VERSION 5.8 ;
BUSBITCHARS "[]" ;
DIVIDERCHAR "/" ;
UNITS
    DATABASE MICRONS 1000 ;
END UNITS

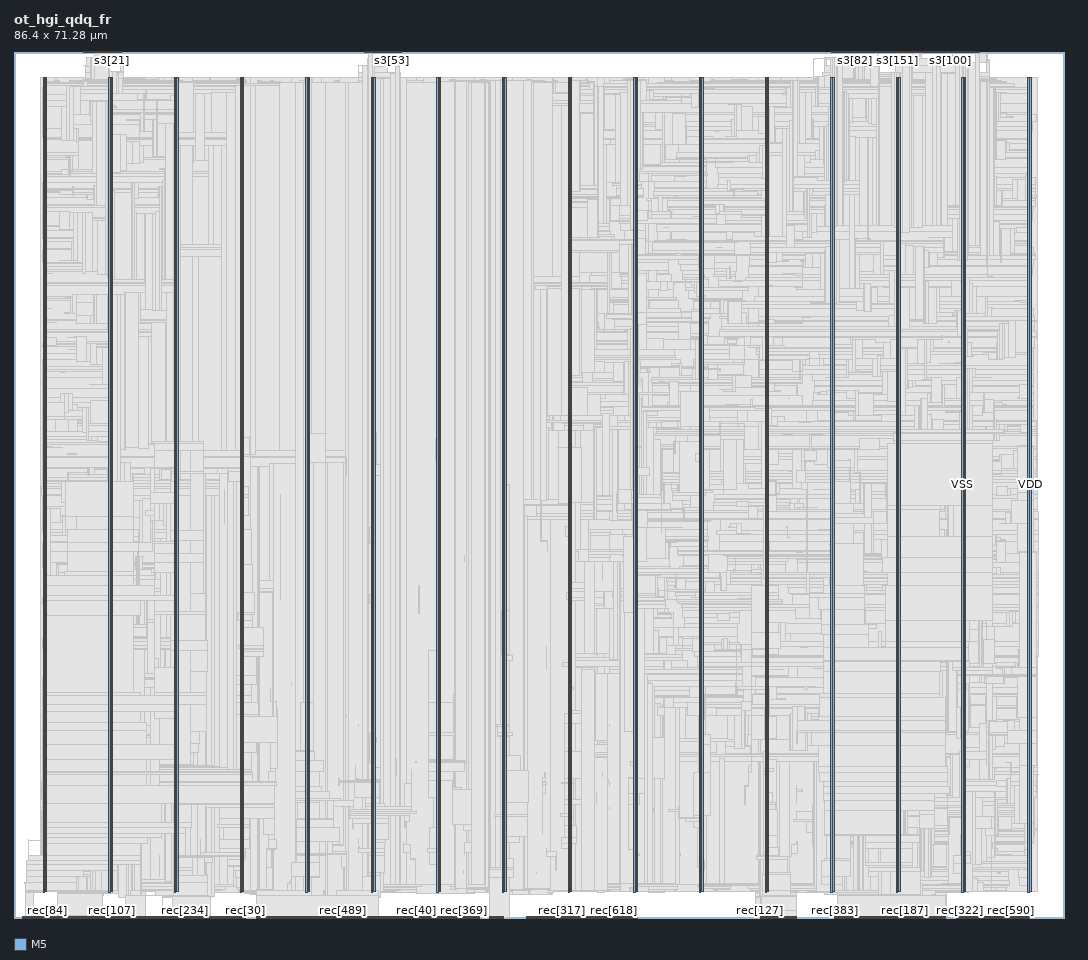
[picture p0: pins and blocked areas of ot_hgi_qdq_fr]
MACRO ot_hgi_qdq_fr
  FOREIGN ot_hgi_qdq_fr 0 0 ;
  CLASS BLOCK ;
  SIZE 86.4 BY 71.28 ;
  PIN clk
    DIRECTION INPUT ;
    USE SIGNAL ;
    PORT
      LAYER M5 ;
        RECT  16.08 0 16.104 0.084 ;
    END
  END clk
  PIN nfault
    DIRECTION OUTPUT ;
    USE SIGNAL ;
    PORT
      LAYER M5 ;
        RECT  5.808 71.196 5.832 71.28 ;
    END
  END nfault
  PIN rec[0]
    DIRECTION INPUT ;
    USE SIGNAL ;
    PORT
      LAYER M5 ;
        RECT  16.176 0 16.2 0.084 ;
    END
  END rec[0]
  PIN rec[100]
    DIRECTION INPUT ;
    USE SIGNAL ;
    PORT
      LAYER M5 ;
        RECT  7.344 0 7.368 0.084 ;
    END
  END rec[100]
  PIN rec[101]
    DIRECTION INPUT ;
    USE SIGNAL ;
    PORT
      LAYER M5 ;
        RECT  7.44 0 7.464 0.084 ;
    END
  END rec[101]
  PIN rec[102]
    DIRECTION INPUT ;
    USE SIGNAL ;
    PORT
      LAYER M5 ;
        RECT  7.536 0 7.56 0.084 ;
    END
  END rec[102]
  PIN rec[103]
    DIRECTION INPUT ;
    USE SIGNAL ;
    PORT
      LAYER M5 ;
        RECT  7.632 0 7.656 0.084 ;
    END
  END rec[103]
  PIN rec[104]
    DIRECTION INPUT ;
    USE SIGNAL ;
    PORT
      LAYER M5 ;
        RECT  7.728 0 7.752 0.084 ;
    END
  END rec[104]
  PIN rec[105]
    DIRECTION INPUT ;
    USE SIGNAL ;
    PORT
      LAYER M5 ;
        RECT  7.824 0 7.848 0.084 ;
    END
  END rec[105]
  PIN rec[106]
    DIRECTION INPUT ;
    USE SIGNAL ;
    PORT
      LAYER M5 ;
        RECT  7.92 0 7.944 0.084 ;
    END
  END rec[106]
  PIN rec[107]
    DIRECTION INPUT ;
    USE SIGNAL ;
    PORT
      LAYER M5 ;
        RECT  8.016 0 8.04 0.084 ;
    END
  END rec[107]
  PIN rec[108]
    DIRECTION INPUT ;
    USE SIGNAL ;
    PORT
      LAYER M5 ;
        RECT  8.112 0 8.136 0.084 ;
    END
  END rec[108]
  PIN rec[109]
    DIRECTION INPUT ;
    USE SIGNAL ;
    PORT
      LAYER M5 ;
        RECT  8.208 0 8.232 0.084 ;
    END
  END rec[109]
  PIN rec[10]
    DIRECTION INPUT ;
    USE SIGNAL ;
    PORT
      LAYER M5 ;
        RECT  17.136 0 17.16 0.084 ;
    END
  END rec[10]
  PIN rec[110]
    DIRECTION INPUT ;
    USE SIGNAL ;
    PORT
      LAYER M5 ;
        RECT  8.304 0 8.328 0.084 ;
    END
  END rec[110]
  PIN rec[111]
    DIRECTION INPUT ;
    USE SIGNAL ;
    PORT
      LAYER M5 ;
        RECT  8.4 0 8.424 0.084 ;
    END
  END rec[111]
  PIN rec[112]
    DIRECTION INPUT ;
    USE SIGNAL ;
    PORT
      LAYER M5 ;
        RECT  8.496 0 8.52 0.084 ;
    END
  END rec[112]
  PIN rec[113]
    DIRECTION INPUT ;
    USE SIGNAL ;
    PORT
      LAYER M5 ;
        RECT  8.592 0 8.616 0.084 ;
    END
  END rec[113]
  PIN rec[114]
    DIRECTION INPUT ;
    USE SIGNAL ;
    PORT
      LAYER M5 ;
        RECT  8.688 0 8.712 0.084 ;
    END
  END rec[114]
  PIN rec[115]
    DIRECTION INPUT ;
    USE SIGNAL ;
    PORT
      LAYER M5 ;
        RECT  8.784 0 8.808 0.084 ;
    END
  END rec[115]
  PIN rec[116]
    DIRECTION INPUT ;
    USE SIGNAL ;
    PORT
      LAYER M5 ;
        RECT  8.88 0 8.904 0.084 ;
    END
  END rec[116]
  PIN rec[117]
    DIRECTION INPUT ;
    USE SIGNAL ;
    PORT
      LAYER M5 ;
        RECT  8.976 0 9 0.084 ;
    END
  END rec[117]
  PIN rec[118]
    DIRECTION INPUT ;
    USE SIGNAL ;
    PORT
      LAYER M5 ;
        RECT  9.072 0 9.096 0.084 ;
    END
  END rec[118]
  PIN rec[119]
    DIRECTION INPUT ;
    USE SIGNAL ;
    PORT
      LAYER M5 ;
        RECT  9.168 0 9.192 0.084 ;
    END
  END rec[119]
  PIN rec[11]
    DIRECTION INPUT ;
    USE SIGNAL ;
    PORT
      LAYER M5 ;
        RECT  17.232 0 17.256 0.084 ;
    END
  END rec[11]
  PIN rec[120]
    DIRECTION INPUT ;
    USE SIGNAL ;
    PORT
      LAYER M5 ;
        RECT  9.264 0 9.288 0.084 ;
    END
  END rec[120]
  PIN rec[121]
    DIRECTION INPUT ;
    USE SIGNAL ;
    PORT
      LAYER M5 ;
        RECT  9.36 0 9.384 0.084 ;
    END
  END rec[121]
  PIN rec[122]
    DIRECTION INPUT ;
    USE SIGNAL ;
    PORT
      LAYER M5 ;
        RECT  9.456 0 9.48 0.084 ;
    END
  END rec[122]
  PIN rec[123]
    DIRECTION INPUT ;
    USE SIGNAL ;
    PORT
      LAYER M5 ;
        RECT  9.552 0 9.576 0.084 ;
    END
  END rec[123]
  PIN rec[124]
    DIRECTION INPUT ;
    USE SIGNAL ;
    PORT
      LAYER M5 ;
        RECT  9.648 0 9.672 0.084 ;
    END
  END rec[124]
  PIN rec[125]
    DIRECTION INPUT ;
    USE SIGNAL ;
    PORT
      LAYER M5 ;
        RECT  9.744 0 9.768 0.084 ;
    END
  END rec[125]
  PIN rec[126]
    DIRECTION INPUT ;
    USE SIGNAL ;
    PORT
      LAYER M5 ;
        RECT  9.84 0 9.864 0.084 ;
    END
  END rec[126]
  PIN rec[127]
    DIRECTION INPUT ;
    USE SIGNAL ;
    PORT
      LAYER M5 ;
        RECT  61.392 0 61.416 0.084 ;
    END
  END rec[127]
  PIN rec[128]
    DIRECTION INPUT ;
    USE SIGNAL ;
    PORT
      LAYER M5 ;
        RECT  61.488 0 61.512 0.084 ;
    END
  END rec[128]
  PIN rec[129]
    DIRECTION INPUT ;
    USE SIGNAL ;
    PORT
      LAYER M5 ;
        RECT  61.584 0 61.608 0.084 ;
    END
  END rec[129]
  PIN rec[12]
    DIRECTION INPUT ;
    USE SIGNAL ;
    PORT
      LAYER M5 ;
        RECT  17.328 0 17.352 0.084 ;
    END
  END rec[12]
  PIN rec[130]
    DIRECTION INPUT ;
    USE SIGNAL ;
    PORT
      LAYER M5 ;
        RECT  61.68 0 61.704 0.084 ;
    END
  END rec[130]
  PIN rec[131]
    DIRECTION INPUT ;
    USE SIGNAL ;
    PORT
      LAYER M5 ;
        RECT  61.776 0 61.8 0.084 ;
    END
  END rec[131]
  PIN rec[132]
    DIRECTION INPUT ;
    USE SIGNAL ;
    PORT
      LAYER M5 ;
        RECT  61.872 0 61.896 0.084 ;
    END
  END rec[132]
  PIN rec[133]
    DIRECTION INPUT ;
    USE SIGNAL ;
    PORT
      LAYER M5 ;
        RECT  61.968 0 61.992 0.084 ;
    END
  END rec[133]
  PIN rec[134]
    DIRECTION INPUT ;
    USE SIGNAL ;
    PORT
      LAYER M5 ;
        RECT  62.064 0 62.088 0.084 ;
    END
  END rec[134]
  PIN rec[135]
    DIRECTION INPUT ;
    USE SIGNAL ;
    PORT
      LAYER M5 ;
        RECT  62.16 0 62.184 0.084 ;
    END
  END rec[135]
  PIN rec[136]
    DIRECTION INPUT ;
    USE SIGNAL ;
    PORT
      LAYER M5 ;
        RECT  62.256 0 62.28 0.084 ;
    END
  END rec[136]
  PIN rec[137]
    DIRECTION INPUT ;
    USE SIGNAL ;
    PORT
      LAYER M5 ;
        RECT  62.352 0 62.376 0.084 ;
    END
  END rec[137]
  PIN rec[138]
    DIRECTION INPUT ;
    USE SIGNAL ;
    PORT
      LAYER M5 ;
        RECT  62.448 0 62.472 0.084 ;
    END
  END rec[138]
  PIN rec[139]
    DIRECTION INPUT ;
    USE SIGNAL ;
    PORT
      LAYER M5 ;
        RECT  62.544 0 62.568 0.084 ;
    END
  END rec[139]
  PIN rec[13]
    DIRECTION INPUT ;
    USE SIGNAL ;
    PORT
      LAYER M5 ;
        RECT  17.424 0 17.448 0.084 ;
    END
  END rec[13]
  PIN rec[140]
    DIRECTION INPUT ;
    USE SIGNAL ;
    PORT
      LAYER M5 ;
        RECT  62.64 0 62.664 0.084 ;
    END
  END rec[140]
  PIN rec[141]
    DIRECTION INPUT ;
    USE SIGNAL ;
    PORT
      LAYER M5 ;
        RECT  62.736 0 62.76 0.084 ;
    END
  END rec[141]
  PIN rec[142]
    DIRECTION INPUT ;
    USE SIGNAL ;
    PORT
      LAYER M5 ;
        RECT  62.832 0 62.856 0.084 ;
    END
  END rec[142]
  PIN rec[143]
    DIRECTION INPUT ;
    USE SIGNAL ;
    PORT
      LAYER M5 ;
        RECT  62.928 0 62.952 0.084 ;
    END
  END rec[143]
  PIN rec[144]
    DIRECTION INPUT ;
    USE SIGNAL ;
    PORT
      LAYER M5 ;
        RECT  63.024 0 63.048 0.084 ;
    END
  END rec[144]
  PIN rec[145]
    DIRECTION INPUT ;
    USE SIGNAL ;
    PORT
      LAYER M5 ;
        RECT  63.12 0 63.144 0.084 ;
    END
  END rec[145]
  PIN rec[146]
    DIRECTION INPUT ;
    USE SIGNAL ;
    PORT
      LAYER M5 ;
        RECT  63.216 0 63.24 0.084 ;
    END
  END rec[146]
  PIN rec[147]
    DIRECTION INPUT ;
    USE SIGNAL ;
    PORT
      LAYER M5 ;
        RECT  63.312 0 63.336 0.084 ;
    END
  END rec[147]
  PIN rec[148]
    DIRECTION INPUT ;
    USE SIGNAL ;
    PORT
      LAYER M5 ;
        RECT  63.408 0 63.432 0.084 ;
    END
  END rec[148]
  PIN rec[149]
    DIRECTION INPUT ;
    USE SIGNAL ;
    PORT
      LAYER M5 ;
        RECT  63.504 0 63.528 0.084 ;
    END
  END rec[149]
  PIN rec[14]
    DIRECTION INPUT ;
    USE SIGNAL ;
    PORT
      LAYER M5 ;
        RECT  17.52 0 17.544 0.084 ;
    END
  END rec[14]
  PIN rec[150]
    DIRECTION INPUT ;
    USE SIGNAL ;
    PORT
      LAYER M5 ;
        RECT  63.6 0 63.624 0.084 ;
    END
  END rec[150]
  PIN rec[151]
    DIRECTION INPUT ;
    USE SIGNAL ;
    PORT
      LAYER M5 ;
        RECT  63.696 0 63.72 0.084 ;
    END
  END rec[151]
  PIN rec[152]
    DIRECTION INPUT ;
    USE SIGNAL ;
    PORT
      LAYER M5 ;
        RECT  63.792 0 63.816 0.084 ;
    END
  END rec[152]
  PIN rec[153]
    DIRECTION INPUT ;
    USE SIGNAL ;
    PORT
      LAYER M5 ;
        RECT  63.888 0 63.912 0.084 ;
    END
  END rec[153]
  PIN rec[154]
    DIRECTION INPUT ;
    USE SIGNAL ;
    PORT
      LAYER M5 ;
        RECT  63.984 0 64.008 0.084 ;
    END
  END rec[154]
  PIN rec[155]
    DIRECTION INPUT ;
    USE SIGNAL ;
    PORT
      LAYER M5 ;
        RECT  64.08 0 64.104 0.084 ;
    END
  END rec[155]
  PIN rec[156]
    DIRECTION INPUT ;
    USE SIGNAL ;
    PORT
      LAYER M5 ;
        RECT  64.176 0 64.2 0.084 ;
    END
  END rec[156]
  PIN rec[157]
    DIRECTION INPUT ;
    USE SIGNAL ;
    PORT
      LAYER M5 ;
        RECT  64.272 0 64.296 0.084 ;
    END
  END rec[157]
  PIN rec[158]
    DIRECTION INPUT ;
    USE SIGNAL ;
    PORT
      LAYER M5 ;
        RECT  64.368 0 64.392 0.084 ;
    END
  END rec[158]
  PIN rec[159]
    DIRECTION INPUT ;
    USE SIGNAL ;
    PORT
      LAYER M5 ;
        RECT  70.608 0 70.632 0.084 ;
    END
  END rec[159]
  PIN rec[15]
    DIRECTION INPUT ;
    USE SIGNAL ;
    PORT
      LAYER M5 ;
        RECT  17.616 0 17.64 0.084 ;
    END
  END rec[15]
  PIN rec[160]
    DIRECTION INPUT ;
    USE SIGNAL ;
    PORT
      LAYER M5 ;
        RECT  70.704 0 70.728 0.084 ;
    END
  END rec[160]
  PIN rec[161]
    DIRECTION INPUT ;
    USE SIGNAL ;
    PORT
      LAYER M5 ;
        RECT  70.8 0 70.824 0.084 ;
    END
  END rec[161]
  PIN rec[162]
    DIRECTION INPUT ;
    USE SIGNAL ;
    PORT
      LAYER M5 ;
        RECT  70.896 0 70.92 0.084 ;
    END
  END rec[162]
  PIN rec[163]
    DIRECTION INPUT ;
    USE SIGNAL ;
    PORT
      LAYER M5 ;
        RECT  70.992 0 71.016 0.084 ;
    END
  END rec[163]
  PIN rec[164]
    DIRECTION INPUT ;
    USE SIGNAL ;
    PORT
      LAYER M5 ;
        RECT  71.088 0 71.112 0.084 ;
    END
  END rec[164]
  PIN rec[165]
    DIRECTION INPUT ;
    USE SIGNAL ;
    PORT
      LAYER M5 ;
        RECT  71.184 0 71.208 0.084 ;
    END
  END rec[165]
  PIN rec[166]
    DIRECTION INPUT ;
    USE SIGNAL ;
    PORT
      LAYER M5 ;
        RECT  71.28 0 71.304 0.084 ;
    END
  END rec[166]
  PIN rec[167]
    DIRECTION INPUT ;
    USE SIGNAL ;
    PORT
      LAYER M5 ;
        RECT  71.376 0 71.4 0.084 ;
    END
  END rec[167]
  PIN rec[168]
    DIRECTION INPUT ;
    USE SIGNAL ;
    PORT
      LAYER M5 ;
        RECT  71.472 0 71.496 0.084 ;
    END
  END rec[168]
  PIN rec[169]
    DIRECTION INPUT ;
    USE SIGNAL ;
    PORT
      LAYER M5 ;
        RECT  71.568 0 71.592 0.084 ;
    END
  END rec[169]
  PIN rec[16]
    DIRECTION INPUT ;
    USE SIGNAL ;
    PORT
      LAYER M5 ;
        RECT  17.712 0 17.736 0.084 ;
    END
  END rec[16]
  PIN rec[170]
    DIRECTION INPUT ;
    USE SIGNAL ;
    PORT
      LAYER M5 ;
        RECT  71.664 0 71.688 0.084 ;
    END
  END rec[170]
  PIN rec[171]
    DIRECTION INPUT ;
    USE SIGNAL ;
    PORT
      LAYER M5 ;
        RECT  71.76 0 71.784 0.084 ;
    END
  END rec[171]
  PIN rec[172]
    DIRECTION INPUT ;
    USE SIGNAL ;
    PORT
      LAYER M5 ;
        RECT  71.856 0 71.88 0.084 ;
    END
  END rec[172]
  PIN rec[173]
    DIRECTION INPUT ;
    USE SIGNAL ;
    PORT
      LAYER M5 ;
        RECT  71.952 0 71.976 0.084 ;
    END
  END rec[173]
  PIN rec[174]
    DIRECTION INPUT ;
    USE SIGNAL ;
    PORT
      LAYER M5 ;
        RECT  72.048 0 72.072 0.084 ;
    END
  END rec[174]
  PIN rec[175]
    DIRECTION INPUT ;
    USE SIGNAL ;
    PORT
      LAYER M5 ;
        RECT  72.144 0 72.168 0.084 ;
    END
  END rec[175]
  PIN rec[176]
    DIRECTION INPUT ;
    USE SIGNAL ;
    PORT
      LAYER M5 ;
        RECT  72.24 0 72.264 0.084 ;
    END
  END rec[176]
  PIN rec[177]
    DIRECTION INPUT ;
    USE SIGNAL ;
    PORT
      LAYER M5 ;
        RECT  72.336 0 72.36 0.084 ;
    END
  END rec[177]
  PIN rec[178]
    DIRECTION INPUT ;
    USE SIGNAL ;
    PORT
      LAYER M5 ;
        RECT  72.432 0 72.456 0.084 ;
    END
  END rec[178]
  PIN rec[179]
    DIRECTION INPUT ;
    USE SIGNAL ;
    PORT
      LAYER M5 ;
        RECT  72.528 0 72.552 0.084 ;
    END
  END rec[179]
  PIN rec[17]
    DIRECTION INPUT ;
    USE SIGNAL ;
    PORT
      LAYER M5 ;
        RECT  17.808 0 17.832 0.084 ;
    END
  END rec[17]
  PIN rec[180]
    DIRECTION INPUT ;
    USE SIGNAL ;
    PORT
      LAYER M5 ;
        RECT  72.624 0 72.648 0.084 ;
    END
  END rec[180]
  PIN rec[181]
    DIRECTION INPUT ;
    USE SIGNAL ;
    PORT
      LAYER M5 ;
        RECT  72.72 0 72.744 0.084 ;
    END
  END rec[181]
  PIN rec[182]
    DIRECTION INPUT ;
    USE SIGNAL ;
    PORT
      LAYER M5 ;
        RECT  72.816 0 72.84 0.084 ;
    END
  END rec[182]
  PIN rec[183]
    DIRECTION INPUT ;
    USE SIGNAL ;
    PORT
      LAYER M5 ;
        RECT  72.912 0 72.936 0.084 ;
    END
  END rec[183]
  PIN rec[184]
    DIRECTION INPUT ;
    USE SIGNAL ;
    PORT
      LAYER M5 ;
        RECT  73.008 0 73.032 0.084 ;
    END
  END rec[184]
  PIN rec[185]
    DIRECTION INPUT ;
    USE SIGNAL ;
    PORT
      LAYER M5 ;
        RECT  73.104 0 73.128 0.084 ;
    END
  END rec[185]
  PIN rec[186]
    DIRECTION INPUT ;
    USE SIGNAL ;
    PORT
      LAYER M5 ;
        RECT  73.2 0 73.224 0.084 ;
    END
  END rec[186]
  PIN rec[187]
    DIRECTION INPUT ;
    USE SIGNAL ;
    PORT
      LAYER M5 ;
        RECT  73.296 0 73.32 0.084 ;
    END
  END rec[187]
  PIN rec[188]
    DIRECTION INPUT ;
    USE SIGNAL ;
    PORT
      LAYER M5 ;
        RECT  73.392 0 73.416 0.084 ;
    END
  END rec[188]
  PIN rec[189]
    DIRECTION INPUT ;
    USE SIGNAL ;
    PORT
      LAYER M5 ;
        RECT  73.488 0 73.512 0.084 ;
    END
  END rec[189]
  PIN rec[18]
    DIRECTION INPUT ;
    USE SIGNAL ;
    PORT
      LAYER M5 ;
        RECT  17.904 0 17.928 0.084 ;
    END
  END rec[18]
  PIN rec[190]
    DIRECTION INPUT ;
    USE SIGNAL ;
    PORT
      LAYER M5 ;
        RECT  73.584 0 73.608 0.084 ;
    END
  END rec[190]
  PIN rec[191]
    DIRECTION INPUT ;
    USE SIGNAL ;
    PORT
      LAYER M5 ;
        RECT  3.792 0 3.816 0.084 ;
    END
  END rec[191]
  PIN rec[192]
    DIRECTION INPUT ;
    USE SIGNAL ;
    PORT
      LAYER M5 ;
        RECT  3.888 0 3.912 0.084 ;
    END
  END rec[192]
  PIN rec[193]
    DIRECTION INPUT ;
    USE SIGNAL ;
    PORT
      LAYER M5 ;
        RECT  3.984 0 4.008 0.084 ;
    END
  END rec[193]
  PIN rec[194]
    DIRECTION INPUT ;
    USE SIGNAL ;
    PORT
      LAYER M5 ;
        RECT  4.08 0 4.104 0.084 ;
    END
  END rec[194]
  PIN rec[195]
    DIRECTION INPUT ;
    USE SIGNAL ;
    PORT
      LAYER M5 ;
        RECT  4.176 0 4.2 0.084 ;
    END
  END rec[195]
  PIN rec[196]
    DIRECTION INPUT ;
    USE SIGNAL ;
    PORT
      LAYER M5 ;
        RECT  4.272 0 4.296 0.084 ;
    END
  END rec[196]
  PIN rec[197]
    DIRECTION INPUT ;
    USE SIGNAL ;
    PORT
      LAYER M5 ;
        RECT  4.368 0 4.392 0.084 ;
    END
  END rec[197]
  PIN rec[198]
    DIRECTION INPUT ;
    USE SIGNAL ;
    PORT
      LAYER M5 ;
        RECT  4.464 0 4.488 0.084 ;
    END
  END rec[198]
  PIN rec[199]
    DIRECTION INPUT ;
    USE SIGNAL ;
    PORT
      LAYER M5 ;
        RECT  4.56 0 4.584 0.084 ;
    END
  END rec[199]
  PIN rec[19]
    DIRECTION INPUT ;
    USE SIGNAL ;
    PORT
      LAYER M5 ;
        RECT  18 0 18.024 0.084 ;
    END
  END rec[19]
  PIN rec[1]
    DIRECTION INPUT ;
    USE SIGNAL ;
    PORT
      LAYER M5 ;
        RECT  16.272 0 16.296 0.084 ;
    END
  END rec[1]
  PIN rec[200]
    DIRECTION INPUT ;
    USE SIGNAL ;
    PORT
      LAYER M5 ;
        RECT  4.656 0 4.68 0.084 ;
    END
  END rec[200]
  PIN rec[201]
    DIRECTION INPUT ;
    USE SIGNAL ;
    PORT
      LAYER M5 ;
        RECT  4.752 0 4.776 0.084 ;
    END
  END rec[201]
  PIN rec[202]
    DIRECTION INPUT ;
    USE SIGNAL ;
    PORT
      LAYER M5 ;
        RECT  4.848 0 4.872 0.084 ;
    END
  END rec[202]
  PIN rec[203]
    DIRECTION INPUT ;
    USE SIGNAL ;
    PORT
      LAYER M5 ;
        RECT  4.944 0 4.968 0.084 ;
    END
  END rec[203]
  PIN rec[204]
    DIRECTION INPUT ;
    USE SIGNAL ;
    PORT
      LAYER M5 ;
        RECT  5.04 0 5.064 0.084 ;
    END
  END rec[204]
  PIN rec[205]
    DIRECTION INPUT ;
    USE SIGNAL ;
    PORT
      LAYER M5 ;
        RECT  5.136 0 5.16 0.084 ;
    END
  END rec[205]
  PIN rec[206]
    DIRECTION INPUT ;
    USE SIGNAL ;
    PORT
      LAYER M5 ;
        RECT  5.232 0 5.256 0.084 ;
    END
  END rec[206]
  PIN rec[207]
    DIRECTION INPUT ;
    USE SIGNAL ;
    PORT
      LAYER M5 ;
        RECT  5.328 0 5.352 0.084 ;
    END
  END rec[207]
  PIN rec[208]
    DIRECTION INPUT ;
    USE SIGNAL ;
    PORT
      LAYER M5 ;
        RECT  5.424 0 5.448 0.084 ;
    END
  END rec[208]
  PIN rec[209]
    DIRECTION INPUT ;
    USE SIGNAL ;
    PORT
      LAYER M5 ;
        RECT  5.52 0 5.544 0.084 ;
    END
  END rec[209]
  PIN rec[20]
    DIRECTION INPUT ;
    USE SIGNAL ;
    PORT
      LAYER M5 ;
        RECT  18.096 0 18.12 0.084 ;
    END
  END rec[20]
  PIN rec[210]
    DIRECTION INPUT ;
    USE SIGNAL ;
    PORT
      LAYER M5 ;
        RECT  5.616 0 5.64 0.084 ;
    END
  END rec[210]
  PIN rec[211]
    DIRECTION INPUT ;
    USE SIGNAL ;
    PORT
      LAYER M5 ;
        RECT  5.712 0 5.736 0.084 ;
    END
  END rec[211]
  PIN rec[212]
    DIRECTION INPUT ;
    USE SIGNAL ;
    PORT
      LAYER M5 ;
        RECT  5.808 0 5.832 0.084 ;
    END
  END rec[212]
  PIN rec[213]
    DIRECTION INPUT ;
    USE SIGNAL ;
    PORT
      LAYER M5 ;
        RECT  5.904 0 5.928 0.084 ;
    END
  END rec[213]
  PIN rec[214]
    DIRECTION INPUT ;
    USE SIGNAL ;
    PORT
      LAYER M5 ;
        RECT  6 0 6.024 0.084 ;
    END
  END rec[214]
  PIN rec[215]
    DIRECTION INPUT ;
    USE SIGNAL ;
    PORT
      LAYER M5 ;
        RECT  6.096 0 6.12 0.084 ;
    END
  END rec[215]
  PIN rec[216]
    DIRECTION INPUT ;
    USE SIGNAL ;
    PORT
      LAYER M5 ;
        RECT  6.192 0 6.216 0.084 ;
    END
  END rec[216]
  PIN rec[217]
    DIRECTION INPUT ;
    USE SIGNAL ;
    PORT
      LAYER M5 ;
        RECT  6.288 0 6.312 0.084 ;
    END
  END rec[217]
  PIN rec[218]
    DIRECTION INPUT ;
    USE SIGNAL ;
    PORT
      LAYER M5 ;
        RECT  6.384 0 6.408 0.084 ;
    END
  END rec[218]
  PIN rec[219]
    DIRECTION INPUT ;
    USE SIGNAL ;
    PORT
      LAYER M5 ;
        RECT  6.48 0 6.504 0.084 ;
    END
  END rec[219]
  PIN rec[21]
    DIRECTION INPUT ;
    USE SIGNAL ;
    PORT
      LAYER M5 ;
        RECT  18.192 0 18.216 0.084 ;
    END
  END rec[21]
  PIN rec[220]
    DIRECTION INPUT ;
    USE SIGNAL ;
    PORT
      LAYER M5 ;
        RECT  6.576 0 6.6 0.084 ;
    END
  END rec[220]
  PIN rec[221]
    DIRECTION INPUT ;
    USE SIGNAL ;
    PORT
      LAYER M5 ;
        RECT  6.672 0 6.696 0.084 ;
    END
  END rec[221]
  PIN rec[222]
    DIRECTION INPUT ;
    USE SIGNAL ;
    PORT
      LAYER M5 ;
        RECT  6.768 0 6.792 0.084 ;
    END
  END rec[222]
  PIN rec[223]
    DIRECTION INPUT ;
    USE SIGNAL ;
    PORT
      LAYER M5 ;
        RECT  13.008 0 13.032 0.084 ;
    END
  END rec[223]
  PIN rec[224]
    DIRECTION INPUT ;
    USE SIGNAL ;
    PORT
      LAYER M5 ;
        RECT  13.104 0 13.128 0.084 ;
    END
  END rec[224]
  PIN rec[225]
    DIRECTION INPUT ;
    USE SIGNAL ;
    PORT
      LAYER M5 ;
        RECT  13.2 0 13.224 0.084 ;
    END
  END rec[225]
  PIN rec[226]
    DIRECTION INPUT ;
    USE SIGNAL ;
    PORT
      LAYER M5 ;
        RECT  13.296 0 13.32 0.084 ;
    END
  END rec[226]
  PIN rec[227]
    DIRECTION INPUT ;
    USE SIGNAL ;
    PORT
      LAYER M5 ;
        RECT  13.392 0 13.416 0.084 ;
    END
  END rec[227]
  PIN rec[228]
    DIRECTION INPUT ;
    USE SIGNAL ;
    PORT
      LAYER M5 ;
        RECT  13.488 0 13.512 0.084 ;
    END
  END rec[228]
  PIN rec[229]
    DIRECTION INPUT ;
    USE SIGNAL ;
    PORT
      LAYER M5 ;
        RECT  13.584 0 13.608 0.084 ;
    END
  END rec[229]
  PIN rec[22]
    DIRECTION INPUT ;
    USE SIGNAL ;
    PORT
      LAYER M5 ;
        RECT  18.288 0 18.312 0.084 ;
    END
  END rec[22]
  PIN rec[230]
    DIRECTION INPUT ;
    USE SIGNAL ;
    PORT
      LAYER M5 ;
        RECT  13.68 0 13.704 0.084 ;
    END
  END rec[230]
  PIN rec[231]
    DIRECTION INPUT ;
    USE SIGNAL ;
    PORT
      LAYER M5 ;
        RECT  13.776 0 13.8 0.084 ;
    END
  END rec[231]
  PIN rec[232]
    DIRECTION INPUT ;
    USE SIGNAL ;
    PORT
      LAYER M5 ;
        RECT  13.872 0 13.896 0.084 ;
    END
  END rec[232]
  PIN rec[233]
    DIRECTION INPUT ;
    USE SIGNAL ;
    PORT
      LAYER M5 ;
        RECT  13.968 0 13.992 0.084 ;
    END
  END rec[233]
  PIN rec[234]
    DIRECTION INPUT ;
    USE SIGNAL ;
    PORT
      LAYER M5 ;
        RECT  14.064 0 14.088 0.084 ;
    END
  END rec[234]
  PIN rec[235]
    DIRECTION INPUT ;
    USE SIGNAL ;
    PORT
      LAYER M5 ;
        RECT  14.16 0 14.184 0.084 ;
    END
  END rec[235]
  PIN rec[236]
    DIRECTION INPUT ;
    USE SIGNAL ;
    PORT
      LAYER M5 ;
        RECT  14.256 0 14.28 0.084 ;
    END
  END rec[236]
  PIN rec[237]
    DIRECTION INPUT ;
    USE SIGNAL ;
    PORT
      LAYER M5 ;
        RECT  14.352 0 14.376 0.084 ;
    END
  END rec[237]
  PIN rec[238]
    DIRECTION INPUT ;
    USE SIGNAL ;
    PORT
      LAYER M5 ;
        RECT  14.448 0 14.472 0.084 ;
    END
  END rec[238]
  PIN rec[239]
    DIRECTION INPUT ;
    USE SIGNAL ;
    PORT
      LAYER M5 ;
        RECT  14.544 0 14.568 0.084 ;
    END
  END rec[239]
  PIN rec[23]
    DIRECTION INPUT ;
    USE SIGNAL ;
    PORT
      LAYER M5 ;
        RECT  18.384 0 18.408 0.084 ;
    END
  END rec[23]
  PIN rec[240]
    DIRECTION INPUT ;
    USE SIGNAL ;
    PORT
      LAYER M5 ;
        RECT  14.64 0 14.664 0.084 ;
    END
  END rec[240]
  PIN rec[241]
    DIRECTION INPUT ;
    USE SIGNAL ;
    PORT
      LAYER M5 ;
        RECT  14.736 0 14.76 0.084 ;
    END
  END rec[241]
  PIN rec[242]
    DIRECTION INPUT ;
    USE SIGNAL ;
    PORT
      LAYER M5 ;
        RECT  14.832 0 14.856 0.084 ;
    END
  END rec[242]
  PIN rec[243]
    DIRECTION INPUT ;
    USE SIGNAL ;
    PORT
      LAYER M5 ;
        RECT  14.928 0 14.952 0.084 ;
    END
  END rec[243]
  PIN rec[244]
    DIRECTION INPUT ;
    USE SIGNAL ;
    PORT
      LAYER M5 ;
        RECT  15.024 0 15.048 0.084 ;
    END
  END rec[244]
  PIN rec[245]
    DIRECTION INPUT ;
    USE SIGNAL ;
    PORT
      LAYER M5 ;
        RECT  15.12 0 15.144 0.084 ;
    END
  END rec[245]
  PIN rec[246]
    DIRECTION INPUT ;
    USE SIGNAL ;
    PORT
      LAYER M5 ;
        RECT  15.216 0 15.24 0.084 ;
    END
  END rec[246]
  PIN rec[247]
    DIRECTION INPUT ;
    USE SIGNAL ;
    PORT
      LAYER M5 ;
        RECT  15.312 0 15.336 0.084 ;
    END
  END rec[247]
  PIN rec[248]
    DIRECTION INPUT ;
    USE SIGNAL ;
    PORT
      LAYER M5 ;
        RECT  15.408 0 15.432 0.084 ;
    END
  END rec[248]
  PIN rec[249]
    DIRECTION INPUT ;
    USE SIGNAL ;
    PORT
      LAYER M5 ;
        RECT  15.504 0 15.528 0.084 ;
    END
  END rec[249]
  PIN rec[24]
    DIRECTION INPUT ;
    USE SIGNAL ;
    PORT
      LAYER M5 ;
        RECT  18.48 0 18.504 0.084 ;
    END
  END rec[24]
  PIN rec[250]
    DIRECTION INPUT ;
    USE SIGNAL ;
    PORT
      LAYER M5 ;
        RECT  15.6 0 15.624 0.084 ;
    END
  END rec[250]
  PIN rec[251]
    DIRECTION INPUT ;
    USE SIGNAL ;
    PORT
      LAYER M5 ;
        RECT  15.696 0 15.72 0.084 ;
    END
  END rec[251]
  PIN rec[252]
    DIRECTION INPUT ;
    USE SIGNAL ;
    PORT
      LAYER M5 ;
        RECT  15.792 0 15.816 0.084 ;
    END
  END rec[252]
  PIN rec[253]
    DIRECTION INPUT ;
    USE SIGNAL ;
    PORT
      LAYER M5 ;
        RECT  15.888 0 15.912 0.084 ;
    END
  END rec[253]
  PIN rec[254]
    DIRECTION INPUT ;
    USE SIGNAL ;
    PORT
      LAYER M5 ;
        RECT  15.984 0 16.008 0.084 ;
    END
  END rec[254]
  PIN rec[255]
    DIRECTION INPUT ;
    USE SIGNAL ;
    PORT
      LAYER M5 ;
        RECT  9.936 0 9.96 0.084 ;
    END
  END rec[255]
  PIN rec[256]
    DIRECTION INPUT ;
    USE SIGNAL ;
    PORT
      LAYER M5 ;
        RECT  10.032 0 10.056 0.084 ;
    END
  END rec[256]
  PIN rec[257]
    DIRECTION INPUT ;
    USE SIGNAL ;
    PORT
      LAYER M5 ;
        RECT  10.128 0 10.152 0.084 ;
    END
  END rec[257]
  PIN rec[258]
    DIRECTION INPUT ;
    USE SIGNAL ;
    PORT
      LAYER M5 ;
        RECT  10.224 0 10.248 0.084 ;
    END
  END rec[258]
  PIN rec[259]
    DIRECTION INPUT ;
    USE SIGNAL ;
    PORT
      LAYER M5 ;
        RECT  10.32 0 10.344 0.084 ;
    END
  END rec[259]
  PIN rec[25]
    DIRECTION INPUT ;
    USE SIGNAL ;
    PORT
      LAYER M5 ;
        RECT  18.576 0 18.6 0.084 ;
    END
  END rec[25]
  PIN rec[260]
    DIRECTION INPUT ;
    USE SIGNAL ;
    PORT
      LAYER M5 ;
        RECT  10.416 0 10.44 0.084 ;
    END
  END rec[260]
  PIN rec[261]
    DIRECTION INPUT ;
    USE SIGNAL ;
    PORT
      LAYER M5 ;
        RECT  10.512 0 10.536 0.084 ;
    END
  END rec[261]
  PIN rec[262]
    DIRECTION INPUT ;
    USE SIGNAL ;
    PORT
      LAYER M5 ;
        RECT  10.608 0 10.632 0.084 ;
    END
  END rec[262]
  PIN rec[263]
    DIRECTION INPUT ;
    USE SIGNAL ;
    PORT
      LAYER M5 ;
        RECT  10.704 0 10.728 0.084 ;
    END
  END rec[263]
  PIN rec[264]
    DIRECTION INPUT ;
    USE SIGNAL ;
    PORT
      LAYER M5 ;
        RECT  10.8 0 10.824 0.084 ;
    END
  END rec[264]
  PIN rec[265]
    DIRECTION INPUT ;
    USE SIGNAL ;
    PORT
      LAYER M5 ;
        RECT  10.896 0 10.92 0.084 ;
    END
  END rec[265]
  PIN rec[266]
    DIRECTION INPUT ;
    USE SIGNAL ;
    PORT
      LAYER M5 ;
        RECT  10.992 0 11.016 0.084 ;
    END
  END rec[266]
  PIN rec[267]
    DIRECTION INPUT ;
    USE SIGNAL ;
    PORT
      LAYER M5 ;
        RECT  11.088 0 11.112 0.084 ;
    END
  END rec[267]
  PIN rec[268]
    DIRECTION INPUT ;
    USE SIGNAL ;
    PORT
      LAYER M5 ;
        RECT  11.184 0 11.208 0.084 ;
    END
  END rec[268]
  PIN rec[269]
    DIRECTION INPUT ;
    USE SIGNAL ;
    PORT
      LAYER M5 ;
        RECT  11.28 0 11.304 0.084 ;
    END
  END rec[269]
  PIN rec[26]
    DIRECTION INPUT ;
    USE SIGNAL ;
    PORT
      LAYER M5 ;
        RECT  18.672 0 18.696 0.084 ;
    END
  END rec[26]
  PIN rec[270]
    DIRECTION INPUT ;
    USE SIGNAL ;
    PORT
      LAYER M5 ;
        RECT  11.376 0 11.4 0.084 ;
    END
  END rec[270]
  PIN rec[271]
    DIRECTION INPUT ;
    USE SIGNAL ;
    PORT
      LAYER M5 ;
        RECT  11.472 0 11.496 0.084 ;
    END
  END rec[271]
  PIN rec[272]
    DIRECTION INPUT ;
    USE SIGNAL ;
    PORT
      LAYER M5 ;
        RECT  11.568 0 11.592 0.084 ;
    END
  END rec[272]
  PIN rec[273]
    DIRECTION INPUT ;
    USE SIGNAL ;
    PORT
      LAYER M5 ;
        RECT  11.664 0 11.688 0.084 ;
    END
  END rec[273]
  PIN rec[274]
    DIRECTION INPUT ;
    USE SIGNAL ;
    PORT
      LAYER M5 ;
        RECT  11.76 0 11.784 0.084 ;
    END
  END rec[274]
  PIN rec[275]
    DIRECTION INPUT ;
    USE SIGNAL ;
    PORT
      LAYER M5 ;
        RECT  11.856 0 11.88 0.084 ;
    END
  END rec[275]
  PIN rec[276]
    DIRECTION INPUT ;
    USE SIGNAL ;
    PORT
      LAYER M5 ;
        RECT  11.952 0 11.976 0.084 ;
    END
  END rec[276]
  PIN rec[277]
    DIRECTION INPUT ;
    USE SIGNAL ;
    PORT
      LAYER M5 ;
        RECT  12.048 0 12.072 0.084 ;
    END
  END rec[277]
  PIN rec[278]
    DIRECTION INPUT ;
    USE SIGNAL ;
    PORT
      LAYER M5 ;
        RECT  12.144 0 12.168 0.084 ;
    END
  END rec[278]
  PIN rec[279]
    DIRECTION INPUT ;
    USE SIGNAL ;
    PORT
      LAYER M5 ;
        RECT  12.24 0 12.264 0.084 ;
    END
  END rec[279]
  PIN rec[27]
    DIRECTION INPUT ;
    USE SIGNAL ;
    PORT
      LAYER M5 ;
        RECT  18.768 0 18.792 0.084 ;
    END
  END rec[27]
  PIN rec[280]
    DIRECTION INPUT ;
    USE SIGNAL ;
    PORT
      LAYER M5 ;
        RECT  12.336 0 12.36 0.084 ;
    END
  END rec[280]
  PIN rec[281]
    DIRECTION INPUT ;
    USE SIGNAL ;
    PORT
      LAYER M5 ;
        RECT  12.432 0 12.456 0.084 ;
    END
  END rec[281]
  PIN rec[282]
    DIRECTION INPUT ;
    USE SIGNAL ;
    PORT
      LAYER M5 ;
        RECT  12.528 0 12.552 0.084 ;
    END
  END rec[282]
  PIN rec[283]
    DIRECTION INPUT ;
    USE SIGNAL ;
    PORT
      LAYER M5 ;
        RECT  12.624 0 12.648 0.084 ;
    END
  END rec[283]
  PIN rec[284]
    DIRECTION INPUT ;
    USE SIGNAL ;
    PORT
      LAYER M5 ;
        RECT  12.72 0 12.744 0.084 ;
    END
  END rec[284]
  PIN rec[285]
    DIRECTION INPUT ;
    USE SIGNAL ;
    PORT
      LAYER M5 ;
        RECT  12.816 0 12.84 0.084 ;
    END
  END rec[285]
  PIN rec[286]
    DIRECTION INPUT ;
    USE SIGNAL ;
    PORT
      LAYER M5 ;
        RECT  12.912 0 12.936 0.084 ;
    END
  END rec[286]
  PIN rec[287]
    DIRECTION INPUT ;
    USE SIGNAL ;
    PORT
      LAYER M5 ;
        RECT  42.192 0 42.216 0.084 ;
    END
  END rec[287]
  PIN rec[288]
    DIRECTION INPUT ;
    USE SIGNAL ;
    PORT
      LAYER M5 ;
        RECT  42.288 0 42.312 0.084 ;
    END
  END rec[288]
  PIN rec[289]
    DIRECTION INPUT ;
    USE SIGNAL ;
    PORT
      LAYER M5 ;
        RECT  42.384 0 42.408 0.084 ;
    END
  END rec[289]
  PIN rec[28]
    DIRECTION INPUT ;
    USE SIGNAL ;
    PORT
      LAYER M5 ;
        RECT  18.864 0 18.888 0.084 ;
    END
  END rec[28]
  PIN rec[290]
    DIRECTION INPUT ;
    USE SIGNAL ;
    PORT
      LAYER M5 ;
        RECT  42.48 0 42.504 0.084 ;
    END
  END rec[290]
  PIN rec[291]
    DIRECTION INPUT ;
    USE SIGNAL ;
    PORT
      LAYER M5 ;
        RECT  42.576 0 42.6 0.084 ;
    END
  END rec[291]
  PIN rec[292]
    DIRECTION INPUT ;
    USE SIGNAL ;
    PORT
      LAYER M5 ;
        RECT  42.672 0 42.696 0.084 ;
    END
  END rec[292]
  PIN rec[293]
    DIRECTION INPUT ;
    USE SIGNAL ;
    PORT
      LAYER M5 ;
        RECT  42.768 0 42.792 0.084 ;
    END
  END rec[293]
  PIN rec[294]
    DIRECTION INPUT ;
    USE SIGNAL ;
    PORT
      LAYER M5 ;
        RECT  42.864 0 42.888 0.084 ;
    END
  END rec[294]
  PIN rec[295]
    DIRECTION INPUT ;
    USE SIGNAL ;
    PORT
      LAYER M5 ;
        RECT  42.96 0 42.984 0.084 ;
    END
  END rec[295]
  PIN rec[296]
    DIRECTION INPUT ;
    USE SIGNAL ;
    PORT
      LAYER M5 ;
        RECT  43.056 0 43.08 0.084 ;
    END
  END rec[296]
  PIN rec[297]
    DIRECTION INPUT ;
    USE SIGNAL ;
    PORT
      LAYER M5 ;
        RECT  43.152 0 43.176 0.084 ;
    END
  END rec[297]
  PIN rec[298]
    DIRECTION INPUT ;
    USE SIGNAL ;
    PORT
      LAYER M5 ;
        RECT  43.248 0 43.272 0.084 ;
    END
  END rec[298]
  PIN rec[299]
    DIRECTION INPUT ;
    USE SIGNAL ;
    PORT
      LAYER M5 ;
        RECT  43.344 0 43.368 0.084 ;
    END
  END rec[299]
  PIN rec[29]
    DIRECTION INPUT ;
    USE SIGNAL ;
    PORT
      LAYER M5 ;
        RECT  18.96 0 18.984 0.084 ;
    END
  END rec[29]
  PIN rec[2]
    DIRECTION INPUT ;
    USE SIGNAL ;
    PORT
      LAYER M5 ;
        RECT  16.368 0 16.392 0.084 ;
    END
  END rec[2]
  PIN rec[300]
    DIRECTION INPUT ;
    USE SIGNAL ;
    PORT
      LAYER M5 ;
        RECT  43.44 0 43.464 0.084 ;
    END
  END rec[300]
  PIN rec[301]
    DIRECTION INPUT ;
    USE SIGNAL ;
    PORT
      LAYER M5 ;
        RECT  43.536 0 43.56 0.084 ;
    END
  END rec[301]
  PIN rec[302]
    DIRECTION INPUT ;
    USE SIGNAL ;
    PORT
      LAYER M5 ;
        RECT  43.632 0 43.656 0.084 ;
    END
  END rec[302]
  PIN rec[303]
    DIRECTION INPUT ;
    USE SIGNAL ;
    PORT
      LAYER M5 ;
        RECT  43.728 0 43.752 0.084 ;
    END
  END rec[303]
  PIN rec[304]
    DIRECTION INPUT ;
    USE SIGNAL ;
    PORT
      LAYER M5 ;
        RECT  43.824 0 43.848 0.084 ;
    END
  END rec[304]
  PIN rec[305]
    DIRECTION INPUT ;
    USE SIGNAL ;
    PORT
      LAYER M5 ;
        RECT  43.92 0 43.944 0.084 ;
    END
  END rec[305]
  PIN rec[306]
    DIRECTION INPUT ;
    USE SIGNAL ;
    PORT
      LAYER M5 ;
        RECT  44.016 0 44.04 0.084 ;
    END
  END rec[306]
  PIN rec[307]
    DIRECTION INPUT ;
    USE SIGNAL ;
    PORT
      LAYER M5 ;
        RECT  44.112 0 44.136 0.084 ;
    END
  END rec[307]
  PIN rec[308]
    DIRECTION INPUT ;
    USE SIGNAL ;
    PORT
      LAYER M5 ;
        RECT  44.208 0 44.232 0.084 ;
    END
  END rec[308]
  PIN rec[309]
    DIRECTION INPUT ;
    USE SIGNAL ;
    PORT
      LAYER M5 ;
        RECT  44.304 0 44.328 0.084 ;
    END
  END rec[309]
  PIN rec[30]
    DIRECTION INPUT ;
    USE SIGNAL ;
    PORT
      LAYER M5 ;
        RECT  19.056 0 19.08 0.084 ;
    END
  END rec[30]
  PIN rec[310]
    DIRECTION INPUT ;
    USE SIGNAL ;
    PORT
      LAYER M5 ;
        RECT  44.4 0 44.424 0.084 ;
    END
  END rec[310]
  PIN rec[311]
    DIRECTION INPUT ;
    USE SIGNAL ;
    PORT
      LAYER M5 ;
        RECT  44.496 0 44.52 0.084 ;
    END
  END rec[311]
  PIN rec[312]
    DIRECTION INPUT ;
    USE SIGNAL ;
    PORT
      LAYER M5 ;
        RECT  44.592 0 44.616 0.084 ;
    END
  END rec[312]
  PIN rec[313]
    DIRECTION INPUT ;
    USE SIGNAL ;
    PORT
      LAYER M5 ;
        RECT  44.688 0 44.712 0.084 ;
    END
  END rec[313]
  PIN rec[314]
    DIRECTION INPUT ;
    USE SIGNAL ;
    PORT
      LAYER M5 ;
        RECT  44.784 0 44.808 0.084 ;
    END
  END rec[314]
  PIN rec[315]
    DIRECTION INPUT ;
    USE SIGNAL ;
    PORT
      LAYER M5 ;
        RECT  44.88 0 44.904 0.084 ;
    END
  END rec[315]
  PIN rec[316]
    DIRECTION INPUT ;
    USE SIGNAL ;
    PORT
      LAYER M5 ;
        RECT  44.976 0 45 0.084 ;
    END
  END rec[316]
  PIN rec[317]
    DIRECTION INPUT ;
    USE SIGNAL ;
    PORT
      LAYER M5 ;
        RECT  45.072 0 45.096 0.084 ;
    END
  END rec[317]
  PIN rec[318]
    DIRECTION INPUT ;
    USE SIGNAL ;
    PORT
      LAYER M5 ;
        RECT  45.168 0 45.192 0.084 ;
    END
  END rec[318]
  PIN rec[319]
    DIRECTION INPUT ;
    USE SIGNAL ;
    PORT
      LAYER M5 ;
        RECT  77.52 0 77.544 0.084 ;
    END
  END rec[319]
  PIN rec[31]
    DIRECTION INPUT ;
    USE SIGNAL ;
    PORT
      LAYER M5 ;
        RECT  32.208 0 32.232 0.084 ;
    END
  END rec[31]
  PIN rec[320]
    DIRECTION INPUT ;
    USE SIGNAL ;
    PORT
      LAYER M5 ;
        RECT  77.616 0 77.64 0.084 ;
    END
  END rec[320]
  PIN rec[321]
    DIRECTION INPUT ;
    USE SIGNAL ;
    PORT
      LAYER M5 ;
        RECT  77.712 0 77.736 0.084 ;
    END
  END rec[321]
  PIN rec[322]
    DIRECTION INPUT ;
    USE SIGNAL ;
    PORT
      LAYER M5 ;
        RECT  77.808 0 77.832 0.084 ;
    END
  END rec[322]
  PIN rec[323]
    DIRECTION INPUT ;
    USE SIGNAL ;
    PORT
      LAYER M5 ;
        RECT  77.904 0 77.928 0.084 ;
    END
  END rec[323]
  PIN rec[324]
    DIRECTION INPUT ;
    USE SIGNAL ;
    PORT
      LAYER M5 ;
        RECT  78 0 78.024 0.084 ;
    END
  END rec[324]
  PIN rec[325]
    DIRECTION INPUT ;
    USE SIGNAL ;
    PORT
      LAYER M5 ;
        RECT  78.096 0 78.12 0.084 ;
    END
  END rec[325]
  PIN rec[326]
    DIRECTION INPUT ;
    USE SIGNAL ;
    PORT
      LAYER M5 ;
        RECT  78.192 0 78.216 0.084 ;
    END
  END rec[326]
  PIN rec[327]
    DIRECTION INPUT ;
    USE SIGNAL ;
    PORT
      LAYER M5 ;
        RECT  78.288 0 78.312 0.084 ;
    END
  END rec[327]
  PIN rec[328]
    DIRECTION INPUT ;
    USE SIGNAL ;
    PORT
      LAYER M5 ;
        RECT  78.384 0 78.408 0.084 ;
    END
  END rec[328]
  PIN rec[329]
    DIRECTION INPUT ;
    USE SIGNAL ;
    PORT
      LAYER M5 ;
        RECT  78.48 0 78.504 0.084 ;
    END
  END rec[329]
  PIN rec[32]
    DIRECTION INPUT ;
    USE SIGNAL ;
    PORT
      LAYER M5 ;
        RECT  32.304 0 32.328 0.084 ;
    END
  END rec[32]
  PIN rec[330]
    DIRECTION INPUT ;
    USE SIGNAL ;
    PORT
      LAYER M5 ;
        RECT  78.576 0 78.6 0.084 ;
    END
  END rec[330]
  PIN rec[331]
    DIRECTION INPUT ;
    USE SIGNAL ;
    PORT
      LAYER M5 ;
        RECT  78.672 0 78.696 0.084 ;
    END
  END rec[331]
  PIN rec[332]
    DIRECTION INPUT ;
    USE SIGNAL ;
    PORT
      LAYER M5 ;
        RECT  78.768 0 78.792 0.084 ;
    END
  END rec[332]
  PIN rec[333]
    DIRECTION INPUT ;
    USE SIGNAL ;
    PORT
      LAYER M5 ;
        RECT  78.864 0 78.888 0.084 ;
    END
  END rec[333]
  PIN rec[334]
    DIRECTION INPUT ;
    USE SIGNAL ;
    PORT
      LAYER M5 ;
        RECT  78.96 0 78.984 0.084 ;
    END
  END rec[334]
  PIN rec[335]
    DIRECTION INPUT ;
    USE SIGNAL ;
    PORT
      LAYER M5 ;
        RECT  79.056 0 79.08 0.084 ;
    END
  END rec[335]
  PIN rec[336]
    DIRECTION INPUT ;
    USE SIGNAL ;
    PORT
      LAYER M5 ;
        RECT  79.152 0 79.176 0.084 ;
    END
  END rec[336]
  PIN rec[337]
    DIRECTION INPUT ;
    USE SIGNAL ;
    PORT
      LAYER M5 ;
        RECT  79.248 0 79.272 0.084 ;
    END
  END rec[337]
  PIN rec[338]
    DIRECTION INPUT ;
    USE SIGNAL ;
    PORT
      LAYER M5 ;
        RECT  79.344 0 79.368 0.084 ;
    END
  END rec[338]
  PIN rec[339]
    DIRECTION INPUT ;
    USE SIGNAL ;
    PORT
      LAYER M5 ;
        RECT  79.44 0 79.464 0.084 ;
    END
  END rec[339]
  PIN rec[33]
    DIRECTION INPUT ;
    USE SIGNAL ;
    PORT
      LAYER M5 ;
        RECT  32.4 0 32.424 0.084 ;
    END
  END rec[33]
  PIN rec[340]
    DIRECTION INPUT ;
    USE SIGNAL ;
    PORT
      LAYER M5 ;
        RECT  79.536 0 79.56 0.084 ;
    END
  END rec[340]
  PIN rec[341]
    DIRECTION INPUT ;
    USE SIGNAL ;
    PORT
      LAYER M5 ;
        RECT  79.632 0 79.656 0.084 ;
    END
  END rec[341]
  PIN rec[342]
    DIRECTION INPUT ;
    USE SIGNAL ;
    PORT
      LAYER M5 ;
        RECT  79.728 0 79.752 0.084 ;
    END
  END rec[342]
  PIN rec[343]
    DIRECTION INPUT ;
    USE SIGNAL ;
    PORT
      LAYER M5 ;
        RECT  79.824 0 79.848 0.084 ;
    END
  END rec[343]
  PIN rec[344]
    DIRECTION INPUT ;
    USE SIGNAL ;
    PORT
      LAYER M5 ;
        RECT  79.92 0 79.944 0.084 ;
    END
  END rec[344]
  PIN rec[345]
    DIRECTION INPUT ;
    USE SIGNAL ;
    PORT
      LAYER M5 ;
        RECT  80.016 0 80.04 0.084 ;
    END
  END rec[345]
  PIN rec[346]
    DIRECTION INPUT ;
    USE SIGNAL ;
    PORT
      LAYER M5 ;
        RECT  80.112 0 80.136 0.084 ;
    END
  END rec[346]
  PIN rec[347]
    DIRECTION INPUT ;
    USE SIGNAL ;
    PORT
      LAYER M5 ;
        RECT  80.208 0 80.232 0.084 ;
    END
  END rec[347]
  PIN rec[348]
    DIRECTION INPUT ;
    USE SIGNAL ;
    PORT
      LAYER M5 ;
        RECT  80.304 0 80.328 0.084 ;
    END
  END rec[348]
  PIN rec[349]
    DIRECTION INPUT ;
    USE SIGNAL ;
    PORT
      LAYER M5 ;
        RECT  80.4 0 80.424 0.084 ;
    END
  END rec[349]
  PIN rec[34]
    DIRECTION INPUT ;
    USE SIGNAL ;
    PORT
      LAYER M5 ;
        RECT  32.496 0 32.52 0.084 ;
    END
  END rec[34]
  PIN rec[350]
    DIRECTION INPUT ;
    USE SIGNAL ;
    PORT
      LAYER M5 ;
        RECT  80.496 0 80.52 0.084 ;
    END
  END rec[350]
  PIN rec[351]
    DIRECTION INPUT ;
    USE SIGNAL ;
    PORT
      LAYER M5 ;
        RECT  35.28 0 35.304 0.084 ;
    END
  END rec[351]
  PIN rec[352]
    DIRECTION INPUT ;
    USE SIGNAL ;
    PORT
      LAYER M5 ;
        RECT  35.376 0 35.4 0.084 ;
    END
  END rec[352]
  PIN rec[353]
    DIRECTION INPUT ;
    USE SIGNAL ;
    PORT
      LAYER M5 ;
        RECT  35.472 0 35.496 0.084 ;
    END
  END rec[353]
  PIN rec[354]
    DIRECTION INPUT ;
    USE SIGNAL ;
    PORT
      LAYER M5 ;
        RECT  35.568 0 35.592 0.084 ;
    END
  END rec[354]
  PIN rec[355]
    DIRECTION INPUT ;
    USE SIGNAL ;
    PORT
      LAYER M5 ;
        RECT  35.664 0 35.688 0.084 ;
    END
  END rec[355]
  PIN rec[356]
    DIRECTION INPUT ;
    USE SIGNAL ;
    PORT
      LAYER M5 ;
        RECT  35.76 0 35.784 0.084 ;
    END
  END rec[356]
  PIN rec[357]
    DIRECTION INPUT ;
    USE SIGNAL ;
    PORT
      LAYER M5 ;
        RECT  35.856 0 35.88 0.084 ;
    END
  END rec[357]
  PIN rec[358]
    DIRECTION INPUT ;
    USE SIGNAL ;
    PORT
      LAYER M5 ;
        RECT  35.952 0 35.976 0.084 ;
    END
  END rec[358]
  PIN rec[359]
    DIRECTION INPUT ;
    USE SIGNAL ;
    PORT
      LAYER M5 ;
        RECT  36.048 0 36.072 0.084 ;
    END
  END rec[359]
  PIN rec[35]
    DIRECTION INPUT ;
    USE SIGNAL ;
    PORT
      LAYER M5 ;
        RECT  32.592 0 32.616 0.084 ;
    END
  END rec[35]
  PIN rec[360]
    DIRECTION INPUT ;
    USE SIGNAL ;
    PORT
      LAYER M5 ;
        RECT  36.144 0 36.168 0.084 ;
    END
  END rec[360]
  PIN rec[361]
    DIRECTION INPUT ;
    USE SIGNAL ;
    PORT
      LAYER M5 ;
        RECT  36.24 0 36.264 0.084 ;
    END
  END rec[361]
  PIN rec[362]
    DIRECTION INPUT ;
    USE SIGNAL ;
    PORT
      LAYER M5 ;
        RECT  36.336 0 36.36 0.084 ;
    END
  END rec[362]
  PIN rec[363]
    DIRECTION INPUT ;
    USE SIGNAL ;
    PORT
      LAYER M5 ;
        RECT  36.432 0 36.456 0.084 ;
    END
  END rec[363]
  PIN rec[364]
    DIRECTION INPUT ;
    USE SIGNAL ;
    PORT
      LAYER M5 ;
        RECT  36.528 0 36.552 0.084 ;
    END
  END rec[364]
  PIN rec[365]
    DIRECTION INPUT ;
    USE SIGNAL ;
    PORT
      LAYER M5 ;
        RECT  36.624 0 36.648 0.084 ;
    END
  END rec[365]
  PIN rec[366]
    DIRECTION INPUT ;
    USE SIGNAL ;
    PORT
      LAYER M5 ;
        RECT  36.72 0 36.744 0.084 ;
    END
  END rec[366]
  PIN rec[367]
    DIRECTION INPUT ;
    USE SIGNAL ;
    PORT
      LAYER M5 ;
        RECT  36.816 0 36.84 0.084 ;
    END
  END rec[367]
  PIN rec[368]
    DIRECTION INPUT ;
    USE SIGNAL ;
    PORT
      LAYER M5 ;
        RECT  36.912 0 36.936 0.084 ;
    END
  END rec[368]
  PIN rec[369]
    DIRECTION INPUT ;
    USE SIGNAL ;
    PORT
      LAYER M5 ;
        RECT  37.008 0 37.032 0.084 ;
    END
  END rec[369]
  PIN rec[36]
    DIRECTION INPUT ;
    USE SIGNAL ;
    PORT
      LAYER M5 ;
        RECT  32.688 0 32.712 0.084 ;
    END
  END rec[36]
  PIN rec[370]
    DIRECTION INPUT ;
    USE SIGNAL ;
    PORT
      LAYER M5 ;
        RECT  37.104 0 37.128 0.084 ;
    END
  END rec[370]
  PIN rec[371]
    DIRECTION INPUT ;
    USE SIGNAL ;
    PORT
      LAYER M5 ;
        RECT  37.2 0 37.224 0.084 ;
    END
  END rec[371]
  PIN rec[372]
    DIRECTION INPUT ;
    USE SIGNAL ;
    PORT
      LAYER M5 ;
        RECT  37.296 0 37.32 0.084 ;
    END
  END rec[372]
  PIN rec[373]
    DIRECTION INPUT ;
    USE SIGNAL ;
    PORT
      LAYER M5 ;
        RECT  37.392 0 37.416 0.084 ;
    END
  END rec[373]
  PIN rec[374]
    DIRECTION INPUT ;
    USE SIGNAL ;
    PORT
      LAYER M5 ;
        RECT  37.488 0 37.512 0.084 ;
    END
  END rec[374]
  PIN rec[375]
    DIRECTION INPUT ;
    USE SIGNAL ;
    PORT
      LAYER M5 ;
        RECT  37.584 0 37.608 0.084 ;
    END
  END rec[375]
  PIN rec[376]
    DIRECTION INPUT ;
    USE SIGNAL ;
    PORT
      LAYER M5 ;
        RECT  37.68 0 37.704 0.084 ;
    END
  END rec[376]
  PIN rec[377]
    DIRECTION INPUT ;
    USE SIGNAL ;
    PORT
      LAYER M5 ;
        RECT  37.776 0 37.8 0.084 ;
    END
  END rec[377]
  PIN rec[378]
    DIRECTION INPUT ;
    USE SIGNAL ;
    PORT
      LAYER M5 ;
        RECT  37.872 0 37.896 0.084 ;
    END
  END rec[378]
  PIN rec[379]
    DIRECTION INPUT ;
    USE SIGNAL ;
    PORT
      LAYER M5 ;
        RECT  37.968 0 37.992 0.084 ;
    END
  END rec[379]
  PIN rec[37]
    DIRECTION INPUT ;
    USE SIGNAL ;
    PORT
      LAYER M5 ;
        RECT  32.784 0 32.808 0.084 ;
    END
  END rec[37]
  PIN rec[380]
    DIRECTION INPUT ;
    USE SIGNAL ;
    PORT
      LAYER M5 ;
        RECT  38.064 0 38.088 0.084 ;
    END
  END rec[380]
  PIN rec[381]
    DIRECTION INPUT ;
    USE SIGNAL ;
    PORT
      LAYER M5 ;
        RECT  38.16 0 38.184 0.084 ;
    END
  END rec[381]
  PIN rec[382]
    DIRECTION INPUT ;
    USE SIGNAL ;
    PORT
      LAYER M5 ;
        RECT  38.256 0 38.28 0.084 ;
    END
  END rec[382]
  PIN rec[383]
    DIRECTION INPUT ;
    USE SIGNAL ;
    PORT
      LAYER M5 ;
        RECT  67.536 0 67.56 0.084 ;
    END
  END rec[383]
  PIN rec[384]
    DIRECTION INPUT ;
    USE SIGNAL ;
    PORT
      LAYER M5 ;
        RECT  67.632 0 67.656 0.084 ;
    END
  END rec[384]
  PIN rec[385]
    DIRECTION INPUT ;
    USE SIGNAL ;
    PORT
      LAYER M5 ;
        RECT  67.728 0 67.752 0.084 ;
    END
  END rec[385]
  PIN rec[386]
    DIRECTION INPUT ;
    USE SIGNAL ;
    PORT
      LAYER M5 ;
        RECT  67.824 0 67.848 0.084 ;
    END
  END rec[386]
  PIN rec[387]
    DIRECTION INPUT ;
    USE SIGNAL ;
    PORT
      LAYER M5 ;
        RECT  67.92 0 67.944 0.084 ;
    END
  END rec[387]
  PIN rec[388]
    DIRECTION INPUT ;
    USE SIGNAL ;
    PORT
      LAYER M5 ;
        RECT  68.016 0 68.04 0.084 ;
    END
  END rec[388]
  PIN rec[389]
    DIRECTION INPUT ;
    USE SIGNAL ;
    PORT
      LAYER M5 ;
        RECT  68.112 0 68.136 0.084 ;
    END
  END rec[389]
  PIN rec[38]
    DIRECTION INPUT ;
    USE SIGNAL ;
    PORT
      LAYER M5 ;
        RECT  32.88 0 32.904 0.084 ;
    END
  END rec[38]
  PIN rec[390]
    DIRECTION INPUT ;
    USE SIGNAL ;
    PORT
      LAYER M5 ;
        RECT  68.208 0 68.232 0.084 ;
    END
  END rec[390]
  PIN rec[391]
    DIRECTION INPUT ;
    USE SIGNAL ;
    PORT
      LAYER M5 ;
        RECT  68.304 0 68.328 0.084 ;
    END
  END rec[391]
  PIN rec[392]
    DIRECTION INPUT ;
    USE SIGNAL ;
    PORT
      LAYER M5 ;
        RECT  68.4 0 68.424 0.084 ;
    END
  END rec[392]
  PIN rec[393]
    DIRECTION INPUT ;
    USE SIGNAL ;
    PORT
      LAYER M5 ;
        RECT  68.496 0 68.52 0.084 ;
    END
  END rec[393]
  PIN rec[394]
    DIRECTION INPUT ;
    USE SIGNAL ;
    PORT
      LAYER M5 ;
        RECT  68.592 0 68.616 0.084 ;
    END
  END rec[394]
  PIN rec[395]
    DIRECTION INPUT ;
    USE SIGNAL ;
    PORT
      LAYER M5 ;
        RECT  68.688 0 68.712 0.084 ;
    END
  END rec[395]
  PIN rec[396]
    DIRECTION INPUT ;
    USE SIGNAL ;
    PORT
      LAYER M5 ;
        RECT  68.784 0 68.808 0.084 ;
    END
  END rec[396]
  PIN rec[397]
    DIRECTION INPUT ;
    USE SIGNAL ;
    PORT
      LAYER M5 ;
        RECT  68.88 0 68.904 0.084 ;
    END
  END rec[397]
  PIN rec[398]
    DIRECTION INPUT ;
    USE SIGNAL ;
    PORT
      LAYER M5 ;
        RECT  68.976 0 69 0.084 ;
    END
  END rec[398]
  PIN rec[399]
    DIRECTION INPUT ;
    USE SIGNAL ;
    PORT
      LAYER M5 ;
        RECT  69.072 0 69.096 0.084 ;
    END
  END rec[399]
  PIN rec[39]
    DIRECTION INPUT ;
    USE SIGNAL ;
    PORT
      LAYER M5 ;
        RECT  32.976 0 33 0.084 ;
    END
  END rec[39]
  PIN rec[3]
    DIRECTION INPUT ;
    USE SIGNAL ;
    PORT
      LAYER M5 ;
        RECT  16.464 0 16.488 0.084 ;
    END
  END rec[3]
  PIN rec[400]
    DIRECTION INPUT ;
    USE SIGNAL ;
    PORT
      LAYER M5 ;
        RECT  69.168 0 69.192 0.084 ;
    END
  END rec[400]
  PIN rec[401]
    DIRECTION INPUT ;
    USE SIGNAL ;
    PORT
      LAYER M5 ;
        RECT  69.264 0 69.288 0.084 ;
    END
  END rec[401]
  PIN rec[402]
    DIRECTION INPUT ;
    USE SIGNAL ;
    PORT
      LAYER M5 ;
        RECT  69.36 0 69.384 0.084 ;
    END
  END rec[402]
  PIN rec[403]
    DIRECTION INPUT ;
    USE SIGNAL ;
    PORT
      LAYER M5 ;
        RECT  69.456 0 69.48 0.084 ;
    END
  END rec[403]
  PIN rec[404]
    DIRECTION INPUT ;
    USE SIGNAL ;
    PORT
      LAYER M5 ;
        RECT  69.552 0 69.576 0.084 ;
    END
  END rec[404]
  PIN rec[405]
    DIRECTION INPUT ;
    USE SIGNAL ;
    PORT
      LAYER M5 ;
        RECT  69.648 0 69.672 0.084 ;
    END
  END rec[405]
  PIN rec[406]
    DIRECTION INPUT ;
    USE SIGNAL ;
    PORT
      LAYER M5 ;
        RECT  69.744 0 69.768 0.084 ;
    END
  END rec[406]
  PIN rec[407]
    DIRECTION INPUT ;
    USE SIGNAL ;
    PORT
      LAYER M5 ;
        RECT  69.84 0 69.864 0.084 ;
    END
  END rec[407]
  PIN rec[408]
    DIRECTION INPUT ;
    USE SIGNAL ;
    PORT
      LAYER M5 ;
        RECT  69.936 0 69.96 0.084 ;
    END
  END rec[408]
  PIN rec[409]
    DIRECTION INPUT ;
    USE SIGNAL ;
    PORT
      LAYER M5 ;
        RECT  70.032 0 70.056 0.084 ;
    END
  END rec[409]
  PIN rec[40]
    DIRECTION INPUT ;
    USE SIGNAL ;
    PORT
      LAYER M5 ;
        RECT  33.072 0 33.096 0.084 ;
    END
  END rec[40]
  PIN rec[410]
    DIRECTION INPUT ;
    USE SIGNAL ;
    PORT
      LAYER M5 ;
        RECT  70.128 0 70.152 0.084 ;
    END
  END rec[410]
  PIN rec[411]
    DIRECTION INPUT ;
    USE SIGNAL ;
    PORT
      LAYER M5 ;
        RECT  70.224 0 70.248 0.084 ;
    END
  END rec[411]
  PIN rec[412]
    DIRECTION INPUT ;
    USE SIGNAL ;
    PORT
      LAYER M5 ;
        RECT  70.32 0 70.344 0.084 ;
    END
  END rec[412]
  PIN rec[413]
    DIRECTION INPUT ;
    USE SIGNAL ;
    PORT
      LAYER M5 ;
        RECT  70.416 0 70.44 0.084 ;
    END
  END rec[413]
  PIN rec[414]
    DIRECTION INPUT ;
    USE SIGNAL ;
    PORT
      LAYER M5 ;
        RECT  70.512 0 70.536 0.084 ;
    END
  END rec[414]
  PIN rec[415]
    DIRECTION INPUT ;
    USE SIGNAL ;
    PORT
      LAYER M5 ;
        RECT  73.68 0 73.704 0.084 ;
    END
  END rec[415]
  PIN rec[416]
    DIRECTION INPUT ;
    USE SIGNAL ;
    PORT
      LAYER M5 ;
        RECT  73.776 0 73.8 0.084 ;
    END
  END rec[416]
  PIN rec[417]
    DIRECTION INPUT ;
    USE SIGNAL ;
    PORT
      LAYER M5 ;
        RECT  73.872 0 73.896 0.084 ;
    END
  END rec[417]
  PIN rec[418]
    DIRECTION INPUT ;
    USE SIGNAL ;
    PORT
      LAYER M5 ;
        RECT  73.968 0 73.992 0.084 ;
    END
  END rec[418]
  PIN rec[419]
    DIRECTION INPUT ;
    USE SIGNAL ;
    PORT
      LAYER M5 ;
        RECT  74.064 0 74.088 0.084 ;
    END
  END rec[419]
  PIN rec[41]
    DIRECTION INPUT ;
    USE SIGNAL ;
    PORT
      LAYER M5 ;
        RECT  33.168 0 33.192 0.084 ;
    END
  END rec[41]
  PIN rec[420]
    DIRECTION INPUT ;
    USE SIGNAL ;
    PORT
      LAYER M5 ;
        RECT  74.16 0 74.184 0.084 ;
    END
  END rec[420]
  PIN rec[421]
    DIRECTION INPUT ;
    USE SIGNAL ;
    PORT
      LAYER M5 ;
        RECT  74.256 0 74.28 0.084 ;
    END
  END rec[421]
  PIN rec[422]
    DIRECTION INPUT ;
    USE SIGNAL ;
    PORT
      LAYER M5 ;
        RECT  74.352 0 74.376 0.084 ;
    END
  END rec[422]
  PIN rec[423]
    DIRECTION INPUT ;
    USE SIGNAL ;
    PORT
      LAYER M5 ;
        RECT  74.448 0 74.472 0.084 ;
    END
  END rec[423]
  PIN rec[424]
    DIRECTION INPUT ;
    USE SIGNAL ;
    PORT
      LAYER M5 ;
        RECT  74.544 0 74.568 0.084 ;
    END
  END rec[424]
  PIN rec[425]
    DIRECTION INPUT ;
    USE SIGNAL ;
    PORT
      LAYER M5 ;
        RECT  74.64 0 74.664 0.084 ;
    END
  END rec[425]
  PIN rec[426]
    DIRECTION INPUT ;
    USE SIGNAL ;
    PORT
      LAYER M5 ;
        RECT  74.736 0 74.76 0.084 ;
    END
  END rec[426]
  PIN rec[427]
    DIRECTION INPUT ;
    USE SIGNAL ;
    PORT
      LAYER M5 ;
        RECT  74.832 0 74.856 0.084 ;
    END
  END rec[427]
  PIN rec[428]
    DIRECTION INPUT ;
    USE SIGNAL ;
    PORT
      LAYER M5 ;
        RECT  74.928 0 74.952 0.084 ;
    END
  END rec[428]
  PIN rec[429]
    DIRECTION INPUT ;
    USE SIGNAL ;
    PORT
      LAYER M5 ;
        RECT  75.024 0 75.048 0.084 ;
    END
  END rec[429]
  PIN rec[42]
    DIRECTION INPUT ;
    USE SIGNAL ;
    PORT
      LAYER M5 ;
        RECT  33.264 0 33.288 0.084 ;
    END
  END rec[42]
  PIN rec[430]
    DIRECTION INPUT ;
    USE SIGNAL ;
    PORT
      LAYER M5 ;
        RECT  75.12 0 75.144 0.084 ;
    END
  END rec[430]
  PIN rec[431]
    DIRECTION INPUT ;
    USE SIGNAL ;
    PORT
      LAYER M5 ;
        RECT  75.216 0 75.24 0.084 ;
    END
  END rec[431]
  PIN rec[432]
    DIRECTION INPUT ;
    USE SIGNAL ;
    PORT
      LAYER M5 ;
        RECT  75.312 0 75.336 0.084 ;
    END
  END rec[432]
  PIN rec[433]
    DIRECTION INPUT ;
    USE SIGNAL ;
    PORT
      LAYER M5 ;
        RECT  75.408 0 75.432 0.084 ;
    END
  END rec[433]
  PIN rec[434]
    DIRECTION INPUT ;
    USE SIGNAL ;
    PORT
      LAYER M5 ;
        RECT  75.504 0 75.528 0.084 ;
    END
  END rec[434]
  PIN rec[435]
    DIRECTION INPUT ;
    USE SIGNAL ;
    PORT
      LAYER M5 ;
        RECT  75.6 0 75.624 0.084 ;
    END
  END rec[435]
  PIN rec[436]
    DIRECTION INPUT ;
    USE SIGNAL ;
    PORT
      LAYER M5 ;
        RECT  75.696 0 75.72 0.084 ;
    END
  END rec[436]
  PIN rec[437]
    DIRECTION INPUT ;
    USE SIGNAL ;
    PORT
      LAYER M5 ;
        RECT  75.792 0 75.816 0.084 ;
    END
  END rec[437]
  PIN rec[438]
    DIRECTION INPUT ;
    USE SIGNAL ;
    PORT
      LAYER M5 ;
        RECT  75.888 0 75.912 0.084 ;
    END
  END rec[438]
  PIN rec[439]
    DIRECTION INPUT ;
    USE SIGNAL ;
    PORT
      LAYER M5 ;
        RECT  75.984 0 76.008 0.084 ;
    END
  END rec[439]
  PIN rec[43]
    DIRECTION INPUT ;
    USE SIGNAL ;
    PORT
      LAYER M5 ;
        RECT  33.36 0 33.384 0.084 ;
    END
  END rec[43]
  PIN rec[440]
    DIRECTION INPUT ;
    USE SIGNAL ;
    PORT
      LAYER M5 ;
        RECT  76.08 0 76.104 0.084 ;
    END
  END rec[440]
  PIN rec[441]
    DIRECTION INPUT ;
    USE SIGNAL ;
    PORT
      LAYER M5 ;
        RECT  76.176 0 76.2 0.084 ;
    END
  END rec[441]
  PIN rec[442]
    DIRECTION INPUT ;
    USE SIGNAL ;
    PORT
      LAYER M5 ;
        RECT  76.272 0 76.296 0.084 ;
    END
  END rec[442]
  PIN rec[443]
    DIRECTION INPUT ;
    USE SIGNAL ;
    PORT
      LAYER M5 ;
        RECT  76.368 0 76.392 0.084 ;
    END
  END rec[443]
  PIN rec[444]
    DIRECTION INPUT ;
    USE SIGNAL ;
    PORT
      LAYER M5 ;
        RECT  76.464 0 76.488 0.084 ;
    END
  END rec[444]
  PIN rec[445]
    DIRECTION INPUT ;
    USE SIGNAL ;
    PORT
      LAYER M5 ;
        RECT  76.56 0 76.584 0.084 ;
    END
  END rec[445]
  PIN rec[446]
    DIRECTION INPUT ;
    USE SIGNAL ;
    PORT
      LAYER M5 ;
        RECT  76.656 0 76.68 0.084 ;
    END
  END rec[446]
  PIN rec[447]
    DIRECTION INPUT ;
    USE SIGNAL ;
    PORT
      LAYER M5 ;
        RECT  19.92 0 19.944 0.084 ;
    END
  END rec[447]
  PIN rec[448]
    DIRECTION INPUT ;
    USE SIGNAL ;
    PORT
      LAYER M5 ;
        RECT  20.016 0 20.04 0.084 ;
    END
  END rec[448]
  PIN rec[449]
    DIRECTION INPUT ;
    USE SIGNAL ;
    PORT
      LAYER M5 ;
        RECT  20.112 0 20.136 0.084 ;
    END
  END rec[449]
  PIN rec[44]
    DIRECTION INPUT ;
    USE SIGNAL ;
    PORT
      LAYER M5 ;
        RECT  33.456 0 33.48 0.084 ;
    END
  END rec[44]
  PIN rec[450]
    DIRECTION INPUT ;
    USE SIGNAL ;
    PORT
      LAYER M5 ;
        RECT  20.208 0 20.232 0.084 ;
    END
  END rec[450]
  PIN rec[451]
    DIRECTION INPUT ;
    USE SIGNAL ;
    PORT
      LAYER M5 ;
        RECT  20.304 0 20.328 0.084 ;
    END
  END rec[451]
  PIN rec[452]
    DIRECTION INPUT ;
    USE SIGNAL ;
    PORT
      LAYER M5 ;
        RECT  20.4 0 20.424 0.084 ;
    END
  END rec[452]
  PIN rec[453]
    DIRECTION INPUT ;
    USE SIGNAL ;
    PORT
      LAYER M5 ;
        RECT  20.496 0 20.52 0.084 ;
    END
  END rec[453]
  PIN rec[454]
    DIRECTION INPUT ;
    USE SIGNAL ;
    PORT
      LAYER M5 ;
        RECT  20.592 0 20.616 0.084 ;
    END
  END rec[454]
  PIN rec[455]
    DIRECTION INPUT ;
    USE SIGNAL ;
    PORT
      LAYER M5 ;
        RECT  20.688 0 20.712 0.084 ;
    END
  END rec[455]
  PIN rec[456]
    DIRECTION INPUT ;
    USE SIGNAL ;
    PORT
      LAYER M5 ;
        RECT  20.784 0 20.808 0.084 ;
    END
  END rec[456]
  PIN rec[457]
    DIRECTION INPUT ;
    USE SIGNAL ;
    PORT
      LAYER M5 ;
        RECT  20.88 0 20.904 0.084 ;
    END
  END rec[457]
  PIN rec[458]
    DIRECTION INPUT ;
    USE SIGNAL ;
    PORT
      LAYER M5 ;
        RECT  20.976 0 21 0.084 ;
    END
  END rec[458]
  PIN rec[459]
    DIRECTION INPUT ;
    USE SIGNAL ;
    PORT
      LAYER M5 ;
        RECT  21.072 0 21.096 0.084 ;
    END
  END rec[459]
  PIN rec[45]
    DIRECTION INPUT ;
    USE SIGNAL ;
    PORT
      LAYER M5 ;
        RECT  33.552 0 33.576 0.084 ;
    END
  END rec[45]
  PIN rec[460]
    DIRECTION INPUT ;
    USE SIGNAL ;
    PORT
      LAYER M5 ;
        RECT  21.168 0 21.192 0.084 ;
    END
  END rec[460]
  PIN rec[461]
    DIRECTION INPUT ;
    USE SIGNAL ;
    PORT
      LAYER M5 ;
        RECT  21.264 0 21.288 0.084 ;
    END
  END rec[461]
  PIN rec[462]
    DIRECTION INPUT ;
    USE SIGNAL ;
    PORT
      LAYER M5 ;
        RECT  21.36 0 21.384 0.084 ;
    END
  END rec[462]
  PIN rec[463]
    DIRECTION INPUT ;
    USE SIGNAL ;
    PORT
      LAYER M5 ;
        RECT  21.456 0 21.48 0.084 ;
    END
  END rec[463]
  PIN rec[464]
    DIRECTION INPUT ;
    USE SIGNAL ;
    PORT
      LAYER M5 ;
        RECT  21.552 0 21.576 0.084 ;
    END
  END rec[464]
  PIN rec[465]
    DIRECTION INPUT ;
    USE SIGNAL ;
    PORT
      LAYER M5 ;
        RECT  21.648 0 21.672 0.084 ;
    END
  END rec[465]
  PIN rec[466]
    DIRECTION INPUT ;
    USE SIGNAL ;
    PORT
      LAYER M5 ;
        RECT  21.744 0 21.768 0.084 ;
    END
  END rec[466]
  PIN rec[467]
    DIRECTION INPUT ;
    USE SIGNAL ;
    PORT
      LAYER M5 ;
        RECT  21.84 0 21.864 0.084 ;
    END
  END rec[467]
  PIN rec[468]
    DIRECTION INPUT ;
    USE SIGNAL ;
    PORT
      LAYER M5 ;
        RECT  21.936 0 21.96 0.084 ;
    END
  END rec[468]
  PIN rec[469]
    DIRECTION INPUT ;
    USE SIGNAL ;
    PORT
      LAYER M5 ;
        RECT  22.032 0 22.056 0.084 ;
    END
  END rec[469]
  PIN rec[46]
    DIRECTION INPUT ;
    USE SIGNAL ;
    PORT
      LAYER M5 ;
        RECT  33.648 0 33.672 0.084 ;
    END
  END rec[46]
  PIN rec[470]
    DIRECTION INPUT ;
    USE SIGNAL ;
    PORT
      LAYER M5 ;
        RECT  22.128 0 22.152 0.084 ;
    END
  END rec[470]
  PIN rec[471]
    DIRECTION INPUT ;
    USE SIGNAL ;
    PORT
      LAYER M5 ;
        RECT  22.224 0 22.248 0.084 ;
    END
  END rec[471]
  PIN rec[472]
    DIRECTION INPUT ;
    USE SIGNAL ;
    PORT
      LAYER M5 ;
        RECT  22.32 0 22.344 0.084 ;
    END
  END rec[472]
  PIN rec[473]
    DIRECTION INPUT ;
    USE SIGNAL ;
    PORT
      LAYER M5 ;
        RECT  22.416 0 22.44 0.084 ;
    END
  END rec[473]
  PIN rec[474]
    DIRECTION INPUT ;
    USE SIGNAL ;
    PORT
      LAYER M5 ;
        RECT  22.512 0 22.536 0.084 ;
    END
  END rec[474]
  PIN rec[475]
    DIRECTION INPUT ;
    USE SIGNAL ;
    PORT
      LAYER M5 ;
        RECT  22.608 0 22.632 0.084 ;
    END
  END rec[475]
  PIN rec[476]
    DIRECTION INPUT ;
    USE SIGNAL ;
    PORT
      LAYER M5 ;
        RECT  22.704 0 22.728 0.084 ;
    END
  END rec[476]
  PIN rec[477]
    DIRECTION INPUT ;
    USE SIGNAL ;
    PORT
      LAYER M5 ;
        RECT  22.8 0 22.824 0.084 ;
    END
  END rec[477]
  PIN rec[478]
    DIRECTION INPUT ;
    USE SIGNAL ;
    PORT
      LAYER M5 ;
        RECT  22.896 0 22.92 0.084 ;
    END
  END rec[478]
  PIN rec[479]
    DIRECTION INPUT ;
    USE SIGNAL ;
    PORT
      LAYER M5 ;
        RECT  26.064 0 26.088 0.084 ;
    END
  END rec[479]
  PIN rec[47]
    DIRECTION INPUT ;
    USE SIGNAL ;
    PORT
      LAYER M5 ;
        RECT  33.744 0 33.768 0.084 ;
    END
  END rec[47]
  PIN rec[480]
    DIRECTION INPUT ;
    USE SIGNAL ;
    PORT
      LAYER M5 ;
        RECT  26.16 0 26.184 0.084 ;
    END
  END rec[480]
  PIN rec[481]
    DIRECTION INPUT ;
    USE SIGNAL ;
    PORT
      LAYER M5 ;
        RECT  26.256 0 26.28 0.084 ;
    END
  END rec[481]
  PIN rec[482]
    DIRECTION INPUT ;
    USE SIGNAL ;
    PORT
      LAYER M5 ;
        RECT  26.352 0 26.376 0.084 ;
    END
  END rec[482]
  PIN rec[483]
    DIRECTION INPUT ;
    USE SIGNAL ;
    PORT
      LAYER M5 ;
        RECT  26.448 0 26.472 0.084 ;
    END
  END rec[483]
  PIN rec[484]
    DIRECTION INPUT ;
    USE SIGNAL ;
    PORT
      LAYER M5 ;
        RECT  26.544 0 26.568 0.084 ;
    END
  END rec[484]
  PIN rec[485]
    DIRECTION INPUT ;
    USE SIGNAL ;
    PORT
      LAYER M5 ;
        RECT  26.64 0 26.664 0.084 ;
    END
  END rec[485]
  PIN rec[486]
    DIRECTION INPUT ;
    USE SIGNAL ;
    PORT
      LAYER M5 ;
        RECT  26.736 0 26.76 0.084 ;
    END
  END rec[486]
  PIN rec[487]
    DIRECTION INPUT ;
    USE SIGNAL ;
    PORT
      LAYER M5 ;
        RECT  26.832 0 26.856 0.084 ;
    END
  END rec[487]
  PIN rec[488]
    DIRECTION INPUT ;
    USE SIGNAL ;
    PORT
      LAYER M5 ;
        RECT  26.928 0 26.952 0.084 ;
    END
  END rec[488]
  PIN rec[489]
    DIRECTION INPUT ;
    USE SIGNAL ;
    PORT
      LAYER M5 ;
        RECT  27.024 0 27.048 0.084 ;
    END
  END rec[489]
  PIN rec[48]
    DIRECTION INPUT ;
    USE SIGNAL ;
    PORT
      LAYER M5 ;
        RECT  33.84 0 33.864 0.084 ;
    END
  END rec[48]
  PIN rec[490]
    DIRECTION INPUT ;
    USE SIGNAL ;
    PORT
      LAYER M5 ;
        RECT  27.12 0 27.144 0.084 ;
    END
  END rec[490]
  PIN rec[491]
    DIRECTION INPUT ;
    USE SIGNAL ;
    PORT
      LAYER M5 ;
        RECT  27.216 0 27.24 0.084 ;
    END
  END rec[491]
  PIN rec[492]
    DIRECTION INPUT ;
    USE SIGNAL ;
    PORT
      LAYER M5 ;
        RECT  27.312 0 27.336 0.084 ;
    END
  END rec[492]
  PIN rec[493]
    DIRECTION INPUT ;
    USE SIGNAL ;
    PORT
      LAYER M5 ;
        RECT  27.408 0 27.432 0.084 ;
    END
  END rec[493]
  PIN rec[494]
    DIRECTION INPUT ;
    USE SIGNAL ;
    PORT
      LAYER M5 ;
        RECT  27.504 0 27.528 0.084 ;
    END
  END rec[494]
  PIN rec[495]
    DIRECTION INPUT ;
    USE SIGNAL ;
    PORT
      LAYER M5 ;
        RECT  27.6 0 27.624 0.084 ;
    END
  END rec[495]
  PIN rec[496]
    DIRECTION INPUT ;
    USE SIGNAL ;
    PORT
      LAYER M5 ;
        RECT  27.696 0 27.72 0.084 ;
    END
  END rec[496]
  PIN rec[497]
    DIRECTION INPUT ;
    USE SIGNAL ;
    PORT
      LAYER M5 ;
        RECT  27.792 0 27.816 0.084 ;
    END
  END rec[497]
  PIN rec[498]
    DIRECTION INPUT ;
    USE SIGNAL ;
    PORT
      LAYER M5 ;
        RECT  27.888 0 27.912 0.084 ;
    END
  END rec[498]
  PIN rec[499]
    DIRECTION INPUT ;
    USE SIGNAL ;
    PORT
      LAYER M5 ;
        RECT  27.984 0 28.008 0.084 ;
    END
  END rec[499]
  PIN rec[49]
    DIRECTION INPUT ;
    USE SIGNAL ;
    PORT
      LAYER M5 ;
        RECT  33.936 0 33.96 0.084 ;
    END
  END rec[49]
  PIN rec[4]
    DIRECTION INPUT ;
    USE SIGNAL ;
    PORT
      LAYER M5 ;
        RECT  16.56 0 16.584 0.084 ;
    END
  END rec[4]
  PIN rec[500]
    DIRECTION INPUT ;
    USE SIGNAL ;
    PORT
      LAYER M5 ;
        RECT  28.08 0 28.104 0.084 ;
    END
  END rec[500]
  PIN rec[501]
    DIRECTION INPUT ;
    USE SIGNAL ;
    PORT
      LAYER M5 ;
        RECT  28.176 0 28.2 0.084 ;
    END
  END rec[501]
  PIN rec[502]
    DIRECTION INPUT ;
    USE SIGNAL ;
    PORT
      LAYER M5 ;
        RECT  28.272 0 28.296 0.084 ;
    END
  END rec[502]
  PIN rec[503]
    DIRECTION INPUT ;
    USE SIGNAL ;
    PORT
      LAYER M5 ;
        RECT  28.368 0 28.392 0.084 ;
    END
  END rec[503]
  PIN rec[504]
    DIRECTION INPUT ;
    USE SIGNAL ;
    PORT
      LAYER M5 ;
        RECT  28.464 0 28.488 0.084 ;
    END
  END rec[504]
  PIN rec[505]
    DIRECTION INPUT ;
    USE SIGNAL ;
    PORT
      LAYER M5 ;
        RECT  28.56 0 28.584 0.084 ;
    END
  END rec[505]
  PIN rec[506]
    DIRECTION INPUT ;
    USE SIGNAL ;
    PORT
      LAYER M5 ;
        RECT  28.656 0 28.68 0.084 ;
    END
  END rec[506]
  PIN rec[507]
    DIRECTION INPUT ;
    USE SIGNAL ;
    PORT
      LAYER M5 ;
        RECT  28.752 0 28.776 0.084 ;
    END
  END rec[507]
  PIN rec[508]
    DIRECTION INPUT ;
    USE SIGNAL ;
    PORT
      LAYER M5 ;
        RECT  28.848 0 28.872 0.084 ;
    END
  END rec[508]
  PIN rec[509]
    DIRECTION INPUT ;
    USE SIGNAL ;
    PORT
      LAYER M5 ;
        RECT  28.944 0 28.968 0.084 ;
    END
  END rec[509]
  PIN rec[50]
    DIRECTION INPUT ;
    USE SIGNAL ;
    PORT
      LAYER M5 ;
        RECT  34.032 0 34.056 0.084 ;
    END
  END rec[50]
  PIN rec[510]
    DIRECTION INPUT ;
    USE SIGNAL ;
    PORT
      LAYER M5 ;
        RECT  29.04 0 29.064 0.084 ;
    END
  END rec[510]
  PIN rec[511]
    DIRECTION INPUT ;
    USE SIGNAL ;
    PORT
      LAYER M5 ;
        RECT  29.136 0 29.16 0.084 ;
    END
  END rec[511]
  PIN rec[512]
    DIRECTION INPUT ;
    USE SIGNAL ;
    PORT
      LAYER M5 ;
        RECT  29.232 0 29.256 0.084 ;
    END
  END rec[512]
  PIN rec[513]
    DIRECTION INPUT ;
    USE SIGNAL ;
    PORT
      LAYER M5 ;
        RECT  29.328 0 29.352 0.084 ;
    END
  END rec[513]
  PIN rec[514]
    DIRECTION INPUT ;
    USE SIGNAL ;
    PORT
      LAYER M5 ;
        RECT  29.424 0 29.448 0.084 ;
    END
  END rec[514]
  PIN rec[515]
    DIRECTION INPUT ;
    USE SIGNAL ;
    PORT
      LAYER M5 ;
        RECT  29.52 0 29.544 0.084 ;
    END
  END rec[515]
  PIN rec[516]
    DIRECTION INPUT ;
    USE SIGNAL ;
    PORT
      LAYER M5 ;
        RECT  29.616 0 29.64 0.084 ;
    END
  END rec[516]
  PIN rec[517]
    DIRECTION INPUT ;
    USE SIGNAL ;
    PORT
      LAYER M5 ;
        RECT  29.712 0 29.736 0.084 ;
    END
  END rec[517]
  PIN rec[518]
    DIRECTION INPUT ;
    USE SIGNAL ;
    PORT
      LAYER M5 ;
        RECT  29.808 0 29.832 0.084 ;
    END
  END rec[518]
  PIN rec[519]
    DIRECTION INPUT ;
    USE SIGNAL ;
    PORT
      LAYER M5 ;
        RECT  29.904 0 29.928 0.084 ;
    END
  END rec[519]
  PIN rec[51]
    DIRECTION INPUT ;
    USE SIGNAL ;
    PORT
      LAYER M5 ;
        RECT  34.128 0 34.152 0.084 ;
    END
  END rec[51]
  PIN rec[520]
    DIRECTION INPUT ;
    USE SIGNAL ;
    PORT
      LAYER M5 ;
        RECT  30 0 30.024 0.084 ;
    END
  END rec[520]
  PIN rec[521]
    DIRECTION INPUT ;
    USE SIGNAL ;
    PORT
      LAYER M5 ;
        RECT  30.096 0 30.12 0.084 ;
    END
  END rec[521]
  PIN rec[522]
    DIRECTION INPUT ;
    USE SIGNAL ;
    PORT
      LAYER M5 ;
        RECT  30.192 0 30.216 0.084 ;
    END
  END rec[522]
  PIN rec[523]
    DIRECTION INPUT ;
    USE SIGNAL ;
    PORT
      LAYER M5 ;
        RECT  30.288 0 30.312 0.084 ;
    END
  END rec[523]
  PIN rec[524]
    DIRECTION INPUT ;
    USE SIGNAL ;
    PORT
      LAYER M5 ;
        RECT  30.384 0 30.408 0.084 ;
    END
  END rec[524]
  PIN rec[525]
    DIRECTION INPUT ;
    USE SIGNAL ;
    PORT
      LAYER M5 ;
        RECT  30.48 0 30.504 0.084 ;
    END
  END rec[525]
  PIN rec[526]
    DIRECTION INPUT ;
    USE SIGNAL ;
    PORT
      LAYER M5 ;
        RECT  30.576 0 30.6 0.084 ;
    END
  END rec[526]
  PIN rec[527]
    DIRECTION INPUT ;
    USE SIGNAL ;
    PORT
      LAYER M5 ;
        RECT  30.672 0 30.696 0.084 ;
    END
  END rec[527]
  PIN rec[528]
    DIRECTION INPUT ;
    USE SIGNAL ;
    PORT
      LAYER M5 ;
        RECT  30.768 0 30.792 0.084 ;
    END
  END rec[528]
  PIN rec[529]
    DIRECTION INPUT ;
    USE SIGNAL ;
    PORT
      LAYER M5 ;
        RECT  30.864 0 30.888 0.084 ;
    END
  END rec[529]
  PIN rec[52]
    DIRECTION INPUT ;
    USE SIGNAL ;
    PORT
      LAYER M5 ;
        RECT  34.224 0 34.248 0.084 ;
    END
  END rec[52]
  PIN rec[530]
    DIRECTION INPUT ;
    USE SIGNAL ;
    PORT
      LAYER M5 ;
        RECT  30.96 0 30.984 0.084 ;
    END
  END rec[530]
  PIN rec[531]
    DIRECTION INPUT ;
    USE SIGNAL ;
    PORT
      LAYER M5 ;
        RECT  31.056 0 31.08 0.084 ;
    END
  END rec[531]
  PIN rec[532]
    DIRECTION INPUT ;
    USE SIGNAL ;
    PORT
      LAYER M5 ;
        RECT  31.152 0 31.176 0.084 ;
    END
  END rec[532]
  PIN rec[533]
    DIRECTION INPUT ;
    USE SIGNAL ;
    PORT
      LAYER M5 ;
        RECT  31.248 0 31.272 0.084 ;
    END
  END rec[533]
  PIN rec[534]
    DIRECTION INPUT ;
    USE SIGNAL ;
    PORT
      LAYER M5 ;
        RECT  31.344 0 31.368 0.084 ;
    END
  END rec[534]
  PIN rec[535]
    DIRECTION INPUT ;
    USE SIGNAL ;
    PORT
      LAYER M5 ;
        RECT  31.44 0 31.464 0.084 ;
    END
  END rec[535]
  PIN rec[536]
    DIRECTION INPUT ;
    USE SIGNAL ;
    PORT
      LAYER M5 ;
        RECT  31.536 0 31.56 0.084 ;
    END
  END rec[536]
  PIN rec[537]
    DIRECTION INPUT ;
    USE SIGNAL ;
    PORT
      LAYER M5 ;
        RECT  31.632 0 31.656 0.084 ;
    END
  END rec[537]
  PIN rec[538]
    DIRECTION INPUT ;
    USE SIGNAL ;
    PORT
      LAYER M5 ;
        RECT  31.728 0 31.752 0.084 ;
    END
  END rec[538]
  PIN rec[539]
    DIRECTION INPUT ;
    USE SIGNAL ;
    PORT
      LAYER M5 ;
        RECT  31.824 0 31.848 0.084 ;
    END
  END rec[539]
  PIN rec[53]
    DIRECTION INPUT ;
    USE SIGNAL ;
    PORT
      LAYER M5 ;
        RECT  34.32 0 34.344 0.084 ;
    END
  END rec[53]
  PIN rec[540]
    DIRECTION INPUT ;
    USE SIGNAL ;
    PORT
      LAYER M5 ;
        RECT  31.92 0 31.944 0.084 ;
    END
  END rec[540]
  PIN rec[541]
    DIRECTION INPUT ;
    USE SIGNAL ;
    PORT
      LAYER M5 ;
        RECT  32.016 0 32.04 0.084 ;
    END
  END rec[541]
  PIN rec[542]
    DIRECTION INPUT ;
    USE SIGNAL ;
    PORT
      LAYER M5 ;
        RECT  32.112 0 32.136 0.084 ;
    END
  END rec[542]
  PIN rec[543]
    DIRECTION INPUT ;
    USE SIGNAL ;
    PORT
      LAYER M5 ;
        RECT  45.264 0 45.288 0.084 ;
    END
  END rec[543]
  PIN rec[544]
    DIRECTION INPUT ;
    USE SIGNAL ;
    PORT
      LAYER M5 ;
        RECT  45.36 0 45.384 0.084 ;
    END
  END rec[544]
  PIN rec[545]
    DIRECTION INPUT ;
    USE SIGNAL ;
    PORT
      LAYER M5 ;
        RECT  45.456 0 45.48 0.084 ;
    END
  END rec[545]
  PIN rec[546]
    DIRECTION INPUT ;
    USE SIGNAL ;
    PORT
      LAYER M5 ;
        RECT  45.552 0 45.576 0.084 ;
    END
  END rec[546]
  PIN rec[547]
    DIRECTION INPUT ;
    USE SIGNAL ;
    PORT
      LAYER M5 ;
        RECT  45.648 0 45.672 0.084 ;
    END
  END rec[547]
  PIN rec[548]
    DIRECTION INPUT ;
    USE SIGNAL ;
    PORT
      LAYER M5 ;
        RECT  45.744 0 45.768 0.084 ;
    END
  END rec[548]
  PIN rec[549]
    DIRECTION INPUT ;
    USE SIGNAL ;
    PORT
      LAYER M5 ;
        RECT  45.84 0 45.864 0.084 ;
    END
  END rec[549]
  PIN rec[54]
    DIRECTION INPUT ;
    USE SIGNAL ;
    PORT
      LAYER M5 ;
        RECT  34.416 0 34.44 0.084 ;
    END
  END rec[54]
  PIN rec[550]
    DIRECTION INPUT ;
    USE SIGNAL ;
    PORT
      LAYER M5 ;
        RECT  45.936 0 45.96 0.084 ;
    END
  END rec[550]
  PIN rec[551]
    DIRECTION INPUT ;
    USE SIGNAL ;
    PORT
      LAYER M5 ;
        RECT  46.032 0 46.056 0.084 ;
    END
  END rec[551]
  PIN rec[552]
    DIRECTION INPUT ;
    USE SIGNAL ;
    PORT
      LAYER M5 ;
        RECT  46.128 0 46.152 0.084 ;
    END
  END rec[552]
  PIN rec[553]
    DIRECTION INPUT ;
    USE SIGNAL ;
    PORT
      LAYER M5 ;
        RECT  46.224 0 46.248 0.084 ;
    END
  END rec[553]
  PIN rec[554]
    DIRECTION INPUT ;
    USE SIGNAL ;
    PORT
      LAYER M5 ;
        RECT  46.32 0 46.344 0.084 ;
    END
  END rec[554]
  PIN rec[555]
    DIRECTION INPUT ;
    USE SIGNAL ;
    PORT
      LAYER M5 ;
        RECT  46.416 0 46.44 0.084 ;
    END
  END rec[555]
  PIN rec[556]
    DIRECTION INPUT ;
    USE SIGNAL ;
    PORT
      LAYER M5 ;
        RECT  46.512 0 46.536 0.084 ;
    END
  END rec[556]
  PIN rec[557]
    DIRECTION INPUT ;
    USE SIGNAL ;
    PORT
      LAYER M5 ;
        RECT  46.608 0 46.632 0.084 ;
    END
  END rec[557]
  PIN rec[558]
    DIRECTION INPUT ;
    USE SIGNAL ;
    PORT
      LAYER M5 ;
        RECT  46.704 0 46.728 0.084 ;
    END
  END rec[558]
  PIN rec[559]
    DIRECTION INPUT ;
    USE SIGNAL ;
    PORT
      LAYER M5 ;
        RECT  46.8 0 46.824 0.084 ;
    END
  END rec[559]
  PIN rec[55]
    DIRECTION INPUT ;
    USE SIGNAL ;
    PORT
      LAYER M5 ;
        RECT  34.512 0 34.536 0.084 ;
    END
  END rec[55]
  PIN rec[560]
    DIRECTION INPUT ;
    USE SIGNAL ;
    PORT
      LAYER M5 ;
        RECT  46.896 0 46.92 0.084 ;
    END
  END rec[560]
  PIN rec[561]
    DIRECTION INPUT ;
    USE SIGNAL ;
    PORT
      LAYER M5 ;
        RECT  46.992 0 47.016 0.084 ;
    END
  END rec[561]
  PIN rec[562]
    DIRECTION INPUT ;
    USE SIGNAL ;
    PORT
      LAYER M5 ;
        RECT  47.088 0 47.112 0.084 ;
    END
  END rec[562]
  PIN rec[563]
    DIRECTION INPUT ;
    USE SIGNAL ;
    PORT
      LAYER M5 ;
        RECT  47.184 0 47.208 0.084 ;
    END
  END rec[563]
  PIN rec[564]
    DIRECTION INPUT ;
    USE SIGNAL ;
    PORT
      LAYER M5 ;
        RECT  47.28 0 47.304 0.084 ;
    END
  END rec[564]
  PIN rec[565]
    DIRECTION INPUT ;
    USE SIGNAL ;
    PORT
      LAYER M5 ;
        RECT  47.376 0 47.4 0.084 ;
    END
  END rec[565]
  PIN rec[566]
    DIRECTION INPUT ;
    USE SIGNAL ;
    PORT
      LAYER M5 ;
        RECT  47.472 0 47.496 0.084 ;
    END
  END rec[566]
  PIN rec[567]
    DIRECTION INPUT ;
    USE SIGNAL ;
    PORT
      LAYER M5 ;
        RECT  47.568 0 47.592 0.084 ;
    END
  END rec[567]
  PIN rec[568]
    DIRECTION INPUT ;
    USE SIGNAL ;
    PORT
      LAYER M5 ;
        RECT  47.664 0 47.688 0.084 ;
    END
  END rec[568]
  PIN rec[569]
    DIRECTION INPUT ;
    USE SIGNAL ;
    PORT
      LAYER M5 ;
        RECT  47.76 0 47.784 0.084 ;
    END
  END rec[569]
  PIN rec[56]
    DIRECTION INPUT ;
    USE SIGNAL ;
    PORT
      LAYER M5 ;
        RECT  34.608 0 34.632 0.084 ;
    END
  END rec[56]
  PIN rec[570]
    DIRECTION INPUT ;
    USE SIGNAL ;
    PORT
      LAYER M5 ;
        RECT  47.856 0 47.88 0.084 ;
    END
  END rec[570]
  PIN rec[571]
    DIRECTION INPUT ;
    USE SIGNAL ;
    PORT
      LAYER M5 ;
        RECT  47.952 0 47.976 0.084 ;
    END
  END rec[571]
  PIN rec[572]
    DIRECTION INPUT ;
    USE SIGNAL ;
    PORT
      LAYER M5 ;
        RECT  48.048 0 48.072 0.084 ;
    END
  END rec[572]
  PIN rec[573]
    DIRECTION INPUT ;
    USE SIGNAL ;
    PORT
      LAYER M5 ;
        RECT  48.144 0 48.168 0.084 ;
    END
  END rec[573]
  PIN rec[574]
    DIRECTION INPUT ;
    USE SIGNAL ;
    PORT
      LAYER M5 ;
        RECT  48.24 0 48.264 0.084 ;
    END
  END rec[574]
  PIN rec[575]
    DIRECTION INPUT ;
    USE SIGNAL ;
    PORT
      LAYER M5 ;
        RECT  80.592 0 80.616 0.084 ;
    END
  END rec[575]
  PIN rec[576]
    DIRECTION INPUT ;
    USE SIGNAL ;
    PORT
      LAYER M5 ;
        RECT  80.688 0 80.712 0.084 ;
    END
  END rec[576]
  PIN rec[577]
    DIRECTION INPUT ;
    USE SIGNAL ;
    PORT
      LAYER M5 ;
        RECT  80.784 0 80.808 0.084 ;
    END
  END rec[577]
  PIN rec[578]
    DIRECTION INPUT ;
    USE SIGNAL ;
    PORT
      LAYER M5 ;
        RECT  80.88 0 80.904 0.084 ;
    END
  END rec[578]
  PIN rec[579]
    DIRECTION INPUT ;
    USE SIGNAL ;
    PORT
      LAYER M5 ;
        RECT  80.976 0 81 0.084 ;
    END
  END rec[579]
  PIN rec[57]
    DIRECTION INPUT ;
    USE SIGNAL ;
    PORT
      LAYER M5 ;
        RECT  34.704 0 34.728 0.084 ;
    END
  END rec[57]
  PIN rec[580]
    DIRECTION INPUT ;
    USE SIGNAL ;
    PORT
      LAYER M5 ;
        RECT  81.072 0 81.096 0.084 ;
    END
  END rec[580]
  PIN rec[581]
    DIRECTION INPUT ;
    USE SIGNAL ;
    PORT
      LAYER M5 ;
        RECT  81.168 0 81.192 0.084 ;
    END
  END rec[581]
  PIN rec[582]
    DIRECTION INPUT ;
    USE SIGNAL ;
    PORT
      LAYER M5 ;
        RECT  81.264 0 81.288 0.084 ;
    END
  END rec[582]
  PIN rec[583]
    DIRECTION INPUT ;
    USE SIGNAL ;
    PORT
      LAYER M5 ;
        RECT  81.36 0 81.384 0.084 ;
    END
  END rec[583]
  PIN rec[584]
    DIRECTION INPUT ;
    USE SIGNAL ;
    PORT
      LAYER M5 ;
        RECT  81.456 0 81.48 0.084 ;
    END
  END rec[584]
  PIN rec[585]
    DIRECTION INPUT ;
    USE SIGNAL ;
    PORT
      LAYER M5 ;
        RECT  81.552 0 81.576 0.084 ;
    END
  END rec[585]
  PIN rec[586]
    DIRECTION INPUT ;
    USE SIGNAL ;
    PORT
      LAYER M5 ;
        RECT  81.648 0 81.672 0.084 ;
    END
  END rec[586]
  PIN rec[587]
    DIRECTION INPUT ;
    USE SIGNAL ;
    PORT
      LAYER M5 ;
        RECT  81.744 0 81.768 0.084 ;
    END
  END rec[587]
  PIN rec[588]
    DIRECTION INPUT ;
    USE SIGNAL ;
    PORT
      LAYER M5 ;
        RECT  81.84 0 81.864 0.084 ;
    END
  END rec[588]
  PIN rec[589]
    DIRECTION INPUT ;
    USE SIGNAL ;
    PORT
      LAYER M5 ;
        RECT  81.936 0 81.96 0.084 ;
    END
  END rec[589]
  PIN rec[58]
    DIRECTION INPUT ;
    USE SIGNAL ;
    PORT
      LAYER M5 ;
        RECT  34.8 0 34.824 0.084 ;
    END
  END rec[58]
  PIN rec[590]
    DIRECTION INPUT ;
    USE SIGNAL ;
    PORT
      LAYER M5 ;
        RECT  82.032 0 82.056 0.084 ;
    END
  END rec[590]
  PIN rec[591]
    DIRECTION INPUT ;
    USE SIGNAL ;
    PORT
      LAYER M5 ;
        RECT  82.128 0 82.152 0.084 ;
    END
  END rec[591]
  PIN rec[592]
    DIRECTION INPUT ;
    USE SIGNAL ;
    PORT
      LAYER M5 ;
        RECT  82.224 0 82.248 0.084 ;
    END
  END rec[592]
  PIN rec[593]
    DIRECTION INPUT ;
    USE SIGNAL ;
    PORT
      LAYER M5 ;
        RECT  82.32 0 82.344 0.084 ;
    END
  END rec[593]
  PIN rec[594]
    DIRECTION INPUT ;
    USE SIGNAL ;
    PORT
      LAYER M5 ;
        RECT  82.416 0 82.44 0.084 ;
    END
  END rec[594]
  PIN rec[595]
    DIRECTION INPUT ;
    USE SIGNAL ;
    PORT
      LAYER M5 ;
        RECT  82.512 0 82.536 0.084 ;
    END
  END rec[595]
  PIN rec[596]
    DIRECTION INPUT ;
    USE SIGNAL ;
    PORT
      LAYER M5 ;
        RECT  82.608 0 82.632 0.084 ;
    END
  END rec[596]
  PIN rec[597]
    DIRECTION INPUT ;
    USE SIGNAL ;
    PORT
      LAYER M5 ;
        RECT  82.704 0 82.728 0.084 ;
    END
  END rec[597]
  PIN rec[598]
    DIRECTION INPUT ;
    USE SIGNAL ;
    PORT
      LAYER M5 ;
        RECT  82.8 0 82.824 0.084 ;
    END
  END rec[598]
  PIN rec[599]
    DIRECTION INPUT ;
    USE SIGNAL ;
    PORT
      LAYER M5 ;
        RECT  82.896 0 82.92 0.084 ;
    END
  END rec[599]
  PIN rec[59]
    DIRECTION INPUT ;
    USE SIGNAL ;
    PORT
      LAYER M5 ;
        RECT  34.896 0 34.92 0.084 ;
    END
  END rec[59]
  PIN rec[5]
    DIRECTION INPUT ;
    USE SIGNAL ;
    PORT
      LAYER M5 ;
        RECT  16.656 0 16.68 0.084 ;
    END
  END rec[5]
  PIN rec[600]
    DIRECTION INPUT ;
    USE SIGNAL ;
    PORT
      LAYER M5 ;
        RECT  82.992 0 83.016 0.084 ;
    END
  END rec[600]
  PIN rec[601]
    DIRECTION INPUT ;
    USE SIGNAL ;
    PORT
      LAYER M5 ;
        RECT  83.088 0 83.112 0.084 ;
    END
  END rec[601]
  PIN rec[602]
    DIRECTION INPUT ;
    USE SIGNAL ;
    PORT
      LAYER M5 ;
        RECT  83.184 0 83.208 0.084 ;
    END
  END rec[602]
  PIN rec[603]
    DIRECTION INPUT ;
    USE SIGNAL ;
    PORT
      LAYER M5 ;
        RECT  83.28 0 83.304 0.084 ;
    END
  END rec[603]
  PIN rec[604]
    DIRECTION INPUT ;
    USE SIGNAL ;
    PORT
      LAYER M5 ;
        RECT  83.376 0 83.4 0.084 ;
    END
  END rec[604]
  PIN rec[605]
    DIRECTION INPUT ;
    USE SIGNAL ;
    PORT
      LAYER M5 ;
        RECT  83.472 0 83.496 0.084 ;
    END
  END rec[605]
  PIN rec[606]
    DIRECTION INPUT ;
    USE SIGNAL ;
    PORT
      LAYER M5 ;
        RECT  83.568 0 83.592 0.084 ;
    END
  END rec[606]
  PIN rec[607]
    DIRECTION INPUT ;
    USE SIGNAL ;
    PORT
      LAYER M5 ;
        RECT  48.336 0 48.36 0.084 ;
    END
  END rec[607]
  PIN rec[608]
    DIRECTION INPUT ;
    USE SIGNAL ;
    PORT
      LAYER M5 ;
        RECT  48.432 0 48.456 0.084 ;
    END
  END rec[608]
  PIN rec[609]
    DIRECTION INPUT ;
    USE SIGNAL ;
    PORT
      LAYER M5 ;
        RECT  48.528 0 48.552 0.084 ;
    END
  END rec[609]
  PIN rec[60]
    DIRECTION INPUT ;
    USE SIGNAL ;
    PORT
      LAYER M5 ;
        RECT  34.992 0 35.016 0.084 ;
    END
  END rec[60]
  PIN rec[610]
    DIRECTION INPUT ;
    USE SIGNAL ;
    PORT
      LAYER M5 ;
        RECT  48.624 0 48.648 0.084 ;
    END
  END rec[610]
  PIN rec[611]
    DIRECTION INPUT ;
    USE SIGNAL ;
    PORT
      LAYER M5 ;
        RECT  48.72 0 48.744 0.084 ;
    END
  END rec[611]
  PIN rec[612]
    DIRECTION INPUT ;
    USE SIGNAL ;
    PORT
      LAYER M5 ;
        RECT  48.816 0 48.84 0.084 ;
    END
  END rec[612]
  PIN rec[613]
    DIRECTION INPUT ;
    USE SIGNAL ;
    PORT
      LAYER M5 ;
        RECT  48.912 0 48.936 0.084 ;
    END
  END rec[613]
  PIN rec[614]
    DIRECTION INPUT ;
    USE SIGNAL ;
    PORT
      LAYER M5 ;
        RECT  49.008 0 49.032 0.084 ;
    END
  END rec[614]
  PIN rec[615]
    DIRECTION INPUT ;
    USE SIGNAL ;
    PORT
      LAYER M5 ;
        RECT  49.104 0 49.128 0.084 ;
    END
  END rec[615]
  PIN rec[616]
    DIRECTION INPUT ;
    USE SIGNAL ;
    PORT
      LAYER M5 ;
        RECT  49.2 0 49.224 0.084 ;
    END
  END rec[616]
  PIN rec[617]
    DIRECTION INPUT ;
    USE SIGNAL ;
    PORT
      LAYER M5 ;
        RECT  49.296 0 49.32 0.084 ;
    END
  END rec[617]
  PIN rec[618]
    DIRECTION INPUT ;
    USE SIGNAL ;
    PORT
      LAYER M5 ;
        RECT  49.392 0 49.416 0.084 ;
    END
  END rec[618]
  PIN rec[619]
    DIRECTION INPUT ;
    USE SIGNAL ;
    PORT
      LAYER M5 ;
        RECT  49.488 0 49.512 0.084 ;
    END
  END rec[619]
  PIN rec[61]
    DIRECTION INPUT ;
    USE SIGNAL ;
    PORT
      LAYER M5 ;
        RECT  35.088 0 35.112 0.084 ;
    END
  END rec[61]
  PIN rec[620]
    DIRECTION INPUT ;
    USE SIGNAL ;
    PORT
      LAYER M5 ;
        RECT  49.584 0 49.608 0.084 ;
    END
  END rec[620]
  PIN rec[621]
    DIRECTION INPUT ;
    USE SIGNAL ;
    PORT
      LAYER M5 ;
        RECT  49.68 0 49.704 0.084 ;
    END
  END rec[621]
  PIN rec[622]
    DIRECTION INPUT ;
    USE SIGNAL ;
    PORT
      LAYER M5 ;
        RECT  49.776 0 49.8 0.084 ;
    END
  END rec[622]
  PIN rec[623]
    DIRECTION INPUT ;
    USE SIGNAL ;
    PORT
      LAYER M5 ;
        RECT  49.872 0 49.896 0.084 ;
    END
  END rec[623]
  PIN rec[624]
    DIRECTION INPUT ;
    USE SIGNAL ;
    PORT
      LAYER M5 ;
        RECT  49.968 0 49.992 0.084 ;
    END
  END rec[624]
  PIN rec[625]
    DIRECTION INPUT ;
    USE SIGNAL ;
    PORT
      LAYER M5 ;
        RECT  50.064 0 50.088 0.084 ;
    END
  END rec[625]
  PIN rec[626]
    DIRECTION INPUT ;
    USE SIGNAL ;
    PORT
      LAYER M5 ;
        RECT  50.16 0 50.184 0.084 ;
    END
  END rec[626]
  PIN rec[627]
    DIRECTION INPUT ;
    USE SIGNAL ;
    PORT
      LAYER M5 ;
        RECT  50.256 0 50.28 0.084 ;
    END
  END rec[627]
  PIN rec[628]
    DIRECTION INPUT ;
    USE SIGNAL ;
    PORT
      LAYER M5 ;
        RECT  50.352 0 50.376 0.084 ;
    END
  END rec[628]
  PIN rec[629]
    DIRECTION INPUT ;
    USE SIGNAL ;
    PORT
      LAYER M5 ;
        RECT  50.448 0 50.472 0.084 ;
    END
  END rec[629]
  PIN rec[62]
    DIRECTION INPUT ;
    USE SIGNAL ;
    PORT
      LAYER M5 ;
        RECT  35.184 0 35.208 0.084 ;
    END
  END rec[62]
  PIN rec[630]
    DIRECTION INPUT ;
    USE SIGNAL ;
    PORT
      LAYER M5 ;
        RECT  50.544 0 50.568 0.084 ;
    END
  END rec[630]
  PIN rec[631]
    DIRECTION INPUT ;
    USE SIGNAL ;
    PORT
      LAYER M5 ;
        RECT  50.64 0 50.664 0.084 ;
    END
  END rec[631]
  PIN rec[632]
    DIRECTION INPUT ;
    USE SIGNAL ;
    PORT
      LAYER M5 ;
        RECT  50.736 0 50.76 0.084 ;
    END
  END rec[632]
  PIN rec[633]
    DIRECTION INPUT ;
    USE SIGNAL ;
    PORT
      LAYER M5 ;
        RECT  50.832 0 50.856 0.084 ;
    END
  END rec[633]
  PIN rec[634]
    DIRECTION INPUT ;
    USE SIGNAL ;
    PORT
      LAYER M5 ;
        RECT  50.928 0 50.952 0.084 ;
    END
  END rec[634]
  PIN rec[635]
    DIRECTION INPUT ;
    USE SIGNAL ;
    PORT
      LAYER M5 ;
        RECT  51.024 0 51.048 0.084 ;
    END
  END rec[635]
  PIN rec[636]
    DIRECTION INPUT ;
    USE SIGNAL ;
    PORT
      LAYER M5 ;
        RECT  51.12 0 51.144 0.084 ;
    END
  END rec[636]
  PIN rec[637]
    DIRECTION INPUT ;
    USE SIGNAL ;
    PORT
      LAYER M5 ;
        RECT  51.216 0 51.24 0.084 ;
    END
  END rec[637]
  PIN rec[638]
    DIRECTION INPUT ;
    USE SIGNAL ;
    PORT
      LAYER M5 ;
        RECT  51.312 0 51.336 0.084 ;
    END
  END rec[638]
  PIN rec[639]
    DIRECTION INPUT ;
    USE SIGNAL ;
    PORT
      LAYER M5 ;
        RECT  22.992 0 23.016 0.084 ;
    END
  END rec[639]
  PIN rec[63]
    DIRECTION INPUT ;
    USE SIGNAL ;
    PORT
      LAYER M5 ;
        RECT  0.72 0 0.744 0.084 ;
    END
  END rec[63]
  PIN rec[640]
    DIRECTION INPUT ;
    USE SIGNAL ;
    PORT
      LAYER M5 ;
        RECT  23.088 0 23.112 0.084 ;
    END
  END rec[640]
  PIN rec[641]
    DIRECTION INPUT ;
    USE SIGNAL ;
    PORT
      LAYER M5 ;
        RECT  23.184 0 23.208 0.084 ;
    END
  END rec[641]
  PIN rec[642]
    DIRECTION INPUT ;
    USE SIGNAL ;
    PORT
      LAYER M5 ;
        RECT  23.28 0 23.304 0.084 ;
    END
  END rec[642]
  PIN rec[643]
    DIRECTION INPUT ;
    USE SIGNAL ;
    PORT
      LAYER M5 ;
        RECT  23.376 0 23.4 0.084 ;
    END
  END rec[643]
  PIN rec[644]
    DIRECTION INPUT ;
    USE SIGNAL ;
    PORT
      LAYER M5 ;
        RECT  23.472 0 23.496 0.084 ;
    END
  END rec[644]
  PIN rec[645]
    DIRECTION INPUT ;
    USE SIGNAL ;
    PORT
      LAYER M5 ;
        RECT  23.568 0 23.592 0.084 ;
    END
  END rec[645]
  PIN rec[646]
    DIRECTION INPUT ;
    USE SIGNAL ;
    PORT
      LAYER M5 ;
        RECT  23.664 0 23.688 0.084 ;
    END
  END rec[646]
  PIN rec[647]
    DIRECTION INPUT ;
    USE SIGNAL ;
    PORT
      LAYER M5 ;
        RECT  23.76 0 23.784 0.084 ;
    END
  END rec[647]
  PIN rec[648]
    DIRECTION INPUT ;
    USE SIGNAL ;
    PORT
      LAYER M5 ;
        RECT  23.856 0 23.88 0.084 ;
    END
  END rec[648]
  PIN rec[649]
    DIRECTION INPUT ;
    USE SIGNAL ;
    PORT
      LAYER M5 ;
        RECT  23.952 0 23.976 0.084 ;
    END
  END rec[649]
  PIN rec[64]
    DIRECTION INPUT ;
    USE SIGNAL ;
    PORT
      LAYER M5 ;
        RECT  0.816 0 0.84 0.084 ;
    END
  END rec[64]
  PIN rec[650]
    DIRECTION INPUT ;
    USE SIGNAL ;
    PORT
      LAYER M5 ;
        RECT  24.048 0 24.072 0.084 ;
    END
  END rec[650]
  PIN rec[651]
    DIRECTION INPUT ;
    USE SIGNAL ;
    PORT
      LAYER M5 ;
        RECT  24.144 0 24.168 0.084 ;
    END
  END rec[651]
  PIN rec[652]
    DIRECTION INPUT ;
    USE SIGNAL ;
    PORT
      LAYER M5 ;
        RECT  24.24 0 24.264 0.084 ;
    END
  END rec[652]
  PIN rec[653]
    DIRECTION INPUT ;
    USE SIGNAL ;
    PORT
      LAYER M5 ;
        RECT  24.336 0 24.36 0.084 ;
    END
  END rec[653]
  PIN rec[654]
    DIRECTION INPUT ;
    USE SIGNAL ;
    PORT
      LAYER M5 ;
        RECT  24.432 0 24.456 0.084 ;
    END
  END rec[654]
  PIN rec[655]
    DIRECTION INPUT ;
    USE SIGNAL ;
    PORT
      LAYER M5 ;
        RECT  24.528 0 24.552 0.084 ;
    END
  END rec[655]
  PIN rec[656]
    DIRECTION INPUT ;
    USE SIGNAL ;
    PORT
      LAYER M5 ;
        RECT  24.624 0 24.648 0.084 ;
    END
  END rec[656]
  PIN rec[657]
    DIRECTION INPUT ;
    USE SIGNAL ;
    PORT
      LAYER M5 ;
        RECT  24.72 0 24.744 0.084 ;
    END
  END rec[657]
  PIN rec[658]
    DIRECTION INPUT ;
    USE SIGNAL ;
    PORT
      LAYER M5 ;
        RECT  24.816 0 24.84 0.084 ;
    END
  END rec[658]
  PIN rec[659]
    DIRECTION INPUT ;
    USE SIGNAL ;
    PORT
      LAYER M5 ;
        RECT  24.912 0 24.936 0.084 ;
    END
  END rec[659]
  PIN rec[65]
    DIRECTION INPUT ;
    USE SIGNAL ;
    PORT
      LAYER M5 ;
        RECT  0.912 0 0.936 0.084 ;
    END
  END rec[65]
  PIN rec[660]
    DIRECTION INPUT ;
    USE SIGNAL ;
    PORT
      LAYER M5 ;
        RECT  25.008 0 25.032 0.084 ;
    END
  END rec[660]
  PIN rec[661]
    DIRECTION INPUT ;
    USE SIGNAL ;
    PORT
      LAYER M5 ;
        RECT  25.104 0 25.128 0.084 ;
    END
  END rec[661]
  PIN rec[662]
    DIRECTION INPUT ;
    USE SIGNAL ;
    PORT
      LAYER M5 ;
        RECT  25.2 0 25.224 0.084 ;
    END
  END rec[662]
  PIN rec[663]
    DIRECTION INPUT ;
    USE SIGNAL ;
    PORT
      LAYER M5 ;
        RECT  25.296 0 25.32 0.084 ;
    END
  END rec[663]
  PIN rec[664]
    DIRECTION INPUT ;
    USE SIGNAL ;
    PORT
      LAYER M5 ;
        RECT  25.392 0 25.416 0.084 ;
    END
  END rec[664]
  PIN rec[665]
    DIRECTION INPUT ;
    USE SIGNAL ;
    PORT
      LAYER M5 ;
        RECT  25.488 0 25.512 0.084 ;
    END
  END rec[665]
  PIN rec[666]
    DIRECTION INPUT ;
    USE SIGNAL ;
    PORT
      LAYER M5 ;
        RECT  25.584 0 25.608 0.084 ;
    END
  END rec[666]
  PIN rec[667]
    DIRECTION INPUT ;
    USE SIGNAL ;
    PORT
      LAYER M5 ;
        RECT  25.68 0 25.704 0.084 ;
    END
  END rec[667]
  PIN rec[668]
    DIRECTION INPUT ;
    USE SIGNAL ;
    PORT
      LAYER M5 ;
        RECT  25.776 0 25.8 0.084 ;
    END
  END rec[668]
  PIN rec[669]
    DIRECTION INPUT ;
    USE SIGNAL ;
    PORT
      LAYER M5 ;
        RECT  25.872 0 25.896 0.084 ;
    END
  END rec[669]
  PIN rec[66]
    DIRECTION INPUT ;
    USE SIGNAL ;
    PORT
      LAYER M5 ;
        RECT  1.008 0 1.032 0.084 ;
    END
  END rec[66]
  PIN rec[670]
    DIRECTION INPUT ;
    USE SIGNAL ;
    PORT
      LAYER M5 ;
        RECT  25.968 0 25.992 0.084 ;
    END
  END rec[670]
  PIN rec[671]
    DIRECTION INPUT ;
    USE SIGNAL ;
    PORT
      LAYER M5 ;
        RECT  39.12 0 39.144 0.084 ;
    END
  END rec[671]
  PIN rec[672]
    DIRECTION INPUT ;
    USE SIGNAL ;
    PORT
      LAYER M5 ;
        RECT  39.216 0 39.24 0.084 ;
    END
  END rec[672]
  PIN rec[673]
    DIRECTION INPUT ;
    USE SIGNAL ;
    PORT
      LAYER M5 ;
        RECT  39.312 0 39.336 0.084 ;
    END
  END rec[673]
  PIN rec[674]
    DIRECTION INPUT ;
    USE SIGNAL ;
    PORT
      LAYER M5 ;
        RECT  39.408 0 39.432 0.084 ;
    END
  END rec[674]
  PIN rec[675]
    DIRECTION INPUT ;
    USE SIGNAL ;
    PORT
      LAYER M5 ;
        RECT  39.504 0 39.528 0.084 ;
    END
  END rec[675]
  PIN rec[676]
    DIRECTION INPUT ;
    USE SIGNAL ;
    PORT
      LAYER M5 ;
        RECT  39.6 0 39.624 0.084 ;
    END
  END rec[676]
  PIN rec[677]
    DIRECTION INPUT ;
    USE SIGNAL ;
    PORT
      LAYER M5 ;
        RECT  39.696 0 39.72 0.084 ;
    END
  END rec[677]
  PIN rec[678]
    DIRECTION INPUT ;
    USE SIGNAL ;
    PORT
      LAYER M5 ;
        RECT  39.792 0 39.816 0.084 ;
    END
  END rec[678]
  PIN rec[679]
    DIRECTION INPUT ;
    USE SIGNAL ;
    PORT
      LAYER M5 ;
        RECT  39.888 0 39.912 0.084 ;
    END
  END rec[679]
  PIN rec[67]
    DIRECTION INPUT ;
    USE SIGNAL ;
    PORT
      LAYER M5 ;
        RECT  1.104 0 1.128 0.084 ;
    END
  END rec[67]
  PIN rec[680]
    DIRECTION INPUT ;
    USE SIGNAL ;
    PORT
      LAYER M5 ;
        RECT  39.984 0 40.008 0.084 ;
    END
  END rec[680]
  PIN rec[681]
    DIRECTION INPUT ;
    USE SIGNAL ;
    PORT
      LAYER M5 ;
        RECT  40.08 0 40.104 0.084 ;
    END
  END rec[681]
  PIN rec[682]
    DIRECTION INPUT ;
    USE SIGNAL ;
    PORT
      LAYER M5 ;
        RECT  40.176 0 40.2 0.084 ;
    END
  END rec[682]
  PIN rec[68]
    DIRECTION INPUT ;
    USE SIGNAL ;
    PORT
      LAYER M5 ;
        RECT  1.2 0 1.224 0.084 ;
    END
  END rec[68]
  PIN rec[69]
    DIRECTION INPUT ;
    USE SIGNAL ;
    PORT
      LAYER M5 ;
        RECT  1.296 0 1.32 0.084 ;
    END
  END rec[69]
  PIN rec[6]
    DIRECTION INPUT ;
    USE SIGNAL ;
    PORT
      LAYER M5 ;
        RECT  16.752 0 16.776 0.084 ;
    END
  END rec[6]
  PIN rec[70]
    DIRECTION INPUT ;
    USE SIGNAL ;
    PORT
      LAYER M5 ;
        RECT  1.392 0 1.416 0.084 ;
    END
  END rec[70]
  PIN rec[71]
    DIRECTION INPUT ;
    USE SIGNAL ;
    PORT
      LAYER M5 ;
        RECT  1.488 0 1.512 0.084 ;
    END
  END rec[71]
  PIN rec[72]
    DIRECTION INPUT ;
    USE SIGNAL ;
    PORT
      LAYER M5 ;
        RECT  1.584 0 1.608 0.084 ;
    END
  END rec[72]
  PIN rec[73]
    DIRECTION INPUT ;
    USE SIGNAL ;
    PORT
      LAYER M5 ;
        RECT  1.68 0 1.704 0.084 ;
    END
  END rec[73]
  PIN rec[74]
    DIRECTION INPUT ;
    USE SIGNAL ;
    PORT
      LAYER M5 ;
        RECT  1.776 0 1.8 0.084 ;
    END
  END rec[74]
  PIN rec[75]
    DIRECTION INPUT ;
    USE SIGNAL ;
    PORT
      LAYER M5 ;
        RECT  1.872 0 1.896 0.084 ;
    END
  END rec[75]
  PIN rec[76]
    DIRECTION INPUT ;
    USE SIGNAL ;
    PORT
      LAYER M5 ;
        RECT  1.968 0 1.992 0.084 ;
    END
  END rec[76]
  PIN rec[77]
    DIRECTION INPUT ;
    USE SIGNAL ;
    PORT
      LAYER M5 ;
        RECT  2.064 0 2.088 0.084 ;
    END
  END rec[77]
  PIN rec[78]
    DIRECTION INPUT ;
    USE SIGNAL ;
    PORT
      LAYER M5 ;
        RECT  2.16 0 2.184 0.084 ;
    END
  END rec[78]
  PIN rec[79]
    DIRECTION INPUT ;
    USE SIGNAL ;
    PORT
      LAYER M5 ;
        RECT  2.256 0 2.28 0.084 ;
    END
  END rec[79]
  PIN rec[7]
    DIRECTION INPUT ;
    USE SIGNAL ;
    PORT
      LAYER M5 ;
        RECT  16.848 0 16.872 0.084 ;
    END
  END rec[7]
  PIN rec[80]
    DIRECTION INPUT ;
    USE SIGNAL ;
    PORT
      LAYER M5 ;
        RECT  2.352 0 2.376 0.084 ;
    END
  END rec[80]
  PIN rec[81]
    DIRECTION INPUT ;
    USE SIGNAL ;
    PORT
      LAYER M5 ;
        RECT  2.448 0 2.472 0.084 ;
    END
  END rec[81]
  PIN rec[82]
    DIRECTION INPUT ;
    USE SIGNAL ;
    PORT
      LAYER M5 ;
        RECT  2.544 0 2.568 0.084 ;
    END
  END rec[82]
  PIN rec[83]
    DIRECTION INPUT ;
    USE SIGNAL ;
    PORT
      LAYER M5 ;
        RECT  2.64 0 2.664 0.084 ;
    END
  END rec[83]
  PIN rec[84]
    DIRECTION INPUT ;
    USE SIGNAL ;
    PORT
      LAYER M5 ;
        RECT  2.736 0 2.76 0.084 ;
    END
  END rec[84]
  PIN rec[85]
    DIRECTION INPUT ;
    USE SIGNAL ;
    PORT
      LAYER M5 ;
        RECT  2.832 0 2.856 0.084 ;
    END
  END rec[85]
  PIN rec[86]
    DIRECTION INPUT ;
    USE SIGNAL ;
    PORT
      LAYER M5 ;
        RECT  2.928 0 2.952 0.084 ;
    END
  END rec[86]
  PIN rec[87]
    DIRECTION INPUT ;
    USE SIGNAL ;
    PORT
      LAYER M5 ;
        RECT  3.024 0 3.048 0.084 ;
    END
  END rec[87]
  PIN rec[88]
    DIRECTION INPUT ;
    USE SIGNAL ;
    PORT
      LAYER M5 ;
        RECT  3.12 0 3.144 0.084 ;
    END
  END rec[88]
  PIN rec[89]
    DIRECTION INPUT ;
    USE SIGNAL ;
    PORT
      LAYER M5 ;
        RECT  3.216 0 3.24 0.084 ;
    END
  END rec[89]
  PIN rec[8]
    DIRECTION INPUT ;
    USE SIGNAL ;
    PORT
      LAYER M5 ;
        RECT  16.944 0 16.968 0.084 ;
    END
  END rec[8]
  PIN rec[90]
    DIRECTION INPUT ;
    USE SIGNAL ;
    PORT
      LAYER M5 ;
        RECT  3.312 0 3.336 0.084 ;
    END
  END rec[90]
  PIN rec[91]
    DIRECTION INPUT ;
    USE SIGNAL ;
    PORT
      LAYER M5 ;
        RECT  3.408 0 3.432 0.084 ;
    END
  END rec[91]
  PIN rec[92]
    DIRECTION INPUT ;
    USE SIGNAL ;
    PORT
      LAYER M5 ;
        RECT  3.504 0 3.528 0.084 ;
    END
  END rec[92]
  PIN rec[93]
    DIRECTION INPUT ;
    USE SIGNAL ;
    PORT
      LAYER M5 ;
        RECT  3.6 0 3.624 0.084 ;
    END
  END rec[93]
  PIN rec[94]
    DIRECTION INPUT ;
    USE SIGNAL ;
    PORT
      LAYER M5 ;
        RECT  3.696 0 3.72 0.084 ;
    END
  END rec[94]
  PIN rec[95]
    DIRECTION INPUT ;
    USE SIGNAL ;
    PORT
      LAYER M5 ;
        RECT  6.864 0 6.888 0.084 ;
    END
  END rec[95]
  PIN rec[96]
    DIRECTION INPUT ;
    USE SIGNAL ;
    PORT
      LAYER M5 ;
        RECT  6.96 0 6.984 0.084 ;
    END
  END rec[96]
  PIN rec[97]
    DIRECTION INPUT ;
    USE SIGNAL ;
    PORT
      LAYER M5 ;
        RECT  7.056 0 7.08 0.084 ;
    END
  END rec[97]
  PIN rec[98]
    DIRECTION INPUT ;
    USE SIGNAL ;
    PORT
      LAYER M5 ;
        RECT  7.152 0 7.176 0.084 ;
    END
  END rec[98]
  PIN rec[99]
    DIRECTION INPUT ;
    USE SIGNAL ;
    PORT
      LAYER M5 ;
        RECT  7.248 0 7.272 0.084 ;
    END
  END rec[99]
  PIN rec[9]
    DIRECTION INPUT ;
    USE SIGNAL ;
    PORT
      LAYER M5 ;
        RECT  17.04 0 17.064 0.084 ;
    END
  END rec[9]
  PIN rst_n
    DIRECTION INPUT ;
    USE SIGNAL ;
    PORT
      LAYER M5 ;
        RECT  40.272 0 40.296 0.084 ;
    END
  END rst_n
  PIN s1_v
    DIRECTION OUTPUT ;
    USE SIGNAL ;
    PORT
      LAYER M5 ;
        RECT  5.904 71.196 5.928 71.28 ;
    END
  END s1_v
  PIN s3[0]
    DIRECTION OUTPUT ;
    USE SIGNAL ;
    PORT
      LAYER M5 ;
        RECT  6 71.196 6.024 71.28 ;
    END
  END s3[0]
  PIN s3[100]
    DIRECTION OUTPUT ;
    USE SIGNAL ;
    PORT
      LAYER M5 ;
        RECT  77.04 71.196 77.064 71.28 ;
    END
  END s3[100]
  PIN s3[101]
    DIRECTION OUTPUT ;
    USE SIGNAL ;
    PORT
      LAYER M5 ;
        RECT  77.136 71.196 77.16 71.28 ;
    END
  END s3[101]
  PIN s3[102]
    DIRECTION OUTPUT ;
    USE SIGNAL ;
    PORT
      LAYER M5 ;
        RECT  77.232 71.196 77.256 71.28 ;
    END
  END s3[102]
  PIN s3[103]
    DIRECTION OUTPUT ;
    USE SIGNAL ;
    PORT
      LAYER M5 ;
        RECT  77.328 71.196 77.352 71.28 ;
    END
  END s3[103]
  PIN s3[104]
    DIRECTION OUTPUT ;
    USE SIGNAL ;
    PORT
      LAYER M5 ;
        RECT  77.424 71.196 77.448 71.28 ;
    END
  END s3[104]
  PIN s3[105]
    DIRECTION OUTPUT ;
    USE SIGNAL ;
    PORT
      LAYER M5 ;
        RECT  77.52 71.196 77.544 71.28 ;
    END
  END s3[105]
  PIN s3[106]
    DIRECTION OUTPUT ;
    USE SIGNAL ;
    PORT
      LAYER M5 ;
        RECT  77.616 71.196 77.64 71.28 ;
    END
  END s3[106]
  PIN s3[107]
    DIRECTION OUTPUT ;
    USE SIGNAL ;
    PORT
      LAYER M5 ;
        RECT  77.712 71.196 77.736 71.28 ;
    END
  END s3[107]
  PIN s3[108]
    DIRECTION OUTPUT ;
    USE SIGNAL ;
    PORT
      LAYER M5 ;
        RECT  77.808 71.196 77.832 71.28 ;
    END
  END s3[108]
  PIN s3[109]
    DIRECTION OUTPUT ;
    USE SIGNAL ;
    PORT
      LAYER M5 ;
        RECT  77.904 71.196 77.928 71.28 ;
    END
  END s3[109]
  PIN s3[10]
    DIRECTION OUTPUT ;
    USE SIGNAL ;
    PORT
      LAYER M5 ;
        RECT  6.96 71.196 6.984 71.28 ;
    END
  END s3[10]
  PIN s3[110]
    DIRECTION OUTPUT ;
    USE SIGNAL ;
    PORT
      LAYER M5 ;
        RECT  78 71.196 78.024 71.28 ;
    END
  END s3[110]
  PIN s3[111]
    DIRECTION OUTPUT ;
    USE SIGNAL ;
    PORT
      LAYER M5 ;
        RECT  78.096 71.196 78.12 71.28 ;
    END
  END s3[111]
  PIN s3[112]
    DIRECTION OUTPUT ;
    USE SIGNAL ;
    PORT
      LAYER M5 ;
        RECT  78.192 71.196 78.216 71.28 ;
    END
  END s3[112]
  PIN s3[113]
    DIRECTION OUTPUT ;
    USE SIGNAL ;
    PORT
      LAYER M5 ;
        RECT  78.288 71.196 78.312 71.28 ;
    END
  END s3[113]
  PIN s3[114]
    DIRECTION OUTPUT ;
    USE SIGNAL ;
    PORT
      LAYER M5 ;
        RECT  78.384 71.196 78.408 71.28 ;
    END
  END s3[114]
  PIN s3[115]
    DIRECTION OUTPUT ;
    USE SIGNAL ;
    PORT
      LAYER M5 ;
        RECT  78.48 71.196 78.504 71.28 ;
    END
  END s3[115]
  PIN s3[116]
    DIRECTION OUTPUT ;
    USE SIGNAL ;
    PORT
      LAYER M5 ;
        RECT  78.576 71.196 78.6 71.28 ;
    END
  END s3[116]
  PIN s3[117]
    DIRECTION OUTPUT ;
    USE SIGNAL ;
    PORT
      LAYER M5 ;
        RECT  78.672 71.196 78.696 71.28 ;
    END
  END s3[117]
  PIN s3[118]
    DIRECTION OUTPUT ;
    USE SIGNAL ;
    PORT
      LAYER M5 ;
        RECT  78.768 71.196 78.792 71.28 ;
    END
  END s3[118]
  PIN s3[119]
    DIRECTION OUTPUT ;
    USE SIGNAL ;
    PORT
      LAYER M5 ;
        RECT  78.864 71.196 78.888 71.28 ;
    END
  END s3[119]
  PIN s3[11]
    DIRECTION OUTPUT ;
    USE SIGNAL ;
    PORT
      LAYER M5 ;
        RECT  7.056 71.196 7.08 71.28 ;
    END
  END s3[11]
  PIN s3[120]
    DIRECTION OUTPUT ;
    USE SIGNAL ;
    PORT
      LAYER M5 ;
        RECT  78.96 71.196 78.984 71.28 ;
    END
  END s3[120]
  PIN s3[121]
    DIRECTION OUTPUT ;
    USE SIGNAL ;
    PORT
      LAYER M5 ;
        RECT  79.056 71.196 79.08 71.28 ;
    END
  END s3[121]
  PIN s3[122]
    DIRECTION OUTPUT ;
    USE SIGNAL ;
    PORT
      LAYER M5 ;
        RECT  79.152 71.196 79.176 71.28 ;
    END
  END s3[122]
  PIN s3[123]
    DIRECTION OUTPUT ;
    USE SIGNAL ;
    PORT
      LAYER M5 ;
        RECT  79.248 71.196 79.272 71.28 ;
    END
  END s3[123]
  PIN s3[124]
    DIRECTION OUTPUT ;
    USE SIGNAL ;
    PORT
      LAYER M5 ;
        RECT  79.344 71.196 79.368 71.28 ;
    END
  END s3[124]
  PIN s3[125]
    DIRECTION OUTPUT ;
    USE SIGNAL ;
    PORT
      LAYER M5 ;
        RECT  79.44 71.196 79.464 71.28 ;
    END
  END s3[125]
  PIN s3[126]
    DIRECTION OUTPUT ;
    USE SIGNAL ;
    PORT
      LAYER M5 ;
        RECT  70.32 71.196 70.344 71.28 ;
    END
  END s3[126]
  PIN s3[127]
    DIRECTION OUTPUT ;
    USE SIGNAL ;
    PORT
      LAYER M5 ;
        RECT  70.416 71.196 70.44 71.28 ;
    END
  END s3[127]
  PIN s3[128]
    DIRECTION OUTPUT ;
    USE SIGNAL ;
    PORT
      LAYER M5 ;
        RECT  70.512 71.196 70.536 71.28 ;
    END
  END s3[128]
  PIN s3[129]
    DIRECTION OUTPUT ;
    USE SIGNAL ;
    PORT
      LAYER M5 ;
        RECT  70.608 71.196 70.632 71.28 ;
    END
  END s3[129]
  PIN s3[12]
    DIRECTION OUTPUT ;
    USE SIGNAL ;
    PORT
      LAYER M5 ;
        RECT  7.152 71.196 7.176 71.28 ;
    END
  END s3[12]
  PIN s3[130]
    DIRECTION OUTPUT ;
    USE SIGNAL ;
    PORT
      LAYER M5 ;
        RECT  70.704 71.196 70.728 71.28 ;
    END
  END s3[130]
  PIN s3[131]
    DIRECTION OUTPUT ;
    USE SIGNAL ;
    PORT
      LAYER M5 ;
        RECT  70.8 71.196 70.824 71.28 ;
    END
  END s3[131]
  PIN s3[132]
    DIRECTION OUTPUT ;
    USE SIGNAL ;
    PORT
      LAYER M5 ;
        RECT  70.896 71.196 70.92 71.28 ;
    END
  END s3[132]
  PIN s3[133]
    DIRECTION OUTPUT ;
    USE SIGNAL ;
    PORT
      LAYER M5 ;
        RECT  70.992 71.196 71.016 71.28 ;
    END
  END s3[133]
  PIN s3[134]
    DIRECTION OUTPUT ;
    USE SIGNAL ;
    PORT
      LAYER M5 ;
        RECT  71.088 71.196 71.112 71.28 ;
    END
  END s3[134]
  PIN s3[135]
    DIRECTION OUTPUT ;
    USE SIGNAL ;
    PORT
      LAYER M5 ;
        RECT  71.184 71.196 71.208 71.28 ;
    END
  END s3[135]
  PIN s3[136]
    DIRECTION OUTPUT ;
    USE SIGNAL ;
    PORT
      LAYER M5 ;
        RECT  71.28 71.196 71.304 71.28 ;
    END
  END s3[136]
  PIN s3[137]
    DIRECTION OUTPUT ;
    USE SIGNAL ;
    PORT
      LAYER M5 ;
        RECT  71.376 71.196 71.4 71.28 ;
    END
  END s3[137]
  PIN s3[138]
    DIRECTION OUTPUT ;
    USE SIGNAL ;
    PORT
      LAYER M5 ;
        RECT  71.472 71.196 71.496 71.28 ;
    END
  END s3[138]
  PIN s3[139]
    DIRECTION OUTPUT ;
    USE SIGNAL ;
    PORT
      LAYER M5 ;
        RECT  71.568 71.196 71.592 71.28 ;
    END
  END s3[139]
  PIN s3[13]
    DIRECTION OUTPUT ;
    USE SIGNAL ;
    PORT
      LAYER M5 ;
        RECT  7.248 71.196 7.272 71.28 ;
    END
  END s3[13]
  PIN s3[140]
    DIRECTION OUTPUT ;
    USE SIGNAL ;
    PORT
      LAYER M5 ;
        RECT  71.664 71.196 71.688 71.28 ;
    END
  END s3[140]
  PIN s3[141]
    DIRECTION OUTPUT ;
    USE SIGNAL ;
    PORT
      LAYER M5 ;
        RECT  71.76 71.196 71.784 71.28 ;
    END
  END s3[141]
  PIN s3[142]
    DIRECTION OUTPUT ;
    USE SIGNAL ;
    PORT
      LAYER M5 ;
        RECT  71.856 71.196 71.88 71.28 ;
    END
  END s3[142]
  PIN s3[143]
    DIRECTION OUTPUT ;
    USE SIGNAL ;
    PORT
      LAYER M5 ;
        RECT  71.952 71.196 71.976 71.28 ;
    END
  END s3[143]
  PIN s3[144]
    DIRECTION OUTPUT ;
    USE SIGNAL ;
    PORT
      LAYER M5 ;
        RECT  72.048 71.196 72.072 71.28 ;
    END
  END s3[144]
  PIN s3[145]
    DIRECTION OUTPUT ;
    USE SIGNAL ;
    PORT
      LAYER M5 ;
        RECT  72.144 71.196 72.168 71.28 ;
    END
  END s3[145]
  PIN s3[146]
    DIRECTION OUTPUT ;
    USE SIGNAL ;
    PORT
      LAYER M5 ;
        RECT  72.24 71.196 72.264 71.28 ;
    END
  END s3[146]
  PIN s3[147]
    DIRECTION OUTPUT ;
    USE SIGNAL ;
    PORT
      LAYER M5 ;
        RECT  72.336 71.196 72.36 71.28 ;
    END
  END s3[147]
  PIN s3[148]
    DIRECTION OUTPUT ;
    USE SIGNAL ;
    PORT
      LAYER M5 ;
        RECT  72.432 71.196 72.456 71.28 ;
    END
  END s3[148]
  PIN s3[149]
    DIRECTION OUTPUT ;
    USE SIGNAL ;
    PORT
      LAYER M5 ;
        RECT  72.528 71.196 72.552 71.28 ;
    END
  END s3[149]
  PIN s3[14]
    DIRECTION OUTPUT ;
    USE SIGNAL ;
    PORT
      LAYER M5 ;
        RECT  7.344 71.196 7.368 71.28 ;
    END
  END s3[14]
  PIN s3[150]
    DIRECTION OUTPUT ;
    USE SIGNAL ;
    PORT
      LAYER M5 ;
        RECT  72.624 71.196 72.648 71.28 ;
    END
  END s3[150]
  PIN s3[151]
    DIRECTION OUTPUT ;
    USE SIGNAL ;
    PORT
      LAYER M5 ;
        RECT  72.72 71.196 72.744 71.28 ;
    END
  END s3[151]
  PIN s3[152]
    DIRECTION OUTPUT ;
    USE SIGNAL ;
    PORT
      LAYER M5 ;
        RECT  72.816 71.196 72.84 71.28 ;
    END
  END s3[152]
  PIN s3[153]
    DIRECTION OUTPUT ;
    USE SIGNAL ;
    PORT
      LAYER M5 ;
        RECT  72.912 71.196 72.936 71.28 ;
    END
  END s3[153]
  PIN s3[154]
    DIRECTION OUTPUT ;
    USE SIGNAL ;
    PORT
      LAYER M5 ;
        RECT  73.008 71.196 73.032 71.28 ;
    END
  END s3[154]
  PIN s3[155]
    DIRECTION OUTPUT ;
    USE SIGNAL ;
    PORT
      LAYER M5 ;
        RECT  73.104 71.196 73.128 71.28 ;
    END
  END s3[155]
  PIN s3[156]
    DIRECTION OUTPUT ;
    USE SIGNAL ;
    PORT
      LAYER M5 ;
        RECT  73.2 71.196 73.224 71.28 ;
    END
  END s3[156]
  PIN s3[157]
    DIRECTION OUTPUT ;
    USE SIGNAL ;
    PORT
      LAYER M5 ;
        RECT  73.296 71.196 73.32 71.28 ;
    END
  END s3[157]
  PIN s3[158]
    DIRECTION OUTPUT ;
    USE SIGNAL ;
    PORT
      LAYER M5 ;
        RECT  73.392 71.196 73.416 71.28 ;
    END
  END s3[158]
  PIN s3[159]
    DIRECTION OUTPUT ;
    USE SIGNAL ;
    PORT
      LAYER M5 ;
        RECT  73.488 71.196 73.512 71.28 ;
    END
  END s3[159]
  PIN s3[15]
    DIRECTION OUTPUT ;
    USE SIGNAL ;
    PORT
      LAYER M5 ;
        RECT  7.44 71.196 7.464 71.28 ;
    END
  END s3[15]
  PIN s3[160]
    DIRECTION OUTPUT ;
    USE SIGNAL ;
    PORT
      LAYER M5 ;
        RECT  73.584 71.196 73.608 71.28 ;
    END
  END s3[160]
  PIN s3[161]
    DIRECTION OUTPUT ;
    USE SIGNAL ;
    PORT
      LAYER M5 ;
        RECT  73.68 71.196 73.704 71.28 ;
    END
  END s3[161]
  PIN s3[162]
    DIRECTION OUTPUT ;
    USE SIGNAL ;
    PORT
      LAYER M5 ;
        RECT  73.776 71.196 73.8 71.28 ;
    END
  END s3[162]
  PIN s3[163]
    DIRECTION OUTPUT ;
    USE SIGNAL ;
    PORT
      LAYER M5 ;
        RECT  73.872 71.196 73.896 71.28 ;
    END
  END s3[163]
  PIN s3[164]
    DIRECTION OUTPUT ;
    USE SIGNAL ;
    PORT
      LAYER M5 ;
        RECT  73.968 71.196 73.992 71.28 ;
    END
  END s3[164]
  PIN s3[165]
    DIRECTION OUTPUT ;
    USE SIGNAL ;
    PORT
      LAYER M5 ;
        RECT  74.064 71.196 74.088 71.28 ;
    END
  END s3[165]
  PIN s3[166]
    DIRECTION OUTPUT ;
    USE SIGNAL ;
    PORT
      LAYER M5 ;
        RECT  74.16 71.196 74.184 71.28 ;
    END
  END s3[166]
  PIN s3[167]
    DIRECTION OUTPUT ;
    USE SIGNAL ;
    PORT
      LAYER M5 ;
        RECT  74.256 71.196 74.28 71.28 ;
    END
  END s3[167]
  PIN s3[168]
    DIRECTION OUTPUT ;
    USE SIGNAL ;
    PORT
      LAYER M5 ;
        RECT  74.352 71.196 74.376 71.28 ;
    END
  END s3[168]
  PIN s3[169]
    DIRECTION OUTPUT ;
    USE SIGNAL ;
    PORT
      LAYER M5 ;
        RECT  74.448 71.196 74.472 71.28 ;
    END
  END s3[169]
  PIN s3[16]
    DIRECTION OUTPUT ;
    USE SIGNAL ;
    PORT
      LAYER M5 ;
        RECT  7.536 71.196 7.56 71.28 ;
    END
  END s3[16]
  PIN s3[170]
    DIRECTION OUTPUT ;
    USE SIGNAL ;
    PORT
      LAYER M5 ;
        RECT  74.544 71.196 74.568 71.28 ;
    END
  END s3[170]
  PIN s3[171]
    DIRECTION OUTPUT ;
    USE SIGNAL ;
    PORT
      LAYER M5 ;
        RECT  74.64 71.196 74.664 71.28 ;
    END
  END s3[171]
  PIN s3[172]
    DIRECTION OUTPUT ;
    USE SIGNAL ;
    PORT
      LAYER M5 ;
        RECT  74.736 71.196 74.76 71.28 ;
    END
  END s3[172]
  PIN s3[173]
    DIRECTION OUTPUT ;
    USE SIGNAL ;
    PORT
      LAYER M5 ;
        RECT  74.832 71.196 74.856 71.28 ;
    END
  END s3[173]
  PIN s3[174]
    DIRECTION OUTPUT ;
    USE SIGNAL ;
    PORT
      LAYER M5 ;
        RECT  74.928 71.196 74.952 71.28 ;
    END
  END s3[174]
  PIN s3[175]
    DIRECTION OUTPUT ;
    USE SIGNAL ;
    PORT
      LAYER M5 ;
        RECT  75.024 71.196 75.048 71.28 ;
    END
  END s3[175]
  PIN s3[176]
    DIRECTION OUTPUT ;
    USE SIGNAL ;
    PORT
      LAYER M5 ;
        RECT  75.12 71.196 75.144 71.28 ;
    END
  END s3[176]
  PIN s3[177]
    DIRECTION OUTPUT ;
    USE SIGNAL ;
    PORT
      LAYER M5 ;
        RECT  75.216 71.196 75.24 71.28 ;
    END
  END s3[177]
  PIN s3[178]
    DIRECTION OUTPUT ;
    USE SIGNAL ;
    PORT
      LAYER M5 ;
        RECT  75.312 71.196 75.336 71.28 ;
    END
  END s3[178]
  PIN s3[179]
    DIRECTION OUTPUT ;
    USE SIGNAL ;
    PORT
      LAYER M5 ;
        RECT  75.408 71.196 75.432 71.28 ;
    END
  END s3[179]
  PIN s3[17]
    DIRECTION OUTPUT ;
    USE SIGNAL ;
    PORT
      LAYER M5 ;
        RECT  7.632 71.196 7.656 71.28 ;
    END
  END s3[17]
  PIN s3[180]
    DIRECTION OUTPUT ;
    USE SIGNAL ;
    PORT
      LAYER M5 ;
        RECT  75.504 71.196 75.528 71.28 ;
    END
  END s3[180]
  PIN s3[181]
    DIRECTION OUTPUT ;
    USE SIGNAL ;
    PORT
      LAYER M5 ;
        RECT  75.6 71.196 75.624 71.28 ;
    END
  END s3[181]
  PIN s3[182]
    DIRECTION OUTPUT ;
    USE SIGNAL ;
    PORT
      LAYER M5 ;
        RECT  75.696 71.196 75.72 71.28 ;
    END
  END s3[182]
  PIN s3[183]
    DIRECTION OUTPUT ;
    USE SIGNAL ;
    PORT
      LAYER M5 ;
        RECT  75.792 71.196 75.816 71.28 ;
    END
  END s3[183]
  PIN s3[184]
    DIRECTION OUTPUT ;
    USE SIGNAL ;
    PORT
      LAYER M5 ;
        RECT  75.888 71.196 75.912 71.28 ;
    END
  END s3[184]
  PIN s3[185]
    DIRECTION OUTPUT ;
    USE SIGNAL ;
    PORT
      LAYER M5 ;
        RECT  75.984 71.196 76.008 71.28 ;
    END
  END s3[185]
  PIN s3[186]
    DIRECTION OUTPUT ;
    USE SIGNAL ;
    PORT
      LAYER M5 ;
        RECT  76.08 71.196 76.104 71.28 ;
    END
  END s3[186]
  PIN s3[187]
    DIRECTION OUTPUT ;
    USE SIGNAL ;
    PORT
      LAYER M5 ;
        RECT  76.176 71.196 76.2 71.28 ;
    END
  END s3[187]
  PIN s3[188]
    DIRECTION OUTPUT ;
    USE SIGNAL ;
    PORT
      LAYER M5 ;
        RECT  76.272 71.196 76.296 71.28 ;
    END
  END s3[188]
  PIN s3[189]
    DIRECTION OUTPUT ;
    USE SIGNAL ;
    PORT
      LAYER M5 ;
        RECT  76.368 71.196 76.392 71.28 ;
    END
  END s3[189]
  PIN s3[18]
    DIRECTION OUTPUT ;
    USE SIGNAL ;
    PORT
      LAYER M5 ;
        RECT  7.728 71.196 7.752 71.28 ;
    END
  END s3[18]
  PIN s3[19]
    DIRECTION OUTPUT ;
    USE SIGNAL ;
    PORT
      LAYER M5 ;
        RECT  7.824 71.196 7.848 71.28 ;
    END
  END s3[19]
  PIN s3[1]
    DIRECTION OUTPUT ;
    USE SIGNAL ;
    PORT
      LAYER M5 ;
        RECT  6.096 71.196 6.12 71.28 ;
    END
  END s3[1]
  PIN s3[20]
    DIRECTION OUTPUT ;
    USE SIGNAL ;
    PORT
      LAYER M5 ;
        RECT  7.92 71.196 7.944 71.28 ;
    END
  END s3[20]
  PIN s3[21]
    DIRECTION OUTPUT ;
    USE SIGNAL ;
    PORT
      LAYER M5 ;
        RECT  8.016 71.196 8.04 71.28 ;
    END
  END s3[21]
  PIN s3[22]
    DIRECTION OUTPUT ;
    USE SIGNAL ;
    PORT
      LAYER M5 ;
        RECT  8.112 71.196 8.136 71.28 ;
    END
  END s3[22]
  PIN s3[23]
    DIRECTION OUTPUT ;
    USE SIGNAL ;
    PORT
      LAYER M5 ;
        RECT  8.208 71.196 8.232 71.28 ;
    END
  END s3[23]
  PIN s3[24]
    DIRECTION OUTPUT ;
    USE SIGNAL ;
    PORT
      LAYER M5 ;
        RECT  8.304 71.196 8.328 71.28 ;
    END
  END s3[24]
  PIN s3[25]
    DIRECTION OUTPUT ;
    USE SIGNAL ;
    PORT
      LAYER M5 ;
        RECT  8.4 71.196 8.424 71.28 ;
    END
  END s3[25]
  PIN s3[26]
    DIRECTION OUTPUT ;
    USE SIGNAL ;
    PORT
      LAYER M5 ;
        RECT  8.496 71.196 8.52 71.28 ;
    END
  END s3[26]
  PIN s3[27]
    DIRECTION OUTPUT ;
    USE SIGNAL ;
    PORT
      LAYER M5 ;
        RECT  8.592 71.196 8.616 71.28 ;
    END
  END s3[27]
  PIN s3[28]
    DIRECTION OUTPUT ;
    USE SIGNAL ;
    PORT
      LAYER M5 ;
        RECT  8.688 71.196 8.712 71.28 ;
    END
  END s3[28]
  PIN s3[29]
    DIRECTION OUTPUT ;
    USE SIGNAL ;
    PORT
      LAYER M5 ;
        RECT  8.784 71.196 8.808 71.28 ;
    END
  END s3[29]
  PIN s3[2]
    DIRECTION OUTPUT ;
    USE SIGNAL ;
    PORT
      LAYER M5 ;
        RECT  6.192 71.196 6.216 71.28 ;
    END
  END s3[2]
  PIN s3[30]
    DIRECTION OUTPUT ;
    USE SIGNAL ;
    PORT
      LAYER M5 ;
        RECT  28.848 71.196 28.872 71.28 ;
    END
  END s3[30]
  PIN s3[31]
    DIRECTION OUTPUT ;
    USE SIGNAL ;
    PORT
      LAYER M5 ;
        RECT  28.944 71.196 28.968 71.28 ;
    END
  END s3[31]
  PIN s3[32]
    DIRECTION OUTPUT ;
    USE SIGNAL ;
    PORT
      LAYER M5 ;
        RECT  29.04 71.196 29.064 71.28 ;
    END
  END s3[32]
  PIN s3[33]
    DIRECTION OUTPUT ;
    USE SIGNAL ;
    PORT
      LAYER M5 ;
        RECT  29.136 71.196 29.16 71.28 ;
    END
  END s3[33]
  PIN s3[34]
    DIRECTION OUTPUT ;
    USE SIGNAL ;
    PORT
      LAYER M5 ;
        RECT  29.232 71.196 29.256 71.28 ;
    END
  END s3[34]
  PIN s3[35]
    DIRECTION OUTPUT ;
    USE SIGNAL ;
    PORT
      LAYER M5 ;
        RECT  29.328 71.196 29.352 71.28 ;
    END
  END s3[35]
  PIN s3[36]
    DIRECTION OUTPUT ;
    USE SIGNAL ;
    PORT
      LAYER M5 ;
        RECT  29.424 71.196 29.448 71.28 ;
    END
  END s3[36]
  PIN s3[37]
    DIRECTION OUTPUT ;
    USE SIGNAL ;
    PORT
      LAYER M5 ;
        RECT  29.52 71.196 29.544 71.28 ;
    END
  END s3[37]
  PIN s3[38]
    DIRECTION OUTPUT ;
    USE SIGNAL ;
    PORT
      LAYER M5 ;
        RECT  29.616 71.196 29.64 71.28 ;
    END
  END s3[38]
  PIN s3[39]
    DIRECTION OUTPUT ;
    USE SIGNAL ;
    PORT
      LAYER M5 ;
        RECT  29.712 71.196 29.736 71.28 ;
    END
  END s3[39]
  PIN s3[3]
    DIRECTION OUTPUT ;
    USE SIGNAL ;
    PORT
      LAYER M5 ;
        RECT  6.288 71.196 6.312 71.28 ;
    END
  END s3[3]
  PIN s3[40]
    DIRECTION OUTPUT ;
    USE SIGNAL ;
    PORT
      LAYER M5 ;
        RECT  29.808 71.196 29.832 71.28 ;
    END
  END s3[40]
  PIN s3[41]
    DIRECTION OUTPUT ;
    USE SIGNAL ;
    PORT
      LAYER M5 ;
        RECT  29.904 71.196 29.928 71.28 ;
    END
  END s3[41]
  PIN s3[42]
    DIRECTION OUTPUT ;
    USE SIGNAL ;
    PORT
      LAYER M5 ;
        RECT  30 71.196 30.024 71.28 ;
    END
  END s3[42]
  PIN s3[43]
    DIRECTION OUTPUT ;
    USE SIGNAL ;
    PORT
      LAYER M5 ;
        RECT  30.096 71.196 30.12 71.28 ;
    END
  END s3[43]
  PIN s3[44]
    DIRECTION OUTPUT ;
    USE SIGNAL ;
    PORT
      LAYER M5 ;
        RECT  30.192 71.196 30.216 71.28 ;
    END
  END s3[44]
  PIN s3[45]
    DIRECTION OUTPUT ;
    USE SIGNAL ;
    PORT
      LAYER M5 ;
        RECT  30.288 71.196 30.312 71.28 ;
    END
  END s3[45]
  PIN s3[46]
    DIRECTION OUTPUT ;
    USE SIGNAL ;
    PORT
      LAYER M5 ;
        RECT  30.384 71.196 30.408 71.28 ;
    END
  END s3[46]
  PIN s3[47]
    DIRECTION OUTPUT ;
    USE SIGNAL ;
    PORT
      LAYER M5 ;
        RECT  30.48 71.196 30.504 71.28 ;
    END
  END s3[47]
  PIN s3[48]
    DIRECTION OUTPUT ;
    USE SIGNAL ;
    PORT
      LAYER M5 ;
        RECT  30.576 71.196 30.6 71.28 ;
    END
  END s3[48]
  PIN s3[49]
    DIRECTION OUTPUT ;
    USE SIGNAL ;
    PORT
      LAYER M5 ;
        RECT  30.672 71.196 30.696 71.28 ;
    END
  END s3[49]
  PIN s3[4]
    DIRECTION OUTPUT ;
    USE SIGNAL ;
    PORT
      LAYER M5 ;
        RECT  6.384 71.196 6.408 71.28 ;
    END
  END s3[4]
  PIN s3[50]
    DIRECTION OUTPUT ;
    USE SIGNAL ;
    PORT
      LAYER M5 ;
        RECT  30.768 71.196 30.792 71.28 ;
    END
  END s3[50]
  PIN s3[51]
    DIRECTION OUTPUT ;
    USE SIGNAL ;
    PORT
      LAYER M5 ;
        RECT  30.864 71.196 30.888 71.28 ;
    END
  END s3[51]
  PIN s3[52]
    DIRECTION OUTPUT ;
    USE SIGNAL ;
    PORT
      LAYER M5 ;
        RECT  30.96 71.196 30.984 71.28 ;
    END
  END s3[52]
  PIN s3[53]
    DIRECTION OUTPUT ;
    USE SIGNAL ;
    PORT
      LAYER M5 ;
        RECT  31.056 71.196 31.08 71.28 ;
    END
  END s3[53]
  PIN s3[54]
    DIRECTION OUTPUT ;
    USE SIGNAL ;
    PORT
      LAYER M5 ;
        RECT  31.152 71.196 31.176 71.28 ;
    END
  END s3[54]
  PIN s3[55]
    DIRECTION OUTPUT ;
    USE SIGNAL ;
    PORT
      LAYER M5 ;
        RECT  31.248 71.196 31.272 71.28 ;
    END
  END s3[55]
  PIN s3[56]
    DIRECTION OUTPUT ;
    USE SIGNAL ;
    PORT
      LAYER M5 ;
        RECT  31.344 71.196 31.368 71.28 ;
    END
  END s3[56]
  PIN s3[57]
    DIRECTION OUTPUT ;
    USE SIGNAL ;
    PORT
      LAYER M5 ;
        RECT  31.44 71.196 31.464 71.28 ;
    END
  END s3[57]
  PIN s3[58]
    DIRECTION OUTPUT ;
    USE SIGNAL ;
    PORT
      LAYER M5 ;
        RECT  31.536 71.196 31.56 71.28 ;
    END
  END s3[58]
  PIN s3[59]
    DIRECTION OUTPUT ;
    USE SIGNAL ;
    PORT
      LAYER M5 ;
        RECT  31.632 71.196 31.656 71.28 ;
    END
  END s3[59]
  PIN s3[5]
    DIRECTION OUTPUT ;
    USE SIGNAL ;
    PORT
      LAYER M5 ;
        RECT  6.48 71.196 6.504 71.28 ;
    END
  END s3[5]
  PIN s3[60]
    DIRECTION OUTPUT ;
    USE SIGNAL ;
    PORT
      LAYER M5 ;
        RECT  31.728 71.196 31.752 71.28 ;
    END
  END s3[60]
  PIN s3[61]
    DIRECTION OUTPUT ;
    USE SIGNAL ;
    PORT
      LAYER M5 ;
        RECT  31.824 71.196 31.848 71.28 ;
    END
  END s3[61]
  PIN s3[62]
    DIRECTION OUTPUT ;
    USE SIGNAL ;
    PORT
      LAYER M5 ;
        RECT  67.248 71.196 67.272 71.28 ;
    END
  END s3[62]
  PIN s3[63]
    DIRECTION OUTPUT ;
    USE SIGNAL ;
    PORT
      LAYER M5 ;
        RECT  67.344 71.196 67.368 71.28 ;
    END
  END s3[63]
  PIN s3[64]
    DIRECTION OUTPUT ;
    USE SIGNAL ;
    PORT
      LAYER M5 ;
        RECT  67.44 71.196 67.464 71.28 ;
    END
  END s3[64]
  PIN s3[65]
    DIRECTION OUTPUT ;
    USE SIGNAL ;
    PORT
      LAYER M5 ;
        RECT  67.536 71.196 67.56 71.28 ;
    END
  END s3[65]
  PIN s3[66]
    DIRECTION OUTPUT ;
    USE SIGNAL ;
    PORT
      LAYER M5 ;
        RECT  67.632 71.196 67.656 71.28 ;
    END
  END s3[66]
  PIN s3[67]
    DIRECTION OUTPUT ;
    USE SIGNAL ;
    PORT
      LAYER M5 ;
        RECT  67.728 71.196 67.752 71.28 ;
    END
  END s3[67]
  PIN s3[68]
    DIRECTION OUTPUT ;
    USE SIGNAL ;
    PORT
      LAYER M5 ;
        RECT  67.824 71.196 67.848 71.28 ;
    END
  END s3[68]
  PIN s3[69]
    DIRECTION OUTPUT ;
    USE SIGNAL ;
    PORT
      LAYER M5 ;
        RECT  67.92 71.196 67.944 71.28 ;
    END
  END s3[69]
  PIN s3[6]
    DIRECTION OUTPUT ;
    USE SIGNAL ;
    PORT
      LAYER M5 ;
        RECT  6.576 71.196 6.6 71.28 ;
    END
  END s3[6]
  PIN s3[70]
    DIRECTION OUTPUT ;
    USE SIGNAL ;
    PORT
      LAYER M5 ;
        RECT  68.016 71.196 68.04 71.28 ;
    END
  END s3[70]
  PIN s3[71]
    DIRECTION OUTPUT ;
    USE SIGNAL ;
    PORT
      LAYER M5 ;
        RECT  68.112 71.196 68.136 71.28 ;
    END
  END s3[71]
  PIN s3[72]
    DIRECTION OUTPUT ;
    USE SIGNAL ;
    PORT
      LAYER M5 ;
        RECT  68.208 71.196 68.232 71.28 ;
    END
  END s3[72]
  PIN s3[73]
    DIRECTION OUTPUT ;
    USE SIGNAL ;
    PORT
      LAYER M5 ;
        RECT  68.304 71.196 68.328 71.28 ;
    END
  END s3[73]
  PIN s3[74]
    DIRECTION OUTPUT ;
    USE SIGNAL ;
    PORT
      LAYER M5 ;
        RECT  68.4 71.196 68.424 71.28 ;
    END
  END s3[74]
  PIN s3[75]
    DIRECTION OUTPUT ;
    USE SIGNAL ;
    PORT
      LAYER M5 ;
        RECT  68.496 71.196 68.52 71.28 ;
    END
  END s3[75]
  PIN s3[76]
    DIRECTION OUTPUT ;
    USE SIGNAL ;
    PORT
      LAYER M5 ;
        RECT  68.592 71.196 68.616 71.28 ;
    END
  END s3[76]
  PIN s3[77]
    DIRECTION OUTPUT ;
    USE SIGNAL ;
    PORT
      LAYER M5 ;
        RECT  68.688 71.196 68.712 71.28 ;
    END
  END s3[77]
  PIN s3[78]
    DIRECTION OUTPUT ;
    USE SIGNAL ;
    PORT
      LAYER M5 ;
        RECT  68.784 71.196 68.808 71.28 ;
    END
  END s3[78]
  PIN s3[79]
    DIRECTION OUTPUT ;
    USE SIGNAL ;
    PORT
      LAYER M5 ;
        RECT  68.88 71.196 68.904 71.28 ;
    END
  END s3[79]
  PIN s3[7]
    DIRECTION OUTPUT ;
    USE SIGNAL ;
    PORT
      LAYER M5 ;
        RECT  6.672 71.196 6.696 71.28 ;
    END
  END s3[7]
  PIN s3[80]
    DIRECTION OUTPUT ;
    USE SIGNAL ;
    PORT
      LAYER M5 ;
        RECT  68.976 71.196 69 71.28 ;
    END
  END s3[80]
  PIN s3[81]
    DIRECTION OUTPUT ;
    USE SIGNAL ;
    PORT
      LAYER M5 ;
        RECT  69.072 71.196 69.096 71.28 ;
    END
  END s3[81]
  PIN s3[82]
    DIRECTION OUTPUT ;
    USE SIGNAL ;
    PORT
      LAYER M5 ;
        RECT  69.168 71.196 69.192 71.28 ;
    END
  END s3[82]
  PIN s3[83]
    DIRECTION OUTPUT ;
    USE SIGNAL ;
    PORT
      LAYER M5 ;
        RECT  69.264 71.196 69.288 71.28 ;
    END
  END s3[83]
  PIN s3[84]
    DIRECTION OUTPUT ;
    USE SIGNAL ;
    PORT
      LAYER M5 ;
        RECT  69.36 71.196 69.384 71.28 ;
    END
  END s3[84]
  PIN s3[85]
    DIRECTION OUTPUT ;
    USE SIGNAL ;
    PORT
      LAYER M5 ;
        RECT  69.456 71.196 69.48 71.28 ;
    END
  END s3[85]
  PIN s3[86]
    DIRECTION OUTPUT ;
    USE SIGNAL ;
    PORT
      LAYER M5 ;
        RECT  69.552 71.196 69.576 71.28 ;
    END
  END s3[86]
  PIN s3[87]
    DIRECTION OUTPUT ;
    USE SIGNAL ;
    PORT
      LAYER M5 ;
        RECT  69.648 71.196 69.672 71.28 ;
    END
  END s3[87]
  PIN s3[88]
    DIRECTION OUTPUT ;
    USE SIGNAL ;
    PORT
      LAYER M5 ;
        RECT  69.744 71.196 69.768 71.28 ;
    END
  END s3[88]
  PIN s3[89]
    DIRECTION OUTPUT ;
    USE SIGNAL ;
    PORT
      LAYER M5 ;
        RECT  69.84 71.196 69.864 71.28 ;
    END
  END s3[89]
  PIN s3[8]
    DIRECTION OUTPUT ;
    USE SIGNAL ;
    PORT
      LAYER M5 ;
        RECT  6.768 71.196 6.792 71.28 ;
    END
  END s3[8]
  PIN s3[90]
    DIRECTION OUTPUT ;
    USE SIGNAL ;
    PORT
      LAYER M5 ;
        RECT  69.936 71.196 69.96 71.28 ;
    END
  END s3[90]
  PIN s3[91]
    DIRECTION OUTPUT ;
    USE SIGNAL ;
    PORT
      LAYER M5 ;
        RECT  70.032 71.196 70.056 71.28 ;
    END
  END s3[91]
  PIN s3[92]
    DIRECTION OUTPUT ;
    USE SIGNAL ;
    PORT
      LAYER M5 ;
        RECT  70.128 71.196 70.152 71.28 ;
    END
  END s3[92]
  PIN s3[93]
    DIRECTION OUTPUT ;
    USE SIGNAL ;
    PORT
      LAYER M5 ;
        RECT  70.224 71.196 70.248 71.28 ;
    END
  END s3[93]
  PIN s3[94]
    DIRECTION OUTPUT ;
    USE SIGNAL ;
    PORT
      LAYER M5 ;
        RECT  76.464 71.196 76.488 71.28 ;
    END
  END s3[94]
  PIN s3[95]
    DIRECTION OUTPUT ;
    USE SIGNAL ;
    PORT
      LAYER M5 ;
        RECT  76.56 71.196 76.584 71.28 ;
    END
  END s3[95]
  PIN s3[96]
    DIRECTION OUTPUT ;
    USE SIGNAL ;
    PORT
      LAYER M5 ;
        RECT  76.656 71.196 76.68 71.28 ;
    END
  END s3[96]
  PIN s3[97]
    DIRECTION OUTPUT ;
    USE SIGNAL ;
    PORT
      LAYER M5 ;
        RECT  76.752 71.196 76.776 71.28 ;
    END
  END s3[97]
  PIN s3[98]
    DIRECTION OUTPUT ;
    USE SIGNAL ;
    PORT
      LAYER M5 ;
        RECT  76.848 71.196 76.872 71.28 ;
    END
  END s3[98]
  PIN s3[99]
    DIRECTION OUTPUT ;
    USE SIGNAL ;
    PORT
      LAYER M5 ;
        RECT  76.944 71.196 76.968 71.28 ;
    END
  END s3[99]
  PIN s3[9]
    DIRECTION OUTPUT ;
    USE SIGNAL ;
    PORT
      LAYER M5 ;
        RECT  6.864 71.196 6.888 71.28 ;
    END
  END s3[9]
  PIN s3_v
    DIRECTION OUTPUT ;
    USE SIGNAL ;
    PORT
      LAYER M5 ;
        RECT  5.712 71.196 5.736 71.28 ;
    END
  END s3_v
  PIN VDD
    DIRECTION INOUT ;
    USE POWER ;
    PORT
      LAYER M5 ;
        RECT  83.592 2.151 83.712 69.129 ;
        RECT  78.192 2.151 78.312 69.129 ;
        RECT  72.792 2.151 72.912 69.129 ;
        RECT  67.392 2.151 67.512 69.129 ;
        RECT  61.992 2.151 62.112 69.129 ;
        RECT  56.592 2.151 56.712 69.129 ;
        RECT  51.192 2.151 51.312 69.129 ;
        RECT  45.792 2.151 45.912 69.129 ;
        RECT  40.392 2.151 40.512 69.129 ;
        RECT  34.992 2.151 35.112 69.129 ;
        RECT  29.592 2.151 29.712 69.129 ;
        RECT  24.192 2.151 24.312 69.129 ;
        RECT  18.792 2.151 18.912 69.129 ;
        RECT  13.392 2.151 13.512 69.129 ;
        RECT  7.992 2.151 8.112 69.129 ;
        RECT  2.592 2.151 2.712 69.129 ;
    END
  END VDD
  PIN VSS
    DIRECTION INOUT ;
    USE GROUND ;
    PORT
      LAYER M5 ;
        RECT  83.4 2.137 83.52 69.143 ;
        RECT  78 2.137 78.12 69.143 ;
        RECT  72.6 2.137 72.72 69.143 ;
        RECT  67.2 2.137 67.32 69.143 ;
        RECT  61.8 2.137 61.92 69.143 ;
        RECT  56.4 2.137 56.52 69.143 ;
        RECT  51 2.137 51.12 69.143 ;
        RECT  45.6 2.137 45.72 69.143 ;
        RECT  40.2 2.137 40.32 69.143 ;
        RECT  34.8 2.137 34.92 69.143 ;
        RECT  29.4 2.137 29.52 69.143 ;
        RECT  24 2.137 24.12 69.143 ;
        RECT  18.6 2.137 18.72 69.143 ;
        RECT  13.2 2.137 13.32 69.143 ;
        RECT  7.8 2.137 7.92 69.143 ;
        RECT  2.4 2.137 2.52 69.143 ;
    END
  END VSS
  # OT_OBS_CLOSED layer=M5 d_um=1.536 added=398
  OBS
    LAYER RVTN ;
     RECT  2.16 2.16 84.24 2.295 ;
     RECT  2.16 2.565 84.24 2.835 ;
     RECT  2.16 3.105 84.24 3.375 ;
     RECT  2.16 3.645 84.24 3.915 ;
     RECT  2.16 4.185 84.24 4.455 ;
     RECT  2.16 4.725 84.24 4.995 ;
     RECT  2.16 5.265 84.24 5.535 ;
     RECT  2.16 5.805 84.24 6.075 ;
     RECT  2.16 6.345 84.24 6.615 ;
     RECT  2.16 6.885 84.24 7.155 ;
     RECT  2.16 7.425 84.24 7.695 ;
     RECT  2.16 7.965 84.24 8.235 ;
     RECT  2.16 8.505 84.24 8.775 ;
     RECT  2.16 9.045 84.24 9.315 ;
     RECT  2.16 9.585 84.24 9.855 ;
     RECT  2.16 10.125 84.24 10.395 ;
     RECT  2.16 10.665 84.24 10.935 ;
     RECT  2.16 11.205 84.24 11.475 ;
     RECT  2.16 11.745 84.24 12.015 ;
     RECT  2.16 12.285 84.24 12.555 ;
     RECT  2.16 12.825 84.24 13.095 ;
     RECT  2.16 13.365 84.24 13.635 ;
     RECT  2.16 13.905 84.24 14.175 ;
     RECT  2.16 14.445 84.24 14.715 ;
     RECT  2.16 14.985 84.24 15.255 ;
     RECT  2.16 15.525 84.24 15.795 ;
     RECT  2.16 16.065 84.24 16.335 ;
     RECT  2.16 16.605 84.24 16.875 ;
     RECT  2.16 17.145 84.24 17.415 ;
     RECT  2.16 17.685 84.24 17.955 ;
     RECT  2.16 18.225 84.24 18.495 ;
     RECT  2.16 18.765 84.24 19.035 ;
     RECT  2.16 19.305 84.24 19.575 ;
     RECT  2.16 19.845 84.24 20.115 ;
     RECT  2.16 20.385 84.24 20.655 ;
     RECT  2.16 20.925 84.24 21.195 ;
     RECT  2.16 21.465 84.24 21.735 ;
     RECT  2.16 22.005 84.24 22.275 ;
     RECT  2.16 22.545 84.24 22.815 ;
     RECT  2.16 23.085 84.24 23.355 ;
     RECT  2.16 23.625 84.24 23.895 ;
     RECT  2.16 24.165 84.24 24.435 ;
     RECT  2.16 24.705 84.24 24.975 ;
     RECT  2.16 25.245 84.24 25.515 ;
     RECT  2.16 25.785 84.24 26.055 ;
     RECT  2.16 26.325 84.24 26.595 ;
     RECT  2.16 26.865 84.24 27.135 ;
     RECT  2.16 27.405 84.24 27.675 ;
     RECT  2.16 27.945 84.24 28.215 ;
     RECT  2.16 28.485 84.24 28.755 ;
     RECT  2.16 29.025 84.24 29.295 ;
     RECT  2.16 29.565 84.24 29.835 ;
     RECT  2.16 30.105 84.24 30.375 ;
     RECT  2.16 30.645 84.24 30.915 ;
     RECT  2.16 31.185 84.24 31.455 ;
     RECT  2.16 31.725 84.24 31.995 ;
     RECT  2.16 32.265 84.24 32.535 ;
     RECT  2.16 32.805 84.24 33.075 ;
     RECT  2.16 33.345 84.24 33.615 ;
     RECT  2.16 33.885 84.24 34.155 ;
     RECT  2.16 34.425 84.24 34.695 ;
     RECT  2.16 34.965 84.24 35.235 ;
     RECT  2.16 35.505 84.24 35.775 ;
     RECT  2.16 36.045 84.24 36.315 ;
     RECT  2.16 36.585 84.24 36.855 ;
     RECT  2.16 37.125 84.24 37.395 ;
     RECT  2.16 37.665 84.24 37.935 ;
     RECT  2.16 38.205 84.24 38.475 ;
     RECT  2.16 38.745 84.24 39.015 ;
     RECT  2.16 39.285 84.24 39.555 ;
     RECT  2.16 39.825 84.24 40.095 ;
     RECT  2.16 40.365 84.24 40.635 ;
     RECT  2.16 40.905 84.24 41.175 ;
     RECT  2.16 41.445 84.24 41.715 ;
     RECT  2.16 41.985 84.24 42.255 ;
     RECT  2.16 42.525 84.24 42.795 ;
     RECT  2.16 43.065 84.24 43.335 ;
     RECT  2.16 43.605 84.24 43.875 ;
     RECT  2.16 44.145 84.24 44.415 ;
     RECT  2.16 44.685 84.24 44.955 ;
     RECT  2.16 45.225 84.24 45.495 ;
     RECT  2.16 45.765 84.24 46.035 ;
     RECT  2.16 46.305 84.24 46.575 ;
     RECT  2.16 46.845 84.24 47.115 ;
     RECT  2.16 47.385 84.24 47.655 ;
     RECT  2.16 47.925 84.24 48.195 ;
     RECT  2.16 48.465 84.24 48.735 ;
     RECT  2.16 49.005 84.24 49.275 ;
     RECT  2.16 49.545 84.24 49.815 ;
     RECT  2.16 50.085 84.24 50.355 ;
     RECT  2.16 50.625 84.24 50.895 ;
     RECT  2.16 51.165 84.24 51.435 ;
     RECT  2.16 51.705 84.24 51.975 ;
     RECT  2.16 52.245 84.24 52.515 ;
     RECT  2.16 52.785 84.24 53.055 ;
     RECT  2.16 53.325 84.24 53.595 ;
     RECT  2.16 53.865 84.24 54.135 ;
     RECT  2.16 54.405 84.24 54.675 ;
     RECT  2.16 54.945 84.24 55.215 ;
     RECT  2.16 55.485 84.24 55.755 ;
     RECT  2.16 56.025 84.24 56.295 ;
     RECT  2.16 56.565 84.24 56.835 ;
     RECT  2.16 57.105 84.24 57.375 ;
     RECT  2.16 57.645 84.24 57.915 ;
     RECT  2.16 58.185 84.24 58.455 ;
     RECT  2.16 58.725 84.24 58.995 ;
     RECT  2.16 59.265 84.24 59.535 ;
     RECT  2.16 59.805 84.24 60.075 ;
     RECT  2.16 60.345 84.24 60.615 ;
     RECT  2.16 60.885 84.24 61.155 ;
     RECT  2.16 61.425 84.24 61.695 ;
     RECT  2.16 61.965 84.24 62.235 ;
     RECT  2.16 62.505 84.24 62.775 ;
     RECT  2.16 63.045 84.24 63.315 ;
     RECT  2.16 63.585 84.24 63.855 ;
     RECT  2.16 64.125 84.24 64.395 ;
     RECT  2.16 64.665 84.24 64.935 ;
     RECT  2.16 65.205 84.24 65.475 ;
     RECT  2.16 65.745 84.24 66.015 ;
     RECT  2.16 66.285 84.24 66.555 ;
     RECT  2.16 66.825 84.24 67.095 ;
     RECT  2.16 67.365 84.24 67.635 ;
     RECT  2.16 67.905 84.24 68.175 ;
     RECT  2.16 68.445 84.24 68.715 ;
     RECT  2.16 68.985 84.24 69.12 ;
    LAYER RVTP ;
     RECT  2.16 2.295 84.24 2.565 ;
     RECT  2.16 2.835 84.24 3.105 ;
     RECT  2.16 3.375 84.24 3.645 ;
     RECT  2.16 3.915 84.24 4.185 ;
     RECT  2.16 4.455 84.24 4.725 ;
     RECT  2.16 4.995 84.24 5.265 ;
     RECT  2.16 5.535 84.24 5.805 ;
     RECT  2.16 6.075 84.24 6.345 ;
     RECT  2.16 6.615 84.24 6.885 ;
     RECT  2.16 7.155 84.24 7.425 ;
     RECT  2.16 7.695 84.24 7.965 ;
     RECT  2.16 8.235 84.24 8.505 ;
     RECT  2.16 8.775 84.24 9.045 ;
     RECT  2.16 9.315 84.24 9.585 ;
     RECT  2.16 9.855 84.24 10.125 ;
     RECT  2.16 10.395 84.24 10.665 ;
     RECT  2.16 10.935 84.24 11.205 ;
     RECT  2.16 11.475 84.24 11.745 ;
     RECT  2.16 12.015 84.24 12.285 ;
     RECT  2.16 12.555 84.24 12.825 ;
     RECT  2.16 13.095 84.24 13.365 ;
     RECT  2.16 13.635 84.24 13.905 ;
     RECT  2.16 14.175 84.24 14.445 ;
     RECT  2.16 14.715 84.24 14.985 ;
     RECT  2.16 15.255 84.24 15.525 ;
     RECT  2.16 15.795 84.24 16.065 ;
     RECT  2.16 16.335 84.24 16.605 ;
     RECT  2.16 16.875 84.24 17.145 ;
     RECT  2.16 17.415 84.24 17.685 ;
     RECT  2.16 17.955 84.24 18.225 ;
     RECT  2.16 18.495 84.24 18.765 ;
     RECT  2.16 19.035 84.24 19.305 ;
     RECT  2.16 19.575 84.24 19.845 ;
     RECT  2.16 20.115 84.24 20.385 ;
     RECT  2.16 20.655 84.24 20.925 ;
     RECT  2.16 21.195 84.24 21.465 ;
     RECT  2.16 21.735 84.24 22.005 ;
     RECT  2.16 22.275 84.24 22.545 ;
     RECT  2.16 22.815 84.24 23.085 ;
     RECT  2.16 23.355 84.24 23.625 ;
     RECT  2.16 23.895 84.24 24.165 ;
     RECT  2.16 24.435 84.24 24.705 ;
     RECT  2.16 24.975 84.24 25.245 ;
     RECT  2.16 25.515 84.24 25.785 ;
     RECT  2.16 26.055 84.24 26.325 ;
     RECT  2.16 26.595 84.24 26.865 ;
     RECT  2.16 27.135 84.24 27.405 ;
     RECT  2.16 27.675 84.24 27.945 ;
     RECT  2.16 28.215 84.24 28.485 ;
     RECT  2.16 28.755 84.24 29.025 ;
     RECT  2.16 29.295 84.24 29.565 ;
     RECT  2.16 29.835 84.24 30.105 ;
     RECT  2.16 30.375 84.24 30.645 ;
     RECT  2.16 30.915 84.24 31.185 ;
     RECT  2.16 31.455 84.24 31.725 ;
     RECT  2.16 31.995 84.24 32.265 ;
     RECT  2.16 32.535 84.24 32.805 ;
     RECT  2.16 33.075 84.24 33.345 ;
     RECT  2.16 33.615 84.24 33.885 ;
     RECT  2.16 34.155 84.24 34.425 ;
     RECT  2.16 34.695 84.24 34.965 ;
     RECT  2.16 35.235 84.24 35.505 ;
     RECT  2.16 35.775 84.24 36.045 ;
     RECT  2.16 36.315 84.24 36.585 ;
     RECT  2.16 36.855 84.24 37.125 ;
     RECT  2.16 37.395 84.24 37.665 ;
     RECT  2.16 37.935 84.24 38.205 ;
     RECT  2.16 38.475 84.24 38.745 ;
     RECT  2.16 39.015 84.24 39.285 ;
     RECT  2.16 39.555 84.24 39.825 ;
     RECT  2.16 40.095 84.24 40.365 ;
     RECT  2.16 40.635 84.24 40.905 ;
     RECT  2.16 41.175 84.24 41.445 ;
     RECT  2.16 41.715 84.24 41.985 ;
     RECT  2.16 42.255 84.24 42.525 ;
     RECT  2.16 42.795 84.24 43.065 ;
     RECT  2.16 43.335 84.24 43.605 ;
     RECT  2.16 43.875 84.24 44.145 ;
     RECT  2.16 44.415 84.24 44.685 ;
     RECT  2.16 44.955 84.24 45.225 ;
     RECT  2.16 45.495 84.24 45.765 ;
     RECT  2.16 46.035 84.24 46.305 ;
     RECT  2.16 46.575 84.24 46.845 ;
     RECT  2.16 47.115 84.24 47.385 ;
     RECT  2.16 47.655 84.24 47.925 ;
     RECT  2.16 48.195 84.24 48.465 ;
     RECT  2.16 48.735 84.24 49.005 ;
     RECT  2.16 49.275 84.24 49.545 ;
     RECT  2.16 49.815 84.24 50.085 ;
     RECT  2.16 50.355 84.24 50.625 ;
     RECT  2.16 50.895 84.24 51.165 ;
     RECT  2.16 51.435 84.24 51.705 ;
     RECT  2.16 51.975 84.24 52.245 ;
     RECT  2.16 52.515 84.24 52.785 ;
     RECT  2.16 53.055 84.24 53.325 ;
     RECT  2.16 53.595 84.24 53.865 ;
     RECT  2.16 54.135 84.24 54.405 ;
     RECT  2.16 54.675 84.24 54.945 ;
     RECT  2.16 55.215 84.24 55.485 ;
     RECT  2.16 55.755 84.24 56.025 ;
     RECT  2.16 56.295 84.24 56.565 ;
     RECT  2.16 56.835 84.24 57.105 ;
     RECT  2.16 57.375 84.24 57.645 ;
     RECT  2.16 57.915 84.24 58.185 ;
     RECT  2.16 58.455 84.24 58.725 ;
     RECT  2.16 58.995 84.24 59.265 ;
     RECT  2.16 59.535 84.24 59.805 ;
     RECT  2.16 60.075 84.24 60.345 ;
     RECT  2.16 60.615 84.24 60.885 ;
     RECT  2.16 61.155 84.24 61.425 ;
     RECT  2.16 61.695 84.24 61.965 ;
     RECT  2.16 62.235 84.24 62.505 ;
     RECT  2.16 62.775 84.24 63.045 ;
     RECT  2.16 63.315 84.24 63.585 ;
     RECT  2.16 63.855 84.24 64.125 ;
     RECT  2.16 64.395 84.24 64.665 ;
     RECT  2.16 64.935 84.24 65.205 ;
     RECT  2.16 65.475 84.24 65.745 ;
     RECT  2.16 66.015 84.24 66.285 ;
     RECT  2.16 66.555 84.24 66.825 ;
     RECT  2.16 67.095 84.24 67.365 ;
     RECT  2.16 67.635 84.24 67.905 ;
     RECT  2.16 68.175 84.24 68.445 ;
     RECT  2.16 68.715 84.24 68.985 ;
    LAYER M1 ;
     RECT  2.16 2.151 84.24 69.129 ;
    LAYER M2 ;
     RECT  1.327 2.232 2.16 2.25 ;
     RECT  1.723 3.852 2.16 3.87 ;
     RECT  6.547 70.65 6.719 70.668 ;
     RECT  2.16 2.151 11.983 69.129 ;
     RECT  11.983 2.034 12.263 69.129 ;
     RECT  12.263 2.07 13.603 69.129 ;
     RECT  14.359 1.152 14.531 1.17 ;
     RECT  13.603 1.998 14.711 69.129 ;
     RECT  15.547 1.152 15.719 1.17 ;
     RECT  14.711 2.106 18.967 69.129 ;
     RECT  18.967 1.998 19.471 69.129 ;
     RECT  19.471 1.962 22.847 69.129 ;
     RECT  22.847 2.07 23.935 69.129 ;
     RECT  23.935 1.998 24.179 69.129 ;
     RECT  24.179 2.07 24.503 69.129 ;
     RECT  24.403 1.152 24.863 1.17 ;
     RECT  24.503 2.106 25.295 69.129 ;
     RECT  25.295 2.151 29.875 69.129 ;
     RECT  29.875 2.106 33.079 69.129 ;
     RECT  33.079 2.034 37.895 69.129 ;
     RECT  37.895 2.106 41.035 69.129 ;
     RECT  41.035 1.962 44.303 69.129 ;
     RECT  44.303 2.106 44.411 69.129 ;
     RECT  44.411 2.151 48.019 69.129 ;
     RECT  48.019 2.106 48.623 69.129 ;
     RECT  48.623 2.151 52.195 69.129 ;
     RECT  52.195 2.106 53.519 69.129 ;
     RECT  53.519 2.151 61.231 69.129 ;
     RECT  61.231 2.106 64.507 69.129 ;
     RECT  65.803 70.65 65.903 70.668 ;
     RECT  64.507 2.07 66.559 69.129 ;
     RECT  66.559 2.07 66.703 69.552 ;
     RECT  66.703 1.926 66.731 69.552 ;
     RECT  69.223 70.65 69.323 70.668 ;
     RECT  66.731 1.926 70.987 69.129 ;
     RECT  70.987 1.926 71.087 69.552 ;
     RECT  71.851 1.152 71.987 1.17 ;
     RECT  71.087 1.926 72.203 69.129 ;
     RECT  72.203 2.07 72.491 69.129 ;
     RECT  72.491 2.106 73.507 69.129 ;
     RECT  73.507 2.07 73.751 69.129 ;
     RECT  73.975 1.152 74.291 1.17 ;
     RECT  75.127 70.65 75.227 70.668 ;
     RECT  76.639 70.65 76.811 70.668 ;
     RECT  73.751 2.106 77.287 69.129 ;
     RECT  77.287 2.07 77.603 69.129 ;
     RECT  77.603 2.106 78.575 69.129 ;
     RECT  79.987 70.578 80.059 70.596 ;
     RECT  80.059 70.578 80.087 70.668 ;
     RECT  80.087 70.65 80.303 70.668 ;
     RECT  78.575 2.151 84.24 69.129 ;
     RECT  84.24 11.826 84.263 11.844 ;
     RECT  84.24 21.546 84.263 21.69 ;
     RECT  84.24 24.48 84.263 24.498 ;
     RECT  84.24 31.77 84.263 31.788 ;
     RECT  84.263 21.546 84.299 21.564 ;
     RECT  84.24 33.39 84.299 33.408 ;
    LAYER M3 ;
     RECT  4.752 0.043 4.77 0.091 ;
     RECT  16.092 0.043 16.11 0.091 ;
     RECT  76.752 0.091 76.77 0.139 ;
     RECT  1.116 0.043 1.134 0.173 ;
     RECT  15.552 0.091 16.11 0.173 ;
     RECT  24.156 0.139 24.498 0.187 ;
     RECT  25.344 0.139 25.362 0.187 ;
     RECT  13.176 0.091 13.194 0.523 ;
     RECT  24.156 0.187 25.362 0.523 ;
     RECT  4.644 0.091 4.77 0.571 ;
     RECT  13.176 0.523 13.374 0.571 ;
     RECT  20.088 0.139 21.294 0.571 ;
     RECT  23.112 0.523 23.13 0.571 ;
     RECT  61.488 0.091 61.506 0.571 ;
     RECT  71.064 0.523 71.082 0.571 ;
     RECT  72.576 0.091 72.594 0.571 ;
     RECT  73.62 0.091 74.286 0.571 ;
     RECT  75.384 0.523 75.402 0.571 ;
     RECT  76.464 0.139 76.77 0.571 ;
     RECT  68.976 0.571 68.994 0.619 ;
     RECT  71.928 0.571 72.594 0.619 ;
     RECT  4.644 0.571 5.346 1.099 ;
     RECT  6.264 0.571 6.282 1.099 ;
     RECT  3.888 0.523 3.906 1.147 ;
     RECT  4.644 1.099 6.282 1.147 ;
     RECT  9.792 0.571 9.81 1.147 ;
     RECT  13.104 0.571 13.77 1.147 ;
     RECT  14.508 0.571 14.526 1.147 ;
     RECT  15.552 0.173 15.57 1.147 ;
     RECT  22.896 0.571 23.418 1.147 ;
     RECT  24.156 0.523 26.046 1.147 ;
     RECT  68.976 0.619 69.066 1.147 ;
     RECT  9.72 1.147 9.81 1.195 ;
     RECT  71.856 0.619 72.594 1.243 ;
     RECT  73.548 0.571 74.286 1.243 ;
     RECT  9.288 1.195 9.81 1.675 ;
     RECT  20.088 0.571 21.762 1.675 ;
     RECT  22.896 1.147 26.046 1.675 ;
     RECT  68.004 0.523 68.022 1.675 ;
     RECT  68.976 1.147 69.534 1.675 ;
     RECT  3.888 1.147 6.282 1.723 ;
     RECT  8.64 1.675 9.81 1.723 ;
     RECT  12.24 0.475 12.258 1.723 ;
     RECT  13.104 1.147 14.526 1.723 ;
     RECT  15.552 1.147 15.714 1.723 ;
     RECT  20.088 1.675 26.046 1.723 ;
     RECT  27.144 1.099 27.162 1.723 ;
     RECT  27.972 0.571 27.99 1.723 ;
     RECT  39.24 1.099 39.258 1.723 ;
     RECT  60.984 0.571 61.506 1.723 ;
     RECT  62.964 1.675 62.982 1.723 ;
     RECT  68.004 1.675 69.534 1.723 ;
     RECT  70.704 0.571 71.082 1.723 ;
     RECT  71.856 1.243 74.286 1.723 ;
     RECT  75.384 0.571 76.77 1.723 ;
     RECT  3.708 1.723 7.182 1.771 ;
     RECT  8.64 1.723 10.746 1.771 ;
     RECT  12.24 1.723 16.11 1.771 ;
     RECT  29.628 1.723 30.114 1.771 ;
     RECT  60.984 1.723 61.722 1.771 ;
     RECT  62.64 1.723 64.386 1.771 ;
     RECT  3.636 1.771 7.29 1.819 ;
     RECT  12.24 1.771 16.47 1.819 ;
     RECT  20.016 1.723 28.782 1.819 ;
     RECT  29.556 1.771 30.114 1.819 ;
     RECT  39.24 1.723 40.194 1.819 ;
     RECT  20.016 1.819 30.114 1.957 ;
     RECT  39.24 1.819 40.41 1.957 ;
     RECT  19.476 1.957 30.114 1.993 ;
     RECT  44.28 1.957 44.298 2.029 ;
     RECT  66.708 1.921 66.726 2.059 ;
     RECT  68.004 1.723 76.77 2.059 ;
     RECT  60.984 1.771 64.386 2.065 ;
     RECT  66.708 2.059 76.77 2.065 ;
     RECT  18.972 1.993 30.114 2.101 ;
     RECT  37.872 2.029 37.89 2.101 ;
     RECT  44.028 2.029 44.298 2.101 ;
     RECT  3.636 1.819 7.362 2.143 ;
     RECT  66.708 2.065 77.598 2.143 ;
     RECT  78.552 2.101 78.57 2.143 ;
     RECT  2.415 2.143 2.505 2.191 ;
     RECT  3.636 2.143 7.905 2.191 ;
     RECT  8.64 1.771 10.818 2.191 ;
     RECT  39.24 1.957 41.058 2.191 ;
     RECT  45.615 2.143 45.705 2.191 ;
     RECT  52.2 2.101 52.218 2.191 ;
     RECT  53.496 2.101 53.514 2.191 ;
     RECT  60.984 2.065 64.53 2.191 ;
     RECT  65.556 2.065 65.898 2.191 ;
     RECT  66.708 2.143 78.57 2.191 ;
     RECT  18.504 2.101 30.114 2.203 ;
     RECT  30.996 2.191 31.374 2.203 ;
     RECT  42.372 2.029 42.39 2.227 ;
     RECT  45.615 2.191 45.954 2.227 ;
     RECT  48.024 2.101 48.618 2.227 ;
     RECT  57.564 2.191 57.582 2.227 ;
     RECT  79.524 2.191 79.542 2.227 ;
     RECT  80.748 2.191 80.766 2.227 ;
     RECT  1.332 1.723 1.35 2.255 ;
     RECT  3.636 2.191 10.818 2.263 ;
     RECT  11.628 1.819 16.47 2.263 ;
     RECT  18.504 2.203 31.374 2.263 ;
     RECT  38.772 2.191 41.058 2.263 ;
     RECT  43.884 2.101 44.406 2.263 ;
     RECT  45.396 2.227 45.954 2.263 ;
     RECT  54.504 2.191 54.522 2.263 ;
     RECT  60.588 2.191 64.53 2.263 ;
     RECT  65.268 2.191 78.57 2.263 ;
     RECT  2.415 2.191 2.682 2.299 ;
     RECT  3.636 2.263 17.046 2.299 ;
     RECT  18.504 2.263 31.806 2.299 ;
     RECT  38.772 2.263 41.346 2.299 ;
     RECT  42.192 2.227 42.606 2.299 ;
     RECT  48.024 2.227 48.726 2.299 ;
     RECT  51.015 2.143 51.105 2.299 ;
     RECT  2.415 2.299 17.046 2.335 ;
     RECT  18.468 2.299 31.806 2.335 ;
     RECT  38.772 2.299 42.606 2.335 ;
     RECT  43.884 2.263 45.954 2.335 ;
     RECT  47.628 2.299 49.086 2.335 ;
     RECT  49.86 2.299 49.878 2.335 ;
     RECT  52.2 2.191 53.514 2.335 ;
     RECT  54.36 2.263 54.522 2.335 ;
     RECT  56.415 2.143 56.505 2.335 ;
     RECT  57.564 2.227 57.87 2.335 ;
     RECT  2.415 2.335 17.406 2.371 ;
     RECT  18.396 2.335 32.202 2.371 ;
     RECT  33.084 2.029 33.102 2.371 ;
     RECT  37.224 2.101 37.89 2.371 ;
     RECT  38.7 2.335 45.954 2.371 ;
     RECT  57.564 2.335 58.122 2.371 ;
     RECT  37.224 2.371 45.954 2.395 ;
     RECT  34.815 2.143 34.905 2.413 ;
     RECT  50.652 2.299 51.105 2.413 ;
     RECT  56.376 2.335 56.505 2.413 ;
     RECT  83.415 2.143 83.505 2.413 ;
     RECT  56.376 2.413 56.697 2.461 ;
     RECT  57.564 2.371 58.986 2.461 ;
     RECT  60.588 2.263 78.57 2.461 ;
     RECT  81.648 2.203 81.666 2.461 ;
     RECT  18.396 2.371 33.102 2.488 ;
     RECT  50.652 2.413 51.297 2.489 ;
     RECT  37.188 2.395 45.954 2.491 ;
     RECT  37.188 2.491 46.386 2.497 ;
     RECT  79.416 2.227 80.766 2.497 ;
     RECT  81.576 2.461 81.666 2.497 ;
     RECT  47.628 2.335 49.878 2.533 ;
     RECT  18.324 2.488 33.102 2.569 ;
     RECT  47.556 2.533 49.878 2.569 ;
     RECT  50.94 2.489 51.297 2.569 ;
     RECT  52.2 2.335 54.594 2.569 ;
     RECT  2.304 2.371 17.406 2.587 ;
     RECT  18.252 2.569 33.102 2.587 ;
     RECT  2.304 2.587 33.102 2.605 ;
     RECT  35.928 2.371 36.45 2.605 ;
     RECT  56.376 2.461 58.986 2.605 ;
     RECT  56.232 2.605 58.986 2.641 ;
     RECT  60.408 2.461 78.57 2.641 ;
     RECT  79.416 2.497 81.666 2.641 ;
     RECT  83.415 2.413 83.697 2.641 ;
     RECT  35.892 2.605 36.45 2.731 ;
     RECT  37.188 2.497 46.782 2.731 ;
     RECT  47.556 2.569 49.914 2.731 ;
     RECT  56.232 2.641 78.606 2.731 ;
     RECT  79.416 2.641 81.954 2.731 ;
     RECT  50.94 2.569 54.594 2.759 ;
     RECT  56.232 2.731 81.954 2.759 ;
     RECT  52.74 2.759 54.594 2.767 ;
     RECT  50.94 2.759 51.894 2.795 ;
     RECT  34.815 2.413 35.097 2.803 ;
     RECT  35.892 2.731 49.914 2.827 ;
     RECT  2.304 2.605 33.57 2.839 ;
     RECT  34.308 2.803 35.097 2.839 ;
     RECT  2.304 2.839 35.097 2.875 ;
     RECT  52.74 2.767 55.134 2.911 ;
     RECT  1.728 2.875 35.097 2.923 ;
     RECT  35.856 2.827 49.914 2.923 ;
     RECT  52.74 2.911 55.278 2.957 ;
     RECT  52.884 2.957 55.278 3.029 ;
     RECT  56.232 2.759 81.882 3.065 ;
     RECT  1.728 2.923 49.914 3.271 ;
     RECT  50.94 2.795 51.858 3.271 ;
     RECT  82.728 2.641 83.697 3.343 ;
     RECT  56.232 3.065 81.846 3.403 ;
     RECT  52.884 3.029 55.062 3.443 ;
     RECT  1.728 3.271 51.858 3.541 ;
     RECT  52.884 3.443 53.298 3.605 ;
     RECT  1.728 3.541 51.966 3.811 ;
     RECT  52.884 3.605 53.226 3.811 ;
     RECT  54.108 3.443 55.062 3.811 ;
     RECT  55.98 3.403 81.846 3.811 ;
     RECT  1.728 3.811 53.226 3.875 ;
     RECT  54.108 3.811 81.846 3.955 ;
     RECT  82.62 3.343 83.697 3.955 ;
     RECT  2.304 3.875 49.914 3.965 ;
     RECT  54.108 3.955 83.697 4.189 ;
     RECT  49.896 3.965 49.914 4.415 ;
     RECT  50.652 3.875 53.226 4.459 ;
     RECT  53.964 4.189 83.697 4.459 ;
     RECT  50.652 4.459 83.697 4.621 ;
     RECT  2.304 3.965 48.87 4.693 ;
     RECT  2.304 4.693 49.086 4.801 ;
     RECT  2.304 4.801 49.158 4.891 ;
     RECT  2.268 4.891 49.158 4.955 ;
     RECT  2.304 4.955 49.158 5.225 ;
     RECT  48.024 5.225 49.158 5.431 ;
     RECT  50.076 4.621 83.697 5.431 ;
     RECT  2.304 5.225 47.178 6.007 ;
     RECT  48.024 5.431 83.697 6.007 ;
     RECT  2.304 6.007 83.697 6.139 ;
     RECT  2.268 6.139 83.697 6.151 ;
     RECT  2.268 6.151 83.79 6.241 ;
     RECT  2.268 6.241 83.862 6.269 ;
     RECT  53.352 6.269 83.862 6.691 ;
     RECT  2.268 6.269 52.614 6.719 ;
     RECT  53.352 6.691 83.934 6.853 ;
     RECT  2.268 6.719 47.898 7.079 ;
     RECT  48.708 6.719 52.614 7.123 ;
     RECT  53.352 6.853 83.97 7.123 ;
     RECT  48.708 7.123 83.97 7.231 ;
     RECT  48.708 7.231 84.114 7.349 ;
     RECT  48.708 7.349 83.934 7.385 ;
     RECT  48.708 7.385 56.862 7.501 ;
     RECT  2.268 7.079 47.826 8.041 ;
     RECT  48.636 7.501 56.862 8.041 ;
     RECT  2.268 8.041 56.862 8.311 ;
     RECT  57.636 7.385 83.934 8.311 ;
     RECT  2.268 8.311 83.934 8.509 ;
     RECT  2.268 8.509 84.006 8.671 ;
     RECT  2.232 8.671 84.006 8.827 ;
     RECT  2.196 8.827 84.006 9.113 ;
     RECT  54.108 9.113 84.006 9.239 ;
     RECT  54.252 9.239 84.006 9.581 ;
     RECT  57.6 9.581 84.006 9.617 ;
     RECT  2.196 9.113 53.334 9.779 ;
     RECT  57.744 9.617 84.006 9.931 ;
     RECT  54.252 9.581 56.862 10.049 ;
     RECT  54.252 10.049 56.79 10.193 ;
     RECT  2.268 9.779 53.334 10.291 ;
     RECT  54.252 10.193 55.566 10.291 ;
     RECT  57.744 9.931 84.15 10.435 ;
     RECT  56.376 10.193 56.79 10.867 ;
     RECT  57.564 10.435 84.15 10.867 ;
     RECT  2.268 10.291 55.566 10.939 ;
     RECT  56.376 10.867 84.15 10.939 ;
     RECT  2.268 10.939 84.15 11.201 ;
     RECT  2.268 11.201 51.297 11.261 ;
     RECT  2.304 11.261 51.297 11.399 ;
     RECT  52.128 11.201 84.15 11.821 ;
     RECT  2.34 11.399 51.297 11.981 ;
     RECT  47.844 11.981 51.297 12.019 ;
     RECT  52.128 11.821 84.258 12.019 ;
     RECT  2.34 11.981 46.962 12.317 ;
     RECT  47.844 12.019 84.258 12.389 ;
     RECT  2.34 12.317 46.746 12.523 ;
     RECT  2.304 12.523 46.746 13.261 ;
     RECT  48.168 12.389 84.258 13.261 ;
     RECT  2.304 13.261 84.258 13.433 ;
     RECT  58.572 13.433 84.258 13.559 ;
     RECT  2.304 13.433 57.798 13.631 ;
     RECT  58.572 13.559 60.57 14.099 ;
     RECT  2.304 13.631 53.154 14.243 ;
     RECT  48.168 14.243 53.154 14.477 ;
     RECT  54.144 13.631 57.798 14.521 ;
     RECT  58.572 14.099 60.426 14.521 ;
     RECT  48.384 14.477 53.154 14.611 ;
     RECT  48.384 14.611 53.298 14.669 ;
     RECT  2.304 14.243 47.142 14.989 ;
     RECT  54.108 14.521 60.426 15.019 ;
     RECT  61.416 13.559 84.258 15.061 ;
     RECT  2.304 14.989 47.574 15.089 ;
     RECT  48.384 14.669 53.118 15.089 ;
     RECT  54.108 15.019 60.462 15.089 ;
     RECT  57.636 15.089 60.462 15.215 ;
     RECT  61.236 15.061 84.258 15.295 ;
     RECT  48.492 15.089 53.118 15.421 ;
     RECT  54.108 15.089 56.898 15.421 ;
     RECT  48.492 15.421 56.898 15.719 ;
     RECT  48.492 15.719 56.754 15.821 ;
     RECT  2.304 15.089 47.286 15.835 ;
     RECT  2.304 15.835 47.394 15.961 ;
     RECT  48.492 15.821 53.118 15.961 ;
     RECT  57.816 15.215 60.462 16.141 ;
     RECT  61.2 15.295 84.258 16.141 ;
     RECT  57.564 16.141 84.258 16.331 ;
     RECT  2.304 15.961 53.118 16.349 ;
     RECT  54.144 15.821 56.754 16.637 ;
     RECT  2.304 16.349 52.974 16.835 ;
     RECT  56.376 16.637 56.754 16.835 ;
     RECT  56.415 16.835 56.754 16.951 ;
     RECT  2.304 16.835 47.97 17.069 ;
     RECT  2.304 17.069 47.934 17.105 ;
     RECT  49.032 16.835 52.974 17.113 ;
     RECT  49.032 17.113 53.01 17.179 ;
     RECT  54.144 16.637 55.386 17.179 ;
     RECT  56.415 16.951 56.79 17.221 ;
     RECT  57.816 16.331 84.258 17.221 ;
     RECT  49.032 17.179 55.386 17.249 ;
     RECT  56.415 17.221 56.862 17.311 ;
     RECT  57.708 17.221 84.258 17.311 ;
     RECT  49.104 17.249 55.386 17.339 ;
     RECT  56.415 17.311 84.258 17.609 ;
     RECT  2.304 17.105 30.87 17.717 ;
     RECT  54.252 17.339 55.386 17.761 ;
     RECT  56.415 17.609 60.03 17.761 ;
     RECT  2.34 17.717 30.87 17.923 ;
     RECT  31.716 17.105 47.934 17.923 ;
     RECT  2.34 17.923 47.934 18.031 ;
     RECT  49.104 17.339 53.406 18.157 ;
     RECT  54.252 17.761 60.03 18.157 ;
     RECT  49.104 18.157 60.03 18.229 ;
     RECT  48.924 18.229 60.03 18.269 ;
     RECT  48.924 18.269 51.606 18.329 ;
     RECT  2.34 18.031 48.15 18.419 ;
     RECT  60.804 17.609 84.258 18.419 ;
     RECT  60.876 18.419 84.258 18.455 ;
     RECT  2.34 18.419 25.794 18.464 ;
     RECT  2.34 18.464 25.758 18.491 ;
     RECT  48.924 18.329 51.297 18.563 ;
     RECT  26.532 18.419 48.15 18.661 ;
     RECT  52.488 18.269 60.03 18.689 ;
     RECT  26.532 18.661 48.474 18.869 ;
     RECT  26.532 18.869 48.438 18.959 ;
     RECT  60.984 18.455 84.258 18.959 ;
     RECT  2.34 18.491 25.146 18.995 ;
     RECT  52.488 18.689 59.922 19.075 ;
     RECT  26.532 18.959 48.042 19.336 ;
     RECT  49.284 18.563 51.297 19.381 ;
     RECT  49.284 19.381 51.606 19.543 ;
     RECT  52.344 19.075 59.922 19.543 ;
     RECT  49.284 19.543 59.922 19.579 ;
     RECT  2.376 18.995 25.146 19.651 ;
     RECT  2.376 19.651 25.254 19.741 ;
     RECT  25.992 19.336 48.042 19.741 ;
     RECT  2.376 19.741 48.042 19.769 ;
     RECT  61.02 18.959 84.258 19.769 ;
     RECT  2.415 19.769 48.042 19.805 ;
     RECT  61.02 19.769 63.702 19.849 ;
     RECT  60.804 19.849 63.702 19.921 ;
     RECT  49.212 19.579 59.922 20.047 ;
     RECT  49.032 20.047 59.922 20.119 ;
     RECT  48.996 20.119 59.922 20.417 ;
     RECT  2.415 19.805 46.566 20.587 ;
     RECT  54.144 20.417 59.922 20.615 ;
     RECT  2.415 20.587 46.71 20.623 ;
     RECT  47.448 19.805 48.042 20.623 ;
     RECT  2.415 20.623 48.042 20.659 ;
     RECT  48.996 20.417 53.406 20.659 ;
     RECT  56.232 20.615 59.922 20.731 ;
     RECT  60.66 19.921 63.702 20.731 ;
     RECT  64.44 19.769 84.258 20.731 ;
     RECT  56.232 20.731 84.258 21.029 ;
     RECT  54.144 20.615 55.458 21.155 ;
     RECT  2.415 20.659 53.406 21.163 ;
     RECT  54.144 21.155 55.026 21.163 ;
     RECT  60.66 21.029 84.258 21.425 ;
     RECT  2.415 21.163 55.026 21.461 ;
     RECT  56.232 21.029 59.886 21.541 ;
     RECT  60.696 21.425 84.258 21.541 ;
     RECT  60.696 21.541 84.294 21.569 ;
     RECT  48.996 21.461 55.026 21.659 ;
     RECT  56.016 21.541 59.886 21.901 ;
     RECT  48.996 21.659 53.658 21.965 ;
     RECT  54.432 21.659 55.026 22.009 ;
     RECT  55.836 21.901 59.886 22.009 ;
     RECT  54.432 22.009 59.886 22.199 ;
     RECT  2.415 21.461 48.042 22.207 ;
     RECT  55.836 22.199 59.886 22.235 ;
     RECT  48.996 21.965 53.406 22.351 ;
     RECT  60.768 21.569 84.294 22.351 ;
     RECT  2.376 22.207 48.042 22.441 ;
     RECT  48.816 22.351 53.406 22.441 ;
     RECT  54.432 22.199 55.026 22.459 ;
     RECT  55.872 22.235 59.886 22.469 ;
     RECT  55.872 22.469 59.706 22.649 ;
     RECT  2.376 22.441 53.406 22.711 ;
     RECT  54.18 22.459 55.026 22.711 ;
     RECT  60.732 22.351 84.294 22.775 ;
     RECT  2.376 22.711 55.026 23.009 ;
     RECT  2.415 23.009 55.026 23.125 ;
     RECT  55.872 22.649 59.526 23.125 ;
     RECT  2.415 23.125 59.526 23.891 ;
     RECT  55.152 23.891 59.526 24.205 ;
     RECT  60.768 22.775 84.294 24.241 ;
     RECT  2.415 23.891 54.27 24.629 ;
     RECT  2.415 24.629 54.09 24.665 ;
     RECT  2.415 24.665 41.85 24.701 ;
     RECT  55.152 24.205 59.67 24.745 ;
     RECT  42.768 24.665 54.09 24.749 ;
     RECT  49.5 24.749 54.09 24.935 ;
     RECT  42.768 24.749 48.654 24.971 ;
     RECT  49.5 24.935 50.238 25.043 ;
     RECT  51.012 24.935 54.018 25.079 ;
     RECT  55.044 24.745 59.67 25.285 ;
     RECT  60.732 24.241 84.294 25.285 ;
     RECT  51.012 25.079 53.838 25.475 ;
     RECT  2.415 24.701 41.742 25.555 ;
     RECT  55.044 25.285 84.294 25.555 ;
     RECT  2.415 25.555 41.922 25.675 ;
     RECT  42.768 24.971 48.582 25.675 ;
     RECT  2.415 25.675 48.582 25.709 ;
     RECT  54.9 25.555 84.294 25.781 ;
     RECT  49.608 25.043 50.238 25.789 ;
     RECT  51.012 25.475 53.586 25.789 ;
     RECT  2.415 25.709 48.474 25.861 ;
     RECT  54.9 25.781 63.234 25.861 ;
     RECT  49.608 25.789 53.586 26.023 ;
     RECT  54.684 25.861 63.234 26.023 ;
     RECT  49.392 26.023 53.586 26.107 ;
     RECT  54.504 26.023 63.234 26.249 ;
     RECT  49.32 26.107 53.586 26.365 ;
     RECT  2.376 25.861 48.474 26.393 ;
     RECT  54.504 26.249 62.91 26.527 ;
     RECT  49.284 26.365 53.586 26.528 ;
     RECT  64.044 25.781 84.294 26.635 ;
     RECT  64.008 26.635 84.294 26.671 ;
     RECT  54.432 26.527 62.91 26.825 ;
     RECT  2.415 26.393 48.474 26.827 ;
     RECT  49.284 26.528 53.01 26.827 ;
     RECT  54.432 26.825 56.898 26.833 ;
     RECT  53.784 26.833 56.898 27.059 ;
     RECT  2.415 26.827 53.01 27.149 ;
     RECT  63.756 26.671 84.294 27.175 ;
     RECT  53.784 27.059 54.486 27.373 ;
     RECT  57.672 26.825 62.91 27.481 ;
     RECT  63.684 27.175 84.294 27.481 ;
     RECT  53.748 27.373 54.486 27.715 ;
     RECT  55.296 27.059 56.898 27.715 ;
     RECT  57.672 27.481 84.294 27.715 ;
     RECT  2.415 27.149 52.902 27.821 ;
     RECT  2.415 27.821 48.006 27.869 ;
     RECT  48.78 27.821 52.902 27.869 ;
     RECT  53.676 27.715 54.486 27.913 ;
     RECT  55.296 27.715 84.294 27.913 ;
     RECT  48.816 27.869 52.902 27.985 ;
     RECT  53.676 27.913 84.294 27.985 ;
     RECT  2.415 27.869 47.862 28.211 ;
     RECT  48.816 27.985 84.294 28.247 ;
     RECT  48.816 28.247 60.714 28.409 ;
     RECT  48.816 28.409 57.186 28.445 ;
     RECT  61.452 28.247 84.294 28.445 ;
     RECT  57.96 28.409 60.714 28.451 ;
     RECT  58.644 28.451 60.714 28.595 ;
     RECT  50.148 28.445 57.186 28.751 ;
     RECT  2.415 28.211 47.718 28.831 ;
     RECT  48.816 28.445 49.266 28.859 ;
     RECT  50.148 28.751 53.982 28.949 ;
     RECT  54.792 28.751 57.186 28.949 ;
     RECT  55.008 28.949 57.186 29.021 ;
     RECT  2.376 28.831 47.718 29.101 ;
     RECT  58.68 28.595 60.714 29.101 ;
     RECT  61.452 28.445 63.486 29.101 ;
     RECT  2.376 29.101 47.862 29.131 ;
     RECT  48.816 28.859 48.978 29.131 ;
     RECT  64.44 28.445 84.294 29.255 ;
     RECT  2.376 29.131 48.978 29.291 ;
     RECT  58.68 29.101 63.486 29.371 ;
     RECT  64.44 29.255 80.838 29.461 ;
     RECT  58.68 29.371 63.666 29.569 ;
     RECT  64.404 29.461 80.838 29.569 ;
     RECT  47.304 29.291 48.978 29.641 ;
     RECT  50.148 28.949 53.946 29.645 ;
     RECT  58.68 29.569 80.838 29.731 ;
     RECT  55.08 29.021 57.186 29.803 ;
     RECT  58.572 29.731 80.838 29.803 ;
     RECT  50.148 29.645 53.838 29.839 ;
     RECT  54.72 29.803 57.186 29.875 ;
     RECT  47.304 29.641 49.086 29.911 ;
     RECT  49.968 29.839 53.838 29.911 ;
     RECT  54.576 29.875 57.186 29.911 ;
     RECT  58.392 29.803 80.838 29.911 ;
     RECT  81.576 29.255 84.294 30.029 ;
     RECT  2.376 29.291 46.422 30.173 ;
     RECT  47.304 29.911 53.838 30.173 ;
     RECT  54.576 29.911 80.838 30.181 ;
     RECT  54.576 30.181 80.874 30.209 ;
     RECT  44.928 30.173 46.422 30.451 ;
     RECT  47.304 30.173 49.05 30.451 ;
     RECT  49.932 30.173 53.838 30.541 ;
     RECT  54.576 30.209 57.042 30.541 ;
     RECT  2.376 30.173 44.082 30.875 ;
     RECT  44.928 30.451 49.05 30.919 ;
     RECT  2.415 30.875 44.082 30.991 ;
     RECT  44.82 30.919 49.05 30.991 ;
     RECT  58.068 30.209 80.874 30.991 ;
     RECT  81.612 30.029 84.294 30.991 ;
     RECT  49.932 30.541 57.042 31.019 ;
     RECT  49.968 31.019 57.042 31.081 ;
     RECT  49.968 31.081 57.186 31.109 ;
     RECT  50.076 31.109 57.186 31.379 ;
     RECT  58.068 30.991 84.294 31.531 ;
     RECT  2.415 30.991 49.05 31.729 ;
     RECT  57.78 31.531 84.294 31.919 ;
     RECT  50.076 31.379 57.042 31.955 ;
     RECT  50.076 31.955 51.297 31.963 ;
     RECT  2.34 31.729 49.05 31.999 ;
     RECT  49.86 31.963 51.297 31.999 ;
     RECT  52.092 31.955 57.042 32.611 ;
     RECT  52.092 32.611 57.258 32.737 ;
     RECT  52.092 32.737 57.402 32.809 ;
     RECT  58.14 31.919 84.294 32.809 ;
     RECT  52.092 32.809 84.294 32.837 ;
     RECT  2.34 31.999 51.297 32.999 ;
     RECT  2.34 32.999 42.21 33.101 ;
     RECT  43.02 32.999 51.297 33.293 ;
     RECT  52.092 32.837 60.462 33.341 ;
     RECT  61.2 32.837 84.294 33.413 ;
     RECT  46.62 33.293 51.297 33.511 ;
     RECT  52.092 33.341 54.126 33.511 ;
     RECT  46.62 33.511 54.126 33.539 ;
     RECT  54.972 33.341 60.462 33.539 ;
     RECT  50.22 33.539 54.054 33.575 ;
     RECT  61.2 33.413 84.222 33.629 ;
     RECT  54.972 33.539 56.754 33.809 ;
     RECT  2.34 33.101 42.03 33.869 ;
     RECT  38.628 33.869 42.03 33.961 ;
     RECT  43.02 33.293 45.897 33.961 ;
     RECT  57.564 33.539 60.462 33.961 ;
     RECT  61.2 33.629 63.882 33.961 ;
     RECT  54.972 33.809 55.674 33.989 ;
     RECT  38.628 33.961 45.897 34.051 ;
     RECT  46.62 33.539 49.266 34.051 ;
     RECT  50.256 33.575 54.054 34.109 ;
     RECT  50.832 34.109 54.054 34.115 ;
     RECT  57.564 33.961 63.882 34.187 ;
     RECT  54.972 33.989 55.638 34.357 ;
     RECT  38.628 34.051 49.266 34.457 ;
     RECT  57.672 34.187 63.882 34.465 ;
     RECT  57.672 34.465 63.918 34.501 ;
     RECT  64.656 33.629 84.222 34.501 ;
     RECT  38.628 34.457 47.142 34.529 ;
     RECT  38.628 34.529 47.106 34.619 ;
     RECT  50.832 34.115 53.442 34.619 ;
     RECT  47.88 34.457 49.266 34.699 ;
     RECT  2.34 33.869 37.782 34.735 ;
     RECT  38.628 34.619 46.926 34.735 ;
     RECT  54.216 34.357 55.638 34.735 ;
     RECT  56.415 33.809 56.754 34.735 ;
     RECT  47.88 34.699 49.77 34.763 ;
     RECT  2.34 34.735 46.926 34.771 ;
     RECT  54.216 34.735 56.754 34.771 ;
     RECT  57.672 34.501 84.222 34.889 ;
     RECT  48.024 34.763 49.77 34.925 ;
     RECT  48.024 34.925 49.734 34.961 ;
     RECT  54.216 34.771 56.862 35.005 ;
     RECT  50.832 34.619 53.406 35.159 ;
     RECT  54.216 35.005 57.51 35.159 ;
     RECT  54.216 35.159 57.33 35.167 ;
     RECT  50.94 35.159 53.406 35.195 ;
     RECT  54.144 35.167 57.33 35.309 ;
     RECT  2.268 34.771 46.926 35.339 ;
     RECT  2.268 35.339 38.07 35.537 ;
     RECT  38.952 35.339 46.926 35.707 ;
     RECT  48.096 34.961 49.734 35.707 ;
     RECT  2.304 35.537 38.07 35.735 ;
     RECT  58.392 34.889 84.222 35.815 ;
     RECT  51.015 35.195 53.406 35.851 ;
     RECT  54.144 35.309 57.222 35.851 ;
     RECT  2.34 35.735 38.07 35.969 ;
     RECT  2.34 35.969 16.974 35.981 ;
     RECT  17.748 35.969 38.07 36.005 ;
     RECT  38.952 35.707 49.734 36.04 ;
     RECT  51.015 35.851 57.222 36.049 ;
     RECT  17.748 36.005 37.818 36.113 ;
     RECT  38.952 36.04 49.878 36.121 ;
     RECT  50.868 36.049 57.222 36.121 ;
     RECT  58.248 35.815 84.222 36.121 ;
     RECT  36.504 36.113 37.818 36.149 ;
     RECT  2.34 35.981 16.794 36.239 ;
     RECT  50.868 36.121 84.222 36.311 ;
     RECT  38.916 36.121 49.878 36.355 ;
     RECT  38.556 36.355 49.878 36.571 ;
     RECT  50.868 36.311 84.15 36.571 ;
     RECT  17.748 36.113 35.622 36.715 ;
     RECT  38.556 36.571 84.15 36.851 ;
     RECT  2.34 36.239 16.758 37.021 ;
     RECT  17.604 36.715 35.622 37.021 ;
     RECT  2.34 37.021 35.622 37.049 ;
     RECT  36.504 36.149 37.746 37.129 ;
     RECT  38.556 36.851 57.654 37.129 ;
     RECT  36.504 37.129 57.654 37.633 ;
     RECT  36.288 37.633 57.654 37.733 ;
     RECT  44.136 37.733 57.654 37.741 ;
     RECT  58.428 36.851 84.15 37.741 ;
     RECT  2.34 37.049 35.334 37.867 ;
     RECT  36.288 37.733 43.182 37.867 ;
     RECT  2.34 37.867 43.182 37.967 ;
     RECT  44.136 37.741 84.15 37.967 ;
     RECT  52.02 37.967 84.15 38.669 ;
     RECT  34.128 37.967 43.182 38.677 ;
     RECT  44.136 37.967 51.297 38.677 ;
     RECT  55.296 38.669 84.15 38.777 ;
     RECT  34.128 38.677 51.297 38.779 ;
     RECT  52.02 38.669 54.414 38.779 ;
     RECT  34.128 38.779 54.414 38.939 ;
     RECT  2.34 37.967 33.318 38.983 ;
     RECT  2.34 38.983 33.354 39.091 ;
     RECT  34.128 38.939 51.678 39.091 ;
     RECT  2.34 39.091 51.678 39.353 ;
     RECT  45.108 39.353 51.678 39.479 ;
     RECT  45.108 39.479 51.462 39.515 ;
     RECT  2.34 39.353 43.902 39.623 ;
     RECT  52.416 38.939 54.414 39.721 ;
     RECT  55.44 38.777 84.15 39.721 ;
     RECT  45.324 39.515 51.462 39.857 ;
     RECT  52.416 39.721 84.15 39.893 ;
     RECT  52.884 39.893 84.15 40.019 ;
     RECT  2.34 39.623 30.006 40.055 ;
     RECT  30.744 39.623 43.902 40.055 ;
     RECT  52.884 40.019 84.114 40.163 ;
     RECT  36.504 40.055 43.902 40.261 ;
     RECT  52.884 40.163 54.918 40.289 ;
     RECT  36.504 40.261 43.974 40.297 ;
     RECT  47.664 39.857 51.462 40.445 ;
     RECT  55.656 40.163 84.114 40.445 ;
     RECT  49.68 40.445 51.462 40.459 ;
     RECT  5.22 40.055 30.006 40.531 ;
     RECT  30.744 40.055 35.694 40.531 ;
     RECT  45.324 39.857 46.854 40.531 ;
     RECT  47.664 40.445 48.906 40.595 ;
     RECT  47.664 40.595 48.798 40.631 ;
     RECT  45.288 40.531 46.854 40.675 ;
     RECT  47.664 40.631 48.726 40.675 ;
     RECT  5.22 40.531 35.694 40.795 ;
     RECT  36.504 40.297 44.226 40.795 ;
     RECT  5.22 40.795 44.226 40.801 ;
     RECT  45.108 40.675 48.726 40.801 ;
     RECT  49.68 40.459 52.002 40.801 ;
     RECT  52.884 40.289 54.846 40.801 ;
     RECT  55.764 40.445 84.114 40.829 ;
     RECT  60.372 40.829 84.114 40.865 ;
     RECT  66.096 40.865 84.114 40.901 ;
     RECT  5.22 40.801 48.726 40.937 ;
     RECT  49.68 40.801 54.846 40.937 ;
     RECT  2.34 40.055 4.482 40.981 ;
     RECT  5.22 40.937 44.046 40.981 ;
     RECT  51.015 40.937 54.846 41.215 ;
     RECT  55.764 40.829 59.526 41.215 ;
     RECT  2.34 40.981 44.046 41.279 ;
     RECT  45 40.937 48.726 41.413 ;
     RECT  49.68 40.937 50.202 41.413 ;
     RECT  45 41.413 50.202 41.719 ;
     RECT  51.015 41.215 59.526 41.719 ;
     RECT  60.372 40.865 65.178 41.719 ;
     RECT  45 41.719 65.178 41.791 ;
     RECT  66.096 40.901 83.862 41.791 ;
     RECT  31.896 41.279 44.046 41.989 ;
     RECT  45 41.791 83.862 41.989 ;
     RECT  31.896 41.989 83.862 42.089 ;
     RECT  52.524 42.089 83.862 42.179 ;
     RECT  2.34 41.279 31.158 42.449 ;
     RECT  31.896 42.089 51.75 42.485 ;
     RECT  31.896 42.485 33.246 42.529 ;
     RECT  65.664 42.179 83.862 42.593 ;
     RECT  31.5 42.529 33.246 42.755 ;
     RECT  2.34 42.449 30.762 42.863 ;
     RECT  31.86 42.755 33.246 42.899 ;
     RECT  52.524 42.179 64.854 43.025 ;
     RECT  33.984 42.485 51.75 43.069 ;
     RECT  52.524 43.025 55.674 43.069 ;
     RECT  31.896 42.899 33.246 43.097 ;
     RECT  33.984 43.069 55.674 43.259 ;
     RECT  65.772 42.593 83.862 43.259 ;
     RECT  25.992 42.863 30.762 43.537 ;
     RECT  2.34 42.863 25.254 43.609 ;
     RECT  25.992 43.537 30.978 43.609 ;
     RECT  65.844 43.259 83.862 43.771 ;
     RECT  56.415 43.025 64.422 43.807 ;
     RECT  33.984 43.259 51.678 43.819 ;
     RECT  31.896 43.097 33.102 43.843 ;
     RECT  33.912 43.819 51.678 43.843 ;
     RECT  52.56 43.259 55.674 43.843 ;
     RECT  56.415 43.807 64.494 43.843 ;
     RECT  65.844 43.771 83.898 43.853 ;
     RECT  52.56 43.843 64.494 43.951 ;
     RECT  52.56 43.951 64.89 44.077 ;
     RECT  31.896 43.843 51.678 44.105 ;
     RECT  31.896 44.105 46.746 44.149 ;
     RECT  47.592 44.105 51.678 44.221 ;
     RECT  65.844 43.853 83.862 44.221 ;
     RECT  52.488 44.077 64.89 44.339 ;
     RECT  47.592 44.221 51.714 44.375 ;
     RECT  52.488 44.339 57.114 44.483 ;
     RECT  57.852 44.339 64.89 44.483 ;
     RECT  2.34 43.609 30.978 44.491 ;
     RECT  31.824 44.149 46.746 44.491 ;
     RECT  57.852 44.483 60.642 44.669 ;
     RECT  57.852 44.669 60.102 44.753 ;
     RECT  61.38 44.483 64.89 44.761 ;
     RECT  65.664 44.221 83.862 44.761 ;
     RECT  2.34 44.491 46.746 44.951 ;
     RECT  44.964 44.951 46.746 45.031 ;
     RECT  47.592 44.375 51.354 45.031 ;
     RECT  2.34 44.951 44.19 45.149 ;
     RECT  61.38 44.761 83.862 45.149 ;
     RECT  44.964 45.031 51.354 45.193 ;
     RECT  52.128 44.851 52.326 45.193 ;
     RECT  44.964 45.193 52.326 45.208 ;
     RECT  45 45.208 52.326 45.265 ;
     RECT  53.1 44.483 57.114 45.265 ;
     RECT  2.34 45.149 44.154 45.419 ;
     RECT  45 45.265 57.114 45.419 ;
     RECT  64.836 45.149 83.862 45.455 ;
     RECT  55.872 45.419 57.114 45.535 ;
     RECT  57.852 44.753 60.03 45.535 ;
     RECT  22.752 45.419 44.154 45.563 ;
     RECT  22.752 45.563 44.118 45.581 ;
     RECT  55.872 45.535 60.138 45.725 ;
     RECT  61.38 45.149 64.062 45.841 ;
     RECT  61.308 45.841 64.062 45.931 ;
     RECT  64.836 45.455 65.43 45.931 ;
     RECT  55.872 45.725 59.166 45.959 ;
     RECT  2.376 45.419 21.87 45.995 ;
     RECT  45 45.419 54.882 45.995 ;
     RECT  56.088 45.959 59.166 45.995 ;
     RECT  59.904 45.725 60.138 45.995 ;
     RECT  45 45.995 54.45 46.139 ;
     RECT  45 46.139 54.414 46.265 ;
     RECT  61.308 45.931 65.43 46.309 ;
     RECT  66.276 45.455 83.862 46.345 ;
     RECT  22.788 45.581 44.118 46.373 ;
     RECT  61.236 46.309 65.43 46.381 ;
     RECT  2.415 45.995 21.87 46.471 ;
     RECT  22.788 46.373 38.214 46.471 ;
     RECT  56.415 45.995 59.166 46.471 ;
     RECT  59.904 45.995 60.102 46.471 ;
     RECT  38.988 46.373 44.118 46.507 ;
     RECT  61.092 46.381 65.43 46.615 ;
     RECT  66.204 46.345 83.862 46.615 ;
     RECT  38.988 46.507 44.19 46.741 ;
     RECT  45 46.265 54.342 46.741 ;
     RECT  56.415 46.471 60.102 46.805 ;
     RECT  61.092 46.615 83.862 46.849 ;
     RECT  61.092 46.849 83.97 46.885 ;
     RECT  61.02 46.885 83.97 46.921 ;
     RECT  2.415 46.471 38.214 47.047 ;
     RECT  55.656 46.741 55.674 47.131 ;
     RECT  56.415 46.805 59.49 47.131 ;
     RECT  2.376 47.047 38.214 47.155 ;
     RECT  38.988 46.741 54.342 47.155 ;
     RECT  2.376 47.155 54.342 47.191 ;
     RECT  55.656 47.131 59.49 47.191 ;
     RECT  2.376 47.191 54.738 47.309 ;
     RECT  55.512 47.191 59.49 47.309 ;
     RECT  2.415 47.309 54.702 47.453 ;
     RECT  44.208 47.453 54.702 47.489 ;
     RECT  55.656 47.309 59.49 47.587 ;
     RECT  55.656 47.587 59.526 47.695 ;
     RECT  55.656 47.695 59.634 47.731 ;
     RECT  60.408 46.921 83.97 47.731 ;
     RECT  55.656 47.731 84.114 47.849 ;
     RECT  55.656 47.849 57.186 48.119 ;
     RECT  2.415 47.453 43.362 48.199 ;
     RECT  44.208 47.489 54.666 48.199 ;
     RECT  2.415 48.199 54.666 48.299 ;
     RECT  58.068 47.849 84.114 48.299 ;
     RECT  2.415 48.299 48.546 48.389 ;
     RECT  44.568 48.389 48.546 48.413 ;
     RECT  44.604 48.413 48.546 48.461 ;
     RECT  58.068 48.299 83.934 48.461 ;
     RECT  44.604 48.461 48.15 48.557 ;
     RECT  49.428 48.299 54.666 48.659 ;
     RECT  58.212 48.461 83.934 48.695 ;
     RECT  55.656 48.119 57.114 48.937 ;
     RECT  44.604 48.557 48.114 49.001 ;
     RECT  52.02 48.659 54.666 49.009 ;
     RECT  55.656 48.937 57.186 49.009 ;
     RECT  61.236 48.695 83.934 49.045 ;
     RECT  61.236 49.045 84.006 49.081 ;
     RECT  44.604 49.001 48.042 49.109 ;
     RECT  52.02 49.009 57.186 49.109 ;
     RECT  2.415 48.389 43.65 49.171 ;
     RECT  61.236 49.081 84.114 49.199 ;
     RECT  2.415 49.171 43.902 49.229 ;
     RECT  49.428 48.659 51.297 49.243 ;
     RECT  49.212 49.243 51.297 49.315 ;
     RECT  52.056 49.109 57.186 49.351 ;
     RECT  58.212 48.695 60.426 49.351 ;
     RECT  52.056 49.351 57.294 49.379 ;
     RECT  58.068 49.351 60.426 49.505 ;
     RECT  61.236 49.199 84.006 49.505 ;
     RECT  44.676 49.109 48.042 49.577 ;
     RECT  48.78 49.315 51.297 49.649 ;
     RECT  45.108 49.577 46.962 49.739 ;
     RECT  47.772 49.577 48.042 49.771 ;
     RECT  48.78 49.649 49.05 49.771 ;
     RECT  52.056 49.379 54.918 49.853 ;
     RECT  52.056 49.853 54.81 50.045 ;
     RECT  55.728 49.379 57.294 50.081 ;
     RECT  52.272 50.045 54.81 50.141 ;
     RECT  52.272 50.141 54.738 50.153 ;
     RECT  58.212 49.505 60.426 50.161 ;
     RECT  61.236 49.505 83.862 50.161 ;
     RECT  58.212 50.161 83.862 50.189 ;
     RECT  45.108 49.739 46.926 50.395 ;
     RECT  47.772 49.771 49.05 50.431 ;
     RECT  47.7 50.431 49.05 50.443 ;
     RECT  49.86 49.649 51.297 50.443 ;
     RECT  44.82 50.395 46.926 50.521 ;
     RECT  47.7 50.443 51.297 50.521 ;
     RECT  58.212 50.189 83.697 50.521 ;
     RECT  44.82 50.521 51.297 50.669 ;
     RECT  58.032 50.521 83.697 50.693 ;
     RECT  55.872 50.081 57.294 50.701 ;
     RECT  58.032 50.693 60.174 50.701 ;
     RECT  47.448 50.669 51.297 50.729 ;
     RECT  47.52 50.729 51.297 50.779 ;
     RECT  2.415 49.229 43.686 50.791 ;
     RECT  52.272 50.153 54.702 50.819 ;
     RECT  55.872 50.701 60.174 50.819 ;
     RECT  47.52 50.779 51.534 50.863 ;
     RECT  52.272 50.819 54.522 50.863 ;
     RECT  55.872 50.819 59.922 50.863 ;
     RECT  44.82 50.669 46.602 50.935 ;
     RECT  55.764 50.863 59.922 50.935 ;
     RECT  2.415 50.791 43.866 50.971 ;
     RECT  44.676 50.935 46.602 50.971 ;
     RECT  47.52 50.863 54.522 51.089 ;
     RECT  2.415 50.971 46.602 51.125 ;
     RECT  60.948 50.693 83.697 51.125 ;
     RECT  43.776 51.125 46.602 51.233 ;
     RECT  43.884 51.233 46.602 51.511 ;
     RECT  55.512 50.935 59.922 51.601 ;
     RECT  55.512 51.601 60.426 51.637 ;
     RECT  47.52 51.089 52.038 51.809 ;
     RECT  55.296 51.637 60.426 51.899 ;
     RECT  43.884 51.511 46.71 51.943 ;
     RECT  47.52 51.809 49.122 51.943 ;
     RECT  57.996 51.899 60.426 51.979 ;
     RECT  61.236 51.125 83.697 51.979 ;
     RECT  2.415 51.125 42.93 52.051 ;
     RECT  43.884 51.943 49.122 52.051 ;
     RECT  53.028 51.089 54.27 52.051 ;
     RECT  52.956 52.051 54.27 52.141 ;
     RECT  2.415 52.051 49.122 52.205 ;
     RECT  49.968 51.809 52.038 52.213 ;
     RECT  52.956 52.141 54.378 52.213 ;
     RECT  52.884 52.213 54.378 52.253 ;
     RECT  2.415 52.205 49.086 52.313 ;
     RECT  49.968 52.213 52.146 52.439 ;
     RECT  57.996 51.979 83.697 52.475 ;
     RECT  55.296 51.899 57.186 52.519 ;
     RECT  54.972 52.519 57.186 52.709 ;
     RECT  60.228 52.475 83.697 52.745 ;
     RECT  57.996 52.475 59.382 52.789 ;
     RECT  49.968 52.439 52.038 52.825 ;
     RECT  47.34 52.313 49.086 52.853 ;
     RECT  49.86 52.825 52.038 52.979 ;
     RECT  52.884 52.253 54.09 52.979 ;
     RECT  54.972 52.709 56.79 52.979 ;
     RECT  57.564 52.789 59.382 52.979 ;
     RECT  60.444 52.745 83.697 52.987 ;
     RECT  52.884 52.979 53.946 53.015 ;
     RECT  49.896 52.979 52.038 53.051 ;
     RECT  2.415 52.313 46.53 53.221 ;
     RECT  57.672 52.979 59.382 53.221 ;
     RECT  47.484 52.853 49.086 53.249 ;
     RECT  49.932 53.051 52.038 53.257 ;
     RECT  52.884 53.015 53.874 53.257 ;
     RECT  54.972 52.979 56.697 53.293 ;
     RECT  2.415 53.221 46.71 53.357 ;
     RECT  60.444 52.987 83.826 53.591 ;
     RECT  2.415 53.357 46.53 53.597 ;
     RECT  60.552 53.591 83.826 53.671 ;
     RECT  54.828 53.293 56.697 53.761 ;
     RECT  2.415 53.597 43.686 53.837 ;
     RECT  2.415 53.837 43.542 53.905 ;
     RECT  47.592 53.249 49.086 53.905 ;
     RECT  49.932 53.257 53.874 53.905 ;
     RECT  57.672 53.221 59.418 53.905 ;
     RECT  47.592 53.905 53.874 54.211 ;
     RECT  54.648 53.761 56.697 54.211 ;
     RECT  60.552 53.671 83.898 54.211 ;
     RECT  44.496 53.597 46.53 54.301 ;
     RECT  47.592 54.211 56.697 54.481 ;
     RECT  57.672 53.905 59.454 54.481 ;
     RECT  60.552 54.211 84.042 54.481 ;
     RECT  47.376 54.481 84.042 54.599 ;
     RECT  47.376 54.599 59.31 54.635 ;
     RECT  60.588 54.599 84.042 54.635 ;
     RECT  47.376 54.635 59.274 54.701 ;
     RECT  60.588 54.635 83.97 54.779 ;
     RECT  44.496 54.301 46.602 54.913 ;
     RECT  47.376 54.701 51.57 54.913 ;
     RECT  52.524 54.701 59.274 54.941 ;
     RECT  2.376 53.905 43.542 55.021 ;
     RECT  2.376 55.021 43.614 55.049 ;
     RECT  2.415 55.049 43.614 55.181 ;
     RECT  60.588 54.779 83.862 55.211 ;
     RECT  60.588 55.211 83.697 55.489 ;
     RECT  52.56 54.941 59.274 55.561 ;
     RECT  52.56 55.561 59.562 55.651 ;
     RECT  60.552 55.489 83.697 55.651 ;
     RECT  52.56 55.651 83.697 55.679 ;
     RECT  52.74 55.679 83.697 55.715 ;
     RECT  44.496 54.913 51.57 55.723 ;
     RECT  44.496 55.723 51.678 55.853 ;
     RECT  44.496 55.853 49.41 55.859 ;
     RECT  50.22 55.853 51.678 55.867 ;
     RECT  2.415 55.181 43.578 55.921 ;
     RECT  2.376 55.921 43.578 55.993 ;
     RECT  44.496 55.859 46.53 55.993 ;
     RECT  47.34 55.859 49.41 56.255 ;
     RECT  47.34 56.255 49.086 56.489 ;
     RECT  52.992 55.715 83.697 56.497 ;
     RECT  2.376 55.993 46.53 56.605 ;
     RECT  47.34 56.489 49.014 56.605 ;
     RECT  50.22 55.867 51.93 56.605 ;
     RECT  2.376 56.605 49.014 56.939 ;
     RECT  52.848 56.497 83.697 57.029 ;
     RECT  49.896 56.605 51.93 57.109 ;
     RECT  52.848 57.029 57.834 57.109 ;
     RECT  49.896 57.109 57.834 57.145 ;
     RECT  58.572 57.029 83.697 57.181 ;
     RECT  47.304 56.939 49.014 57.209 ;
     RECT  58.572 57.181 83.754 57.379 ;
     RECT  2.376 56.939 46.278 57.569 ;
     RECT  49.788 57.145 57.834 57.569 ;
     RECT  2.376 57.569 44.226 57.605 ;
     RECT  45.072 57.569 46.278 57.685 ;
     RECT  49.788 57.569 51.318 57.839 ;
     RECT  52.488 57.569 57.834 57.847 ;
     RECT  58.572 57.379 83.79 57.847 ;
     RECT  45.072 57.685 46.386 57.883 ;
     RECT  47.304 57.209 48.798 58.153 ;
     RECT  47.304 58.153 48.978 58.171 ;
     RECT  45.072 57.883 46.53 58.225 ;
     RECT  47.304 58.171 49.05 58.225 ;
     RECT  52.488 57.847 83.79 58.261 ;
     RECT  2.376 57.605 44.01 58.495 ;
     RECT  52.488 58.261 83.898 58.495 ;
     RECT  52.452 58.495 83.898 58.531 ;
     RECT  2.376 58.495 44.154 58.649 ;
     RECT  2.376 58.649 44.01 58.685 ;
     RECT  45.072 58.225 49.05 58.891 ;
     RECT  49.788 57.839 51.297 58.891 ;
     RECT  45.072 58.891 51.297 58.963 ;
     RECT  52.452 58.531 84.042 59.035 ;
     RECT  44.964 58.963 51.297 59.197 ;
     RECT  52.02 59.035 84.042 59.213 ;
     RECT  44.856 59.197 51.297 59.269 ;
     RECT  2.376 58.685 43.902 59.305 ;
     RECT  52.596 59.213 84.042 59.305 ;
     RECT  44.856 59.269 51.822 59.369 ;
     RECT  49.536 59.369 51.822 59.459 ;
     RECT  52.596 59.305 84.114 59.459 ;
     RECT  44.856 59.369 48.762 59.539 ;
     RECT  2.34 59.305 43.902 59.729 ;
     RECT  52.596 59.459 84.042 59.765 ;
     RECT  2.376 59.729 43.902 59.947 ;
     RECT  44.712 59.539 48.762 59.947 ;
     RECT  2.376 59.947 48.762 59.999 ;
     RECT  49.536 59.459 51.786 59.999 ;
     RECT  52.668 59.765 84.042 59.999 ;
     RECT  52.668 59.999 57.042 60.143 ;
     RECT  49.536 59.999 51.642 60.313 ;
     RECT  57.888 59.999 84.042 60.377 ;
     RECT  49.284 60.313 51.642 60.413 ;
     RECT  2.376 59.999 48.114 60.539 ;
     RECT  52.668 60.143 56.97 60.619 ;
     RECT  57.996 60.377 84.042 60.907 ;
     RECT  57.996 60.907 84.114 60.953 ;
     RECT  2.415 60.539 48.114 61.051 ;
     RECT  52.488 60.619 56.97 61.123 ;
     RECT  2.415 61.051 48.258 61.231 ;
     RECT  49.284 60.413 51.462 61.231 ;
     RECT  52.488 61.123 57.042 61.231 ;
     RECT  57.996 60.953 83.697 61.231 ;
     RECT  49.284 61.231 57.042 61.259 ;
     RECT  2.415 61.231 48.438 61.387 ;
     RECT  49.284 61.259 56.97 61.387 ;
     RECT  2.415 61.387 56.97 61.457 ;
     RECT  57.852 61.231 83.697 61.735 ;
     RECT  44.532 61.457 56.97 61.799 ;
     RECT  49.428 61.799 56.97 61.889 ;
     RECT  2.415 61.457 43.542 62.395 ;
     RECT  49.536 61.889 56.97 62.429 ;
     RECT  54.468 62.429 56.97 62.509 ;
     RECT  57.744 61.735 83.697 62.509 ;
     RECT  54.468 62.509 83.697 62.537 ;
     RECT  2.415 62.395 43.578 62.545 ;
     RECT  2.415 62.545 43.65 62.581 ;
     RECT  54.54 62.537 83.697 62.581 ;
     RECT  49.536 62.429 53.622 62.707 ;
     RECT  2.415 62.581 43.722 62.731 ;
     RECT  44.532 61.799 48.69 62.731 ;
     RECT  2.415 62.731 48.69 62.779 ;
     RECT  49.464 62.707 53.622 62.779 ;
     RECT  2.415 62.779 53.622 62.969 ;
     RECT  54.54 62.581 83.754 62.969 ;
     RECT  54.684 62.969 83.754 63.751 ;
     RECT  2.415 62.969 49.086 64.021 ;
     RECT  50.112 62.969 53.622 64.021 ;
     RECT  2.415 64.021 53.622 64.093 ;
     RECT  54.648 63.751 83.754 64.093 ;
     RECT  2.415 64.093 83.754 64.157 ;
     RECT  2.415 64.157 43.83 64.201 ;
     RECT  44.604 64.157 83.754 64.831 ;
     RECT  44.604 64.831 83.79 65.117 ;
     RECT  44.604 65.117 53.046 65.165 ;
     RECT  2.376 64.201 43.83 65.273 ;
     RECT  37.692 65.273 43.83 65.323 ;
     RECT  44.604 65.165 53.01 65.323 ;
     RECT  37.692 65.323 53.01 65.435 ;
     RECT  37.692 65.435 49.05 65.471 ;
     RECT  53.784 65.117 83.79 65.515 ;
     RECT  53.784 65.515 84.15 65.543 ;
     RECT  53.82 65.543 84.15 66.083 ;
     RECT  2.376 65.273 36.918 66.091 ;
     RECT  37.692 65.471 49.014 66.091 ;
     RECT  2.376 66.091 49.014 66.181 ;
     RECT  49.932 65.435 53.01 66.181 ;
     RECT  2.34 66.181 49.014 66.217 ;
     RECT  49.824 66.181 53.01 66.217 ;
     RECT  2.34 66.217 53.01 66.281 ;
     RECT  40.215 66.281 53.01 66.289 ;
     RECT  53.82 66.083 83.697 66.289 ;
     RECT  2.34 66.281 39.474 66.515 ;
     RECT  40.215 66.289 83.697 67.019 ;
     RECT  2.34 66.515 39.438 67.261 ;
     RECT  40.215 67.019 54.954 67.261 ;
     RECT  2.34 67.261 54.954 67.819 ;
     RECT  55.728 67.019 83.697 67.819 ;
     RECT  2.34 67.819 83.697 68.141 ;
     RECT  48.348 68.141 83.697 68.369 ;
     RECT  2.34 68.141 47.358 68.405 ;
     RECT  48.348 68.369 82.314 68.429 ;
     RECT  2.415 68.405 47.358 68.477 ;
     RECT  2.415 68.477 25.074 68.639 ;
     RECT  34.815 68.477 47.358 68.639 ;
     RECT  48.528 68.429 82.314 68.639 ;
     RECT  2.415 68.639 22.77 68.675 ;
     RECT  48.924 68.639 52.218 68.675 ;
     RECT  34.815 68.639 47.25 68.711 ;
     RECT  23.508 68.639 25.074 68.717 ;
     RECT  26.28 68.477 34.074 68.717 ;
     RECT  52.992 68.639 81.702 68.747 ;
     RECT  2.415 68.675 19.134 68.783 ;
     RECT  20.016 68.675 22.662 68.783 ;
     RECT  26.28 68.717 33.714 68.783 ;
     RECT  34.815 68.711 44.694 68.783 ;
     RECT  4.536 68.783 19.134 68.819 ;
     RECT  20.016 68.783 21.906 68.819 ;
     RECT  22.644 68.783 22.662 68.819 ;
     RECT  26.28 68.783 26.802 68.819 ;
     RECT  35.82 68.783 39.33 68.819 ;
     RECT  42.192 68.783 44.694 68.819 ;
     RECT  45.615 68.711 47.25 68.819 ;
     RECT  53.496 68.747 81.702 68.819 ;
     RECT  2.415 68.783 3.762 68.867 ;
     RECT  34.815 68.783 35.097 68.867 ;
     RECT  40.068 68.783 41.31 68.867 ;
     RECT  55.584 68.819 81.27 68.867 ;
     RECT  83.415 68.369 83.697 68.867 ;
     RECT  3.348 68.867 3.762 68.909 ;
     RECT  4.536 68.819 13.878 68.909 ;
     RECT  14.724 68.819 19.134 68.909 ;
     RECT  20.016 68.819 20.358 68.909 ;
     RECT  23.508 68.717 24.57 68.909 ;
     RECT  26.424 68.819 26.802 68.909 ;
     RECT  28.368 68.783 33.714 68.909 ;
     RECT  35.856 68.819 39.114 68.909 ;
     RECT  41.148 68.867 41.31 68.909 ;
     RECT  42.192 68.819 43.614 68.909 ;
     RECT  44.352 68.819 44.694 68.909 ;
     RECT  45.615 68.819 46.206 68.909 ;
     RECT  48.996 68.675 52.074 68.909 ;
     RECT  53.496 68.819 54.234 68.909 ;
     RECT  57.348 68.867 81.27 68.909 ;
     RECT  63.036 68.909 63.954 68.915 ;
     RECT  3.456 68.909 3.618 68.945 ;
     RECT  10.188 68.909 13.374 68.945 ;
     RECT  14.868 68.909 16.146 68.945 ;
     RECT  16.956 68.909 19.062 68.945 ;
     RECT  20.34 68.909 20.358 68.945 ;
     RECT  21.096 68.819 21.366 68.945 ;
     RECT  23.904 68.909 24.57 68.945 ;
     RECT  28.368 68.909 32.886 68.945 ;
     RECT  37.368 68.909 37.386 68.945 ;
     RECT  38.376 68.909 38.934 68.945 ;
     RECT  42.192 68.909 42.822 68.945 ;
     RECT  43.596 68.909 43.614 68.945 ;
     RECT  45.615 68.909 46.062 68.945 ;
     RECT  47.016 68.819 47.25 68.945 ;
     RECT  49.932 68.909 52.074 68.945 ;
     RECT  53.496 68.909 54.09 68.945 ;
     RECT  55.584 68.867 56.505 68.945 ;
     RECT  58.392 68.909 61.905 68.945 ;
     RECT  63.036 68.915 63.522 68.945 ;
     RECT  40.068 68.867 40.305 68.957 ;
     RECT  42.192 68.945 42.606 68.957 ;
     RECT  47.016 68.945 47.178 68.957 ;
     RECT  48.996 68.909 49.014 68.957 ;
     RECT  50.04 68.945 52.074 68.957 ;
     RECT  3.456 68.945 3.474 68.981 ;
     RECT  5.652 68.909 9.306 68.981 ;
     RECT  10.188 68.945 11.826 68.981 ;
     RECT  18.324 68.945 19.062 68.981 ;
     RECT  23.976 68.945 24.57 68.981 ;
     RECT  26.784 68.909 26.802 68.981 ;
     RECT  33.696 68.909 33.714 68.981 ;
     RECT  35.856 68.909 36.342 68.981 ;
     RECT  38.376 68.945 38.862 68.981 ;
     RECT  40.176 68.957 40.305 68.981 ;
     RECT  42.192 68.957 42.57 68.981 ;
     RECT  45.615 68.945 45.918 68.981 ;
     RECT  47.016 68.957 47.034 68.981 ;
     RECT  50.04 68.957 51.606 68.981 ;
     RECT  55.584 68.945 55.602 68.981 ;
     RECT  57.384 68.909 57.618 68.981 ;
     RECT  59.076 68.945 60.39 68.981 ;
     RECT  63.108 68.945 63.126 68.981 ;
     RECT  65.808 68.909 80.838 68.981 ;
     RECT  5.904 68.981 9.054 69.005 ;
     RECT  23.976 68.981 24.498 69.005 ;
     RECT  11.628 68.981 11.826 69.017 ;
     RECT  44.352 68.909 44.37 69.017 ;
     RECT  50.292 68.981 51.606 69.017 ;
     RECT  59.076 68.981 59.094 69.017 ;
     RECT  10.188 68.981 10.782 69.053 ;
     RECT  50.292 69.017 51.105 69.053 ;
     RECT  11.808 69.017 11.826 69.089 ;
     RECT  12.996 68.945 13.305 69.089 ;
     RECT  16.128 68.945 16.146 69.089 ;
     RECT  18.324 68.981 18.705 69.089 ;
     RECT  54.072 68.945 54.09 69.089 ;
     RECT  59.904 68.981 59.922 69.089 ;
     RECT  65.808 68.981 80.766 69.089 ;
     RECT  5.904 69.005 9.018 69.101 ;
     RECT  2.415 68.867 2.505 69.137 ;
     RECT  13.215 69.089 13.305 69.137 ;
     RECT  18.615 69.089 18.705 69.137 ;
     RECT  24.015 69.005 24.105 69.137 ;
     RECT  34.815 68.867 34.905 69.137 ;
     RECT  40.215 68.981 40.305 69.137 ;
     RECT  45.615 68.981 45.705 69.137 ;
     RECT  51.015 69.053 51.105 69.137 ;
     RECT  56.415 68.945 56.505 69.137 ;
     RECT  61.815 68.945 61.905 69.137 ;
     RECT  83.415 68.867 83.505 69.137 ;
     RECT  28.368 68.945 32.274 69.149 ;
     RECT  65.808 69.089 80.298 69.245 ;
     RECT  28.368 69.149 31.77 69.533 ;
     RECT  66.564 69.245 80.298 69.557 ;
     RECT  5.904 69.101 8.982 69.581 ;
     RECT  28.368 69.533 30.726 69.581 ;
     RECT  31.68 69.533 31.77 69.581 ;
     RECT  66.708 69.557 80.298 69.581 ;
     RECT  8.424 69.581 8.982 69.677 ;
     RECT  5.904 69.581 7.65 70.109 ;
     RECT  29.124 69.581 30.726 70.109 ;
     RECT  31.68 69.581 31.698 70.109 ;
     RECT  71.064 69.581 71.226 70.109 ;
     RECT  72.54 69.581 79.11 70.109 ;
     RECT  5.94 70.109 7.65 70.157 ;
     RECT  28.368 69.581 28.386 70.157 ;
     RECT  30.132 70.109 30.726 70.157 ;
     RECT  66.708 69.581 70.002 70.157 ;
     RECT  72.54 70.109 75.474 70.157 ;
     RECT  76.644 70.109 77.562 70.157 ;
     RECT  29.124 70.109 29.394 70.205 ;
     RECT  72.54 70.157 73.278 70.205 ;
     RECT  80.064 69.581 80.298 70.573 ;
     RECT  67.896 70.157 69.57 70.637 ;
     RECT  65.808 69.245 65.826 70.645 ;
     RECT  65.808 70.645 65.898 70.673 ;
     RECT  76.644 70.157 77.274 70.673 ;
     RECT  79.992 70.573 80.298 70.673 ;
     RECT  8.784 69.677 8.982 70.685 ;
     RECT  30.708 70.157 30.726 70.685 ;
     RECT  66.708 70.157 66.87 70.685 ;
     RECT  68.04 70.637 69.57 70.685 ;
     RECT  72.54 70.205 72.558 70.685 ;
     RECT  74.52 70.157 75.474 70.685 ;
     RECT  76.788 70.673 77.274 70.685 ;
     RECT  29.124 70.205 29.142 70.733 ;
     RECT  65.88 70.673 65.898 70.733 ;
     RECT  68.22 70.685 69.57 70.733 ;
     RECT  74.52 70.685 75.222 70.733 ;
     RECT  5.94 70.157 7.182 70.781 ;
     RECT  66.708 70.685 66.726 70.781 ;
     RECT  68.904 70.733 69.246 70.781 ;
     RECT  6.444 70.781 7.182 70.829 ;
     RECT  74.52 70.733 74.646 71.117 ;
     RECT  76.788 70.685 77.202 71.117 ;
     RECT  79.992 70.673 80.082 71.117 ;
     RECT  6.696 70.829 7.182 71.165 ;
     RECT  8.784 70.685 8.802 71.165 ;
     RECT  69.228 70.781 69.246 71.165 ;
     RECT  71.064 70.109 71.082 71.165 ;
     RECT  74.52 71.117 74.538 71.165 ;
     RECT  77.184 71.117 77.202 71.165 ;
     RECT  79.992 71.117 80.01 71.165 ;
    LAYER M4 ;
     RECT  1.061 0.144 1.105 0.168 ;
     RECT  1.105 0.048 1.145 0.168 ;
     RECT  1.277 1.728 1.361 1.752 ;
     RECT  0.997 4.656 1.381 4.68 ;
     RECT  0.901 2.88 1.573 2.904 ;
     RECT  1.189 6.384 2.252 6.408 ;
     RECT  2.185 8.832 2.252 8.856 ;
     RECT  1.573 2.88 2.293 3.624 ;
     RECT  1.381 4.656 2.293 5.16 ;
     RECT  2.252 6.144 2.293 6.408 ;
     RECT  2.252 8.64 2.293 8.856 ;
     RECT  2.252 11.232 2.293 11.256 ;
     RECT  2.293 8.448 2.329 8.856 ;
     RECT  2.293 16.656 2.365 16.68 ;
     RECT  2.293 2.784 2.408 3.624 ;
     RECT  2.293 4.656 2.408 6.888 ;
     RECT  2.329 7.968 2.408 8.856 ;
     RECT  2.293 11.136 2.408 11.256 ;
     RECT  2.293 15.408 2.408 15.432 ;
     RECT  2.365 16.656 2.408 16.92 ;
     RECT  2.365 26.112 2.408 26.136 ;
     RECT  2.365 29.232 2.408 29.256 ;
     RECT  2.329 33.36 2.408 33.384 ;
     RECT  2.329 34.752 2.408 34.776 ;
     RECT  2.365 38.784 2.408 38.808 ;
     RECT  2.365 44.976 2.408 45 ;
     RECT  2.365 47.136 2.408 47.16 ;
     RECT  2.365 57.024 2.408 57.048 ;
     RECT  2.365 66.048 2.408 66.072 ;
     RECT  2.408 2.148 2.512 69.132 ;
     RECT  2.512 2.208 2.704 68.862 ;
     RECT  2.704 34.752 2.801 34.872 ;
     RECT  2.704 5.088 2.819 20.616 ;
     RECT  2.819 16.848 2.867 20.616 ;
     RECT  2.704 44.976 2.873 45 ;
     RECT  2.704 2.208 2.915 4.104 ;
     RECT  2.704 27.936 2.917 29.256 ;
     RECT  2.704 50.16 3.053 50.184 ;
     RECT  2.704 38.688 3.161 38.808 ;
     RECT  2.704 53.04 3.197 53.064 ;
     RECT  2.704 21.648 3.347 26.808 ;
     RECT  2.704 40.032 3.413 41.016 ;
     RECT  2.917 28.128 3.485 29.256 ;
     RECT  2.704 47.136 3.491 47.736 ;
     RECT  2.704 49.008 3.491 49.032 ;
     RECT  3.347 24.48 3.521 26.808 ;
     RECT  3.491 47.712 3.532 47.736 ;
     RECT  2.915 2.208 3.581 3.912 ;
     RECT  3.347 21.648 3.629 22.824 ;
     RECT  3.485 28.128 3.665 29.112 ;
     RECT  3.581 1.776 3.697 3.912 ;
     RECT  3.629 21.648 3.731 22.248 ;
     RECT  2.704 57.024 3.733 58.152 ;
     RECT  2.704 59.808 3.769 59.832 ;
     RECT  2.704 42.432 3.805 42.456 ;
     RECT  2.704 32.544 3.845 33.672 ;
     RECT  1.145 0.048 3.877 0.072 ;
     RECT  2.704 61.2 3.877 61.224 ;
     RECT  2.801 34.848 3.913 34.872 ;
     RECT  2.704 35.904 3.913 35.928 ;
     RECT  3.697 1.728 3.925 3.912 ;
     RECT  2.819 5.088 3.925 15.72 ;
     RECT  2.704 64.944 3.949 66.792 ;
     RECT  2.704 31.44 4.021 31.464 ;
     RECT  3.845 32.544 4.021 33.048 ;
     RECT  3.161 38.688 4.025 38.712 ;
     RECT  3.925 1.728 4.093 15.72 ;
     RECT  2.867 16.896 4.093 20.616 ;
     RECT  3.413 40.992 4.117 41.016 ;
     RECT  3.805 42.432 4.117 43.128 ;
     RECT  4.117 40.992 4.163 43.128 ;
     RECT  3.805 44.88 4.169 44.904 ;
     RECT  4.093 1.728 4.205 20.616 ;
     RECT  4.021 31.44 4.241 33.048 ;
     RECT  3.949 63.984 4.301 66.792 ;
     RECT  2.704 67.776 4.301 68.472 ;
     RECT  3.521 24.48 4.345 26.76 ;
     RECT  4.241 31.44 4.403 31.944 ;
     RECT  3.913 34.176 4.405 35.928 ;
     RECT  4.405 34.176 4.421 36.648 ;
     RECT  4.421 35.28 4.451 36.648 ;
     RECT  4.205 4.464 4.453 20.616 ;
     RECT  4.309 62.64 4.453 62.664 ;
     RECT  4.163 41.616 4.465 43.128 ;
     RECT  4.453 4.464 4.489 20.664 ;
     RECT  3.731 21.648 4.489 22.2 ;
     RECT  3.877 61.2 4.489 61.608 ;
     RECT  4.453 62.64 4.489 62.76 ;
     RECT  3.877 0.048 4.525 0.552 ;
     RECT  4.205 1.728 4.525 3.336 ;
     RECT  3.665 28.464 4.525 29.112 ;
     RECT  4.489 4.464 4.529 22.2 ;
     RECT  4.345 23.952 4.547 26.76 ;
     RECT  3.733 56.688 4.565 58.152 ;
     RECT  4.489 61.2 4.589 62.76 ;
     RECT  4.301 63.984 4.601 68.472 ;
     RECT  4.129 49.776 4.633 49.8 ;
     RECT  4.273 51.072 4.633 51.096 ;
     RECT  4.589 61.008 4.673 62.76 ;
     RECT  4.525 0.048 4.691 3.336 ;
     RECT  3.769 54.096 4.705 54.12 ;
     RECT  2.704 55.104 4.705 55.704 ;
     RECT  4.529 4.512 4.709 22.2 ;
     RECT  4.691 0.048 4.781 0.6 ;
     RECT  4.465 41.76 4.781 43.128 ;
     RECT  3.769 59.568 4.789 59.832 ;
     RECT  4.547 23.952 4.817 26.568 ;
     RECT  4.673 61.488 4.835 62.76 ;
     RECT  4.633 49.776 4.849 51.096 ;
     RECT  4.709 4.512 4.876 22.104 ;
     RECT  4.789 59.568 4.885 60.216 ;
     RECT  4.885 59.28 4.889 60.216 ;
     RECT  4.601 63.984 4.889 68.424 ;
     RECT  4.705 54.096 4.921 55.704 ;
     RECT  4.565 56.688 4.921 58.056 ;
     RECT  4.889 59.28 4.925 59.832 ;
     RECT  4.417 47.76 4.993 47.784 ;
     RECT  4.403 31.44 4.997 31.656 ;
     RECT  4.451 35.28 4.997 35.352 ;
     RECT  4.525 28.464 5.033 29.688 ;
     RECT  4.817 23.952 5.123 25.32 ;
     RECT  4.489 46.752 5.137 46.776 ;
     RECT  4.993 47.76 5.137 47.88 ;
     RECT  4.849 49.776 5.173 51.288 ;
     RECT  4.889 63.984 5.173 64.968 ;
     RECT  4.417 38.16 5.177 38.184 ;
     RECT  5.173 48.96 5.177 51.288 ;
     RECT  4.781 41.76 5.213 42.216 ;
     RECT  4.921 54.096 5.228 58.056 ;
     RECT  4.241 33.024 5.257 33.048 ;
     RECT  4.691 1.728 5.317 3.336 ;
     RECT  5.123 23.952 5.317 24.648 ;
     RECT  4.835 61.584 5.317 62.76 ;
     RECT  5.173 63.84 5.317 64.968 ;
     RECT  5.317 61.584 5.321 64.968 ;
     RECT  4.876 4.608 5.404 22.104 ;
     RECT  5.033 28.752 5.413 29.688 ;
     RECT  4.889 66.096 5.465 68.424 ;
     RECT  4.421 34.176 5.497 34.2 ;
     RECT  5.497 33.6 5.537 34.2 ;
     RECT  5.245 40.704 5.641 40.728 ;
     RECT  5.213 41.76 5.641 41.976 ;
     RECT  5.228 53.952 5.641 58.056 ;
     RECT  5.465 68.4 5.713 68.424 ;
     RECT  5.317 23.376 5.717 24.648 ;
     RECT  4.997 31.44 5.753 31.464 ;
     RECT  5.413 28.752 5.789 30.264 ;
     RECT  5.641 53.04 5.843 58.056 ;
     RECT  5.701 70.128 5.893 70.152 ;
     RECT  4.817 26.544 5.929 26.568 ;
     RECT  4.925 59.28 5.929 59.544 ;
     RECT  5.893 70.08 5.929 70.152 ;
     RECT  5.137 45.792 5.933 47.88 ;
     RECT  5.641 39.936 5.965 41.976 ;
     RECT  5.929 70.08 5.976 70.776 ;
     RECT  5.317 1.728 6.001 3.432 ;
     RECT  5.713 68.4 6.035 68.856 ;
     RECT  4.781 0.576 6.037 0.6 ;
     RECT  6.001 1.68 6.037 3.432 ;
     RECT  4.451 36.48 6.073 36.648 ;
     RECT  5.929 59.232 6.081 59.544 ;
     RECT  6.073 36.48 6.133 37.032 ;
     RECT  5.965 39.312 6.149 41.976 ;
     RECT  6.133 36.432 6.22 37.032 ;
     RECT  4.997 35.328 6.221 35.352 ;
     RECT  5.465 66.096 6.227 67.272 ;
     RECT  5.976 70.032 6.277 70.776 ;
     RECT  5.929 26.064 6.289 26.568 ;
     RECT  5.933 45.792 6.289 47.304 ;
     RECT  6.037 0.576 6.325 3.432 ;
     RECT  5.404 4.608 6.325 22.056 ;
     RECT  6.149 40.656 6.325 41.976 ;
     RECT  5.177 48.96 6.325 49.56 ;
     RECT  6.227 66.096 6.325 67.224 ;
     RECT  6.149 39.312 6.361 39.624 ;
     RECT  5.789 30.048 6.365 30.264 ;
     RECT  6.277 68.976 6.418 70.776 ;
     RECT  6.289 25.824 6.433 26.568 ;
     RECT  5.321 61.584 6.433 64.008 ;
     RECT  6.325 65.52 6.433 67.224 ;
     RECT  6.325 0.576 6.437 22.056 ;
     RECT  5.843 53.184 6.467 58.056 ;
     RECT  6.433 61.584 6.469 67.224 ;
     RECT  5.537 33.6 6.473 34.152 ;
     RECT  6.467 53.184 6.473 57.576 ;
     RECT  6.433 25.824 6.505 27.48 ;
     RECT  5.789 28.752 6.505 28.776 ;
     RECT  6.473 33.984 6.508 34.152 ;
     RECT  6.325 48.96 6.541 49.608 ;
     RECT  5.177 50.64 6.541 51.288 ;
     RECT  6.081 59.136 6.572 59.544 ;
     RECT  6.541 48.96 6.577 51.288 ;
     RECT  6.037 31.776 6.613 31.944 ;
     RECT  6.572 59.136 6.613 60.264 ;
     RECT  6.418 68.976 6.641 70.824 ;
     RECT  6.229 23.328 6.649 23.352 ;
     RECT  6.22 36.528 6.653 37.032 ;
     RECT  6.577 48.96 6.661 51.336 ;
     RECT  6.437 0.576 6.707 5.688 ;
     RECT  6.661 48.96 6.757 51.288 ;
     RECT  6.649 23.088 6.793 23.352 ;
     RECT  5.717 24.528 6.793 24.648 ;
     RECT  6.289 45.552 6.805 47.304 ;
     RECT  6.613 58.608 6.805 60.264 ;
     RECT  6.805 58.608 6.829 60.312 ;
     RECT  6.469 61.296 6.829 67.224 ;
     RECT  6.473 53.184 6.865 57.384 ;
     RECT  6.505 25.824 6.901 28.776 ;
     RECT  6.361 39.264 6.901 39.624 ;
     RECT  6.901 25.728 6.973 28.776 ;
     RECT  6.973 25.728 7.045 29.064 ;
     RECT  6.365 30.048 7.045 30.072 ;
     RECT  6.707 1.728 7.193 5.688 ;
     RECT  6.217 43.872 7.297 43.896 ;
     RECT  6.805 45.552 7.297 46.92 ;
     RECT  7.193 1.776 7.301 5.688 ;
     RECT  7.301 1.824 7.373 5.688 ;
     RECT  7.189 0.144 7.379 0.168 ;
     RECT  7.373 2.016 7.541 5.688 ;
     RECT  6.437 6.672 7.541 22.056 ;
     RECT  6.865 52.992 7.549 57.384 ;
     RECT  6.829 58.608 7.549 67.224 ;
     RECT  6.613 31.776 7.621 32.52 ;
     RECT  6.653 36.528 7.657 36.936 ;
     RECT  6.757 48.912 7.669 51.288 ;
     RECT  7.669 48.432 7.693 51.288 ;
     RECT  7.549 52.992 7.693 67.224 ;
     RECT  6.793 23.088 7.801 24.648 ;
     RECT  7.541 2.016 7.808 22.056 ;
     RECT  7.801 23.088 7.808 24.696 ;
     RECT  7.045 25.728 7.808 30.072 ;
     RECT  7.621 31.68 7.808 32.52 ;
     RECT  6.721 34.224 7.808 34.248 ;
     RECT  7.657 36 7.808 36.936 ;
     RECT  6.901 39.216 7.808 39.624 ;
     RECT  6.325 40.656 7.808 42.6 ;
     RECT  7.297 43.872 7.808 46.92 ;
     RECT  7.693 48.384 7.808 51.288 ;
     RECT  7.693 52.704 7.808 67.224 ;
     RECT  6.641 68.976 7.808 71.16 ;
     RECT  7.808 2.016 7.859 71.16 ;
     RECT  7.859 2.016 8.104 69.672 ;
     RECT  8.104 23.088 8.129 30.072 ;
     RECT  8.104 52.512 8.243 59.88 ;
     RECT  8.104 66.72 8.273 66.888 ;
     RECT  8.273 66.72 8.417 66.744 ;
     RECT  8.104 67.872 8.453 69.672 ;
     RECT  8.129 24.144 8.461 30.072 ;
     RECT  8.104 31.392 8.531 51.288 ;
     RECT  8.453 67.872 8.561 69.528 ;
     RECT  8.104 2.016 8.629 22.056 ;
     RECT  8.461 28.704 8.705 30.072 ;
     RECT  8.531 32.976 8.741 51.288 ;
     RECT  8.104 61.344 8.741 64.44 ;
     RECT  7.859 70.656 8.813 71.16 ;
     RECT  8.461 24.144 8.885 27.48 ;
     RECT  8.561 67.872 8.957 69.096 ;
     RECT  8.813 70.656 8.993 70.68 ;
     RECT  8.705 30.048 9.029 30.072 ;
     RECT  8.957 68.976 9.029 69.096 ;
     RECT  9.029 68.976 9.065 69.048 ;
     RECT  8.741 32.976 9.101 37.464 ;
     RECT  8.741 38.544 9.133 51.288 ;
     RECT  9.133 38.544 9.173 51.432 ;
     RECT  8.531 31.392 9.209 31.992 ;
     RECT  8.741 61.536 9.245 64.44 ;
     RECT  8.629 1.68 9.277 22.056 ;
     RECT  9.245 62.064 9.281 64.44 ;
     RECT  9.277 1.2 9.389 22.056 ;
     RECT  9.101 35.328 9.569 37.464 ;
     RECT  8.243 52.512 9.685 59.736 ;
     RECT  9.389 1.2 9.709 14.856 ;
     RECT  9.281 62.064 9.713 63.864 ;
     RECT  9.709 1.152 9.781 14.856 ;
     RECT  9.569 35.328 9.785 36.552 ;
     RECT  9.685 52.512 9.785 60.552 ;
     RECT  9.785 35.856 9.821 36.552 ;
     RECT  8.885 24.144 9.857 26.952 ;
     RECT  9.781 0.576 9.875 14.856 ;
     RECT  9.785 52.56 9.923 60.552 ;
     RECT  9.923 52.56 9.929 58.104 ;
     RECT  8.705 28.704 10.033 28.968 ;
     RECT  9.875 1.2 10.067 14.856 ;
     RECT  9.857 24.192 10.069 26.952 ;
     RECT  10.033 28.704 10.069 29.784 ;
     RECT  9.929 52.56 10.109 58.056 ;
     RECT  9.097 67.824 10.141 67.848 ;
     RECT  10.069 24.192 10.177 29.784 ;
     RECT  10.177 24.192 10.213 30.216 ;
     RECT  9.209 31.392 10.213 31.944 ;
     RECT  9.923 59.184 10.217 60.552 ;
     RECT  9.065 69.024 10.217 69.048 ;
     RECT  9.173 38.736 10.253 51.432 ;
     RECT  10.217 59.712 10.253 60.552 ;
     RECT  10.213 24.192 10.261 31.944 ;
     RECT  10.253 38.736 10.285 47.88 ;
     RECT  9.713 62.112 10.289 63.864 ;
     RECT  10.261 30.864 10.321 31.944 ;
     RECT  9.101 32.976 10.321 34.344 ;
     RECT  10.289 62.16 10.321 63.864 ;
     RECT  9.277 65.664 10.321 65.688 ;
     RECT  10.261 24.192 10.325 29.784 ;
     RECT  10.321 62.16 10.325 65.688 ;
     RECT  10.253 48.912 10.397 51.432 ;
     RECT  10.325 64.752 10.429 65.688 ;
     RECT  10.067 1.728 10.477 14.856 ;
     RECT  10.321 30.864 10.537 34.344 ;
     RECT  10.325 28.704 10.577 29.784 ;
     RECT  10.429 64.752 10.645 66.312 ;
     RECT  10.141 67.392 10.645 67.848 ;
     RECT  10.577 29.76 10.649 29.784 ;
     RECT  10.253 59.712 10.649 59.736 ;
     RECT  10.325 62.16 10.685 63.576 ;
     RECT  9.821 36.528 10.717 36.552 ;
     RECT  10.325 24.192 10.739 27.384 ;
     RECT  10.109 52.56 10.753 58.008 ;
     RECT  10.477 1.728 10.757 1.848 ;
     RECT  9.389 15.84 10.757 22.056 ;
     RECT  10.645 64.752 10.757 67.848 ;
     RECT  10.397 50.112 10.825 51.432 ;
     RECT  10.753 52.416 10.825 58.008 ;
     RECT  10.757 67.296 10.825 67.848 ;
     RECT  10.757 1.776 10.829 1.848 ;
     RECT  8.129 23.088 10.861 23.112 ;
     RECT  10.861 23.04 10.897 23.112 ;
     RECT  10.739 24.192 10.897 26.904 ;
     RECT  10.825 67.296 10.937 68.136 ;
     RECT  10.757 20.112 11.005 22.056 ;
     RECT  10.897 23.04 11.005 26.904 ;
     RECT  10.285 38.64 11.045 47.88 ;
     RECT  10.477 3.168 11.221 14.856 ;
     RECT  10.757 15.84 11.221 18.984 ;
     RECT  10.537 30.864 11.225 34.488 ;
     RECT  10.577 28.704 11.293 28.776 ;
     RECT  11.045 39.072 11.293 47.88 ;
     RECT  10.397 48.912 11.293 48.984 ;
     RECT  11.225 30.864 11.365 31.224 ;
     RECT  10.685 62.592 11.365 63.576 ;
     RECT  10.757 64.752 11.365 65.688 ;
     RECT  10.825 50.112 11.413 58.008 ;
     RECT  11.365 62.592 11.477 65.688 ;
     RECT  11.293 28.464 11.545 28.776 ;
     RECT  11.545 27.888 11.653 28.776 ;
     RECT  11.413 50.016 11.653 58.008 ;
     RECT  10.829 1.824 11.657 1.848 ;
     RECT  11.477 62.64 11.749 65.688 ;
     RECT  10.937 67.296 11.749 67.32 ;
     RECT  11.749 62.64 11.795 67.32 ;
     RECT  11.795 66.48 11.837 67.32 ;
     RECT  11.833 59.424 11.869 59.448 ;
     RECT  11.225 32.688 11.941 34.488 ;
     RECT  10.717 36.528 11.941 37.032 ;
     RECT  11.653 50.016 11.941 58.152 ;
     RECT  11.869 59.328 11.941 60.216 ;
     RECT  11.653 27.888 12.037 29.304 ;
     RECT  11.365 30.336 12.037 31.224 ;
     RECT  11.005 20.112 12.053 26.904 ;
     RECT  12.053 23.088 12.085 26.904 ;
     RECT  12.037 27.888 12.085 31.224 ;
     RECT  11.941 50.016 12.125 60.216 ;
     RECT  11.941 36.048 12.131 37.032 ;
     RECT  12.125 52.56 12.193 60.216 ;
     RECT  11.941 32.688 12.265 35.016 ;
     RECT  11.221 3.168 12.373 18.984 ;
     RECT  12.053 20.112 12.373 22.056 ;
     RECT  12.193 52.56 12.38 60.648 ;
     RECT  12.013 61.632 12.38 61.656 ;
     RECT  12.373 3.168 12.445 22.056 ;
     RECT  12.38 52.56 12.445 61.656 ;
     RECT  11.795 62.64 12.445 65.4 ;
     RECT  11.293 39.072 12.481 48.984 ;
     RECT  12.481 38.688 12.553 48.984 ;
     RECT  12.125 50.016 12.553 51.48 ;
     RECT  12.085 23.088 12.589 31.224 ;
     RECT  12.265 32.304 12.589 35.016 ;
     RECT  12.553 38.688 12.589 51.48 ;
     RECT  11.837 67.296 12.877 67.32 ;
     RECT  12.589 23.088 12.901 35.016 ;
     RECT  12.131 36.048 12.901 36.936 ;
     RECT  12.445 3.024 12.949 22.056 ;
     RECT  12.229 0.48 13.093 0.504 ;
     RECT  12.769 1.728 13.093 1.752 ;
     RECT  12.949 2.88 13.093 22.056 ;
     RECT  12.589 38.496 13.093 51.48 ;
     RECT  12.445 52.56 13.093 65.4 ;
     RECT  13.093 0.48 13.165 0.6 ;
     RECT  13.093 1.728 13.165 22.056 ;
     RECT  12.901 23.088 13.165 36.936 ;
     RECT  13.165 1.728 13.208 36.936 ;
     RECT  13.093 38.496 13.208 65.4 ;
     RECT  12.877 67.296 13.208 67.704 ;
     RECT  13.165 0.096 13.249 0.6 ;
     RECT  13.208 1.728 13.312 69.132 ;
     RECT  13.312 1.728 13.504 68.862 ;
     RECT  13.249 0.48 13.619 0.6 ;
     RECT  13.504 36.048 13.673 63.528 ;
     RECT  13.504 1.728 14.537 34.728 ;
     RECT  13.619 0.576 14.581 0.6 ;
     RECT  13.673 36.048 14.681 54.408 ;
     RECT  13.673 55.44 14.681 63.528 ;
     RECT  14.681 62.16 14.771 63.528 ;
     RECT  14.771 62.256 14.789 63.528 ;
     RECT  13.504 64.656 14.789 68.712 ;
     RECT  14.789 62.304 14.965 63.528 ;
     RECT  14.789 64.656 14.965 67.848 ;
     RECT  14.537 3.168 15.073 34.728 ;
     RECT  14.681 36.048 15.073 36.6 ;
     RECT  14.681 37.584 15.203 54.408 ;
     RECT  14.965 62.304 15.689 67.848 ;
     RECT  15.073 3.168 15.725 36.6 ;
     RECT  14.537 1.728 15.865 1.944 ;
     RECT  15.725 3.168 15.865 34.776 ;
     RECT  14.681 55.44 15.973 60.984 ;
     RECT  15.689 62.304 15.973 63.576 ;
     RECT  15.109 0.096 16.037 0.12 ;
     RECT  16.037 0.096 16.081 0.168 ;
     RECT  16.081 0.048 16.121 0.168 ;
     RECT  15.865 1.728 16.211 34.776 ;
     RECT  15.689 64.656 16.225 67.848 ;
     RECT  15.973 55.44 16.403 63.576 ;
     RECT  16.211 1.776 16.481 34.776 ;
     RECT  16.481 2.736 16.909 34.776 ;
     RECT  15.725 36.048 16.909 36.6 ;
     RECT  15.203 38.496 17.053 54.408 ;
     RECT  16.403 55.44 17.053 63.528 ;
     RECT  17.053 38.496 17.485 63.528 ;
     RECT  16.225 64.656 17.485 67.896 ;
     RECT  16.909 2.736 17.564 36.6 ;
     RECT  17.564 2.736 18.061 36.744 ;
     RECT  17.485 38.496 18.229 67.896 ;
     RECT  18.061 2.592 18.313 36.744 ;
     RECT  18.313 2.496 18.608 36.744 ;
     RECT  18.229 38.496 18.608 68.472 ;
     RECT  18.608 2.148 18.712 69.132 ;
     RECT  18.712 2.304 18.904 68.862 ;
     RECT  18.904 2.304 19.42 68.472 ;
     RECT  19.42 38.16 19.865 68.472 ;
     RECT  16.121 0.048 20.005 0.072 ;
     RECT  19.42 2.304 20.005 37.128 ;
     RECT  20.005 0.048 20.156 0.168 ;
     RECT  20.005 1.728 20.156 37.128 ;
     RECT  20.156 0.048 20.225 37.128 ;
     RECT  20.225 27.744 21.013 37.128 ;
     RECT  20.225 0.048 21.299 26.76 ;
     RECT  21.299 1.68 21.337 26.76 ;
     RECT  21.013 27.744 21.337 37.416 ;
     RECT  21.299 0.048 21.817 0.6 ;
     RECT  19.865 38.496 21.877 68.472 ;
     RECT  21.817 0.048 22.885 0.072 ;
     RECT  22.885 0.048 23.137 0.6 ;
     RECT  21.337 1.68 23.137 37.416 ;
     RECT  21.877 38.496 23.137 68.76 ;
     RECT  23.137 0.048 23.795 68.76 ;
     RECT  23.795 1.728 23.965 68.76 ;
     RECT  23.965 1.728 24.008 69 ;
     RECT  24.008 1.728 24.112 69.132 ;
     RECT  24.112 1.728 24.509 69 ;
     RECT  24.509 1.728 25.619 68.712 ;
     RECT  23.795 0.048 25.657 0.552 ;
     RECT  25.657 0.048 25.669 0.6 ;
     RECT  25.619 1.728 25.669 37.464 ;
     RECT  25.669 0.048 25.769 37.464 ;
     RECT  25.769 0.048 26.018 0.6 ;
     RECT  26.018 0.048 26.291 0.552 ;
     RECT  25.769 1.728 27.133 37.464 ;
     RECT  27.133 1.104 27.241 37.464 ;
     RECT  25.619 38.496 27.241 68.712 ;
     RECT  27.241 1.104 27.539 68.712 ;
     RECT  26.291 0.048 27.961 0.072 ;
     RECT  27.961 0.048 28.045 0.6 ;
     RECT  27.539 1.728 28.645 68.712 ;
     RECT  28.645 1.728 28.681 69 ;
     RECT  28.357 70.128 28.681 70.152 ;
     RECT  28.681 1.728 29.084 70.152 ;
     RECT  29.084 1.728 29.173 70.728 ;
     RECT  29.173 1.728 29.459 71.112 ;
     RECT  29.459 1.728 29.651 70.2 ;
     RECT  29.651 1.728 30.125 69.048 ;
     RECT  29.651 70.08 30.323 70.2 ;
     RECT  30.125 2.208 30.413 69.048 ;
     RECT  30.469 70.608 30.769 70.68 ;
     RECT  30.769 70.608 30.947 70.632 ;
     RECT  30.413 2.784 30.949 69.048 ;
     RECT  30.949 2.784 31.429 69.528 ;
     RECT  31.429 2.784 31.709 70.104 ;
     RECT  31.709 2.784 31.781 69.576 ;
     RECT  31.781 2.784 32.285 69.144 ;
     RECT  32.285 2.784 34.808 68.712 ;
     RECT  34.808 2.148 34.912 69.132 ;
     RECT  34.912 2.418 35.104 68.862 ;
     RECT  35.104 2.784 36.277 68.856 ;
     RECT  36.277 2.4 36.353 68.856 ;
     RECT  36.353 2.4 37.217 68.808 ;
     RECT  37.217 2.736 37.361 68.808 ;
     RECT  37.361 2.736 37.433 68.76 ;
     RECT  37.433 2.784 37.685 68.76 ;
     RECT  37.685 2.784 38.725 68.712 ;
     RECT  38.725 2.784 38.761 68.76 ;
     RECT  38.761 2.496 39.085 68.76 ;
     RECT  39.085 2.496 39.121 68.904 ;
     RECT  39.121 2.304 39.205 68.904 ;
     RECT  39.205 1.728 39.229 68.904 ;
     RECT  39.229 1.104 39.635 68.904 ;
     RECT  28.045 0.048 39.877 0.072 ;
     RECT  39.877 0.048 40.019 0.312 ;
     RECT  39.635 1.728 40.057 68.904 ;
     RECT  40.057 1.728 40.208 68.952 ;
     RECT  40.208 1.728 40.259 69.132 ;
     RECT  40.259 1.776 40.312 69.132 ;
     RECT  40.019 0.048 40.451 0.264 ;
     RECT  40.312 1.776 40.451 68.952 ;
     RECT  40.451 0.048 40.787 0.072 ;
     RECT  40.451 2.352 41.897 68.952 ;
     RECT  41.897 2.352 42.041 33.096 ;
     RECT  42.041 2.4 42.221 33.096 ;
     RECT  41.897 34.416 42.617 68.952 ;
     RECT  42.617 34.416 42.761 68.712 ;
     RECT  42.761 34.416 43.333 51.72 ;
     RECT  43.333 34.32 43.841 51.72 ;
     RECT  43.841 41.376 43.873 51.72 ;
     RECT  43.841 34.416 43.949 40.392 ;
     RECT  42.221 2.4 44.125 32.808 ;
     RECT  42.761 52.752 44.273 68.712 ;
     RECT  44.273 67.872 44.377 68.712 ;
     RECT  44.377 67.872 44.561 68.76 ;
     RECT  43.949 34.416 44.809 40.152 ;
     RECT  43.873 41.376 45.061 51.768 ;
     RECT  44.273 52.752 45.061 66.84 ;
     RECT  44.125 2.304 45.608 32.808 ;
     RECT  44.809 34.128 45.608 40.152 ;
     RECT  45.061 41.376 45.608 66.84 ;
     RECT  44.561 67.968 45.608 68.76 ;
     RECT  45.608 2.148 45.712 69.132 ;
     RECT  45.712 2.304 45.904 68.952 ;
     RECT  45.904 27.648 46.181 40.152 ;
     RECT  45.904 2.304 46.217 26.136 ;
     RECT  45.904 59.76 46.505 68.952 ;
     RECT  45.904 44.64 46.541 51.768 ;
     RECT  45.904 52.752 46.541 54.744 ;
     RECT  46.505 59.76 46.613 66.216 ;
     RECT  46.181 30.336 46.649 40.152 ;
     RECT  46.505 67.296 46.649 68.952 ;
     RECT  46.541 44.64 46.685 51.72 ;
     RECT  46.217 2.304 46.721 20.616 ;
     RECT  46.217 21.792 46.933 26.136 ;
     RECT  46.181 27.648 46.933 29.352 ;
     RECT  45.904 41.376 47.189 43.656 ;
     RECT  46.649 68.736 47.189 68.952 ;
     RECT  45.904 55.968 47.221 58.488 ;
     RECT  46.649 30.336 47.261 32.808 ;
     RECT  47.261 30.336 47.405 31.8 ;
     RECT  47.405 30.336 47.477 31.752 ;
     RECT  47.261 32.784 47.653 32.808 ;
     RECT  46.649 34.176 47.653 40.152 ;
     RECT  46.649 67.296 47.701 67.704 ;
     RECT  47.189 68.736 47.701 68.808 ;
     RECT  46.613 60.24 47.725 66.216 ;
     RECT  47.701 67.296 47.725 68.808 ;
     RECT  46.685 44.928 47.729 51.72 ;
     RECT  47.725 60.24 47.747 68.808 ;
     RECT  46.933 21.792 47.761 29.352 ;
     RECT  47.729 44.928 47.761 45.816 ;
     RECT  47.761 21.648 47.765 29.352 ;
     RECT  47.653 32.784 47.797 40.2 ;
     RECT  46.721 2.304 47.801 20.424 ;
     RECT  47.801 14.64 47.837 20.424 ;
     RECT  47.765 21.648 47.909 25.464 ;
     RECT  47.797 32.784 47.945 40.392 ;
     RECT  47.729 46.8 47.945 51.72 ;
     RECT  47.221 55.968 48.013 59.112 ;
     RECT  47.747 60.24 48.013 68.424 ;
     RECT  47.945 48.432 48.017 51.72 ;
     RECT  48.013 55.968 48.125 68.424 ;
     RECT  48.017 48.432 48.161 48.552 ;
     RECT  48.125 55.968 48.197 56.088 ;
     RECT  47.189 41.376 48.233 43.08 ;
     RECT  47.945 34.8 48.409 40.392 ;
     RECT  48.233 41.376 48.409 41.496 ;
     RECT  48.125 57.168 48.485 68.424 ;
     RECT  47.761 44.88 48.557 45.816 ;
     RECT  48.485 64.896 48.629 68.424 ;
     RECT  48.233 42.768 48.701 43.08 ;
     RECT  48.485 57.168 48.773 63.672 ;
     RECT  47.801 2.304 48.809 13.176 ;
     RECT  48.809 2.832 48.877 13.176 ;
     RECT  47.837 14.64 48.877 20.088 ;
     RECT  48.017 49.776 48.877 51.72 ;
     RECT  46.541 53.088 48.877 54.744 ;
     RECT  47.909 21.792 48.985 25.464 ;
     RECT  47.945 32.784 48.985 33.432 ;
     RECT  48.409 34.8 48.989 41.496 ;
     RECT  47.477 30.336 49.021 31.464 ;
     RECT  48.877 49.776 49.025 54.744 ;
     RECT  48.773 57.168 49.025 59.208 ;
     RECT  49.025 57.312 49.061 59.208 ;
     RECT  49.025 51.696 49.129 54.744 ;
     RECT  49.129 51.696 49.133 54.792 ;
     RECT  48.197 56.064 49.201 56.088 ;
     RECT  48.985 32.736 49.237 33.432 ;
     RECT  48.989 34.8 49.237 40.2 ;
     RECT  48.985 21.264 49.309 25.464 ;
     RECT  47.765 26.832 49.309 29.352 ;
     RECT  48.989 41.376 49.309 41.496 ;
     RECT  49.025 49.776 49.313 50.616 ;
     RECT  48.557 44.88 49.333 45.72 ;
     RECT  49.201 55.824 49.421 56.088 ;
     RECT  48.773 60.528 49.525 63.672 ;
     RECT  48.629 64.896 49.525 67.8 ;
     RECT  49.309 21.264 49.633 29.352 ;
     RECT  49.237 32.736 49.673 40.2 ;
     RECT  49.673 34.08 49.781 40.2 ;
     RECT  49.133 53.088 49.813 54.792 ;
     RECT  49.421 55.824 49.813 55.848 ;
     RECT  48.877 2.832 49.849 20.088 ;
     RECT  49.633 21.168 49.849 29.352 ;
     RECT  49.813 53.088 49.853 55.848 ;
     RECT  49.061 58.656 49.921 59.208 ;
     RECT  49.525 60.528 49.921 67.8 ;
     RECT  49.849 2.832 49.925 29.352 ;
     RECT  48.701 43.056 50.137 43.08 ;
     RECT  49.333 44.112 50.137 45.72 ;
     RECT  49.925 27.12 50.209 29.352 ;
     RECT  49.021 30.336 50.209 31.56 ;
     RECT  50.137 43.056 50.209 45.72 ;
     RECT  48.161 48.432 50.209 48.456 ;
     RECT  49.921 58.656 50.461 67.896 ;
     RECT  48.985 68.88 50.461 68.952 ;
     RECT  47.945 46.8 50.485 47.16 ;
     RECT  50.209 48.384 50.485 48.456 ;
     RECT  49.313 49.776 50.533 50.472 ;
     RECT  49.133 51.696 50.533 51.768 ;
     RECT  50.533 49.776 50.569 51.768 ;
     RECT  49.853 53.088 50.569 55.416 ;
     RECT  49.309 41.376 50.605 42.072 ;
     RECT  50.209 43.056 50.605 45.768 ;
     RECT  49.781 35.232 50.713 40.2 ;
     RECT  50.605 41.376 50.713 45.768 ;
     RECT  50.485 46.8 50.741 48.456 ;
     RECT  50.713 35.232 50.749 45.768 ;
     RECT  50.741 46.8 50.749 48.504 ;
     RECT  49.061 57.312 50.749 57.432 ;
     RECT  50.461 58.656 50.749 68.952 ;
     RECT  49.673 32.736 50.785 32.808 ;
     RECT  49.781 34.08 50.785 34.104 ;
     RECT  50.569 49.776 50.828 55.416 ;
     RECT  50.828 49.776 50.849 55.512 ;
     RECT  50.209 27.12 50.869 31.56 ;
     RECT  50.785 32.736 50.869 34.104 ;
     RECT  50.749 35.232 50.869 48.504 ;
     RECT  50.849 49.584 50.869 55.512 ;
     RECT  49.925 2.832 51.008 26.136 ;
     RECT  50.869 27.12 51.008 34.104 ;
     RECT  50.869 35.232 51.008 55.512 ;
     RECT  50.749 56.64 51.008 68.952 ;
     RECT  51.008 2.148 51.112 69.132 ;
     RECT  51.112 2.418 51.304 68.952 ;
     RECT  51.304 44.88 51.365 48.84 ;
     RECT  51.304 34.848 51.473 43.08 ;
     RECT  51.304 61.584 51.545 68.952 ;
     RECT  51.365 44.88 51.581 45.768 ;
     RECT  51.473 34.848 51.653 42.744 ;
     RECT  51.304 60.384 51.653 60.6 ;
     RECT  51.545 61.584 51.676 66.312 ;
     RECT  51.653 34.848 51.761 41.784 ;
     RECT  51.676 61.968 51.797 66.312 ;
     RECT  51.304 2.832 51.905 25.464 ;
     RECT  51.304 54.576 51.971 55.896 ;
     RECT  51.971 54.576 51.977 54.696 ;
     RECT  51.761 34.848 52.013 41.688 ;
     RECT  51.365 46.8 52.013 48.84 ;
     RECT  51.304 49.824 52.013 53.064 ;
     RECT  52.013 49.824 52.019 52.344 ;
     RECT  51.971 55.68 52.019 55.896 ;
     RECT  51.977 54.576 52.021 54.6 ;
     RECT  51.304 29.328 52.049 32.136 ;
     RECT  51.581 44.88 52.085 45.24 ;
     RECT  51.545 67.296 52.085 68.952 ;
     RECT  51.905 2.832 52.121 20.136 ;
     RECT  51.304 57.408 52.121 58.248 ;
     RECT  52.013 48.816 52.157 48.84 ;
     RECT  52.085 67.296 52.301 68.088 ;
     RECT  52.085 44.88 52.337 44.952 ;
     RECT  52.121 58.128 52.477 58.248 ;
     RECT  52.121 2.832 52.553 19.272 ;
     RECT  51.905 21.792 52.589 25.464 ;
     RECT  52.013 34.848 52.589 40.392 ;
     RECT  52.301 67.392 52.625 68.088 ;
     RECT  52.553 2.832 52.697 19.08 ;
     RECT  51.797 65.472 52.765 66.312 ;
     RECT  52.019 55.68 52.769 55.704 ;
     RECT  51.304 26.688 52.801 28.2 ;
     RECT  52.589 24.72 52.913 25.464 ;
     RECT  52.801 26.496 52.913 28.2 ;
     RECT  52.013 41.376 52.985 41.688 ;
     RECT  52.477 58.128 53.017 59.208 ;
     RECT  52.913 26.496 53.021 27.144 ;
     RECT  52.589 21.792 53.057 23.688 ;
     RECT  53.057 21.792 53.093 23.112 ;
     RECT  52.019 51.696 53.161 52.344 ;
     RECT  52.697 2.832 53.201 17.64 ;
     RECT  52.913 28.176 53.201 28.2 ;
     RECT  52.589 34.848 53.201 39.384 ;
     RECT  53.201 34.848 53.228 38.568 ;
     RECT  51.797 61.968 53.237 63.672 ;
     RECT  52.589 40.368 53.269 40.392 ;
     RECT  53.228 34.752 53.315 38.568 ;
     RECT  53.237 62.16 53.341 63.672 ;
     RECT  52.765 64.896 53.341 66.312 ;
     RECT  53.201 2.832 53.345 17.496 ;
     RECT  53.017 58.128 53.363 59.448 ;
     RECT  53.315 35.232 53.381 38.568 ;
     RECT  53.381 35.232 53.417 35.688 ;
     RECT  52.013 46.8 53.453 47.688 ;
     RECT  52.625 67.392 53.485 67.608 ;
     RECT  52.913 25.104 53.525 25.464 ;
     RECT  53.053 44.16 53.525 44.184 ;
     RECT  53.021 26.496 53.557 26.952 ;
     RECT  53.341 62.16 53.561 66.312 ;
     RECT  52.049 29.568 53.633 32.136 ;
     RECT  53.485 67.344 53.633 67.608 ;
     RECT  53.093 21.792 53.669 23.064 ;
     RECT  53.633 67.344 53.705 67.56 ;
     RECT  53.363 58.128 53.741 59.208 ;
     RECT  53.197 42.144 53.773 42.168 ;
     RECT  53.161 51.6 53.777 52.344 ;
     RECT  53.557 26.208 53.813 26.952 ;
     RECT  53.633 29.568 53.885 30.936 ;
     RECT  53.449 56.832 53.885 56.856 ;
     RECT  53.773 42.144 53.953 42.456 ;
     RECT  53.845 43.536 53.953 44.136 ;
     RECT  53.885 29.616 53.957 30.936 ;
     RECT  53.809 55.824 53.989 55.848 ;
     RECT  53.957 30.576 53.993 30.936 ;
     RECT  53.741 58.128 54.025 58.248 ;
     RECT  54.025 57.552 54.029 58.248 ;
     RECT  53.989 55.824 54.076 56.52 ;
     RECT  54.029 57.552 54.109 58.152 ;
     RECT  54.109 58.128 54.173 58.152 ;
     RECT  53.561 63.648 54.209 66.312 ;
     RECT  53.669 22.464 54.229 23.064 ;
     RECT  53.381 36.672 54.241 38.568 ;
     RECT  53.525 25.104 54.275 25.128 ;
     RECT  53.777 51.696 54.281 52.344 ;
     RECT  51.653 60.576 54.313 60.6 ;
     RECT  54.313 60.576 54.317 61.08 ;
     RECT  54.281 52.224 54.389 52.344 ;
     RECT  53.345 2.832 54.421 17.304 ;
     RECT  54.38 27.216 54.467 27.24 ;
     RECT  53.417 35.664 54.529 35.688 ;
     RECT  52.477 54.48 54.529 54.504 ;
     RECT  53.813 26.208 54.533 26.232 ;
     RECT  53.993 30.912 54.533 30.936 ;
     RECT  53.269 40.368 54.569 40.872 ;
     RECT  54.457 59.376 54.569 59.4 ;
     RECT  54.529 35.568 54.637 35.688 ;
     RECT  53.953 42.144 54.677 44.136 ;
     RECT  54.637 35.232 54.709 35.688 ;
     RECT  54.229 22.464 54.713 23.88 ;
     RECT  54.421 2.784 54.749 17.304 ;
     RECT  54.709 34.992 54.781 35.688 ;
     RECT  54.241 36.672 54.781 39.24 ;
     RECT  54.097 45.504 54.781 45.624 ;
     RECT  53.561 62.16 54.781 62.376 ;
     RECT  52.019 49.824 54.821 50.136 ;
     RECT  54.569 40.416 54.853 40.872 ;
     RECT  54.677 42.144 54.853 43.32 ;
     RECT  54.781 44.64 54.893 45.624 ;
     RECT  54.529 54.48 54.893 54.648 ;
     RECT  53.701 21.408 55.037 21.432 ;
     RECT  54.713 22.464 55.037 23.064 ;
     RECT  53.633 32.112 55.037 32.136 ;
     RECT  54.025 33.648 55.093 33.672 ;
     RECT  55.093 32.88 55.139 33.672 ;
     RECT  55.139 32.88 55.181 32.904 ;
     RECT  54.749 14.784 55.253 17.304 ;
     RECT  54.209 63.648 55.253 66.168 ;
     RECT  55.253 63.648 55.325 65.304 ;
     RECT  54.076 55.824 55.361 55.848 ;
     RECT  54.317 61.056 55.361 61.08 ;
     RECT  53.705 67.536 55.573 67.56 ;
     RECT  52.697 19.056 55.609 19.08 ;
     RECT  53.453 46.8 55.645 47.592 ;
     RECT  54.389 52.32 55.717 52.344 ;
     RECT  55.573 67.536 55.717 67.848 ;
     RECT  54.821 49.824 55.789 49.896 ;
     RECT  54.893 44.64 55.797 45.192 ;
     RECT  55.037 22.464 55.825 23.016 ;
     RECT  55.717 52.032 56.005 52.344 ;
     RECT  55.797 44.352 56.053 45.192 ;
     RECT  55.645 46.8 56.053 47.64 ;
     RECT  55.681 26.352 56.077 26.376 ;
     RECT  56.005 51.504 56.185 52.344 ;
     RECT  55.253 14.784 56.285 16.68 ;
     RECT  56.053 44.352 56.293 47.64 ;
     RECT  55.717 66.72 56.293 67.848 ;
     RECT  54.893 54.48 56.365 54.504 ;
     RECT  54.749 2.784 56.408 12.888 ;
     RECT  56.285 14.256 56.408 16.68 ;
     RECT  55.609 18.144 56.408 19.08 ;
     RECT  55.825 21.936 56.408 23.016 ;
     RECT  56.077 26.352 56.408 26.808 ;
     RECT  54.421 28.416 56.408 28.44 ;
     RECT  56.329 33.6 56.408 33.624 ;
     RECT  54.781 34.992 56.408 39.24 ;
     RECT  54.853 40.416 56.408 43.32 ;
     RECT  56.293 44.352 56.408 47.688 ;
     RECT  55.789 49.056 56.408 49.896 ;
     RECT  56.185 51.168 56.408 52.344 ;
     RECT  56.365 53.568 56.408 54.504 ;
     RECT  55.825 57.696 56.408 57.72 ;
     RECT  55.681 59.184 56.408 59.208 ;
     RECT  55.501 61.104 56.408 61.128 ;
     RECT  54.781 62.16 56.408 62.424 ;
     RECT  55.325 63.648 56.408 64.344 ;
     RECT  56.293 66.72 56.408 68.184 ;
     RECT  56.408 2.148 56.512 69.132 ;
     RECT  56.512 2.418 56.704 68.862 ;
     RECT  56.704 14.736 56.867 19.08 ;
     RECT  56.704 51.168 56.873 51.192 ;
     RECT  56.704 2.832 56.981 13.368 ;
     RECT  56.704 47.184 57.053 47.928 ;
     RECT  56.704 68.16 57.161 68.28 ;
     RECT  56.704 35.28 57.197 38.568 ;
     RECT  56.704 40.848 57.197 42.024 ;
     RECT  57.197 42 57.521 42.024 ;
     RECT  56.704 64.32 57.557 64.344 ;
     RECT  57.161 68.256 57.629 68.28 ;
     RECT  56.704 21.936 57.665 22.488 ;
     RECT  56.704 58.656 57.733 58.68 ;
     RECT  56.704 25.056 57.805 25.08 ;
     RECT  57.805 25.008 57.877 25.08 ;
     RECT  57.697 64.752 57.989 64.776 ;
     RECT  57.733 57.984 58.012 58.68 ;
     RECT  56.981 2.832 58.021 12.888 ;
     RECT  56.704 45.168 58.028 45.192 ;
     RECT  56.704 28.032 58.057 28.44 ;
     RECT  56.704 39.744 58.069 39.768 ;
     RECT  57.197 40.848 58.069 40.872 ;
     RECT  56.704 49.776 58.093 50.136 ;
     RECT  58.069 39.744 58.115 40.872 ;
     RECT  57.197 36.768 58.129 38.568 ;
     RECT  58.115 39.744 58.129 40.728 ;
     RECT  58.028 44.976 58.133 45.192 ;
     RECT  58.057 27.888 58.165 28.44 ;
     RECT  58.093 49.776 58.165 50.808 ;
     RECT  58.129 36.768 58.169 40.728 ;
     RECT  56.704 56.4 58.169 56.52 ;
     RECT  57.665 22.08 58.201 22.488 ;
     RECT  57.841 55.152 58.277 55.176 ;
     RECT  58.201 22.08 58.345 22.92 ;
     RECT  58.069 43.488 58.345 43.512 ;
     RECT  58.012 58.128 58.373 58.68 ;
     RECT  57.197 35.28 58.381 35.688 ;
     RECT  58.169 36.768 58.381 39.384 ;
     RECT  58.165 49.776 58.421 50.856 ;
     RECT  57.053 47.184 58.451 47.832 ;
     RECT  58.021 2.832 58.457 13.128 ;
     RECT  58.373 58.128 58.457 58.728 ;
     RECT  58.165 26.928 58.601 28.44 ;
     RECT  58.601 27.408 58.633 28.44 ;
     RECT  56.704 53.424 58.633 53.448 ;
     RECT  58.169 56.4 58.633 56.472 ;
     RECT  58.421 49.776 58.693 50.808 ;
     RECT  58.669 60.672 58.693 60.696 ;
     RECT  56.867 14.736 58.705 16.68 ;
     RECT  58.451 47.184 58.705 47.688 ;
     RECT  58.705 47.088 58.739 47.688 ;
     RECT  58.345 22.08 58.745 23.016 ;
     RECT  58.739 47.088 58.745 47.208 ;
     RECT  58.693 48.96 58.817 50.808 ;
     RECT  57.877 24.48 58.849 25.08 ;
     RECT  58.405 45.936 58.849 45.96 ;
     RECT  58.745 47.088 58.849 47.112 ;
     RECT  58.849 24.48 58.853 25.128 ;
     RECT  58.633 52.656 58.885 53.448 ;
     RECT  58.745 22.08 58.889 22.776 ;
     RECT  58.777 32.16 58.957 32.184 ;
     RECT  58.633 27.408 58.961 28.584 ;
     RECT  58.693 59.904 58.961 60.696 ;
     RECT  58.885 52.656 58.969 53.592 ;
     RECT  58.525 64.32 59.029 64.344 ;
     RECT  58.993 65.664 59.029 65.688 ;
     RECT  58.969 52.656 59.069 52.68 ;
     RECT  58.345 43.344 59.101 43.512 ;
     RECT  58.381 44.64 59.101 44.664 ;
     RECT  58.633 55.872 59.141 56.472 ;
     RECT  58.705 68.16 59.177 68.184 ;
     RECT  58.961 59.904 59.18 59.928 ;
     RECT  56.704 62.16 59.219 62.28 ;
     RECT  58.961 28.464 59.245 28.584 ;
     RECT  59.18 59.184 59.267 59.928 ;
     RECT  58.705 14.688 59.281 16.68 ;
     RECT  59.245 28.464 59.285 28.68 ;
     RECT  59.029 64.32 59.317 65.688 ;
     RECT  58.813 66.912 59.317 66.936 ;
     RECT  59.285 28.56 59.353 28.68 ;
     RECT  59.353 28.56 59.357 29.592 ;
     RECT  56.867 18.432 59.381 19.08 ;
     RECT  59.101 43.344 59.393 44.664 ;
     RECT  58.957 32.16 59.461 32.472 ;
     RECT  59.425 34.224 59.461 34.248 ;
     RECT  59.381 18.432 59.465 19.368 ;
     RECT  58.381 35.28 59.465 39.384 ;
     RECT  59.317 64.32 59.465 66.936 ;
     RECT  59.425 26.208 59.569 26.232 ;
     RECT  59.465 18.432 59.573 19.08 ;
     RECT  58.169 40.704 59.605 40.728 ;
     RECT  58.525 42.192 59.641 42.216 ;
     RECT  58.853 25.104 59.681 25.128 ;
     RECT  58.889 22.08 59.749 22.488 ;
     RECT  59.465 64.8 59.825 66.936 ;
     RECT  59.281 13.968 59.845 16.68 ;
     RECT  59.804 17.808 59.845 17.832 ;
     RECT  58.457 58.128 59.857 58.152 ;
     RECT  59.845 13.968 59.891 17.832 ;
     RECT  59.749 21.648 59.897 22.488 ;
     RECT  59.461 31.632 59.897 32.472 ;
     RECT  58.817 48.96 59.897 50.712 ;
     RECT  59.173 52.416 59.897 52.44 ;
     RECT  59.857 57.648 59.897 58.152 ;
     RECT  59.357 29.568 59.933 29.592 ;
     RECT  59.465 35.76 60.041 39.384 ;
     RECT  59.267 59.808 60.041 59.928 ;
     RECT  58.849 45.936 60.073 47.112 ;
     RECT  60.041 38.544 60.085 39.384 ;
     RECT  59.605 40.416 60.085 40.728 ;
     RECT  60.073 45.936 60.113 47.88 ;
     RECT  60.085 38.544 60.131 40.728 ;
     RECT  59.891 13.968 60.149 17.112 ;
     RECT  60.149 14.208 60.185 17.112 ;
     RECT  60.041 35.76 60.221 37.368 ;
     RECT  59.897 48.96 60.293 49.8 ;
     RECT  59.219 62.256 60.361 62.28 ;
     RECT  60.185 14.208 60.412 16.68 ;
     RECT  60.221 35.76 60.469 35.784 ;
     RECT  59.461 33.888 60.473 34.248 ;
     RECT  60.361 62.256 60.505 62.76 ;
     RECT  59.357 28.56 60.577 28.584 ;
     RECT  59.641 42.096 60.577 42.216 ;
     RECT  59.897 31.632 60.581 31.656 ;
     RECT  60.113 47.088 60.581 47.88 ;
     RECT  58.961 27.408 60.649 27.432 ;
     RECT  59.393 43.68 60.653 44.664 ;
     RECT  59.569 26.208 60.661 26.28 ;
     RECT  60.577 28.416 60.685 28.584 ;
     RECT  60.649 27.36 60.733 27.432 ;
     RECT  60.577 42.096 60.761 42.696 ;
     RECT  59.825 64.8 60.761 66.744 ;
     RECT  59.141 56.448 60.973 56.472 ;
     RECT  60.761 42.096 61.009 42.12 ;
     RECT  60.505 62.16 61.081 62.76 ;
     RECT  60.041 59.808 61.189 59.832 ;
     RECT  58.457 2.832 61.261 12.84 ;
     RECT  60.131 38.544 61.261 40.44 ;
     RECT  60.761 64.8 61.261 65.976 ;
     RECT  61.045 1.728 61.333 1.752 ;
     RECT  61.261 2.784 61.333 12.84 ;
     RECT  61.081 62.16 61.34 63 ;
     RECT  60.113 45.936 61.369 45.96 ;
     RECT  60.581 47.088 61.369 47.112 ;
     RECT  60.973 0.576 61.405 0.6 ;
     RECT  61.333 1.728 61.405 12.84 ;
     RECT  61.405 0.576 61.427 12.84 ;
     RECT  60.221 36.768 61.477 37.368 ;
     RECT  61.261 38.544 61.477 40.872 ;
     RECT  60.973 56.064 61.477 56.472 ;
     RECT  59.897 57.648 61.477 57.768 ;
     RECT  60.733 27.408 61.487 27.432 ;
     RECT  60.685 28.416 61.487 28.68 ;
     RECT  60.661 25.536 61.525 26.28 ;
     RECT  60.469 35.328 61.549 35.784 ;
     RECT  61.477 36.768 61.549 40.872 ;
     RECT  61.189 59.52 61.549 59.832 ;
     RECT  61.34 62.16 61.573 63.528 ;
     RECT  61.549 60.816 61.583 60.84 ;
     RECT  61.573 62.064 61.583 63.528 ;
     RECT  61.369 45.936 61.585 47.112 ;
     RECT  60.901 30.96 61.649 30.984 ;
     RECT  61.427 1.152 61.669 12.84 ;
     RECT  60.412 14.688 61.765 16.68 ;
     RECT  61.487 27.408 61.765 28.68 ;
     RECT  61.549 35.328 61.801 40.872 ;
     RECT  61.669 1.152 61.808 13.704 ;
     RECT  61.765 14.688 61.808 17.16 ;
     RECT  59.573 18.816 61.808 19.08 ;
     RECT  59.897 22.128 61.808 22.488 ;
     RECT  61.525 25.296 61.808 26.28 ;
     RECT  61.765 27.36 61.808 28.68 ;
     RECT  61.649 30.72 61.808 30.984 ;
     RECT  60.473 33.888 61.808 33.912 ;
     RECT  61.801 34.896 61.808 40.872 ;
     RECT  61.009 41.904 61.808 42.12 ;
     RECT  60.653 43.68 61.808 43.704 ;
     RECT  61.585 45.936 61.808 47.88 ;
     RECT  60.293 48.96 61.808 48.984 ;
     RECT  61.693 51.12 61.808 51.144 ;
     RECT  61.477 56.064 61.808 57.768 ;
     RECT  61.549 59.184 61.808 59.832 ;
     RECT  61.583 60.816 61.808 63.528 ;
     RECT  61.261 64.56 61.808 65.976 ;
     RECT  61.808 1.152 61.912 69.132 ;
     RECT  61.477 0.096 62.003 0.12 ;
     RECT  61.912 1.152 62.099 68.862 ;
     RECT  62.099 1.68 62.104 68.862 ;
     RECT  62.104 14.688 62.129 19.08 ;
     RECT  62.104 30.192 62.129 30.984 ;
     RECT  62.104 56.064 62.129 66.744 ;
     RECT  62.104 40.512 62.345 41.928 ;
     RECT  62.104 51.984 62.381 52.008 ;
     RECT  62.104 68.688 62.453 68.712 ;
     RECT  62.104 47.088 62.489 47.88 ;
     RECT  62.104 43.344 62.561 43.944 ;
     RECT  62.129 63.792 62.561 66.744 ;
     RECT  62.104 48.96 62.597 49.272 ;
     RECT  62.561 63.792 62.669 65.016 ;
     RECT  62.104 1.68 62.705 13.08 ;
     RECT  62.129 18 62.705 19.08 ;
     RECT  62.104 53.952 62.723 54.792 ;
     RECT  62.104 33.456 62.741 36.024 ;
     RECT  62.741 33.6 62.764 35.784 ;
     RECT  62.345 40.512 62.849 41.256 ;
     RECT  62.104 50.736 62.857 50.76 ;
     RECT  62.104 27.36 62.885 27.384 ;
     RECT  62.104 21.648 62.921 24.312 ;
     RECT  62.129 30.192 62.921 30.216 ;
     RECT  62.104 37.344 62.921 38.568 ;
     RECT  62.764 34.896 62.993 35.784 ;
     RECT  62.705 1.68 63.004 12.84 ;
     RECT  62.561 43.344 63.065 43.368 ;
     RECT  62.921 22.224 63.107 24.312 ;
     RECT  62.129 56.064 63.205 62.76 ;
     RECT  62.669 63.792 63.205 64.968 ;
     RECT  62.489 47.088 63.245 47.736 ;
     RECT  62.723 54.048 63.245 54.792 ;
     RECT  62.104 20.448 63.353 20.472 ;
     RECT  63.245 47.088 63.389 47.112 ;
     RECT  62.849 40.848 63.425 41.256 ;
     RECT  62.705 18 63.461 18.024 ;
     RECT  63.277 67.776 63.493 67.944 ;
     RECT  63.107 22.752 63.497 24.312 ;
     RECT  63.205 56.064 63.529 64.968 ;
     RECT  62.561 66.672 63.601 66.744 ;
     RECT  63.493 67.776 63.601 68.376 ;
     RECT  63.529 55.152 63.605 64.968 ;
     RECT  63.596 32.16 63.637 32.184 ;
     RECT  63.637 31.296 63.683 32.184 ;
     RECT  63.245 54.048 63.731 54.072 ;
     RECT  63.605 58.128 63.781 64.968 ;
     RECT  62.764 33.6 63.817 33.816 ;
     RECT  63.709 42.72 63.821 42.744 ;
     RECT  63.004 1.728 63.827 12.84 ;
     RECT  62.129 14.688 63.853 16.68 ;
     RECT  63.497 22.752 63.893 23.448 ;
     RECT  63.853 13.824 63.925 16.776 ;
     RECT  63.601 66.672 63.925 68.376 ;
     RECT  63.683 31.296 63.929 31.32 ;
     RECT  63.425 40.848 64.001 40.872 ;
     RECT  63.781 58.128 64.021 65.64 ;
     RECT  63.925 66.672 64.021 68.904 ;
     RECT  63.925 13.824 64.069 16.824 ;
     RECT  62.993 35.328 64.069 35.784 ;
     RECT  63.709 36.768 64.069 36.792 ;
     RECT  62.921 38.208 64.069 38.568 ;
     RECT  62.104 45.936 64.069 45.96 ;
     RECT  63.205 39.792 64.073 39.816 ;
     RECT  64.021 58.128 64.145 68.904 ;
     RECT  63.817 33.6 64.217 34.104 ;
     RECT  63.605 55.152 64.217 57 ;
     RECT  63.277 52.992 64.249 53.016 ;
     RECT  62.104 25.536 64.285 25.56 ;
     RECT  64.249 51.888 64.393 51.912 ;
     RECT  63.827 1.728 64.397 1.848 ;
     RECT  64.397 1.824 64.405 1.848 ;
     RECT  64.145 61.008 64.469 68.904 ;
     RECT  64.069 44.976 64.597 45.96 ;
     RECT  64.469 63.744 64.649 68.904 ;
     RECT  64.597 44.352 64.684 45.96 ;
     RECT  64.069 35.328 64.789 38.568 ;
     RECT  64.789 35.28 64.793 38.568 ;
     RECT  64.793 35.28 64.835 35.928 ;
     RECT  62.597 48.96 64.861 48.984 ;
     RECT  64.249 52.896 64.861 53.016 ;
     RECT  64.717 54.048 64.861 54.072 ;
     RECT  64.393 30.048 64.865 30.072 ;
     RECT  64.684 44.976 64.865 45.96 ;
     RECT  64.217 55.824 64.865 56.52 ;
     RECT  64.393 51.744 64.897 51.912 ;
     RECT  64.861 52.896 64.897 54.072 ;
     RECT  64.861 48.96 64.901 49.464 ;
     RECT  64.897 51.744 64.901 54.072 ;
     RECT  64.145 58.128 64.933 59.784 ;
     RECT  64.217 33.792 64.937 34.104 ;
     RECT  64.901 53.52 64.969 54.072 ;
     RECT  62.705 19.056 65.041 19.08 ;
     RECT  64.933 57.984 65.041 59.784 ;
     RECT  64.649 68.88 65.045 68.904 ;
     RECT  64.469 61.008 65.081 62.76 ;
     RECT  64.969 53.52 65.113 54.12 ;
     RECT  64.069 13.824 65.116 17.4 ;
     RECT  64.649 63.744 65.117 67.896 ;
     RECT  64.865 45.552 65.153 45.96 ;
     RECT  65.041 57.6 65.221 59.784 ;
     RECT  64.865 55.968 65.257 56.52 ;
     RECT  65.221 57.6 65.257 60.024 ;
     RECT  64.835 35.28 65.267 35.784 ;
     RECT  65.116 13.824 65.297 16.824 ;
     RECT  65.041 18.768 65.297 19.08 ;
     RECT  64.681 22.224 65.297 22.248 ;
     RECT  65.153 45.936 65.329 45.96 ;
     RECT  65.329 45.936 65.369 46.056 ;
     RECT  64.285 24.624 65.42 25.56 ;
     RECT  65.221 26.736 65.42 26.76 ;
     RECT  65.257 55.968 65.441 60.024 ;
     RECT  64.793 37.584 65.473 38.568 ;
     RECT  64.901 49.44 65.513 49.464 ;
     RECT  65.461 28.416 65.549 28.44 ;
     RECT  64.573 40.8 65.549 40.824 ;
     RECT  65.081 62.16 65.549 62.76 ;
     RECT  65.441 55.968 65.585 58.008 ;
     RECT  65.117 64.176 65.621 67.896 ;
     RECT  65.297 14.208 65.651 16.824 ;
     RECT  65.473 37.584 65.657 39.768 ;
     RECT  65.113 53.52 65.689 54.648 ;
     RECT  65.651 14.208 65.693 15.336 ;
     RECT  65.441 59.424 65.729 60.024 ;
     RECT  65.621 64.176 65.729 65.784 ;
     RECT  65.729 59.76 65.765 60.024 ;
     RECT  65.729 64.176 65.765 65.688 ;
     RECT  63.827 2.832 65.797 12.84 ;
     RECT  65.657 37.584 65.869 38.568 ;
     RECT  65.797 2.688 65.905 12.84 ;
     RECT  65.549 62.4 65.941 62.76 ;
     RECT  65.621 66.768 65.941 67.896 ;
     RECT  65.297 19.056 65.945 19.08 ;
     RECT  65.905 2.304 66.049 12.84 ;
     RECT  65.585 56.4 66.053 58.008 ;
     RECT  65.941 66.768 66.085 68.376 ;
     RECT  64.937 33.792 66.089 33.816 ;
     RECT  65.081 61.008 66.121 61.032 ;
     RECT  66.085 66.768 66.161 69.24 ;
     RECT  65.651 16.56 66.236 16.824 ;
     RECT  66.236 16.56 66.265 17.112 ;
     RECT  65.941 62.4 66.301 63.192 ;
     RECT  65.765 64.176 66.301 65.16 ;
     RECT  65.693 14.208 66.325 15.096 ;
     RECT  66.265 16.56 66.373 17.448 ;
     RECT  66.277 18.432 66.373 18.456 ;
     RECT  66.085 43.104 66.373 43.128 ;
     RECT  64.901 51.744 66.373 52.44 ;
     RECT  65.689 53.52 66.373 54.696 ;
     RECT  65.42 24.624 66.401 26.76 ;
     RECT  63.893 23.424 66.421 23.448 ;
     RECT  66.401 24.528 66.421 26.76 ;
     RECT  65.657 39.744 66.553 39.768 ;
     RECT  65.369 46.032 66.589 46.056 ;
     RECT  66.301 62.4 66.589 65.16 ;
     RECT  66.421 23.328 66.613 26.76 ;
     RECT  66.121 27.984 66.613 28.008 ;
     RECT  66.053 56.88 66.661 58.008 ;
     RECT  66.121 60.672 66.661 61.032 ;
     RECT  66.589 62.016 66.661 65.16 ;
     RECT  65.581 50.592 66.697 50.616 ;
     RECT  66.373 51.744 66.697 54.696 ;
     RECT  65.869 70.704 66.697 70.728 ;
     RECT  66.161 68.352 66.701 69.24 ;
     RECT  66.697 50.592 66.733 54.696 ;
     RECT  66.733 50.592 66.805 54.936 ;
     RECT  66.661 56.88 66.805 58.632 ;
     RECT  66.373 43.104 66.841 43.32 ;
     RECT  66.661 60.672 66.841 65.16 ;
     RECT  66.697 70.704 66.841 70.776 ;
     RECT  65.869 37.296 66.913 38.568 ;
     RECT  66.841 60.672 66.985 65.256 ;
     RECT  66.161 66.768 66.985 66.792 ;
     RECT  66.613 23.328 67.093 28.008 ;
     RECT  67.129 30.672 67.165 30.696 ;
     RECT  66.193 31.92 67.165 31.944 ;
     RECT  66.701 68.352 67.165 69.288 ;
     RECT  66.841 70.656 67.165 70.776 ;
     RECT  66.049 2.208 67.208 12.84 ;
     RECT  66.325 13.968 67.208 15.096 ;
     RECT  66.373 16.56 67.208 18.456 ;
     RECT  65.797 20.496 67.208 20.52 ;
     RECT  67.093 22.752 67.208 28.008 ;
     RECT  67.165 30.672 67.208 31.944 ;
     RECT  65.761 35.232 67.208 35.256 ;
     RECT  66.913 37.104 67.208 38.568 ;
     RECT  66.553 39.744 67.208 39.864 ;
     RECT  65.113 42 67.208 42.024 ;
     RECT  66.841 43.104 67.208 43.368 ;
     RECT  66.805 44.448 67.208 44.472 ;
     RECT  66.589 45.552 67.208 46.056 ;
     RECT  66.445 47.856 67.208 47.88 ;
     RECT  66.805 50.592 67.208 55.272 ;
     RECT  66.805 56.88 67.208 59.496 ;
     RECT  66.985 60.672 67.208 66.792 ;
     RECT  67.165 68.352 67.208 70.776 ;
     RECT  67.208 2.148 67.345 70.776 ;
     RECT  67.345 2.064 67.504 70.776 ;
     RECT  67.504 30.672 67.619 31.224 ;
     RECT  67.504 50.592 67.673 55.848 ;
     RECT  67.504 2.064 67.681 27.96 ;
     RECT  67.504 56.88 67.709 70.776 ;
     RECT  67.709 56.976 67.781 70.776 ;
     RECT  67.681 2.064 67.813 22.776 ;
     RECT  67.813 1.728 67.817 22.776 ;
     RECT  67.673 50.688 67.925 55.848 ;
     RECT  67.504 35.232 68.069 35.928 ;
     RECT  67.993 0.528 68.147 0.552 ;
     RECT  67.781 57.024 68.147 70.776 ;
     RECT  68.147 57.024 68.236 68.04 ;
     RECT  67.817 1.728 68.356 5.88 ;
     RECT  68.236 60.528 68.357 68.04 ;
     RECT  67.681 23.904 68.465 27.96 ;
     RECT  67.504 32.352 68.465 33.096 ;
     RECT  67.504 43.248 68.472 43.368 ;
     RECT  68.465 32.688 68.483 33.096 ;
     RECT  68.356 1.68 68.531 5.88 ;
     RECT  67.504 44.448 68.533 44.472 ;
     RECT  67.504 45.552 68.533 45.96 ;
     RECT  68.357 60.672 68.537 68.04 ;
     RECT  68.537 60.672 68.627 67.848 ;
     RECT  67.504 41.616 68.629 41.64 ;
     RECT  67.504 39.84 68.645 39.864 ;
     RECT  68.533 44.448 68.645 45.96 ;
     RECT  67.619 31.104 68.713 31.224 ;
     RECT  68.627 60.672 68.717 67.416 ;
     RECT  67.817 6.864 68.725 22.776 ;
     RECT  67.925 51.84 68.785 55.848 ;
     RECT  68.236 57.024 68.785 59.496 ;
     RECT  67.504 47.184 68.821 47.208 ;
     RECT  68.465 23.904 68.893 27.24 ;
     RECT  68.069 35.232 68.929 35.256 ;
     RECT  68.713 31.104 68.965 31.704 ;
     RECT  68.645 44.928 68.965 45.96 ;
     RECT  68.677 29.664 68.969 29.688 ;
     RECT  68.821 47.184 68.969 47.784 ;
     RECT  68.717 65.472 68.969 67.416 ;
     RECT  68.965 44.928 69.001 46.056 ;
     RECT  68.969 47.184 69.001 47.592 ;
     RECT  68.965 0.576 69.037 0.6 ;
     RECT  69.037 0.576 69.049 0.648 ;
     RECT  68.629 41.376 69.073 41.64 ;
     RECT  68.531 1.728 69.109 5.88 ;
     RECT  68.725 6.864 69.109 22.824 ;
     RECT  68.147 69.12 69.109 70.776 ;
     RECT  69.049 0.624 69.121 0.648 ;
     RECT  68.785 51.84 69.155 59.496 ;
     RECT  69.109 69.024 69.157 70.776 ;
     RECT  68.605 28.368 69.181 28.632 ;
     RECT  67.504 37.104 69.181 38.568 ;
     RECT  69.061 34.08 69.217 34.104 ;
     RECT  68.929 35.136 69.217 35.256 ;
     RECT  69.155 51.84 69.221 55.944 ;
     RECT  68.717 60.672 69.221 64.344 ;
     RECT  69.073 41.04 69.253 41.64 ;
     RECT  68.472 42.72 69.253 43.368 ;
     RECT  69.157 69.024 69.253 71.16 ;
     RECT  69.253 41.04 69.257 43.368 ;
     RECT  69.001 44.928 69.257 47.592 ;
     RECT  69.253 68.976 69.257 71.16 ;
     RECT  67.925 50.688 69.325 50.712 ;
     RECT  69.221 55.632 69.329 55.944 ;
     RECT  69.181 36.672 69.401 38.568 ;
     RECT  69.401 37.68 69.437 38.568 ;
     RECT  69.257 44.928 69.437 45.048 ;
     RECT  69.109 1.728 69.445 22.824 ;
     RECT  69.257 68.976 69.491 70.776 ;
     RECT  69.445 1.728 69.505 22.872 ;
     RECT  69.257 41.376 69.509 43.368 ;
     RECT  68.893 23.856 69.541 27.24 ;
     RECT  69.437 38.544 69.541 38.568 ;
     RECT  69.221 51.84 69.545 54.6 ;
     RECT  69.505 1.152 69.581 22.872 ;
     RECT  69.217 34.08 69.613 35.256 ;
     RECT  69.401 36.672 69.613 36.696 ;
     RECT  69.155 57.024 69.613 59.496 ;
     RECT  69.221 60.672 69.613 64.248 ;
     RECT  69.613 34.08 69.617 36.696 ;
     RECT  69.181 28.368 69.761 29.112 ;
     RECT  69.491 68.976 69.779 70.728 ;
     RECT  69.581 1.152 69.827 22.824 ;
     RECT  69.761 28.368 69.833 28.632 ;
     RECT  69.257 46.032 69.833 47.592 ;
     RECT  69.827 1.152 69.875 22.728 ;
     RECT  69.325 50.016 69.901 50.712 ;
     RECT  69.545 51.84 69.901 52.2 ;
     RECT  69.541 23.856 69.905 27.336 ;
     RECT  68.483 32.688 69.932 33.048 ;
     RECT  69.617 34.08 69.932 35.736 ;
     RECT  68.965 30.672 69.937 31.704 ;
     RECT  69.937 30 69.965 31.704 ;
     RECT  69.932 32.688 69.965 35.736 ;
     RECT  69.905 26.928 69.973 27.336 ;
     RECT  69.833 28.464 69.977 28.632 ;
     RECT  69.779 68.976 70.013 70.152 ;
     RECT  69.901 50.016 70.021 52.2 ;
     RECT  69.905 23.856 70.057 25.512 ;
     RECT  68.969 65.856 70.076 67.416 ;
     RECT  70.076 65.808 70.117 67.416 ;
     RECT  69.973 26.928 70.157 27.384 ;
     RECT  69.329 55.776 70.213 55.944 ;
     RECT  69.613 57.024 70.213 64.248 ;
     RECT  69.977 28.464 70.265 28.488 ;
     RECT  70.057 23.856 70.297 24.12 ;
     RECT  70.213 55.776 70.3 64.248 ;
     RECT  70.117 65.52 70.309 67.416 ;
     RECT  70.3 55.776 70.412 55.944 ;
     RECT  70.013 68.976 70.441 70.104 ;
     RECT  70.412 55.68 70.499 55.944 ;
     RECT  70.021 49.92 70.517 52.2 ;
     RECT  70.309 65.376 70.549 67.416 ;
     RECT  70.517 49.92 70.553 51.864 ;
     RECT  69.965 30 70.589 35.736 ;
     RECT  70.3 56.976 70.633 64.248 ;
     RECT  69.437 44.928 70.645 44.952 ;
     RECT  69.833 46.032 70.645 46.056 ;
     RECT  69.509 41.376 70.697 43.128 ;
     RECT  70.589 30 70.739 33.432 ;
     RECT  69.545 53.232 70.765 54.6 ;
     RECT  70.693 0.576 70.777 0.6 ;
     RECT  69.833 47.568 70.873 47.592 ;
     RECT  70.873 47.328 70.913 47.592 ;
     RECT  70.633 57.024 70.945 64.248 ;
     RECT  70.549 65.328 70.945 67.416 ;
     RECT  70.297 23.808 70.949 24.12 ;
     RECT  70.553 50.592 71.021 51.864 ;
     RECT  70.645 44.592 71.053 46.056 ;
     RECT  70.885 71.136 71.093 71.16 ;
     RECT  69.875 1.728 71.125 22.728 ;
     RECT  70.945 57.024 71.173 67.416 ;
     RECT  70.441 68.4 71.173 70.104 ;
     RECT  71.173 57.024 71.201 70.104 ;
     RECT  69.541 38.544 71.237 39.48 ;
     RECT  71.201 69.408 71.237 70.104 ;
     RECT  71.053 44.592 71.273 46.248 ;
     RECT  70.765 52.992 71.305 54.6 ;
     RECT  70.499 55.68 71.305 55.704 ;
     RECT  71.125 1.728 71.345 23.544 ;
     RECT  71.345 23.52 71.381 23.544 ;
     RECT  70.739 30 71.413 31.128 ;
     RECT  70.697 41.376 71.413 41.4 ;
     RECT  70.157 26.928 71.449 26.952 ;
     RECT  70.697 43.104 71.449 43.128 ;
     RECT  71.273 44.592 71.449 44.952 ;
     RECT  71.413 28.464 71.497 28.488 ;
     RECT  71.273 46.032 71.557 46.248 ;
     RECT  70.913 47.328 71.557 47.352 ;
     RECT  71.305 52.992 71.561 55.704 ;
     RECT  70.589 35.136 71.701 35.736 ;
     RECT  70.057 25.344 71.809 25.512 ;
     RECT  70.739 32.448 71.809 33.432 ;
     RECT  71.701 34.656 71.809 35.736 ;
     RECT  71.053 0.528 71.845 0.552 ;
     RECT  71.809 24.72 71.881 25.512 ;
     RECT  71.449 43.104 71.881 44.952 ;
     RECT  70.549 48.672 71.953 48.696 ;
     RECT  71.413 29.664 71.989 31.128 ;
     RECT  71.021 50.592 72.061 50.76 ;
     RECT  71.521 51.888 72.061 51.912 ;
     RECT  71.561 52.992 72.061 53.256 ;
     RECT  71.557 46.032 72.097 47.352 ;
     RECT  71.845 0.528 72.133 0.648 ;
     RECT  71.345 1.728 72.133 22.248 ;
     RECT  71.449 26.928 72.133 27.384 ;
     RECT  71.201 57.024 72.181 68.424 ;
     RECT  71.237 69.408 72.181 69.576 ;
     RECT  71.237 38.784 72.341 39.48 ;
     RECT  71.989 28.944 72.349 31.128 ;
     RECT  72.133 0.528 72.373 22.248 ;
     RECT  72.373 0.192 72.421 22.248 ;
     RECT  71.953 48.672 72.449 49.608 ;
     RECT  72.061 50.592 72.449 53.256 ;
     RECT  72.181 57.024 72.469 69.576 ;
     RECT  72.097 46.032 72.601 47.592 ;
     RECT  72.449 48.672 72.601 53.256 ;
     RECT  72.421 0.096 72.608 22.248 ;
     RECT  72.325 23.376 72.608 23.4 ;
     RECT  71.881 24.72 72.608 25.56 ;
     RECT  72.133 26.688 72.608 27.384 ;
     RECT  72.349 28.944 72.608 31.176 ;
     RECT  71.809 32.448 72.608 35.736 ;
     RECT  72.097 37.68 72.608 37.704 ;
     RECT  72.341 38.784 72.608 39.912 ;
     RECT  71.413 40.896 72.608 41.4 ;
     RECT  71.881 42.48 72.608 44.952 ;
     RECT  72.601 46.032 72.608 53.256 ;
     RECT  71.561 54.48 72.608 55.704 ;
     RECT  72.469 56.784 72.608 69.576 ;
     RECT  72.529 70.656 72.613 70.68 ;
     RECT  72.608 0.096 72.904 69.576 ;
     RECT  72.904 28.944 72.965 40.104 ;
     RECT  72.904 52.992 72.965 69.576 ;
     RECT  72.965 56.448 73.093 69.576 ;
     RECT  72.613 70.656 73.093 71.112 ;
     RECT  72.904 4.128 73.145 27.48 ;
     RECT  72.904 0.096 73.187 2.856 ;
     RECT  73.145 4.128 73.235 24.168 ;
     RECT  72.965 28.944 73.289 32.376 ;
     RECT  73.235 4.128 73.325 11.352 ;
     RECT  73.325 4.128 73.361 10.296 ;
     RECT  72.904 41.376 73.361 46.872 ;
     RECT  72.965 52.992 73.397 55.464 ;
     RECT  73.361 43.584 73.505 46.872 ;
     RECT  73.361 4.128 73.541 10.2 ;
     RECT  73.145 25.248 73.541 27.48 ;
     RECT  73.505 43.584 73.613 44.232 ;
     RECT  73.093 56.448 73.685 71.112 ;
     RECT  72.904 48.432 73.721 51.912 ;
     RECT  73.685 56.784 73.811 71.112 ;
     RECT  73.289 28.944 73.829 31.992 ;
     RECT  73.829 28.944 73.897 31.896 ;
     RECT  73.811 68.976 73.901 71.112 ;
     RECT  73.613 43.632 73.937 44.232 ;
     RECT  73.541 25.488 73.964 27.48 ;
     RECT  73.897 28.464 73.964 31.896 ;
     RECT  73.964 25.488 73.973 31.896 ;
     RECT  73.811 56.784 74.017 67.848 ;
     RECT  73.973 25.488 74.045 31.8 ;
     RECT  73.397 52.992 74.045 55.32 ;
     RECT  72.965 33.6 74.101 40.104 ;
     RECT  73.361 41.376 74.101 42.168 ;
     RECT  73.721 49.248 74.149 51.912 ;
     RECT  74.045 52.992 74.149 55.224 ;
     RECT  73.901 71.088 74.149 71.112 ;
     RECT  73.937 43.728 74.195 44.232 ;
     RECT  73.187 0.096 74.233 0.6 ;
     RECT  73.325 11.328 74.252 11.352 ;
     RECT  73.235 12.48 74.252 24.168 ;
     RECT  74.045 25.488 74.261 31.704 ;
     RECT  74.233 0.096 74.297 0.552 ;
     RECT  74.261 25.488 74.297 31.512 ;
     RECT  73.541 4.128 74.329 7.464 ;
     RECT  73.505 45.6 74.329 46.872 ;
     RECT  74.195 44.208 74.369 44.232 ;
     RECT  74.101 33.6 74.389 42.168 ;
     RECT  74.389 33.504 74.483 42.168 ;
     RECT  74.329 3.984 74.533 7.464 ;
     RECT  74.149 71.088 74.549 71.16 ;
     RECT  74.533 3.84 74.581 7.464 ;
     RECT  73.541 8.448 74.581 10.2 ;
     RECT  74.483 36.48 74.581 42.168 ;
     RECT  74.483 33.504 74.629 35.4 ;
     RECT  74.549 71.088 74.657 71.112 ;
     RECT  74.581 36.48 74.659 42.744 ;
     RECT  74.252 11.328 74.684 24.168 ;
     RECT  74.581 3.84 74.689 10.2 ;
     RECT  74.684 11.328 74.689 24.504 ;
     RECT  74.689 3.84 74.693 24.504 ;
     RECT  74.017 56.784 74.723 67.704 ;
     RECT  73.187 1.728 74.729 2.856 ;
     RECT  74.693 24.48 74.771 24.504 ;
     RECT  74.297 25.488 74.833 28.488 ;
     RECT  74.149 49.248 74.833 55.224 ;
     RECT  74.693 3.84 74.837 23.4 ;
     RECT  74.629 33.456 74.873 35.4 ;
     RECT  74.837 3.84 74.905 22.248 ;
     RECT  74.797 44.304 74.905 44.328 ;
     RECT  74.329 45.6 74.905 47.592 ;
     RECT  74.833 48.96 74.909 55.224 ;
     RECT  74.833 24.528 74.915 28.488 ;
     RECT  74.915 24.528 74.963 28.248 ;
     RECT  74.909 48.96 74.981 52.392 ;
     RECT  74.723 57.024 75.013 67.704 ;
     RECT  73.901 68.976 75.013 69.576 ;
     RECT  74.963 26.688 75.017 28.248 ;
     RECT  74.873 33.456 75.053 35.352 ;
     RECT  74.905 44.304 75.125 47.592 ;
     RECT  74.659 36.528 75.161 42.744 ;
     RECT  75.161 42.384 75.193 42.744 ;
     RECT  74.905 3.312 75.233 22.248 ;
     RECT  75.164 70.704 75.251 70.728 ;
     RECT  74.981 48.96 75.269 52.344 ;
     RECT  74.909 53.52 75.269 54.888 ;
     RECT  75.053 33.504 75.305 35.352 ;
     RECT  75.269 53.52 75.341 54.744 ;
     RECT  75.125 45.744 75.413 47.592 ;
     RECT  75.233 3.312 75.443 20.52 ;
     RECT  74.297 29.616 75.445 31.512 ;
     RECT  75.193 42.384 75.445 43.176 ;
     RECT  75.161 36.528 75.491 41.4 ;
     RECT  74.297 0.528 75.493 0.552 ;
     RECT  75.445 42.384 75.517 43.272 ;
     RECT  75.125 44.304 75.517 44.472 ;
     RECT  75.443 3.312 75.521 9 ;
     RECT  75.491 36.528 75.521 41.016 ;
     RECT  75.305 33.552 75.58 35.352 ;
     RECT  75.445 29.616 75.589 31.944 ;
     RECT  75.013 57.024 75.589 69.576 ;
     RECT  75.445 70.656 75.589 70.68 ;
     RECT  75.521 38.496 75.593 41.016 ;
     RECT  75.521 36.528 75.601 37.08 ;
     RECT  75.589 29.616 75.617 32.184 ;
     RECT  75.413 46.656 75.629 47.592 ;
     RECT  75.521 4.224 75.665 9 ;
     RECT  75.443 10.176 75.665 20.328 ;
     RECT  75.629 46.8 75.665 47.592 ;
     RECT  75.617 29.616 75.701 32.472 ;
     RECT  74.729 1.728 75.827 2.28 ;
     RECT  75.601 36.528 75.827 37.032 ;
     RECT  75.493 0.096 75.877 0.552 ;
     RECT  75.827 36.528 75.881 36.792 ;
     RECT  75.269 48.96 75.917 51.912 ;
     RECT  75.589 57.024 75.923 70.68 ;
     RECT  74.963 24.528 75.949 25.704 ;
     RECT  75.017 26.688 75.949 27.768 ;
     RECT  75.949 24.528 75.985 27.768 ;
     RECT  75.341 53.664 75.989 54.744 ;
     RECT  75.665 10.224 76.067 20.328 ;
     RECT  75.917 49.824 76.115 51.912 ;
     RECT  74.837 23.376 76.165 23.4 ;
     RECT  75.985 24.48 76.165 27.768 ;
     RECT  75.923 57.024 76.249 70.104 ;
     RECT  75.233 21.648 76.268 22.248 ;
     RECT  75.665 47.568 76.309 47.592 ;
     RECT  76.249 57.024 76.345 69.528 ;
     RECT  75.517 42.384 76.349 44.472 ;
     RECT  76.165 23.376 76.357 27.768 ;
     RECT  76.268 21.6 76.381 22.248 ;
     RECT  76.357 23.328 76.381 27.768 ;
     RECT  76.381 21.6 76.417 27.768 ;
     RECT  76.349 42.384 76.417 43.896 ;
     RECT  76.067 14.208 76.421 20.328 ;
     RECT  75.593 38.496 76.421 39.192 ;
     RECT  76.309 47.568 76.421 47.928 ;
     RECT  75.593 40.176 76.457 41.016 ;
     RECT  75.989 54.336 76.489 54.744 ;
     RECT  75.877 0.096 76.499 0.6 ;
     RECT  76.489 54.336 76.525 54.888 ;
     RECT  75.229 55.968 76.525 55.992 ;
     RECT  76.525 54.336 76.529 55.992 ;
     RECT  76.417 21.6 76.556 28.488 ;
     RECT  76.417 42 76.565 43.896 ;
     RECT  76.499 0.096 76.595 0.552 ;
     RECT  76.556 21.552 76.597 28.488 ;
     RECT  75.701 29.616 76.597 31.944 ;
     RECT  75.58 33.6 76.597 35.352 ;
     RECT  76.421 14.208 76.643 14.232 ;
     RECT  76.421 38.496 76.643 38.76 ;
     RECT  76.597 33.6 76.669 35.928 ;
     RECT  75.827 1.728 76.673 1.848 ;
     RECT  75.665 4.224 76.705 6.072 ;
     RECT  76.067 10.224 76.705 13.176 ;
     RECT  76.597 21.552 76.705 31.944 ;
     RECT  76.673 1.824 76.709 1.848 ;
     RECT  76.421 15.312 76.741 20.328 ;
     RECT  76.705 21.408 76.741 31.944 ;
     RECT  76.595 0.096 76.781 0.12 ;
     RECT  76.345 56.976 76.787 69.528 ;
     RECT  75.665 7.632 76.813 9 ;
     RECT  76.813 7.392 76.835 9 ;
     RECT  76.741 15.312 76.849 31.944 ;
     RECT  76.669 33.072 76.849 35.928 ;
     RECT  76.345 2.832 76.885 2.856 ;
     RECT  76.705 4.032 76.885 6.072 ;
     RECT  76.849 15.312 76.921 35.928 ;
     RECT  76.885 2.832 76.933 6.072 ;
     RECT  76.835 7.392 76.933 8.28 ;
     RECT  76.885 47.376 76.997 47.4 ;
     RECT  76.645 71.088 77.029 71.16 ;
     RECT  76.705 10.08 77.065 13.176 ;
     RECT  76.115 51.12 77.137 51.912 ;
     RECT  77.065 10.08 77.209 13.464 ;
     RECT  76.529 54.864 77.209 55.992 ;
     RECT  76.787 56.976 77.209 57.576 ;
     RECT  77.029 70.608 77.213 71.16 ;
     RECT  76.115 49.824 77.245 49.848 ;
     RECT  77.245 49.584 77.353 49.848 ;
     RECT  76.129 45.6 77.389 45.624 ;
     RECT  76.787 58.608 77.509 69.528 ;
     RECT  77.213 70.608 77.509 70.68 ;
     RECT  76.921 15.312 77.533 37.032 ;
     RECT  77.353 49.584 77.564 49.992 ;
     RECT  76.565 42.72 77.569 43.896 ;
     RECT  77.564 48.624 77.605 49.992 ;
     RECT  77.209 54.864 77.677 57.576 ;
     RECT  77.677 54.096 77.777 57.576 ;
     RECT  77.509 58.608 77.777 70.68 ;
     RECT  77.209 9.888 77.785 13.464 ;
     RECT  76.457 40.176 77.785 40.632 ;
     RECT  76.633 41.616 77.785 41.688 ;
     RECT  77.533 14.736 77.857 37.032 ;
     RECT  76.933 2.832 77.965 8.28 ;
     RECT  77.785 9.888 77.965 13.704 ;
     RECT  77.965 2.832 78.008 13.704 ;
     RECT  77.857 14.736 78.008 37.08 ;
     RECT  76.643 38.64 78.008 38.76 ;
     RECT  77.785 40.176 78.008 41.688 ;
     RECT  77.569 42.72 78.008 44.472 ;
     RECT  77.389 45.6 78.008 45.72 ;
     RECT  77.605 47.856 78.008 49.992 ;
     RECT  77.137 51.12 78.008 52.44 ;
     RECT  77.777 54.096 78.008 70.68 ;
     RECT  78.008 2.148 78.035 70.68 ;
     RECT  78.035 2.148 78.112 70.392 ;
     RECT  78.112 2.208 78.304 70.392 ;
     RECT  78.304 36.384 78.437 45.192 ;
     RECT  78.304 54.096 78.437 70.392 ;
     RECT  78.304 46.224 78.473 48.408 ;
     RECT  78.304 15.312 78.506 22.776 ;
     RECT  78.304 28.368 78.509 34.872 ;
     RECT  78.437 54.72 78.545 70.392 ;
     RECT  78.437 36.384 78.563 37.08 ;
     RECT  78.506 15.312 78.581 19.992 ;
     RECT  78.581 15.696 78.617 19.992 ;
     RECT  78.437 38.352 78.653 45.192 ;
     RECT  78.304 49.728 78.653 52.728 ;
     RECT  78.617 15.696 78.725 18.168 ;
     RECT  78.563 36.768 78.797 37.08 ;
     RECT  78.473 46.224 78.797 47.352 ;
     RECT  78.653 43.248 78.833 45.192 ;
     RECT  78.304 2.208 78.869 10.392 ;
     RECT  78.797 36.768 78.869 37.032 ;
     RECT  78.509 28.368 78.905 31.992 ;
     RECT  78.653 38.352 78.905 42.168 ;
     RECT  78.797 47.328 78.905 47.352 ;
     RECT  78.653 49.728 78.905 52.248 ;
     RECT  78.797 46.224 78.977 46.248 ;
     RECT  78.869 4.368 79.121 10.392 ;
     RECT  78.545 55.344 79.141 70.392 ;
     RECT  78.833 44.448 79.157 45.192 ;
     RECT  78.905 49.728 79.193 51.96 ;
     RECT  78.869 2.208 79.301 3.288 ;
     RECT  78.506 20.976 79.333 22.776 ;
     RECT  78.304 23.76 79.333 27.384 ;
     RECT  78.905 38.352 79.337 40.2 ;
     RECT  79.333 20.976 79.361 27.384 ;
     RECT  78.905 28.368 79.361 29.016 ;
     RECT  79.141 55.344 79.42 71.16 ;
     RECT  78.304 11.424 79.429 13.992 ;
     RECT  79.361 20.976 79.445 29.016 ;
     RECT  79.445 28.368 79.481 29.016 ;
     RECT  78.617 19.344 79.484 19.992 ;
     RECT  79.445 20.976 79.484 27.336 ;
     RECT  79.42 55.344 79.525 69 ;
     RECT  79.525 54.48 79.553 69 ;
     RECT  79.484 19.344 79.571 27.336 ;
     RECT  78.905 30.432 79.573 31.992 ;
     RECT  78.509 33.024 79.573 34.872 ;
     RECT  79.121 4.368 79.589 7.368 ;
     RECT  79.571 20.976 79.612 27.336 ;
     RECT  79.573 30.432 79.621 34.872 ;
     RECT  78.473 48.336 79.625 48.408 ;
     RECT  79.621 30.432 79.66 35.544 ;
     RECT  79.121 8.352 79.661 9.912 ;
     RECT  78.905 41.376 79.661 42.168 ;
     RECT  79.612 20.976 79.697 25.464 ;
     RECT  79.66 33.024 79.705 35.544 ;
     RECT  79.612 26.544 79.733 27.336 ;
     RECT  79.705 35.52 79.765 35.544 ;
     RECT  78.869 36.768 79.765 36.792 ;
     RECT  79.301 2.208 79.769 2.904 ;
     RECT  79.733 26.544 79.811 26.856 ;
     RECT  79.661 41.616 79.813 42.168 ;
     RECT  78.833 43.248 79.813 43.272 ;
     RECT  79.571 19.344 79.837 19.992 ;
     RECT  79.697 25.152 79.841 25.464 ;
     RECT  79.66 30.432 79.841 31.944 ;
     RECT  79.813 41.616 79.859 43.272 ;
     RECT  79.837 19.296 79.877 19.992 ;
     RECT  79.841 30.624 79.877 31.944 ;
     RECT  79.811 26.544 79.913 26.712 ;
     RECT  78.725 15.696 79.945 17.496 ;
     RECT  79.913 26.544 79.949 26.568 ;
     RECT  79.337 38.736 79.981 40.2 ;
     RECT  79.193 49.728 79.981 51.144 ;
     RECT  79.553 54.48 80.005 68.808 ;
     RECT  79.589 4.656 80.021 7.368 ;
     RECT  79.981 38.736 80.021 40.44 ;
     RECT  79.42 70.368 80.021 71.16 ;
     RECT  79.981 49.536 80.093 51.144 ;
     RECT  80.021 70.368 80.093 71.112 ;
     RECT  80.005 53.568 80.125 68.808 ;
     RECT  80.125 52.752 80.129 68.808 ;
     RECT  79.429 11.424 80.161 14.376 ;
     RECT  79.945 15.696 80.161 18.216 ;
     RECT  79.813 46.512 80.197 46.536 ;
     RECT  79.705 33.024 80.201 34.248 ;
     RECT  79.765 35.52 80.201 36.792 ;
     RECT  80.161 11.424 80.237 18.216 ;
     RECT  80.201 33.024 80.237 33.048 ;
     RECT  80.093 70.368 80.273 70.392 ;
     RECT  80.129 54.48 80.309 68.808 ;
     RECT  79.697 20.976 80.345 23.976 ;
     RECT  80.345 20.976 80.417 21.528 ;
     RECT  80.201 34.224 80.417 34.248 ;
     RECT  79.157 44.448 80.417 44.472 ;
     RECT  80.093 49.536 80.417 50.232 ;
     RECT  79.769 2.208 80.483 2.28 ;
     RECT  80.237 11.424 80.489 15.048 ;
     RECT  80.417 20.976 80.489 21.048 ;
     RECT  80.417 50.208 80.525 50.232 ;
     RECT  80.129 52.752 80.561 52.776 ;
     RECT  80.309 54.48 80.561 68.376 ;
     RECT  79.859 41.616 80.627 42.696 ;
     RECT  80.021 39.312 80.629 40.44 ;
     RECT  80.627 41.616 80.629 42.456 ;
     RECT  80.345 22.8 80.675 23.976 ;
     RECT  80.629 39.312 80.675 42.456 ;
     RECT  79.661 8.352 80.677 9.288 ;
     RECT  80.636 10.272 80.677 10.296 ;
     RECT  80.021 4.992 80.701 7.368 ;
     RECT  80.677 8.352 80.701 10.296 ;
     RECT  80.701 4.992 80.705 10.296 ;
     RECT  80.489 11.424 80.705 12.36 ;
     RECT  80.561 58.656 80.705 68.376 ;
     RECT  80.705 5.184 80.723 10.296 ;
     RECT  80.675 22.8 80.741 22.824 ;
     RECT  79.877 30.624 80.741 31.56 ;
     RECT  80.705 62.4 80.741 68.376 ;
     RECT  80.489 13.872 80.777 15.048 ;
     RECT  80.705 58.656 80.819 61.032 ;
     RECT  80.489 20.976 80.845 21 ;
     RECT  80.705 12.336 80.849 12.36 ;
     RECT  80.675 39.312 80.849 41.016 ;
     RECT  80.741 62.4 80.867 67.944 ;
     RECT  79.481 28.368 80.881 28.824 ;
     RECT  80.197 45.936 80.881 46.536 ;
     RECT  80.237 16.272 80.885 18.216 ;
     RECT  80.845 20.544 80.885 21 ;
     RECT  80.741 31.104 80.885 31.56 ;
     RECT  80.723 5.184 80.921 5.736 ;
     RECT  80.881 45.936 80.953 47.352 ;
     RECT  79.625 48.336 80.953 48.36 ;
     RECT  80.723 6.816 80.957 9.768 ;
     RECT  80.819 60.912 80.963 61.032 ;
     RECT  80.957 6.816 81.029 8.376 ;
     RECT  80.867 65.52 81.029 67.944 ;
     RECT  80.953 45.936 81.061 48.36 ;
     RECT  80.849 39.312 81.065 40.584 ;
     RECT  80.561 54.48 81.065 57.336 ;
     RECT  80.389 37.584 81.133 37.608 ;
     RECT  81.065 54.48 81.157 56.712 ;
     RECT  80.885 31.104 81.173 31.32 ;
     RECT  80.963 60.912 81.173 60.936 ;
     RECT  81.029 65.904 81.173 67.944 ;
     RECT  80.917 3.696 81.209 3.72 ;
     RECT  80.881 28.272 81.209 28.824 ;
     RECT  80.201 36.48 81.241 36.504 ;
     RECT  81.133 37.584 81.241 38.136 ;
     RECT  81.157 53.952 81.245 56.712 ;
     RECT  81.241 36.48 81.281 38.136 ;
     RECT  80.819 58.656 81.281 59.832 ;
     RECT  80.675 42.192 81.317 42.456 ;
     RECT  81.061 45.936 81.317 48.936 ;
     RECT  81.281 58.704 81.353 59.832 ;
     RECT  79.877 19.296 81.377 19.32 ;
     RECT  80.885 20.544 81.377 20.616 ;
     RECT  81.209 28.272 81.389 28.392 ;
     RECT  81.065 39.888 81.484 40.584 ;
     RECT  80.777 14.112 81.497 15.048 ;
     RECT  81.377 19.296 81.497 20.616 ;
     RECT  81.317 46.032 81.497 48.936 ;
     RECT  81.484 40.032 81.533 40.584 ;
     RECT  81.133 32.448 81.565 32.472 ;
     RECT  80.867 62.4 81.569 64.008 ;
     RECT  81.173 31.104 81.605 31.128 ;
     RECT  81.317 42.192 81.641 42.216 ;
     RECT  81.569 63.168 81.641 64.008 ;
     RECT  81.173 65.904 81.641 66.216 ;
     RECT  81.173 67.92 81.641 67.944 ;
     RECT  80.675 23.952 81.673 23.976 ;
     RECT  79.841 25.152 81.673 25.176 ;
     RECT  80.483 2.208 81.677 2.232 ;
     RECT  80.957 9.408 81.685 9.768 ;
     RECT  80.845 10.848 81.685 11.352 ;
     RECT  80.809 34.752 81.713 35.496 ;
     RECT  81.497 14.352 81.733 15.048 ;
     RECT  81.457 16.224 81.733 16.248 ;
     RECT  81.533 40.08 81.749 40.584 ;
     RECT  81.733 14.352 81.779 16.248 ;
     RECT  81.497 46.128 81.817 48.936 ;
     RECT  81.779 14.352 81.857 14.376 ;
     RECT  81.673 23.952 81.925 25.176 ;
     RECT  81.641 63.168 81.929 63.816 ;
     RECT  80.921 5.184 81.961 5.208 ;
     RECT  81.245 54.48 81.965 56.712 ;
     RECT  81.565 32.448 81.997 33.384 ;
     RECT  81.685 9.408 82.033 11.448 ;
     RECT  81.565 12.768 82.033 12.792 ;
     RECT  82.033 9.408 82.037 12.792 ;
     RECT  81.713 34.752 82.037 35.352 ;
     RECT  81.997 32.448 82.069 33.432 ;
     RECT  81.961 5.136 82.073 5.208 ;
     RECT  81.029 7.248 82.109 8.376 ;
     RECT  82.037 12 82.109 12.792 ;
     RECT  82.069 32.448 82.115 34.344 ;
     RECT  81.353 59.232 82.141 59.832 ;
     RECT  81.925 23.952 82.181 25.224 ;
     RECT  81.281 36.96 82.213 38.136 ;
     RECT  81.641 65.904 82.253 65.928 ;
     RECT  81.965 54.672 82.289 56.712 ;
     RECT  82.109 7.776 82.321 8.376 ;
     RECT  82.037 9.408 82.321 10.872 ;
     RECT  82.249 50.736 82.36 50.76 ;
     RECT  81.779 15.36 82.361 16.248 ;
     RECT  81.497 19.92 82.393 20.616 ;
     RECT  82.181 24.336 82.397 25.224 ;
     RECT  81.817 46.128 82.397 49.176 ;
     RECT  82.289 56.448 82.465 56.712 ;
     RECT  80.885 17.472 82.501 18.216 ;
     RECT  82.465 56.448 82.501 56.76 ;
     RECT  82.141 59.232 82.537 60.792 ;
     RECT  82.213 36.96 82.573 38.472 ;
     RECT  82.393 19.92 82.597 21.048 ;
     RECT  82.597 19.392 82.645 21.048 ;
     RECT  82.609 22.032 82.645 22.056 ;
     RECT  82.597 30.096 82.645 30.12 ;
     RECT  82.573 36.96 82.717 38.52 ;
     RECT  82.597 42.768 82.717 42.792 ;
     RECT  81.389 28.272 82.753 28.296 ;
     RECT  82.397 25.2 82.789 25.224 ;
     RECT  81.749 40.56 82.789 40.584 ;
     RECT  82.645 30.096 82.861 30.168 ;
     RECT  82.717 36.432 82.861 38.52 ;
     RECT  82.645 19.392 82.897 22.056 ;
     RECT  82.36 50.736 82.897 50.808 ;
     RECT  82.037 35.328 82.933 35.352 ;
     RECT  82.861 36.432 82.933 38.712 ;
     RECT  82.501 16.512 82.988 18.216 ;
     RECT  82.897 19.392 82.988 22.248 ;
     RECT  82.115 33.36 83.039 34.344 ;
     RECT  82.933 35.328 83.039 38.712 ;
     RECT  82.988 16.512 83.069 22.248 ;
     RECT  82.073 5.136 83.125 5.16 ;
     RECT  83.039 33.36 83.125 38.712 ;
     RECT  82.537 59.04 83.249 60.792 ;
     RECT  83.125 33.36 83.329 38.76 ;
     RECT  82.645 31.872 83.365 31.896 ;
     RECT  83.125 5.136 83.408 5.688 ;
     RECT  82.321 7.776 83.408 10.872 ;
     RECT  82.109 12 83.408 12.024 ;
     RECT  82.361 15.36 83.408 15.384 ;
     RECT  83.069 16.512 83.408 22.776 ;
     RECT  82.789 25.2 83.408 25.704 ;
     RECT  82.753 28.224 83.408 28.296 ;
     RECT  82.861 30.096 83.408 30.84 ;
     RECT  83.365 31.872 83.408 32.328 ;
     RECT  83.329 33.36 83.408 38.808 ;
     RECT  82.789 39.936 83.408 40.584 ;
     RECT  82.717 42.768 83.408 43.896 ;
     RECT  82.397 46.56 83.408 49.176 ;
     RECT  82.897 50.64 83.408 50.808 ;
     RECT  82.289 54.672 83.408 55.32 ;
     RECT  82.501 56.448 83.408 56.856 ;
     RECT  83.249 59.04 83.408 61.08 ;
     RECT  81.929 63.168 83.408 63.24 ;
     RECT  83.408 2.148 83.512 69.132 ;
     RECT  83.512 2.418 83.704 68.862 ;
     RECT  83.704 19.008 83.765 19.704 ;
     RECT  83.704 43.008 83.765 43.848 ;
     RECT  83.704 34.704 83.801 35.016 ;
     RECT  83.704 22.656 83.843 22.68 ;
     RECT  83.704 38.784 83.843 38.904 ;
     RECT  83.704 6.192 83.891 6.216 ;
     RECT  83.843 38.784 83.891 38.808 ;
     RECT  83.765 43.824 83.909 43.848 ;
     RECT  83.765 19.68 83.939 19.704 ;
     RECT  83.801 34.992 83.939 35.016 ;
     RECT  83.704 60.912 84.125 60.936 ;
     RECT  83.704 12.528 84.131 12.552 ;
     RECT  83.704 30.144 84.131 30.168 ;
    LAYER M5 ;
     RECT  39.12 0.016 40.296 0.037 ;
     RECT  3.6 0.016 7.368 0.179 ;
     RECT  61.392 0.016 64.392 0.611 ;
     RECT  13.008 0.016 16.2 1.763 ;
     RECT  61.488 0.611 64.392 1.763 ;
     RECT  13.104 1.763 16.008 1.811 ;
     RECT  9.168 0.016 10.824 1.859 ;
     RECT  19.92 0.016 30.024 1.859 ;
     RECT  61.584 1.763 64.392 1.859 ;
     RECT  67.728 0.016 76.68 1.859 ;
     RECT  75.6 1.859 75.816 1.907 ;
     RECT  67.728 1.859 74.568 1.955 ;
     RECT  3.6 0.179 7.272 2.005 ;
     RECT  0.912 0.016 1.608 2.137 ;
     RECT  3.6 2.005 7.368 2.137 ;
     RECT  67.728 1.955 71.112 2.137 ;
     RECT  0.912 2.137 2.52 2.151 ;
     RECT  3.6 2.137 7.92 2.151 ;
     RECT  18.6 2.137 18.72 2.151 ;
     RECT  34.8 2.137 34.92 2.151 ;
     RECT  45.6 2.137 45.72 2.151 ;
     RECT  51 2.137 51.12 2.151 ;
     RECT  56.4 2.137 56.52 2.151 ;
     RECT  78 2.137 78.12 2.151 ;
     RECT  83.4 2.137 83.52 2.151 ;
     RECT  26.544 1.859 30.024 2.243 ;
     RECT  67.2 2.137 71.112 2.243 ;
     RECT  0.912 2.151 8.112 2.245 ;
     RECT  0.912 2.245 8.52 2.291 ;
     RECT  9.552 1.859 10.44 2.291 ;
     RECT  19.92 1.859 24.456 2.291 ;
     RECT  25.488 1.859 25.512 2.291 ;
     RECT  26.544 2.243 29.712 2.291 ;
     RECT  61.584 1.859 63.912 2.291 ;
     RECT  67.2 2.243 69.384 2.291 ;
     RECT  75.792 1.907 75.816 2.291 ;
     RECT  19.92 2.291 21.288 2.339 ;
     RECT  67.2 2.291 68.136 2.773 ;
     RECT  22.512 2.291 22.824 2.867 ;
     RECT  0.912 2.291 5.16 2.915 ;
     RECT  13.104 1.811 15.912 2.915 ;
     RECT  22.704 2.867 22.824 2.963 ;
     RECT  18.6 2.151 18.912 3.301 ;
     RECT  24 2.291 24.456 3.301 ;
     RECT  39.12 0.037 40.776 3.301 ;
     RECT  1.008 2.915 5.16 3.397 ;
     RECT  22.8 2.963 22.824 3.397 ;
     RECT  24 3.301 25.128 3.397 ;
     RECT  66.48 2.773 68.136 3.397 ;
     RECT  70.512 2.243 71.112 3.397 ;
     RECT  28.656 2.291 29.712 3.443 ;
     RECT  13.2 2.915 15.912 3.491 ;
     RECT  29.184 3.443 29.712 3.493 ;
     RECT  61.632 2.291 63.912 3.539 ;
     RECT  15.696 3.491 15.912 3.587 ;
     RECT  78 2.151 78.312 3.685 ;
     RECT  43.008 3.637 43.032 3.779 ;
     RECT  61.8 3.539 63.912 3.779 ;
     RECT  29.184 3.493 30.072 3.781 ;
     RECT  70.272 3.397 71.112 3.829 ;
     RECT  72.144 1.955 74.568 3.829 ;
     RECT  36.96 3.685 36.984 3.875 ;
     RECT  1.008 3.397 5.736 3.925 ;
     RECT  7.2 2.291 8.52 3.925 ;
     RECT  13.2 3.491 14.664 3.925 ;
     RECT  18.192 3.301 18.912 3.925 ;
     RECT  56.4 2.151 56.712 3.925 ;
     RECT  39.12 3.301 41.112 4.019 ;
     RECT  20.784 2.339 21.288 4.115 ;
     RECT  39.216 4.019 41.112 4.115 ;
     RECT  70.272 3.829 74.568 4.115 ;
     RECT  56.4 3.925 56.808 4.117 ;
     RECT  13.104 3.925 14.664 4.163 ;
     RECT  39.312 4.115 41.112 4.163 ;
     RECT  27.216 2.291 27.336 4.165 ;
     RECT  18.096 3.925 18.912 4.261 ;
     RECT  17.616 4.261 18.912 4.357 ;
     RECT  70.272 4.115 73.896 4.357 ;
     RECT  1.008 3.925 8.52 4.405 ;
     RECT  9.888 2.291 10.44 4.405 ;
     RECT  34.8 2.151 35.112 4.405 ;
     RECT  77.28 3.685 78.312 4.501 ;
     RECT  15.696 3.587 15.72 4.549 ;
     RECT  22.8 3.397 25.128 4.595 ;
     RECT  70.08 4.357 73.896 4.595 ;
     RECT  1.008 4.405 10.44 4.691 ;
     RECT  66.48 3.397 68.856 4.691 ;
     RECT  56.256 4.117 56.808 4.739 ;
     RECT  17.568 4.357 18.912 4.837 ;
     RECT  33.024 2.821 33.048 4.837 ;
     RECT  61.8 3.779 63.624 4.837 ;
     RECT  32.64 4.837 33.048 4.883 ;
     RECT  40.2 4.163 41.112 4.883 ;
     RECT  66.672 4.691 68.856 4.931 ;
     RECT  13.2 4.163 14.664 4.981 ;
     RECT  15.696 4.549 16.344 4.981 ;
     RECT  61.104 4.837 63.624 5.029 ;
     RECT  61.104 5.029 64.008 5.075 ;
     RECT  13.2 4.981 16.344 5.077 ;
     RECT  17.568 4.837 19.032 5.077 ;
     RECT  44.592 3.925 44.616 5.077 ;
     RECT  13.2 5.077 19.032 5.123 ;
     RECT  61.104 5.075 62.904 5.123 ;
     RECT  23.232 4.595 25.128 5.125 ;
     RECT  51 2.151 51.312 5.125 ;
     RECT  1.2 4.691 10.44 5.171 ;
     RECT  11.952 3.397 11.976 5.171 ;
     RECT  77.28 4.501 78.696 5.171 ;
     RECT  29.184 3.781 30.456 5.173 ;
     RECT  23.232 5.125 25.752 5.221 ;
     RECT  26.928 4.165 27.336 5.221 ;
     RECT  23.232 5.221 27.336 5.267 ;
     RECT  51 5.125 51.432 5.267 ;
     RECT  54.816 5.173 54.84 5.315 ;
     RECT  63.984 5.075 64.008 5.317 ;
     RECT  15.36 5.123 19.032 5.411 ;
     RECT  29.184 5.173 30.504 5.413 ;
     RECT  32.64 4.883 32.664 5.413 ;
     RECT  34.176 4.405 35.112 5.413 ;
     RECT  37.056 5.221 37.08 5.413 ;
     RECT  26.208 5.267 27.336 5.459 ;
     RECT  43.824 5.077 44.616 5.459 ;
     RECT  77.904 5.171 78.696 5.459 ;
     RECT  20.784 4.115 21.192 5.605 ;
     RECT  51 5.267 51.312 5.653 ;
     RECT  83.4 2.151 83.712 5.653 ;
     RECT  34.032 5.413 35.112 5.699 ;
     RECT  80.448 2.245 80.472 5.701 ;
     RECT  20.784 5.605 21.624 5.747 ;
     RECT  28.368 5.413 30.504 5.747 ;
     RECT  43.824 5.459 43.848 5.747 ;
     RECT  16.896 5.411 19.032 5.749 ;
     RECT  45.6 2.151 45.912 5.749 ;
     RECT  70.08 4.595 70.296 5.749 ;
     RECT  71.328 4.595 73.896 5.749 ;
     RECT  61.8 5.123 62.904 5.795 ;
     RECT  28.368 5.747 28.392 5.891 ;
     RECT  26.208 5.459 27.24 5.939 ;
     RECT  26.208 5.939 26.952 6.035 ;
     RECT  32.064 5.413 32.664 6.035 ;
     RECT  63.984 5.317 64.44 6.035 ;
     RECT  75.504 4.933 75.528 6.037 ;
     RECT  2.304 5.171 10.44 6.133 ;
     RECT  45.024 5.749 45.912 6.133 ;
     RECT  37.056 5.413 37.656 6.179 ;
     RECT  40.2 4.883 40.776 6.181 ;
     RECT  83.136 5.653 83.712 6.181 ;
     RECT  32.064 6.035 32.088 6.227 ;
     RECT  29.4 5.747 30.504 6.229 ;
     RECT  70.08 5.749 73.896 6.229 ;
     RECT  80.448 5.701 80.52 6.229 ;
     RECT  23.232 5.267 25.128 6.277 ;
     RECT  26.208 6.035 26.808 6.277 ;
     RECT  64.416 6.035 64.44 6.323 ;
     RECT  1.2 5.171 1.224 6.419 ;
     RECT  15.36 5.411 15.384 6.419 ;
     RECT  16.896 5.749 19.416 6.419 ;
     RECT  20.928 5.747 21.624 6.419 ;
     RECT  29.4 6.229 30.6 6.469 ;
     RECT  28.32 6.037 28.344 6.563 ;
     RECT  45.024 6.133 46.248 6.611 ;
     RECT  2.304 6.133 10.968 6.613 ;
     RECT  12.144 6.517 12.168 6.613 ;
     RECT  40.2 6.181 41.592 6.709 ;
     RECT  66.864 4.931 68.856 6.757 ;
     RECT  70.08 6.229 74.52 6.757 ;
     RECT  61.8 5.795 62.856 6.805 ;
     RECT  66.864 6.757 74.52 6.805 ;
     RECT  80.448 6.229 80.712 6.805 ;
     RECT  77.904 5.459 78.312 6.851 ;
     RECT  66.672 6.805 74.52 6.899 ;
     RECT  20.928 6.419 21.432 6.901 ;
     RECT  2.304 6.613 12.168 6.949 ;
     RECT  13.2 5.123 14.088 6.949 ;
     RECT  65.664 5.893 65.688 6.997 ;
     RECT  37.632 6.179 37.656 7.237 ;
     RECT  79.968 6.805 80.712 7.379 ;
     RECT  74.496 6.899 74.52 7.381 ;
     RECT  75.504 6.037 75.72 7.381 ;
     RECT  56.256 4.739 56.712 7.429 ;
     RECT  23.232 6.277 26.808 7.475 ;
     RECT  34.176 5.699 35.112 7.475 ;
     RECT  2.304 6.949 14.088 7.477 ;
     RECT  17.232 6.419 19.416 7.477 ;
     RECT  45.264 6.611 46.248 7.619 ;
     RECT  16.752 7.477 19.416 7.715 ;
     RECT  37.008 7.237 37.656 7.717 ;
     RECT  27.888 7.333 27.912 7.765 ;
     RECT  29.4 6.469 30.792 7.765 ;
     RECT  83.136 6.181 83.88 7.765 ;
     RECT  2.304 7.477 14.568 7.859 ;
     RECT  32.16 7.429 32.184 7.957 ;
     RECT  55.872 7.429 56.712 7.957 ;
     RECT  65.232 6.997 65.688 7.957 ;
     RECT  23.232 7.475 26.28 8.099 ;
     RECT  64.176 7.957 65.688 8.099 ;
     RECT  23.328 8.099 26.28 8.147 ;
     RECT  76.944 6.853 76.968 8.147 ;
     RECT  16.896 7.715 19.416 8.149 ;
     RECT  20.496 6.901 21.432 8.149 ;
     RECT  27.888 7.765 30.792 8.197 ;
     RECT  55.248 7.957 56.712 8.197 ;
     RECT  54.72 8.197 56.712 8.243 ;
     RECT  45.264 7.619 46.056 8.339 ;
     RECT  45.264 8.339 46.008 8.341 ;
     RECT  80.448 7.379 80.712 8.387 ;
     RECT  40.2 6.709 42.216 8.389 ;
     RECT  27.648 8.197 30.792 8.437 ;
     RECT  32.16 7.957 32.52 8.437 ;
     RECT  55.872 8.243 56.712 8.437 ;
     RECT  74.496 7.381 75.72 8.485 ;
     RECT  39.504 8.389 42.216 8.531 ;
     RECT  44.976 8.341 46.008 8.579 ;
     RECT  27.648 8.437 32.52 8.629 ;
     RECT  64.416 8.099 65.688 8.723 ;
     RECT  27.648 8.629 33.096 8.771 ;
     RECT  54.72 8.243 54.744 8.773 ;
     RECT  66.672 6.899 73.176 8.869 ;
     RECT  74.496 8.485 75.768 8.869 ;
     RECT  27.648 8.771 32.712 8.963 ;
     RECT  53.856 8.773 54.744 8.963 ;
     RECT  61.68 6.805 62.856 8.963 ;
     RECT  52.656 8.725 52.68 9.011 ;
     RECT  15.744 7.285 15.768 9.061 ;
     RECT  16.896 8.149 21.432 9.061 ;
     RECT  49.008 8.965 49.032 9.107 ;
     RECT  28.944 8.963 32.712 9.203 ;
     RECT  54.72 8.963 54.744 9.203 ;
     RECT  26.256 8.147 26.28 9.205 ;
     RECT  27.648 8.963 27.96 9.205 ;
     RECT  65.664 8.723 65.688 9.251 ;
     RECT  13.2 7.859 14.568 9.301 ;
     RECT  15.744 9.061 21.432 9.301 ;
     RECT  61.68 8.963 62.664 9.347 ;
     RECT  45.264 8.579 46.008 9.349 ;
     RECT  50.592 5.653 51.312 9.349 ;
     RECT  28.944 9.203 30.456 9.395 ;
     RECT  2.304 7.859 12.168 9.397 ;
     RECT  13.2 9.301 21.432 9.397 ;
     RECT  61.8 9.347 62.664 9.539 ;
     RECT  23.328 8.147 25.128 9.541 ;
     RECT  40.2 8.531 42.216 9.541 ;
     RECT  23.184 9.541 25.128 9.637 ;
     RECT  26.256 9.205 27.96 9.637 ;
     RECT  66.672 8.869 75.768 9.637 ;
     RECT  23.184 9.637 27.96 9.683 ;
     RECT  27.936 9.683 27.96 9.731 ;
     RECT  45.264 9.349 46.68 9.779 ;
     RECT  23.184 9.683 26.904 9.827 ;
     RECT  28.944 9.395 30.072 9.925 ;
     RECT  34.512 7.475 35.112 9.925 ;
     RECT  76.8 8.245 76.824 10.069 ;
     RECT  43.488 6.853 43.512 10.213 ;
     RECT  66.624 9.637 75.768 10.213 ;
     RECT  76.8 10.069 76.968 10.213 ;
     RECT  50.592 9.349 51.432 10.261 ;
     RECT  47.904 9.349 47.928 10.307 ;
     RECT  61.8 9.539 62.376 10.307 ;
     RECT  80.688 8.387 80.712 10.307 ;
     RECT  23.184 9.827 25.992 10.403 ;
     RECT  64.368 9.445 64.392 10.405 ;
     RECT  64.368 10.405 64.92 10.547 ;
     RECT  36.096 7.717 37.656 10.595 ;
     RECT  39.12 10.549 39.144 10.597 ;
     RECT  39.024 10.597 39.144 10.691 ;
     RECT  36.096 10.595 36.84 10.739 ;
     RECT  23.184 10.403 25.32 10.787 ;
     RECT  39.024 10.691 39.048 10.787 ;
     RECT  66.624 10.213 76.968 10.787 ;
     RECT  60.144 9.301 60.168 10.789 ;
     RECT  2.304 9.397 21.432 10.883 ;
     RECT  60.144 10.789 60.456 10.883 ;
     RECT  64.368 10.547 64.392 10.883 ;
     RECT  12 10.883 21.432 10.885 ;
     RECT  43.488 10.213 43.752 10.981 ;
     RECT  45.264 9.779 46.008 11.029 ;
     RECT  32.112 9.203 32.712 11.075 ;
     RECT  12 10.885 21.576 11.123 ;
     RECT  43.488 10.981 43.848 11.123 ;
     RECT  26.736 10.885 26.76 11.125 ;
     RECT  27.984 9.925 30.072 11.125 ;
     RECT  49.008 10.837 49.032 11.125 ;
     RECT  45.024 11.029 46.008 11.171 ;
     RECT  48.912 11.125 49.032 11.171 ;
     RECT  43.488 11.123 43.752 11.219 ;
     RECT  12 11.123 21.528 11.267 ;
     RECT  26.736 11.125 30.072 11.269 ;
     RECT  66.624 10.787 76.824 11.269 ;
     RECT  26.736 11.269 30.12 11.315 ;
     RECT  34.128 9.925 35.112 11.317 ;
     RECT  36.096 10.739 36.168 11.317 ;
     RECT  28.08 11.315 30.12 11.363 ;
     RECT  48.912 11.171 48.936 11.363 ;
     RECT  26.736 11.315 26.76 11.459 ;
     RECT  28.08 11.363 28.344 11.459 ;
     RECT  50.592 10.261 51.912 11.459 ;
     RECT  81.696 9.397 81.72 11.459 ;
     RECT  45.264 11.171 46.008 11.509 ;
     RECT  53.52 11.365 53.544 11.509 ;
     RECT  43.488 11.219 43.704 11.555 ;
     RECT  50.592 11.459 51.312 11.555 ;
     RECT  2.304 10.883 10.92 11.845 ;
     RECT  12 11.267 19.608 11.845 ;
     RECT  61.8 10.307 62.112 11.845 ;
     RECT  2.304 11.845 19.608 11.939 ;
     RECT  43.68 11.555 43.704 11.939 ;
     RECT  60.432 10.883 60.456 11.941 ;
     RECT  66.288 11.269 76.824 11.941 ;
     RECT  48.432 11.653 48.456 11.987 ;
     RECT  55.872 8.437 57.288 11.987 ;
     RECT  2.304 11.939 19.56 12.035 ;
     RECT  20.976 11.267 21.528 12.035 ;
     RECT  23.184 10.787 25.128 12.037 ;
     RECT  34.128 11.317 36.168 12.037 ;
     RECT  61.68 11.845 62.112 12.037 ;
     RECT  40.2 9.541 42.36 12.131 ;
     RECT  12 12.035 19.56 12.179 ;
     RECT  32.688 11.075 32.712 12.227 ;
     RECT  61.68 12.037 62.472 12.275 ;
     RECT  21.12 12.035 21.528 12.277 ;
     RECT  12 12.179 17.544 12.419 ;
     RECT  29.4 11.363 30.12 12.419 ;
     RECT  12 12.419 17.016 12.467 ;
     RECT  66.24 11.941 76.824 12.467 ;
     RECT  78 6.851 78.312 12.469 ;
     RECT  82.704 7.765 83.88 12.517 ;
     RECT  12 12.467 16.488 12.563 ;
     RECT  28.08 11.459 28.104 12.563 ;
     RECT  60.432 11.941 60.696 12.563 ;
     RECT  51 11.555 51.312 12.565 ;
     RECT  12 12.563 14.808 12.611 ;
     RECT  29.4 12.419 29.712 12.757 ;
     RECT  34.128 12.037 37.08 12.757 ;
     RECT  50.736 12.565 51.312 12.851 ;
     RECT  33.072 12.757 33.096 12.899 ;
     RECT  34.128 12.757 37.176 12.899 ;
     RECT  34.128 12.899 37.08 12.947 ;
     RECT  23.184 12.037 25.464 12.995 ;
     RECT  34.128 12.947 36.216 13.043 ;
     RECT  2.304 12.035 10.92 13.045 ;
     RECT  12 12.611 13.512 13.045 ;
     RECT  78 12.469 78.648 13.045 ;
     RECT  80.016 12.517 80.04 13.045 ;
     RECT  31.488 11.749 31.512 13.091 ;
     RECT  40.2 12.131 41.64 13.331 ;
     RECT  14.544 12.611 14.808 13.621 ;
     RECT  18.6 12.179 19.56 13.621 ;
     RECT  45.264 11.509 46.68 13.667 ;
     RECT  23.184 12.995 24.744 13.715 ;
     RECT  61.68 12.275 62.112 13.715 ;
     RECT  78 13.045 80.04 13.715 ;
     RECT  23.184 13.715 24.648 13.811 ;
     RECT  60.672 12.563 60.696 14.197 ;
     RECT  66.24 12.467 76.632 14.197 ;
     RECT  2.304 13.045 13.512 14.291 ;
     RECT  56.304 11.987 57.288 14.291 ;
     RECT  14.544 13.621 15.192 14.341 ;
     RECT  82.704 12.517 84.12 14.341 ;
     RECT  18.6 13.621 19.992 14.437 ;
     RECT  21.12 12.277 21.72 14.437 ;
     RECT  29.28 12.757 29.712 14.437 ;
     RECT  61.8 13.715 62.112 14.773 ;
     RECT  29.28 14.437 29.832 14.819 ;
     RECT  52.56 11.509 53.544 14.867 ;
     RECT  40.2 13.331 40.776 14.965 ;
     RECT  34.128 13.043 36.168 15.013 ;
     RECT  39.792 14.965 40.776 15.013 ;
     RECT  56.4 14.291 57.288 15.059 ;
     RECT  60.336 14.197 60.696 15.059 ;
     RECT  29.28 14.819 29.712 15.155 ;
     RECT  34.128 15.013 36.216 15.251 ;
     RECT  39.792 15.013 41.016 15.251 ;
     RECT  64.416 14.341 64.44 15.301 ;
     RECT  65.616 14.197 76.632 15.301 ;
     RECT  14.544 14.341 15.288 15.349 ;
     RECT  51 12.851 51.312 15.349 ;
     RECT  81.744 14.341 84.12 15.395 ;
     RECT  2.304 14.291 10.92 15.443 ;
     RECT  64.416 15.301 76.632 15.443 ;
     RECT  53.472 14.867 53.544 15.491 ;
     RECT  39.792 15.251 40.776 15.781 ;
     RECT  28.32 15.781 28.344 15.923 ;
     RECT  39.696 15.781 40.776 15.923 ;
     RECT  49.008 15.781 49.032 15.923 ;
     RECT  45.264 13.667 45.912 15.973 ;
     RECT  79.44 13.715 80.04 16.019 ;
     RECT  2.4 15.443 10.92 16.067 ;
     RECT  64.512 15.443 76.632 16.259 ;
     RECT  80.016 16.019 80.04 16.261 ;
     RECT  56.4 15.059 56.712 16.357 ;
     RECT  12 14.291 13.512 16.405 ;
     RECT  82.704 15.395 84.12 16.501 ;
     RECT  18.6 14.437 21.72 16.595 ;
     RECT  61.8 14.773 62.712 16.595 ;
     RECT  66.24 16.259 76.632 16.595 ;
     RECT  27.312 16.549 27.336 16.691 ;
     RECT  53.472 15.491 53.496 16.693 ;
     RECT  18.6 16.595 20.088 16.741 ;
     RECT  45.264 15.973 46.728 16.835 ;
     RECT  2.4 16.067 10.44 17.029 ;
     RECT  11.568 16.405 13.512 17.029 ;
     RECT  45.6 16.835 46.728 17.075 ;
     RECT  60.672 15.059 60.696 17.077 ;
     RECT  21.6 16.595 21.72 17.123 ;
     RECT  52.944 16.693 53.496 17.315 ;
     RECT  78 13.715 78.312 17.317 ;
     RECT  64.512 16.259 65.064 17.411 ;
     RECT  56.4 16.357 56.808 17.461 ;
     RECT  2.4 17.029 13.512 17.557 ;
     RECT  14.544 15.349 15.816 17.557 ;
     RECT  52.944 17.315 52.968 17.651 ;
     RECT  23.568 13.811 24.648 17.699 ;
     RECT  34.128 15.251 36.168 17.699 ;
     RECT  18.288 16.741 20.088 17.747 ;
     RECT  21.6 17.123 21.624 17.797 ;
     RECT  21.12 17.797 21.624 17.843 ;
     RECT  59.856 17.077 60.696 17.843 ;
     RECT  66.288 16.595 76.632 18.131 ;
     RECT  2.4 17.557 15.816 18.275 ;
     RECT  18.288 17.747 19.56 18.323 ;
     RECT  36.144 17.699 36.168 18.371 ;
     RECT  56.4 17.461 56.856 18.467 ;
     RECT  66.288 18.131 76.152 18.467 ;
     RECT  2.4 18.275 10.392 18.515 ;
     RECT  11.568 18.275 15.816 18.563 ;
     RECT  45.6 17.075 45.912 18.805 ;
     RECT  77.616 17.317 78.312 18.805 ;
     RECT  21.12 17.843 21.144 18.851 ;
     RECT  45.6 18.805 46.056 18.947 ;
     RECT  18.336 18.323 19.56 19.237 ;
     RECT  80.016 16.261 80.52 19.285 ;
     RECT  77.616 18.805 78.408 19.333 ;
     RECT  22.8 19.189 22.824 19.379 ;
     RECT  80.016 19.285 81.432 19.909 ;
     RECT  82.608 16.501 84.12 19.909 ;
     RECT  18.336 19.237 19.992 19.955 ;
     RECT  77.616 19.333 78.648 19.957 ;
     RECT  80.016 19.909 84.12 19.957 ;
     RECT  77.616 19.957 84.12 20.003 ;
     RECT  14.544 18.563 15.816 20.293 ;
     RECT  66.624 18.467 76.152 20.293 ;
     RECT  77.616 20.003 80.52 20.341 ;
     RECT  11.568 18.563 13.512 20.579 ;
     RECT  77.232 20.341 80.52 20.579 ;
     RECT  82.08 20.003 84.12 20.579 ;
     RECT  45.6 18.947 45.912 20.725 ;
     RECT  79.776 20.579 80.52 20.965 ;
     RECT  45.12 20.725 45.912 21.011 ;
     RECT  66.624 20.293 76.248 21.109 ;
     RECT  77.232 20.579 78.648 21.109 ;
     RECT  66.624 21.109 78.648 21.155 ;
     RECT  40.2 15.923 40.776 21.205 ;
     RECT  11.568 20.579 11.88 21.347 ;
     RECT  18.6 19.955 19.992 21.493 ;
     RECT  40.2 21.205 41.016 21.587 ;
     RECT  40.2 21.587 40.776 21.685 ;
     RECT  18.6 21.493 20.52 21.925 ;
     RECT  34.128 17.699 35.112 21.971 ;
     RECT  12.912 20.579 13.512 21.973 ;
     RECT  14.544 20.293 15.912 21.973 ;
     RECT  18.6 21.925 20.568 22.115 ;
     RECT  18.6 22.115 20.52 22.165 ;
     RECT  60.672 17.843 60.696 22.213 ;
     RECT  61.8 16.595 62.112 22.213 ;
     RECT  66.624 21.155 78.552 22.259 ;
     RECT  43.824 20.485 43.848 22.307 ;
     RECT  18.48 22.165 20.52 22.403 ;
     RECT  59.424 19.333 59.448 22.499 ;
     RECT  71.712 22.259 78.552 22.741 ;
     RECT  12.912 21.973 15.912 22.835 ;
     RECT  79.776 20.965 80.664 22.883 ;
     RECT  66.624 22.259 70.296 23.317 ;
     RECT  60.672 22.213 63.096 23.459 ;
     RECT  18.6 22.403 20.52 23.939 ;
     RECT  80.016 22.883 80.664 23.987 ;
     RECT  66.432 23.317 70.296 24.131 ;
     RECT  11.568 21.347 11.592 24.325 ;
     RECT  18.6 23.939 19.656 24.469 ;
     RECT  71.712 22.741 78.648 24.469 ;
     RECT  80.016 23.987 80.52 24.469 ;
     RECT  10.944 24.325 11.592 24.563 ;
     RECT  2.4 18.515 9.864 24.853 ;
     RECT  11.568 24.563 11.592 24.997 ;
     RECT  12.912 22.835 15.72 24.997 ;
     RECT  18.432 24.469 19.656 24.997 ;
     RECT  18.432 24.997 19.8 25.139 ;
     RECT  54.24 23.845 54.264 25.139 ;
     RECT  50.208 15.349 51.312 25.141 ;
     RECT  11.568 24.997 15.72 25.235 ;
     RECT  40.08 21.685 40.776 25.283 ;
     RECT  66.432 24.131 70.008 25.381 ;
     RECT  29.4 15.155 29.712 25.909 ;
     RECT  2.4 24.853 10.44 26.101 ;
     RECT  11.568 25.235 13.512 26.101 ;
     RECT  45.6 21.011 45.912 26.197 ;
     RECT  66.24 25.381 70.008 26.389 ;
     RECT  2.4 26.101 13.512 26.531 ;
     RECT  29.28 25.909 29.712 26.627 ;
     RECT  14.544 25.235 15.72 26.675 ;
     RECT  65.472 26.389 70.008 26.675 ;
     RECT  65.472 26.675 65.496 26.725 ;
     RECT  18.6 25.139 19.8 26.771 ;
     RECT  45.456 26.197 45.912 26.819 ;
     RECT  33.312 25.093 33.336 27.347 ;
     RECT  2.4 26.531 11.592 27.395 ;
     RECT  60.672 23.459 62.112 27.395 ;
     RECT  66.624 26.675 70.008 27.395 ;
     RECT  71.712 24.469 80.52 27.395 ;
     RECT  61.536 27.395 62.112 27.971 ;
     RECT  58.176 26.917 58.2 28.067 ;
     RECT  2.4 27.395 9.864 28.163 ;
     RECT  54.432 27.205 54.456 28.451 ;
     RECT  65.232 26.725 65.496 28.451 ;
     RECT  11.568 27.395 11.592 28.453 ;
     RECT  12.912 26.531 13.512 28.453 ;
     RECT  71.904 27.395 80.52 28.453 ;
     RECT  4.176 28.163 9.864 28.547 ;
     RECT  18.6 26.771 19.656 29.075 ;
     RECT  48.432 27.781 48.456 29.171 ;
     RECT  11.568 28.453 13.512 29.221 ;
     RECT  14.544 26.675 15.576 29.221 ;
     RECT  71.424 28.453 80.52 29.699 ;
     RECT  37.056 29.365 37.08 29.795 ;
     RECT  11.568 29.221 15.576 29.987 ;
     RECT  82.704 20.579 84.12 30.085 ;
     RECT  82.608 30.085 84.12 30.179 ;
     RECT  4.368 28.547 9.864 30.181 ;
     RECT  67.2 27.395 69.912 30.803 ;
     RECT  11.568 29.987 13.512 30.853 ;
     RECT  29.4 26.627 29.712 30.853 ;
     RECT  4.368 30.181 10.248 30.899 ;
     RECT  11.424 30.853 13.512 30.995 ;
     RECT  43.872 30.133 43.896 30.997 ;
     RECT  43.344 30.997 43.896 31.043 ;
     RECT  12.912 30.995 13.512 31.093 ;
     RECT  14.544 29.987 15.576 31.093 ;
     RECT  71.904 29.699 80.52 31.379 ;
     RECT  45.6 26.819 45.912 31.381 ;
     RECT  50.16 25.141 51.312 31.427 ;
     RECT  12.912 31.093 15.576 31.859 ;
     RECT  4.368 30.899 9.864 31.955 ;
     RECT  18.6 29.075 19.56 32.003 ;
     RECT  29.232 30.853 29.712 32.147 ;
     RECT  63.648 31.285 63.672 32.195 ;
     RECT  45.36 31.381 45.912 32.243 ;
     RECT  67.2 30.803 69.096 32.437 ;
     RECT  70.704 31.669 70.728 32.437 ;
     RECT  82.608 30.179 83.928 32.437 ;
     RECT  11.424 30.995 11.592 32.725 ;
     RECT  67.2 32.437 70.728 32.963 ;
     RECT  5.136 31.955 9.864 33.013 ;
     RECT  18.6 32.003 19.464 33.107 ;
     RECT  11.232 32.725 11.592 33.157 ;
     RECT  50.88 31.427 51.312 33.251 ;
     RECT  67.2 32.963 70.008 33.251 ;
     RECT  10.848 33.157 11.592 33.491 ;
     RECT  71.904 31.379 76.152 33.589 ;
     RECT  2.4 28.163 3 33.683 ;
     RECT  55.104 32.869 55.128 33.683 ;
     RECT  61.68 27.971 62.112 33.923 ;
     RECT  71.904 33.589 76.2 33.925 ;
     RECT  77.328 31.379 80.52 33.925 ;
     RECT  11.232 33.491 11.592 34.069 ;
     RECT  12.912 31.859 13.512 34.069 ;
     RECT  67.2 33.251 69.096 34.115 ;
     RECT  45.6 32.243 45.912 34.165 ;
     RECT  43.344 31.043 43.368 34.355 ;
     RECT  82.08 32.437 83.928 34.355 ;
     RECT  18.6 33.107 19.272 34.597 ;
     RECT  61.8 33.923 62.112 34.741 ;
     RECT  18.6 34.597 19.32 34.883 ;
     RECT  21.936 26.197 21.96 34.883 ;
     RECT  61.8 34.741 62.712 34.883 ;
     RECT  49.584 33.349 49.608 34.931 ;
     RECT  11.232 34.069 13.512 35.027 ;
     RECT  82.608 34.355 83.928 35.027 ;
     RECT  17.28 32.437 17.304 35.219 ;
     RECT  65.232 28.451 65.256 35.269 ;
     RECT  53.28 31.621 53.304 35.363 ;
     RECT  18.6 34.883 19.272 35.507 ;
     RECT  40.2 25.283 40.776 35.699 ;
     RECT  64.8 35.269 65.256 35.795 ;
     RECT  64.8 35.795 65.112 35.845 ;
     RECT  4.272 33.013 9.864 35.939 ;
     RECT  12.912 35.027 13.512 35.939 ;
     RECT  61.8 34.883 62.664 35.939 ;
     RECT  67.2 34.115 68.808 35.939 ;
     RECT  18.6 35.507 18.912 35.941 ;
     RECT  51 33.251 51.312 36.373 ;
     RECT  29.4 32.147 29.712 36.421 ;
     RECT  37.248 35.845 37.272 36.515 ;
     RECT  12.96 35.939 13.512 36.613 ;
     RECT  14.544 31.859 15.576 36.613 ;
     RECT  12.96 36.613 15.576 36.755 ;
     RECT  17.616 35.941 18.912 36.755 ;
     RECT  64.368 35.845 65.112 36.803 ;
     RECT  11.232 35.027 11.592 36.997 ;
     RECT  12.96 36.755 13.512 36.997 ;
     RECT  11.232 36.997 13.512 37.043 ;
     RECT  51 36.373 52.296 37.043 ;
     RECT  67.2 35.939 67.512 37.093 ;
     RECT  68.784 35.939 68.808 37.093 ;
     RECT  29.4 36.421 30.168 37.283 ;
     RECT  24 17.699 24.648 37.477 ;
     RECT  56.4 18.467 56.712 37.573 ;
     RECT  67.2 37.093 68.808 37.619 ;
     RECT  65.088 36.803 65.112 37.621 ;
     RECT  34.8 21.971 35.112 37.669 ;
     RECT  68.64 37.619 68.808 37.715 ;
     RECT  27.312 36.373 27.336 37.859 ;
     RECT  18.6 36.755 18.912 38.005 ;
     RECT  18.6 38.005 19.368 38.149 ;
     RECT  61.8 35.939 62.112 38.197 ;
     RECT  56.112 37.573 56.712 38.243 ;
     RECT  65.088 37.621 66.072 38.435 ;
     RECT  11.568 37.043 13.512 38.437 ;
     RECT  14.544 36.755 15.576 38.437 ;
     RECT  45.6 34.165 46.728 38.677 ;
     RECT  51 37.043 51.312 38.677 ;
     RECT  44.688 38.677 46.728 38.723 ;
     RECT  51 38.677 51.672 38.819 ;
     RECT  82.608 35.027 83.88 38.819 ;
     RECT  82.608 38.819 83.832 38.915 ;
     RECT  71.904 33.925 80.52 39.011 ;
     RECT  11.568 38.437 15.576 39.061 ;
     RECT  11.424 39.061 15.576 39.203 ;
     RECT  54.384 38.197 54.408 39.251 ;
     RECT  72.384 39.011 80.52 39.301 ;
     RECT  34.704 37.669 35.112 39.491 ;
     RECT  18.6 38.149 19.416 39.539 ;
     RECT  43.296 39.397 43.32 39.733 ;
     RECT  24 37.477 25.608 39.829 ;
     RECT  24 39.829 25.704 39.875 ;
     RECT  60.096 39.013 60.12 39.877 ;
     RECT  72.384 39.301 80.616 39.877 ;
     RECT  29.4 37.283 29.832 39.923 ;
     RECT  72.384 39.877 81.432 39.923 ;
     RECT  72.6 39.923 81.432 40.211 ;
     RECT  42.672 39.733 43.32 40.357 ;
     RECT  42.48 40.357 43.32 40.403 ;
     RECT  60.096 39.877 60.168 40.451 ;
     RECT  4.416 35.939 9.864 40.693 ;
     RECT  60.096 40.451 60.12 40.739 ;
     RECT  4.416 40.693 10.392 40.981 ;
     RECT  11.424 39.203 11.592 40.981 ;
     RECT  12.96 39.203 15.576 40.981 ;
     RECT  72.6 40.211 80.664 40.981 ;
     RECT  4.128 40.981 10.392 41.173 ;
     RECT  11.424 40.981 15.576 41.173 ;
     RECT  68.64 37.715 68.664 41.557 ;
     RECT  4.128 41.173 15.576 41.651 ;
     RECT  71.904 40.981 80.664 41.651 ;
     RECT  37.248 38.677 37.368 41.699 ;
     RECT  25.68 39.875 25.704 41.749 ;
     RECT  5.136 41.651 15.576 41.843 ;
     RECT  61.536 38.197 62.112 41.939 ;
     RECT  37.248 41.699 37.272 41.941 ;
     RECT  56.4 38.243 56.712 41.989 ;
     RECT  40.2 35.699 40.512 42.037 ;
     RECT  37.056 41.941 37.272 42.083 ;
     RECT  5.136 41.843 10.392 42.323 ;
     RECT  25.68 41.749 26.136 42.371 ;
     RECT  11.568 41.843 15.576 42.659 ;
     RECT  71.904 41.651 80.616 42.707 ;
     RECT  18.6 39.539 19.368 42.709 ;
     RECT  56.208 41.989 56.712 42.709 ;
     RECT  68.64 41.557 69.24 42.709 ;
     RECT  82.608 38.915 83.712 42.803 ;
     RECT  4.128 41.651 4.152 42.995 ;
     RECT  29.4 39.923 29.712 42.997 ;
     RECT  18.6 42.709 19.992 43.139 ;
     RECT  55.584 42.709 56.712 43.331 ;
     RECT  28.176 38.149 28.2 43.333 ;
     RECT  29.184 42.997 29.712 43.333 ;
     RECT  28.176 43.333 29.712 43.379 ;
     RECT  37.248 42.083 37.272 43.379 ;
     RECT  33.024 41.941 33.048 43.525 ;
     RECT  26.112 42.371 26.136 43.669 ;
     RECT  25.776 43.669 26.136 43.715 ;
     RECT  42.48 40.403 42.504 43.765 ;
     RECT  71.904 42.707 80.52 43.765 ;
     RECT  42.24 43.765 42.552 43.907 ;
     RECT  33.024 43.525 33.672 43.955 ;
     RECT  39.936 42.037 40.512 43.957 ;
     RECT  42.48 43.907 42.552 44.147 ;
     RECT  71.856 43.765 80.52 44.147 ;
     RECT  56.4 43.331 56.712 44.341 ;
     RECT  65.088 38.435 65.112 44.341 ;
     RECT  28.464 43.379 29.712 44.531 ;
     RECT  25.776 43.715 25.8 44.771 ;
     RECT  19.968 43.139 19.992 44.915 ;
     RECT  29.184 44.531 29.712 44.915 ;
     RECT  64.608 44.341 65.112 45.011 ;
     RECT  68.544 42.709 69.24 45.059 ;
     RECT  39.936 43.957 41.304 45.107 ;
     RECT  70.656 43.093 70.68 45.155 ;
     RECT  55.824 44.341 56.712 45.203 ;
     RECT  11.568 42.659 11.592 45.493 ;
     RECT  17.28 45.397 17.304 45.587 ;
     RECT  49.344 44.101 49.368 45.587 ;
     RECT  65.088 45.011 65.112 45.587 ;
     RECT  39.984 45.107 41.304 45.635 ;
     RECT  40.2 45.635 41.304 45.683 ;
     RECT  58.08 40.693 58.104 45.925 ;
     RECT  56.064 45.203 56.712 45.971 ;
     RECT  82.752 42.803 83.712 46.741 ;
     RECT  2.4 33.683 2.712 47.125 ;
     RECT  82.08 46.741 83.712 47.507 ;
     RECT  56.4 45.971 56.712 47.557 ;
     RECT  51 38.819 51.312 47.653 ;
     RECT  58.08 45.925 58.44 47.653 ;
     RECT  56.304 47.557 56.712 47.699 ;
     RECT  58.08 47.653 58.728 47.699 ;
     RECT  5.136 42.323 9.864 47.749 ;
     RECT  44.688 38.723 45.912 48.083 ;
     RECT  21.648 46.645 21.672 48.419 ;
     RECT  82.608 47.507 83.712 48.419 ;
     RECT  45.6 48.083 45.912 48.469 ;
     RECT  50.496 47.653 51.312 48.805 ;
     RECT  44.448 48.373 44.472 48.851 ;
     RECT  20.496 48.373 20.52 48.901 ;
     RECT  82.752 48.419 83.712 48.947 ;
     RECT  61.8 41.939 62.112 48.949 ;
     RECT  58.416 47.699 58.728 48.997 ;
     RECT  2.4 47.125 3.48 49.043 ;
     RECT  20.496 48.901 21.144 49.043 ;
     RECT  37.536 48.997 37.56 49.139 ;
     RECT  45.6 48.469 46.632 49.235 ;
     RECT  20.496 49.043 21.048 49.667 ;
     RECT  40.2 45.683 40.512 49.717 ;
     RECT  58.416 48.997 59.448 49.811 ;
     RECT  69.216 45.059 69.24 49.909 ;
     RECT  11.424 45.493 11.592 50.051 ;
     RECT  47.664 49.333 47.688 50.195 ;
     RECT  83.088 48.947 83.712 50.675 ;
     RECT  18.6 43.139 18.912 50.725 ;
     RECT  61.8 48.949 62.808 50.771 ;
     RECT  22.704 48.373 22.728 51.347 ;
     RECT  18.432 50.725 18.912 51.637 ;
     RECT  29.4 44.915 29.712 51.733 ;
     RECT  18.432 51.637 19.416 51.779 ;
     RECT  18.432 51.779 18.912 51.827 ;
     RECT  67.2 37.619 67.512 51.829 ;
     RECT  69.216 49.909 70.056 51.829 ;
     RECT  40.2 49.717 41.256 51.875 ;
     RECT  42.48 44.147 42.504 51.923 ;
     RECT  50.496 48.805 52.008 51.923 ;
     RECT  34.8 39.491 35.112 51.925 ;
     RECT  21.024 49.667 21.048 52.211 ;
     RECT  67.2 51.829 70.056 52.211 ;
     RECT  21.12 52.213 21.144 52.547 ;
     RECT  29.4 51.733 30.6 52.693 ;
     RECT  67.2 52.211 69.24 52.741 ;
     RECT  11.52 50.051 11.592 52.883 ;
     RECT  29.184 52.693 30.6 52.931 ;
     RECT  12.96 42.659 15.576 53.075 ;
     RECT  66.72 52.741 69.24 53.267 ;
     RECT  17.232 50.533 17.256 53.603 ;
     RECT  58.416 49.811 58.92 53.603 ;
     RECT  24 39.875 24.648 53.939 ;
     RECT  61.8 50.771 62.112 53.941 ;
     RECT  71.904 44.147 80.52 53.941 ;
     RECT  61.8 53.941 62.712 54.037 ;
     RECT  42.144 53.701 42.168 54.085 ;
     RECT  43.488 53.797 43.512 54.085 ;
     RECT  33.648 43.955 33.672 54.179 ;
     RECT  50.496 51.923 51.312 54.179 ;
     RECT  71.904 53.941 81.192 54.515 ;
     RECT  42.144 54.085 43.512 54.563 ;
     RECT  12.96 53.075 13.512 54.565 ;
     RECT  51 54.179 51.312 54.565 ;
     RECT  34.8 51.925 35.256 54.661 ;
     RECT  45.6 49.235 45.912 54.661 ;
     RECT  38.688 54.565 38.712 54.707 ;
     RECT  61.8 54.037 63.72 54.803 ;
     RECT  43.008 54.563 43.512 54.899 ;
     RECT  34.704 54.661 35.256 54.947 ;
     RECT  2.4 49.043 2.712 55.237 ;
     RECT  11.568 52.883 11.592 55.237 ;
     RECT  67.2 53.267 69.24 55.237 ;
     RECT  51 54.565 52.008 55.477 ;
     RECT  12.768 54.565 13.512 55.571 ;
     RECT  43.008 54.899 43.032 55.669 ;
     RECT  2.4 55.237 3 55.715 ;
     RECT  42.72 55.669 43.032 55.715 ;
     RECT  18.6 51.827 18.912 55.813 ;
     RECT  63.696 54.803 63.72 55.813 ;
     RECT  50.88 55.477 52.008 55.907 ;
     RECT  70.464 54.565 70.488 55.909 ;
     RECT  70.224 55.909 70.488 55.955 ;
     RECT  29.4 52.931 30.6 56.197 ;
     RECT  45.456 54.661 45.912 56.291 ;
     RECT  61.8 54.803 62.112 56.341 ;
     RECT  11.52 55.237 11.592 56.485 ;
     RECT  54 55.813 54.024 56.531 ;
     RECT  63.696 55.813 63.864 56.531 ;
     RECT  42.72 55.715 42.744 56.533 ;
     RECT  41.856 56.533 42.744 56.627 ;
     RECT  24 53.939 24.312 56.869 ;
     RECT  66.816 55.237 69.24 56.869 ;
     RECT  22.512 53.797 22.536 56.915 ;
     RECT  4.704 47.749 9.864 56.917 ;
     RECT  70.224 55.955 70.248 56.965 ;
     RECT  61.8 56.341 62.328 57.013 ;
     RECT  63.696 56.531 63.72 57.013 ;
     RECT  10.944 56.485 11.592 57.059 ;
     RECT  71.904 54.515 80.568 57.059 ;
     RECT  10.944 57.059 11.544 57.107 ;
     RECT  28.656 56.197 30.6 57.203 ;
     RECT  11.52 57.107 11.544 57.299 ;
     RECT  13.2 55.571 13.512 57.301 ;
     RECT  14.544 53.075 15.576 57.301 ;
     RECT  50.88 55.907 51.312 57.445 ;
     RECT  70.224 56.965 70.584 57.539 ;
     RECT  24 56.869 25.272 57.827 ;
     RECT  66.768 56.869 69.24 57.923 ;
     RECT  58.416 53.603 58.44 57.973 ;
     RECT  22.32 57.877 22.344 58.115 ;
     RECT  4.608 56.917 9.864 58.117 ;
     RECT  50.88 57.445 51.912 58.163 ;
     RECT  80.496 57.059 80.568 58.163 ;
     RECT  70.56 57.539 70.584 58.501 ;
     RECT  50.88 58.163 51.312 58.645 ;
     RECT  54.048 57.541 54.072 58.645 ;
     RECT  80.544 58.163 80.568 58.645 ;
     RECT  57.936 57.973 58.44 58.691 ;
     RECT  61.8 57.013 63.72 58.691 ;
     RECT  29.4 57.203 30.6 58.693 ;
     RECT  12.192 58.453 12.216 58.739 ;
     RECT  13.2 57.301 15.576 58.739 ;
     RECT  58.416 58.691 58.44 58.739 ;
     RECT  67.2 57.923 69.24 58.787 ;
     RECT  29.4 58.693 30.792 58.883 ;
     RECT  3.984 58.117 9.864 59.027 ;
     RECT  9.552 59.027 9.864 59.029 ;
     RECT  71.904 57.059 79.176 59.029 ;
     RECT  83.4 50.675 83.712 59.029 ;
     RECT  67.2 58.787 67.512 59.077 ;
     RECT  80.544 58.645 80.616 59.077 ;
     RECT  9.552 59.029 9.912 59.171 ;
     RECT  3.984 59.027 8.52 59.315 ;
     RECT  50.112 58.645 51.312 59.315 ;
     RECT  71.76 59.029 79.176 59.315 ;
     RECT  63.504 58.691 63.72 59.413 ;
     RECT  53.328 58.645 54.072 59.459 ;
     RECT  3.984 59.315 8.232 59.603 ;
     RECT  80.544 59.077 80.856 59.749 ;
     RECT  61.8 58.691 62.112 59.797 ;
     RECT  70.272 58.501 70.584 59.797 ;
     RECT  4.608 59.603 8.232 59.891 ;
     RECT  59.232 59.173 59.256 59.893 ;
     RECT  58.704 59.893 59.256 59.939 ;
     RECT  22.32 59.365 22.344 59.987 ;
     RECT  38.784 59.845 38.808 59.987 ;
     RECT  44.064 58.645 44.088 59.987 ;
     RECT  29.4 58.883 30.696 59.989 ;
     RECT  61.632 59.797 62.112 59.989 ;
     RECT  63.504 59.413 64.056 59.989 ;
     RECT  65.232 58.021 65.256 60.035 ;
     RECT  13.2 58.739 13.512 60.085 ;
     RECT  29.4 59.989 30.744 60.275 ;
     RECT  14.544 58.739 15.576 60.277 ;
     RECT  31.824 60.229 31.848 60.371 ;
     RECT  51 59.315 51.312 60.373 ;
     RECT  67.104 59.077 67.512 60.373 ;
     RECT  34.704 54.947 35.112 60.517 ;
     RECT  9.696 59.171 9.912 60.563 ;
     RECT  70.272 59.797 70.728 60.563 ;
     RECT  18.6 55.813 19.32 60.611 ;
     RECT  34.704 60.517 35.208 60.707 ;
     RECT  79.824 59.749 80.856 60.803 ;
     RECT  83.088 59.029 83.712 60.803 ;
     RECT  12.432 60.085 13.512 60.899 ;
     RECT  71.76 59.315 78.744 60.901 ;
     RECT  80.592 60.803 80.856 60.901 ;
     RECT  24 57.827 24.312 60.997 ;
     RECT  41.856 56.627 42.456 60.997 ;
     RECT  4.608 59.891 8.112 61.043 ;
     RECT  41.856 60.997 43.368 61.043 ;
     RECT  80.592 60.901 80.952 61.043 ;
     RECT  83.28 60.803 83.712 61.091 ;
     RECT  22.752 60.997 22.776 61.139 ;
     RECT  67.104 60.373 68.184 61.139 ;
     RECT  32.448 60.949 32.472 61.283 ;
     RECT  71.76 60.901 78.936 61.333 ;
     RECT  9.888 60.563 9.912 61.525 ;
     RECT  4.8 61.043 8.112 61.619 ;
     RECT  24 60.997 25.032 61.619 ;
     RECT  51 60.373 51.624 61.619 ;
     RECT  67.104 61.139 67.8 61.621 ;
     RECT  80.592 61.043 80.856 61.715 ;
     RECT  29.4 60.275 30.696 61.909 ;
     RECT  34.8 60.707 35.208 62.051 ;
     RECT  61.632 59.989 64.056 62.053 ;
     RECT  71.664 61.333 78.936 62.053 ;
     RECT  66.72 61.621 67.8 62.101 ;
     RECT  69.216 58.787 69.24 62.101 ;
     RECT  29.04 61.909 30.696 62.149 ;
     RECT  56.4 47.699 56.712 62.149 ;
     RECT  58.704 59.939 58.728 62.149 ;
     RECT  9.168 61.525 9.912 62.195 ;
     RECT  48.096 60.949 48.12 62.195 ;
     RECT  54.048 59.459 54.072 62.195 ;
     RECT  58.704 62.149 59.208 62.195 ;
     RECT  42.432 61.043 43.368 62.293 ;
     RECT  42.192 62.293 43.368 62.339 ;
     RECT  43.344 62.339 43.368 62.435 ;
     RECT  61.584 62.053 64.056 62.435 ;
     RECT  66.72 62.101 69.24 62.435 ;
     RECT  71.664 62.053 79.512 62.531 ;
     RECT  45.6 56.291 45.912 62.581 ;
     RECT  67.2 62.435 69.24 62.581 ;
     RECT  70.272 60.563 70.584 62.581 ;
     RECT  9.888 62.195 9.912 62.629 ;
     RECT  28.512 62.149 30.696 62.677 ;
     RECT  61.584 62.435 62.112 62.677 ;
     RECT  45.6 62.581 46.68 62.723 ;
     RECT  9.888 62.629 10.68 62.771 ;
     RECT  11.952 62.629 11.976 62.771 ;
     RECT  14.544 60.277 16.344 63.059 ;
     RECT  28.512 62.677 30.792 63.299 ;
     RECT  67.2 62.581 70.584 63.349 ;
     RECT  71.664 62.531 79.08 63.349 ;
     RECT  28.512 63.299 30.696 63.491 ;
     RECT  14.64 63.059 16.344 63.541 ;
     RECT  24 61.619 24.312 63.781 ;
     RECT  5.184 61.619 8.112 63.875 ;
     RECT  14.64 63.541 16.392 63.875 ;
     RECT  5.808 63.875 8.112 64.019 ;
     RECT  28.752 63.491 30.696 64.355 ;
     RECT  24 63.781 24.456 64.357 ;
     RECT  67.2 63.349 79.08 64.451 ;
     RECT  34.8 62.051 35.112 64.501 ;
     RECT  24 64.357 25.416 64.547 ;
     RECT  29.184 64.355 30.696 64.547 ;
     RECT  63.264 62.435 64.056 64.595 ;
     RECT  42.192 62.339 42.216 64.597 ;
     RECT  67.2 64.451 78.696 64.597 ;
     RECT  34.8 64.501 35.208 64.691 ;
     RECT  41.664 64.597 42.216 64.789 ;
     RECT  41.664 64.789 42.696 64.835 ;
     RECT  61.392 62.677 62.112 64.885 ;
     RECT  48.144 62.629 48.168 64.933 ;
     RECT  6.96 64.019 8.112 64.979 ;
     RECT  21.552 64.021 21.576 64.979 ;
     RECT  48.144 64.933 48.312 64.979 ;
     RECT  67.104 64.597 78.696 64.979 ;
     RECT  59.184 62.195 59.208 65.027 ;
     RECT  80.832 61.715 80.856 65.075 ;
     RECT  29.184 64.547 30.168 65.171 ;
     RECT  49.536 64.357 49.56 65.411 ;
     RECT  29.184 65.171 29.712 65.605 ;
     RECT  18.6 60.611 18.912 65.653 ;
     RECT  59.28 65.509 59.832 65.699 ;
     RECT  31.152 64.837 31.176 65.701 ;
     RECT  32.208 63.493 32.232 65.701 ;
     RECT  31.152 65.701 32.232 65.747 ;
     RECT  14.64 63.875 14.664 65.939 ;
     RECT  67.2 64.979 78.696 65.941 ;
     RECT  61.296 64.885 62.112 65.987 ;
     RECT  5.808 64.019 5.832 66.085 ;
     RECT  7.296 64.979 8.112 66.085 ;
     RECT  48.288 64.979 48.312 66.085 ;
     RECT  64.032 64.595 64.056 66.179 ;
     RECT  29.088 65.605 29.712 66.373 ;
     RECT  67.2 65.941 78.792 66.419 ;
     RECT  59.808 65.699 59.832 66.467 ;
     RECT  11.76 63.781 11.784 66.515 ;
     RECT  29.088 66.373 30.6 66.611 ;
     RECT  16.368 63.875 16.392 66.755 ;
     RECT  32.112 65.747 32.232 66.901 ;
     RECT  5.328 66.085 8.112 67.235 ;
     RECT  4.32 63.973 4.344 67.283 ;
     RECT  5.328 67.235 6.216 67.283 ;
     RECT  47.76 66.085 48.312 67.283 ;
     RECT  10.656 62.771 10.68 67.331 ;
     RECT  25.392 64.547 25.416 67.331 ;
     RECT  27.36 66.325 27.384 67.331 ;
     RECT  29.088 66.611 29.712 67.523 ;
     RECT  55.584 62.149 56.712 67.859 ;
     RECT  32.112 66.901 33.096 67.955 ;
     RECT  67.2 66.419 78.696 68.341 ;
     RECT  6.192 67.283 6.216 68.389 ;
     RECT  3.84 67.765 3.864 68.435 ;
     RECT  18.24 65.653 18.912 68.483 ;
     RECT  31.728 68.341 31.752 68.485 ;
     RECT  42.672 64.835 42.696 68.531 ;
     RECT  7.8 67.235 8.112 68.533 ;
     RECT  33.072 67.955 33.096 68.723 ;
     RECT  47.712 67.765 47.736 68.819 ;
     RECT  6 68.389 6.216 68.821 ;
     RECT  29.184 67.523 29.712 68.917 ;
     RECT  30.912 68.485 31.752 68.917 ;
     RECT  5.808 68.821 6.216 68.965 ;
     RECT  7.8 68.533 8.424 68.965 ;
     RECT  29.184 68.917 31.752 68.965 ;
     RECT  29.184 68.965 31.848 69.013 ;
     RECT  5.808 68.965 8.712 69.061 ;
     RECT  2.4 55.715 2.712 69.129 ;
     RECT  13.2 60.899 13.512 69.129 ;
     RECT  18.6 68.483 18.912 69.129 ;
     RECT  24 64.547 24.312 69.129 ;
     RECT  34.8 64.691 35.112 69.129 ;
     RECT  40.2 51.875 40.512 69.129 ;
     RECT  45.6 62.723 45.912 69.129 ;
     RECT  51 61.619 51.312 69.129 ;
     RECT  56.4 67.859 56.712 69.129 ;
     RECT  61.8 65.987 62.112 69.129 ;
     RECT  83.4 61.091 83.712 69.129 ;
     RECT  2.4 69.129 2.52 69.143 ;
     RECT  13.2 69.129 13.32 69.143 ;
     RECT  18.6 69.129 18.72 69.143 ;
     RECT  24 69.129 24.12 69.143 ;
     RECT  34.8 69.129 34.92 69.143 ;
     RECT  40.2 69.129 40.32 69.143 ;
     RECT  45.6 69.129 45.72 69.143 ;
     RECT  51 69.129 51.12 69.143 ;
     RECT  56.4 69.129 56.52 69.143 ;
     RECT  61.8 69.129 61.92 69.143 ;
     RECT  67.2 68.341 79.464 69.143 ;
     RECT  83.4 69.129 83.52 69.143 ;
     RECT  29.04 69.013 31.848 69.541 ;
     RECT  5.808 69.061 8.808 70.117 ;
     RECT  5.712 70.117 8.808 71.248 ;
     RECT  28.848 69.541 31.848 71.248 ;
     RECT  67.248 69.143 79.464 71.248 ;
     RECT  9.168 1.859 9.552 2.137 ;
     RECT  24.456 1.859 25.488 2.291 ;
     RECT  25.512 1.859 26.544 2.291 ;
     RECT  74.568 1.859 75.6 1.907 ;
     RECT  74.568 1.907 75.792 2.291 ;
     RECT  71.112 1.955 72.144 3.829 ;
     RECT  2.52 2.137 3.6 2.151 ;
     RECT  7.92 2.137 9.552 2.151 ;
     RECT  18.72 2.137 19.92 2.151 ;
     RECT  8.112 2.151 9.552 2.245 ;
     RECT  18.912 2.151 19.92 2.339 ;
     RECT  29.712 2.243 30.024 3.493 ;
     RECT  69.384 2.243 70.512 2.291 ;
     RECT  8.52 2.245 9.552 2.291 ;
     RECT  5.16 2.291 7.2 3.397 ;
     RECT  8.52 2.291 9.888 4.405 ;
     RECT  21.288 2.291 22.512 2.867 ;
     RECT  22.824 2.291 24 3.397 ;
     RECT  24.456 2.291 25.128 3.301 ;
     RECT  27.336 2.291 28.656 3.443 ;
     RECT  68.136 2.291 70.512 3.397 ;
     RECT  21.288 2.867 22.704 2.963 ;
     RECT  13.104 2.915 13.2 3.397 ;
     RECT  21.288 2.963 22.8 4.115 ;
     RECT  5.736 3.397 7.2 3.925 ;
     RECT  10.44 3.397 11.952 5.171 ;
     RECT  11.976 3.397 13.2 3.925 ;
     RECT  68.856 3.397 70.272 4.357 ;
     RECT  14.664 3.491 15.696 4.981 ;
     RECT  61.632 3.539 61.8 4.837 ;
     RECT  15.72 3.587 15.912 4.549 ;
     RECT  63.624 3.779 63.912 5.029 ;
     RECT  11.976 3.925 13.104 4.163 ;
     RECT  44.616 3.925 45.6 5.459 ;
     RECT  21.192 4.115 22.8 4.595 ;
     RECT  11.976 4.163 13.2 5.171 ;
     RECT  68.856 4.357 70.08 6.757 ;
     RECT  33.048 4.405 34.176 4.883 ;
     RECT  16.344 4.549 17.568 5.077 ;
     RECT  21.192 4.595 21.624 5.605 ;
     RECT  70.296 4.595 71.328 5.749 ;
     RECT  66.48 4.691 66.672 4.931 ;
     RECT  32.664 4.883 34.176 5.413 ;
     RECT  40.776 4.883 41.112 6.181 ;
     RECT  66.48 4.931 66.864 5.893 ;
     RECT  62.904 5.075 63.984 5.795 ;
     RECT  14.088 5.123 15.36 6.419 ;
     RECT  25.752 5.125 26.928 5.221 ;
     RECT  1.224 5.171 2.304 6.419 ;
     RECT  10.44 5.171 13.2 6.133 ;
     RECT  54.84 5.173 56.256 5.315 ;
     RECT  25.128 5.267 26.208 6.277 ;
     RECT  15.384 5.411 16.896 6.419 ;
     RECT  27.336 5.413 28.368 5.459 ;
     RECT  32.664 5.413 34.032 5.699 ;
     RECT  27.24 5.459 28.368 5.891 ;
     RECT  43.848 5.459 45.6 5.747 ;
     RECT  32.664 5.699 34.176 6.035 ;
     RECT  20.784 5.747 20.928 5.749 ;
     RECT  28.392 5.747 29.4 5.891 ;
     RECT  45.024 5.747 45.6 5.749 ;
     RECT  19.416 5.749 20.928 6.901 ;
     RECT  62.856 5.795 63.984 6.035 ;
     RECT  27.24 5.891 29.4 5.939 ;
     RECT  64.44 5.893 65.664 6.323 ;
     RECT  65.688 5.893 66.864 6.805 ;
     RECT  26.952 5.939 29.4 6.035 ;
     RECT  26.808 6.035 29.4 6.037 ;
     RECT  32.088 6.035 32.184 6.227 ;
     RECT  26.808 6.037 28.32 6.563 ;
     RECT  28.344 6.037 29.4 6.563 ;
     RECT  10.968 6.133 13.2 6.517 ;
     RECT  37.056 6.179 37.632 7.237 ;
     RECT  32.064 6.227 32.184 6.229 ;
     RECT  30.6 6.229 32.184 6.469 ;
     RECT  74.52 6.229 75.504 7.381 ;
     RECT  65.232 6.323 65.664 6.997 ;
     RECT  14.088 6.419 17.232 7.285 ;
     RECT  30.792 6.469 32.184 7.429 ;
     RECT  10.968 6.517 12.144 6.613 ;
     RECT  12.168 6.517 13.2 6.949 ;
     RECT  26.808 6.563 29.4 7.333 ;
     RECT  65.688 6.805 66.672 9.251 ;
     RECT  77.904 6.851 78 6.853 ;
     RECT  42.216 6.853 43.488 9.541 ;
     RECT  75.72 6.853 76.944 8.147 ;
     RECT  76.968 6.853 78 8.147 ;
     RECT  73.176 6.899 74.496 8.869 ;
     RECT  19.416 6.901 20.496 8.149 ;
     RECT  14.088 7.285 15.744 7.477 ;
     RECT  15.768 7.285 17.232 7.477 ;
     RECT  26.808 7.333 27.888 7.475 ;
     RECT  27.912 7.333 29.4 7.765 ;
     RECT  30.792 7.429 32.16 8.437 ;
     RECT  26.28 7.475 27.888 8.197 ;
     RECT  34.176 7.475 34.512 8.629 ;
     RECT  14.568 7.477 15.744 9.301 ;
     RECT  15.768 7.477 16.752 7.715 ;
     RECT  15.768 7.715 16.896 9.061 ;
     RECT  35.112 7.717 36.096 11.317 ;
     RECT  12.168 7.859 13.2 9.397 ;
     RECT  62.856 7.957 64.176 8.099 ;
     RECT  23.232 8.099 23.328 9.541 ;
     RECT  62.856 8.099 64.416 8.723 ;
     RECT  25.128 8.147 26.256 9.637 ;
     RECT  75.72 8.147 78 8.245 ;
     RECT  26.28 8.197 27.648 9.205 ;
     RECT  54.744 8.243 55.872 9.203 ;
     RECT  75.72 8.245 76.8 8.485 ;
     RECT  76.824 8.245 78 10.069 ;
     RECT  46.008 8.339 46.056 9.349 ;
     RECT  43.512 8.341 44.976 8.579 ;
     RECT  75.768 8.485 76.8 10.213 ;
     RECT  33.096 8.629 34.512 8.771 ;
     RECT  62.856 8.723 65.664 8.963 ;
     RECT  51.312 8.725 52.656 9.011 ;
     RECT  32.712 8.771 34.512 9.925 ;
     RECT  52.68 8.773 53.856 8.963 ;
     RECT  27.96 8.963 28.944 9.731 ;
     RECT  64.368 8.963 65.664 9.251 ;
     RECT  51.312 9.011 51.912 9.349 ;
     RECT  64.368 9.251 64.92 9.445 ;
     RECT  66.624 9.251 66.672 9.637 ;
     RECT  60.168 9.301 61.68 9.347 ;
     RECT  60.168 9.347 61.8 10.789 ;
     RECT  46.68 9.349 47.904 9.779 ;
     RECT  51.432 9.349 51.912 10.261 ;
     RECT  80.712 9.397 81.696 10.307 ;
     RECT  81.72 9.397 82.704 11.459 ;
     RECT  64.392 9.445 64.92 10.405 ;
     RECT  42.36 9.541 43.488 11.555 ;
     RECT  26.904 9.683 27.936 9.731 ;
     RECT  26.904 9.731 28.944 9.827 ;
     RECT  25.992 9.827 28.944 9.925 ;
     RECT  25.992 9.925 27.984 10.403 ;
     RECT  32.712 9.925 34.128 12.227 ;
     RECT  76.968 10.069 78 10.787 ;
     RECT  43.752 10.213 45.264 10.981 ;
     RECT  25.32 10.403 27.984 10.787 ;
     RECT  37.656 10.549 39.12 10.595 ;
     RECT  39.144 10.549 40.2 10.691 ;
     RECT  36.84 10.595 37.08 10.739 ;
     RECT  39.024 10.595 39.12 10.597 ;
     RECT  39.048 10.691 40.2 10.787 ;
     RECT  36.168 10.739 37.08 12.037 ;
     RECT  25.128 10.787 27.984 10.885 ;
     RECT  76.824 10.787 78 12.467 ;
     RECT  60.456 10.789 61.8 11.845 ;
     RECT  10.92 10.883 12 11.845 ;
     RECT  25.128 10.885 26.736 11.459 ;
     RECT  26.76 10.885 27.984 11.125 ;
     RECT  43.848 10.981 45.264 11.029 ;
     RECT  43.848 11.029 45.024 11.123 ;
     RECT  32.112 11.075 32.688 11.749 ;
     RECT  21.528 11.123 21.576 12.277 ;
     RECT  43.752 11.123 45.024 11.171 ;
     RECT  43.752 11.171 45.264 11.219 ;
     RECT  19.608 11.267 20.976 11.939 ;
     RECT  26.76 11.315 28.08 11.459 ;
     RECT  28.344 11.363 29.4 11.459 ;
     RECT  25.128 11.459 25.464 12.037 ;
     RECT  28.104 11.459 29.4 12.563 ;
     RECT  51.312 11.459 51.912 11.509 ;
     RECT  51.312 11.509 52.56 14.867 ;
     RECT  42.36 11.555 43.68 11.939 ;
     RECT  50.736 11.555 51 12.565 ;
     RECT  30.12 11.749 31.488 12.419 ;
     RECT  31.512 11.749 32.688 12.227 ;
     RECT  60.456 11.845 61.68 11.941 ;
     RECT  19.56 11.939 20.976 12.035 ;
     RECT  60.696 11.941 61.68 13.715 ;
     RECT  10.92 12.035 12 13.045 ;
     RECT  17.544 12.179 18.6 12.419 ;
     RECT  33.072 12.227 34.128 12.757 ;
     RECT  21.72 12.277 23.184 13.811 ;
     RECT  76.632 12.467 78 17.317 ;
     RECT  78.648 12.517 80.016 13.045 ;
     RECT  14.808 12.563 15.192 13.621 ;
     RECT  29.28 12.563 29.4 12.757 ;
     RECT  13.512 12.611 14.544 17.557 ;
     RECT  33.096 12.757 34.128 12.899 ;
     RECT  19.992 13.621 21.12 14.437 ;
     RECT  60.696 13.715 61.8 22.213 ;
     RECT  78.312 13.715 79.44 16.019 ;
     RECT  10.92 14.291 12 16.067 ;
     RECT  64.44 14.341 65.616 15.301 ;
     RECT  56.712 15.059 56.808 16.357 ;
     RECT  29.28 15.155 29.4 15.781 ;
     RECT  82.608 15.395 82.704 16.501 ;
     RECT  28.344 15.781 29.4 15.923 ;
     RECT  49.032 15.781 50.208 15.923 ;
     RECT  10.44 16.067 12 16.405 ;
     RECT  65.064 16.259 66.24 16.595 ;
     RECT  10.44 16.405 11.568 17.029 ;
     RECT  20.088 16.595 21.6 17.747 ;
     RECT  65.064 16.595 66.288 17.411 ;
     RECT  76.632 17.317 77.616 18.131 ;
     RECT  23.568 17.699 24 19.189 ;
     RECT  35.112 17.699 36.144 18.371 ;
     RECT  19.56 17.747 21.6 17.797 ;
     RECT  19.56 17.797 21.12 18.851 ;
     RECT  59.856 17.843 60.672 19.333 ;
     RECT  76.152 18.131 77.616 20.293 ;
     RECT  10.392 18.275 11.568 18.515 ;
     RECT  13.512 18.563 14.544 21.973 ;
     RECT  19.56 18.851 19.992 19.237 ;
     RECT  22.824 19.189 24 19.379 ;
     RECT  81.432 19.285 82.608 19.909 ;
     RECT  59.448 19.333 60.672 22.499 ;
     RECT  78.648 19.333 80.016 19.957 ;
     RECT  80.52 20.003 82.08 20.579 ;
     RECT  76.248 20.293 77.616 20.341 ;
     RECT  76.248 20.341 77.232 21.109 ;
     RECT  11.88 20.579 12.912 21.347 ;
     RECT  78.648 20.579 79.776 21.155 ;
     RECT  80.52 20.579 80.664 20.965 ;
     RECT  43.848 20.725 45.12 21.011 ;
     RECT  78.552 21.155 79.776 22.741 ;
     RECT  11.592 21.347 12.912 24.997 ;
     RECT  70.296 22.259 71.712 24.131 ;
     RECT  78.648 22.741 79.776 22.883 ;
     RECT  78.648 22.883 80.016 24.469 ;
     RECT  19.656 23.939 19.8 24.997 ;
     RECT  9.864 24.325 10.944 24.563 ;
     RECT  9.864 24.563 11.568 24.853 ;
     RECT  10.44 24.853 11.568 26.101 ;
     RECT  33.336 25.093 34.8 27.347 ;
     RECT  13.512 25.235 14.544 29.221 ;
     RECT  11.592 26.531 12.912 28.453 ;
     RECT  65.496 26.675 66.624 27.395 ;
     RECT  56.712 26.917 58.176 28.067 ;
     RECT  69.912 27.395 70.008 28.453 ;
     RECT  71.712 27.395 71.904 28.453 ;
     RECT  3 28.163 4.176 28.547 ;
     RECT  69.912 28.453 71.424 29.699 ;
     RECT  3 28.547 4.368 31.955 ;
     RECT  13.512 29.987 14.544 31.093 ;
     RECT  10.248 30.181 11.568 30.853 ;
     RECT  10.248 30.853 11.424 30.899 ;
     RECT  11.592 30.995 12.912 34.069 ;
     RECT  76.152 31.379 77.328 33.589 ;
     RECT  70.728 31.669 71.904 32.963 ;
     RECT  13.512 31.859 14.544 36.613 ;
     RECT  3 31.955 5.136 33.013 ;
     RECT  17.304 32.437 18.6 35.219 ;
     RECT  9.864 32.725 11.232 33.157 ;
     RECT  55.128 32.869 56.4 33.683 ;
     RECT  3 33.013 4.272 33.683 ;
     RECT  19.272 33.107 19.32 34.597 ;
     RECT  9.864 33.157 10.848 33.491 ;
     RECT  50.88 33.251 51 33.349 ;
     RECT  49.608 33.349 51 34.931 ;
     RECT  9.864 33.491 11.232 37.043 ;
     RECT  76.2 33.589 77.328 33.925 ;
     RECT  11.592 35.027 12.912 35.939 ;
     RECT  17.616 35.219 18.6 35.941 ;
     RECT  11.592 35.939 12.96 36.997 ;
     RECT  67.512 35.939 68.784 37.093 ;
     RECT  13.512 36.755 14.544 38.437 ;
     RECT  67.512 37.619 68.64 42.709 ;
     RECT  66.072 37.621 67.2 38.435 ;
     RECT  28.2 38.149 29.4 42.997 ;
     RECT  60.12 39.013 61.536 39.877 ;
     RECT  11.592 39.203 12.96 40.981 ;
     RECT  43.32 39.397 44.688 40.403 ;
     RECT  24.648 39.875 25.68 42.371 ;
     RECT  60.168 39.877 61.536 40.451 ;
     RECT  81.432 39.877 82.608 40.211 ;
     RECT  72.384 39.923 72.6 40.981 ;
     RECT  60.12 40.451 61.536 40.739 ;
     RECT  10.392 40.693 11.424 41.173 ;
     RECT  56.712 40.693 58.08 47.699 ;
     RECT  2.712 40.981 4.128 42.995 ;
     RECT  4.152 41.651 5.136 42.995 ;
     RECT  10.392 41.843 11.568 42.323 ;
     RECT  24.648 42.371 26.112 43.669 ;
     RECT  11.592 42.659 12.96 54.565 ;
     RECT  67.512 42.709 68.544 45.059 ;
     RECT  28.2 42.997 29.184 43.333 ;
     RECT  69.24 43.093 70.656 45.155 ;
     RECT  70.68 43.093 71.904 43.765 ;
     RECT  18.912 43.139 19.968 44.915 ;
     RECT  55.824 43.331 56.4 44.341 ;
     RECT  33.672 43.525 34.8 54.179 ;
     RECT  24.648 43.669 25.776 44.771 ;
     RECT  70.68 43.765 71.856 44.147 ;
     RECT  42.24 43.907 42.48 43.957 ;
     RECT  41.304 43.957 42.48 45.683 ;
     RECT  70.68 44.147 71.904 45.155 ;
     RECT  17.304 45.397 18.6 45.587 ;
     RECT  3.48 47.749 4.704 49.043 ;
     RECT  44.688 48.083 45.6 48.373 ;
     RECT  20.52 48.373 21.648 48.419 ;
     RECT  21.672 48.373 22.704 48.419 ;
     RECT  22.728 48.373 24 51.347 ;
     RECT  44.472 48.373 45.6 48.851 ;
     RECT  20.52 48.419 21.144 48.901 ;
     RECT  41.256 49.717 42.48 51.875 ;
     RECT  17.256 50.533 18.6 50.725 ;
     RECT  17.256 50.725 18.432 51.827 ;
     RECT  17.256 51.827 18.6 53.603 ;
     RECT  13.512 53.075 14.544 57.301 ;
     RECT  22.536 53.797 24 56.915 ;
     RECT  42.168 53.797 43.488 54.085 ;
     RECT  34.704 54.179 34.8 54.661 ;
     RECT  50.88 54.179 51 55.477 ;
     RECT  42.72 54.563 43.008 55.669 ;
     RECT  11.592 54.565 12.768 55.571 ;
     RECT  38.712 54.565 40.2 54.707 ;
     RECT  69.24 54.565 70.464 55.909 ;
     RECT  70.488 54.565 71.904 55.955 ;
     RECT  69.24 55.909 70.224 57.539 ;
     RECT  70.248 55.955 71.904 56.965 ;
     RECT  62.328 56.341 63.696 57.013 ;
     RECT  9.864 56.485 10.944 57.107 ;
     RECT  63.72 56.531 63.864 58.021 ;
     RECT  40.512 56.533 41.856 61.043 ;
     RECT  70.584 56.965 71.904 59.029 ;
     RECT  79.176 57.059 80.496 58.163 ;
     RECT  69.24 57.539 70.56 58.501 ;
     RECT  67.104 57.923 67.2 59.077 ;
     RECT  56.712 57.973 57.936 58.691 ;
     RECT  63.72 58.021 65.232 59.413 ;
     RECT  22.32 58.115 22.344 59.365 ;
     RECT  2.712 58.117 3.984 59.603 ;
     RECT  79.176 58.163 80.544 59.315 ;
     RECT  12.216 58.453 13.2 58.739 ;
     RECT  69.24 58.501 70.272 62.581 ;
     RECT  44.088 58.645 45.6 59.987 ;
     RECT  62.112 58.691 63.504 59.989 ;
     RECT  12.432 58.739 13.2 60.085 ;
     RECT  13.512 58.739 14.544 63.059 ;
     RECT  30.696 58.883 30.792 59.989 ;
     RECT  8.52 59.027 9.552 59.171 ;
     RECT  70.584 59.029 71.76 59.797 ;
     RECT  8.52 59.171 9.696 59.315 ;
     RECT  8.232 59.315 9.696 59.891 ;
     RECT  78.744 59.315 80.544 59.749 ;
     RECT  64.056 59.413 65.232 60.035 ;
     RECT  78.744 59.749 79.824 60.803 ;
     RECT  70.728 59.797 71.76 60.563 ;
     RECT  38.808 59.845 40.2 59.987 ;
     RECT  30.744 59.989 30.792 60.229 ;
     RECT  30.744 60.229 31.824 60.275 ;
     RECT  30.696 60.275 31.824 60.371 ;
     RECT  68.184 60.373 69.216 61.139 ;
     RECT  9.696 60.563 9.888 61.525 ;
     RECT  70.584 60.563 71.76 61.333 ;
     RECT  78.744 60.803 80.592 60.901 ;
     RECT  78.936 60.901 80.592 61.715 ;
     RECT  22.776 60.997 24 61.139 ;
     RECT  42.192 61.043 42.432 62.293 ;
     RECT  67.8 61.139 69.216 62.101 ;
     RECT  70.584 61.333 71.664 63.349 ;
     RECT  8.112 61.525 9.168 62.195 ;
     RECT  78.936 61.715 80.832 62.053 ;
     RECT  79.512 62.053 80.832 62.531 ;
     RECT  54.072 62.149 55.584 62.195 ;
     RECT  48.096 62.195 48.12 62.581 ;
     RECT  42.216 62.339 43.344 62.435 ;
     RECT  62.112 62.435 63.264 64.595 ;
     RECT  46.68 62.581 48.12 62.629 ;
     RECT  10.68 62.629 11.952 62.771 ;
     RECT  11.976 62.629 13.2 62.771 ;
     RECT  46.68 62.629 48.144 62.723 ;
     RECT  10.68 62.771 13.2 63.781 ;
     RECT  13.512 63.059 14.64 65.939 ;
     RECT  30.696 63.299 30.792 63.493 ;
     RECT  30.696 63.493 32.208 64.547 ;
     RECT  10.68 63.781 11.76 66.515 ;
     RECT  11.784 63.781 13.2 66.515 ;
     RECT  5.184 63.875 5.808 63.973 ;
     RECT  4.344 63.973 5.808 66.085 ;
     RECT  5.832 64.019 6.96 64.979 ;
     RECT  29.088 64.355 29.184 65.605 ;
     RECT  48.168 64.357 49.536 64.933 ;
     RECT  49.56 64.357 51 65.411 ;
     RECT  78.696 64.451 78.792 65.941 ;
     RECT  24.312 64.547 25.392 67.331 ;
     RECT  30.168 64.547 32.208 64.837 ;
     RECT  40.512 64.597 41.664 64.835 ;
     RECT  30.168 64.837 31.152 65.171 ;
     RECT  31.176 64.837 32.208 65.701 ;
     RECT  48.312 64.933 49.536 65.411 ;
     RECT  5.832 64.979 7.296 66.085 ;
     RECT  48.144 64.979 48.288 66.085 ;
     RECT  29.712 65.171 31.152 65.747 ;
     RECT  59.832 65.509 61.296 65.987 ;
     RECT  29.712 65.747 32.112 66.373 ;
     RECT  4.344 66.085 5.328 67.283 ;
     RECT  30.6 66.373 32.112 66.611 ;
     RECT  6 67.283 6.192 68.389 ;
     RECT  29.088 67.523 29.184 69.013 ;
     RECT  2.712 67.765 3.84 68.435 ;
     RECT  32.112 67.955 33.072 68.341 ;
     RECT  31.752 68.341 33.072 68.723 ;
     RECT  29.712 68.485 30.912 68.917 ;
     RECT  31.752 68.723 31.848 68.965 ;
  END
END ot_hgi_qdq_fr
END LIBRARY
